VERSION 5.8 ;
BUSBITCHARS "[]" ;
DIVIDERCHAR "/" ;
UNITS
    DATABASE MICRONS 1000 ;
END UNITS

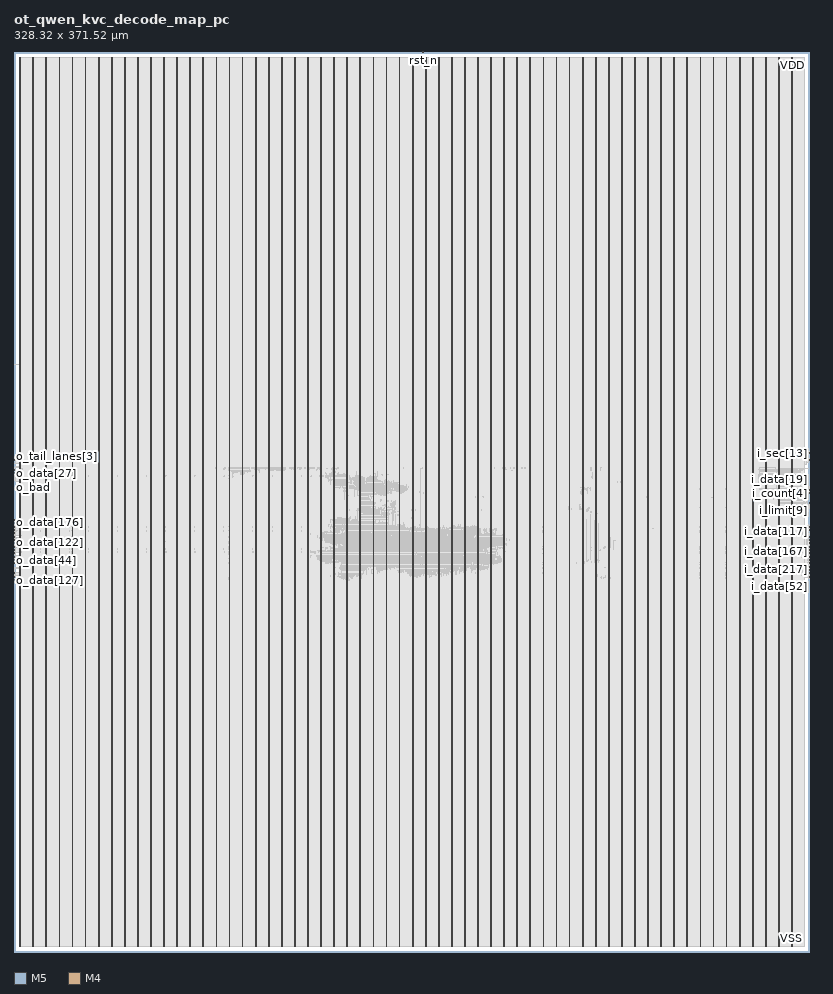
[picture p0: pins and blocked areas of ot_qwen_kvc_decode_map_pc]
MACRO ot_qwen_kvc_decode_map_pc
  FOREIGN ot_qwen_kvc_decode_map_pc 0 0 ;
  CLASS BLOCK ;
  SIZE 328.32 BY 371.52 ;
  PIN clk
    DIRECTION INPUT ;
    USE SIGNAL ;
    PORT
      LAYER M5 ;
        RECT  168.72 371.436 168.744 371.52 ;
    END
  END clk
  PIN fault
    DIRECTION OUTPUT ;
    USE SIGNAL ;
    PORT
      LAYER M5 ;
        RECT  168.816 371.436 168.84 371.52 ;
    END
  END fault
  PIN i_active
    DIRECTION INPUT ;
    USE SIGNAL ;
    PORT
      LAYER M4 ;
        RECT  328.236 188.88 328.32 188.904 ;
    END
  END i_active
  PIN i_count[0]
    DIRECTION INPUT ;
    USE SIGNAL ;
    PORT
      LAYER M4 ;
        RECT  328.236 188.976 328.32 189 ;
    END
  END i_count[0]
  PIN i_count[10]
    DIRECTION INPUT ;
    USE SIGNAL ;
    PORT
      LAYER M4 ;
        RECT  328.236 189.936 328.32 189.96 ;
    END
  END i_count[10]
  PIN i_count[1]
    DIRECTION INPUT ;
    USE SIGNAL ;
    PORT
      LAYER M4 ;
        RECT  328.236 189.072 328.32 189.096 ;
    END
  END i_count[1]
  PIN i_count[2]
    DIRECTION INPUT ;
    USE SIGNAL ;
    PORT
      LAYER M4 ;
        RECT  328.236 189.168 328.32 189.192 ;
    END
  END i_count[2]
  PIN i_count[3]
    DIRECTION INPUT ;
    USE SIGNAL ;
    PORT
      LAYER M4 ;
        RECT  328.236 189.264 328.32 189.288 ;
    END
  END i_count[3]
  PIN i_count[4]
    DIRECTION INPUT ;
    USE SIGNAL ;
    PORT
      LAYER M4 ;
        RECT  328.236 189.36 328.32 189.384 ;
    END
  END i_count[4]
  PIN i_count[5]
    DIRECTION INPUT ;
    USE SIGNAL ;
    PORT
      LAYER M4 ;
        RECT  328.236 189.456 328.32 189.48 ;
    END
  END i_count[5]
  PIN i_count[6]
    DIRECTION INPUT ;
    USE SIGNAL ;
    PORT
      LAYER M4 ;
        RECT  328.236 189.552 328.32 189.576 ;
    END
  END i_count[6]
  PIN i_count[7]
    DIRECTION INPUT ;
    USE SIGNAL ;
    PORT
      LAYER M4 ;
        RECT  328.236 189.648 328.32 189.672 ;
    END
  END i_count[7]
  PIN i_count[8]
    DIRECTION INPUT ;
    USE SIGNAL ;
    PORT
      LAYER M4 ;
        RECT  328.236 189.744 328.32 189.768 ;
    END
  END i_count[8]
  PIN i_count[9]
    DIRECTION INPUT ;
    USE SIGNAL ;
    PORT
      LAYER M4 ;
        RECT  328.236 189.84 328.32 189.864 ;
    END
  END i_count[9]
  PIN i_cr
    DIRECTION OUTPUT ;
    USE SIGNAL ;
    PORT
      LAYER M5 ;
        RECT  168.912 371.436 168.936 371.52 ;
    END
  END i_cr
  PIN i_data[0]
    DIRECTION INPUT ;
    USE SIGNAL ;
    PORT
      LAYER M4 ;
        RECT  328.236 190.032 328.32 190.056 ;
    END
  END i_data[0]
  PIN i_data[100]
    DIRECTION INPUT ;
    USE SIGNAL ;
    PORT
      LAYER M4 ;
        RECT  328.236 171.216 328.32 171.24 ;
    END
  END i_data[100]
  PIN i_data[101]
    DIRECTION INPUT ;
    USE SIGNAL ;
    PORT
      LAYER M4 ;
        RECT  328.236 171.312 328.32 171.336 ;
    END
  END i_data[101]
  PIN i_data[102]
    DIRECTION INPUT ;
    USE SIGNAL ;
    PORT
      LAYER M4 ;
        RECT  328.236 171.408 328.32 171.432 ;
    END
  END i_data[102]
  PIN i_data[103]
    DIRECTION INPUT ;
    USE SIGNAL ;
    PORT
      LAYER M4 ;
        RECT  328.236 171.504 328.32 171.528 ;
    END
  END i_data[103]
  PIN i_data[104]
    DIRECTION INPUT ;
    USE SIGNAL ;
    PORT
      LAYER M4 ;
        RECT  328.236 171.6 328.32 171.624 ;
    END
  END i_data[104]
  PIN i_data[105]
    DIRECTION INPUT ;
    USE SIGNAL ;
    PORT
      LAYER M4 ;
        RECT  328.236 171.696 328.32 171.72 ;
    END
  END i_data[105]
  PIN i_data[106]
    DIRECTION INPUT ;
    USE SIGNAL ;
    PORT
      LAYER M4 ;
        RECT  328.236 171.792 328.32 171.816 ;
    END
  END i_data[106]
  PIN i_data[107]
    DIRECTION INPUT ;
    USE SIGNAL ;
    PORT
      LAYER M4 ;
        RECT  328.236 171.888 328.32 171.912 ;
    END
  END i_data[107]
  PIN i_data[108]
    DIRECTION INPUT ;
    USE SIGNAL ;
    PORT
      LAYER M4 ;
        RECT  328.236 171.984 328.32 172.008 ;
    END
  END i_data[108]
  PIN i_data[109]
    DIRECTION INPUT ;
    USE SIGNAL ;
    PORT
      LAYER M4 ;
        RECT  328.236 172.08 328.32 172.104 ;
    END
  END i_data[109]
  PIN i_data[10]
    DIRECTION INPUT ;
    USE SIGNAL ;
    PORT
      LAYER M4 ;
        RECT  328.236 190.992 328.32 191.016 ;
    END
  END i_data[10]
  PIN i_data[110]
    DIRECTION INPUT ;
    USE SIGNAL ;
    PORT
      LAYER M4 ;
        RECT  328.236 172.176 328.32 172.2 ;
    END
  END i_data[110]
  PIN i_data[111]
    DIRECTION INPUT ;
    USE SIGNAL ;
    PORT
      LAYER M4 ;
        RECT  328.236 172.272 328.32 172.296 ;
    END
  END i_data[111]
  PIN i_data[112]
    DIRECTION INPUT ;
    USE SIGNAL ;
    PORT
      LAYER M4 ;
        RECT  328.236 172.368 328.32 172.392 ;
    END
  END i_data[112]
  PIN i_data[113]
    DIRECTION INPUT ;
    USE SIGNAL ;
    PORT
      LAYER M4 ;
        RECT  328.236 172.464 328.32 172.488 ;
    END
  END i_data[113]
  PIN i_data[114]
    DIRECTION INPUT ;
    USE SIGNAL ;
    PORT
      LAYER M4 ;
        RECT  328.236 172.56 328.32 172.584 ;
    END
  END i_data[114]
  PIN i_data[115]
    DIRECTION INPUT ;
    USE SIGNAL ;
    PORT
      LAYER M4 ;
        RECT  328.236 172.656 328.32 172.68 ;
    END
  END i_data[115]
  PIN i_data[116]
    DIRECTION INPUT ;
    USE SIGNAL ;
    PORT
      LAYER M4 ;
        RECT  328.236 173.52 328.32 173.544 ;
    END
  END i_data[116]
  PIN i_data[117]
    DIRECTION INPUT ;
    USE SIGNAL ;
    PORT
      LAYER M4 ;
        RECT  328.236 173.616 328.32 173.64 ;
    END
  END i_data[117]
  PIN i_data[118]
    DIRECTION INPUT ;
    USE SIGNAL ;
    PORT
      LAYER M4 ;
        RECT  328.236 173.712 328.32 173.736 ;
    END
  END i_data[118]
  PIN i_data[119]
    DIRECTION INPUT ;
    USE SIGNAL ;
    PORT
      LAYER M4 ;
        RECT  328.236 173.808 328.32 173.832 ;
    END
  END i_data[119]
  PIN i_data[11]
    DIRECTION INPUT ;
    USE SIGNAL ;
    PORT
      LAYER M4 ;
        RECT  328.236 191.088 328.32 191.112 ;
    END
  END i_data[11]
  PIN i_data[120]
    DIRECTION INPUT ;
    USE SIGNAL ;
    PORT
      LAYER M4 ;
        RECT  328.236 173.904 328.32 173.928 ;
    END
  END i_data[120]
  PIN i_data[121]
    DIRECTION INPUT ;
    USE SIGNAL ;
    PORT
      LAYER M4 ;
        RECT  328.236 174 328.32 174.024 ;
    END
  END i_data[121]
  PIN i_data[122]
    DIRECTION INPUT ;
    USE SIGNAL ;
    PORT
      LAYER M4 ;
        RECT  328.236 174.096 328.32 174.12 ;
    END
  END i_data[122]
  PIN i_data[123]
    DIRECTION INPUT ;
    USE SIGNAL ;
    PORT
      LAYER M4 ;
        RECT  328.236 174.192 328.32 174.216 ;
    END
  END i_data[123]
  PIN i_data[124]
    DIRECTION INPUT ;
    USE SIGNAL ;
    PORT
      LAYER M4 ;
        RECT  328.236 174.288 328.32 174.312 ;
    END
  END i_data[124]
  PIN i_data[125]
    DIRECTION INPUT ;
    USE SIGNAL ;
    PORT
      LAYER M4 ;
        RECT  328.236 174.384 328.32 174.408 ;
    END
  END i_data[125]
  PIN i_data[126]
    DIRECTION INPUT ;
    USE SIGNAL ;
    PORT
      LAYER M4 ;
        RECT  328.236 174.48 328.32 174.504 ;
    END
  END i_data[126]
  PIN i_data[127]
    DIRECTION INPUT ;
    USE SIGNAL ;
    PORT
      LAYER M4 ;
        RECT  328.236 174.576 328.32 174.6 ;
    END
  END i_data[127]
  PIN i_data[128]
    DIRECTION INPUT ;
    USE SIGNAL ;
    PORT
      LAYER M4 ;
        RECT  328.236 174.672 328.32 174.696 ;
    END
  END i_data[128]
  PIN i_data[129]
    DIRECTION INPUT ;
    USE SIGNAL ;
    PORT
      LAYER M4 ;
        RECT  328.236 174.768 328.32 174.792 ;
    END
  END i_data[129]
  PIN i_data[12]
    DIRECTION INPUT ;
    USE SIGNAL ;
    PORT
      LAYER M4 ;
        RECT  328.236 191.184 328.32 191.208 ;
    END
  END i_data[12]
  PIN i_data[130]
    DIRECTION INPUT ;
    USE SIGNAL ;
    PORT
      LAYER M4 ;
        RECT  328.236 174.864 328.32 174.888 ;
    END
  END i_data[130]
  PIN i_data[131]
    DIRECTION INPUT ;
    USE SIGNAL ;
    PORT
      LAYER M4 ;
        RECT  328.236 174.96 328.32 174.984 ;
    END
  END i_data[131]
  PIN i_data[132]
    DIRECTION INPUT ;
    USE SIGNAL ;
    PORT
      LAYER M4 ;
        RECT  328.236 175.056 328.32 175.08 ;
    END
  END i_data[132]
  PIN i_data[133]
    DIRECTION INPUT ;
    USE SIGNAL ;
    PORT
      LAYER M4 ;
        RECT  328.236 175.152 328.32 175.176 ;
    END
  END i_data[133]
  PIN i_data[134]
    DIRECTION INPUT ;
    USE SIGNAL ;
    PORT
      LAYER M4 ;
        RECT  328.236 175.248 328.32 175.272 ;
    END
  END i_data[134]
  PIN i_data[135]
    DIRECTION INPUT ;
    USE SIGNAL ;
    PORT
      LAYER M4 ;
        RECT  328.236 175.344 328.32 175.368 ;
    END
  END i_data[135]
  PIN i_data[136]
    DIRECTION INPUT ;
    USE SIGNAL ;
    PORT
      LAYER M4 ;
        RECT  328.236 175.44 328.32 175.464 ;
    END
  END i_data[136]
  PIN i_data[137]
    DIRECTION INPUT ;
    USE SIGNAL ;
    PORT
      LAYER M4 ;
        RECT  328.236 175.536 328.32 175.56 ;
    END
  END i_data[137]
  PIN i_data[138]
    DIRECTION INPUT ;
    USE SIGNAL ;
    PORT
      LAYER M4 ;
        RECT  328.236 175.632 328.32 175.656 ;
    END
  END i_data[138]
  PIN i_data[139]
    DIRECTION INPUT ;
    USE SIGNAL ;
    PORT
      LAYER M4 ;
        RECT  328.236 175.728 328.32 175.752 ;
    END
  END i_data[139]
  PIN i_data[13]
    DIRECTION INPUT ;
    USE SIGNAL ;
    PORT
      LAYER M4 ;
        RECT  328.236 191.28 328.32 191.304 ;
    END
  END i_data[13]
  PIN i_data[140]
    DIRECTION INPUT ;
    USE SIGNAL ;
    PORT
      LAYER M4 ;
        RECT  328.236 175.824 328.32 175.848 ;
    END
  END i_data[140]
  PIN i_data[141]
    DIRECTION INPUT ;
    USE SIGNAL ;
    PORT
      LAYER M4 ;
        RECT  328.236 175.92 328.32 175.944 ;
    END
  END i_data[141]
  PIN i_data[142]
    DIRECTION INPUT ;
    USE SIGNAL ;
    PORT
      LAYER M4 ;
        RECT  328.236 176.016 328.32 176.04 ;
    END
  END i_data[142]
  PIN i_data[143]
    DIRECTION INPUT ;
    USE SIGNAL ;
    PORT
      LAYER M4 ;
        RECT  328.236 176.112 328.32 176.136 ;
    END
  END i_data[143]
  PIN i_data[144]
    DIRECTION INPUT ;
    USE SIGNAL ;
    PORT
      LAYER M4 ;
        RECT  328.236 176.208 328.32 176.232 ;
    END
  END i_data[144]
  PIN i_data[145]
    DIRECTION INPUT ;
    USE SIGNAL ;
    PORT
      LAYER M4 ;
        RECT  328.236 176.304 328.32 176.328 ;
    END
  END i_data[145]
  PIN i_data[146]
    DIRECTION INPUT ;
    USE SIGNAL ;
    PORT
      LAYER M4 ;
        RECT  328.236 176.4 328.32 176.424 ;
    END
  END i_data[146]
  PIN i_data[147]
    DIRECTION INPUT ;
    USE SIGNAL ;
    PORT
      LAYER M4 ;
        RECT  328.236 176.496 328.32 176.52 ;
    END
  END i_data[147]
  PIN i_data[148]
    DIRECTION INPUT ;
    USE SIGNAL ;
    PORT
      LAYER M4 ;
        RECT  328.236 163.536 328.32 163.56 ;
    END
  END i_data[148]
  PIN i_data[149]
    DIRECTION INPUT ;
    USE SIGNAL ;
    PORT
      LAYER M4 ;
        RECT  328.236 163.632 328.32 163.656 ;
    END
  END i_data[149]
  PIN i_data[14]
    DIRECTION INPUT ;
    USE SIGNAL ;
    PORT
      LAYER M4 ;
        RECT  328.236 191.376 328.32 191.4 ;
    END
  END i_data[14]
  PIN i_data[150]
    DIRECTION INPUT ;
    USE SIGNAL ;
    PORT
      LAYER M4 ;
        RECT  328.236 163.728 328.32 163.752 ;
    END
  END i_data[150]
  PIN i_data[151]
    DIRECTION INPUT ;
    USE SIGNAL ;
    PORT
      LAYER M4 ;
        RECT  328.236 163.824 328.32 163.848 ;
    END
  END i_data[151]
  PIN i_data[152]
    DIRECTION INPUT ;
    USE SIGNAL ;
    PORT
      LAYER M4 ;
        RECT  328.236 163.92 328.32 163.944 ;
    END
  END i_data[152]
  PIN i_data[153]
    DIRECTION INPUT ;
    USE SIGNAL ;
    PORT
      LAYER M4 ;
        RECT  328.236 164.016 328.32 164.04 ;
    END
  END i_data[153]
  PIN i_data[154]
    DIRECTION INPUT ;
    USE SIGNAL ;
    PORT
      LAYER M4 ;
        RECT  328.236 164.112 328.32 164.136 ;
    END
  END i_data[154]
  PIN i_data[155]
    DIRECTION INPUT ;
    USE SIGNAL ;
    PORT
      LAYER M4 ;
        RECT  328.236 164.208 328.32 164.232 ;
    END
  END i_data[155]
  PIN i_data[156]
    DIRECTION INPUT ;
    USE SIGNAL ;
    PORT
      LAYER M4 ;
        RECT  328.236 164.304 328.32 164.328 ;
    END
  END i_data[156]
  PIN i_data[157]
    DIRECTION INPUT ;
    USE SIGNAL ;
    PORT
      LAYER M4 ;
        RECT  328.236 164.4 328.32 164.424 ;
    END
  END i_data[157]
  PIN i_data[158]
    DIRECTION INPUT ;
    USE SIGNAL ;
    PORT
      LAYER M4 ;
        RECT  328.236 164.496 328.32 164.52 ;
    END
  END i_data[158]
  PIN i_data[159]
    DIRECTION INPUT ;
    USE SIGNAL ;
    PORT
      LAYER M4 ;
        RECT  328.236 164.592 328.32 164.616 ;
    END
  END i_data[159]
  PIN i_data[15]
    DIRECTION INPUT ;
    USE SIGNAL ;
    PORT
      LAYER M4 ;
        RECT  328.236 191.472 328.32 191.496 ;
    END
  END i_data[15]
  PIN i_data[160]
    DIRECTION INPUT ;
    USE SIGNAL ;
    PORT
      LAYER M4 ;
        RECT  328.236 164.688 328.32 164.712 ;
    END
  END i_data[160]
  PIN i_data[161]
    DIRECTION INPUT ;
    USE SIGNAL ;
    PORT
      LAYER M4 ;
        RECT  328.236 164.784 328.32 164.808 ;
    END
  END i_data[161]
  PIN i_data[162]
    DIRECTION INPUT ;
    USE SIGNAL ;
    PORT
      LAYER M4 ;
        RECT  328.236 164.88 328.32 164.904 ;
    END
  END i_data[162]
  PIN i_data[163]
    DIRECTION INPUT ;
    USE SIGNAL ;
    PORT
      LAYER M4 ;
        RECT  328.236 164.976 328.32 165 ;
    END
  END i_data[163]
  PIN i_data[164]
    DIRECTION INPUT ;
    USE SIGNAL ;
    PORT
      LAYER M4 ;
        RECT  328.236 165.072 328.32 165.096 ;
    END
  END i_data[164]
  PIN i_data[165]
    DIRECTION INPUT ;
    USE SIGNAL ;
    PORT
      LAYER M4 ;
        RECT  328.236 165.168 328.32 165.192 ;
    END
  END i_data[165]
  PIN i_data[166]
    DIRECTION INPUT ;
    USE SIGNAL ;
    PORT
      LAYER M4 ;
        RECT  328.236 165.264 328.32 165.288 ;
    END
  END i_data[166]
  PIN i_data[167]
    DIRECTION INPUT ;
    USE SIGNAL ;
    PORT
      LAYER M4 ;
        RECT  328.236 165.36 328.32 165.384 ;
    END
  END i_data[167]
  PIN i_data[168]
    DIRECTION INPUT ;
    USE SIGNAL ;
    PORT
      LAYER M4 ;
        RECT  328.236 165.456 328.32 165.48 ;
    END
  END i_data[168]
  PIN i_data[169]
    DIRECTION INPUT ;
    USE SIGNAL ;
    PORT
      LAYER M4 ;
        RECT  328.236 165.552 328.32 165.576 ;
    END
  END i_data[169]
  PIN i_data[16]
    DIRECTION INPUT ;
    USE SIGNAL ;
    PORT
      LAYER M4 ;
        RECT  328.236 191.568 328.32 191.592 ;
    END
  END i_data[16]
  PIN i_data[170]
    DIRECTION INPUT ;
    USE SIGNAL ;
    PORT
      LAYER M4 ;
        RECT  328.236 165.648 328.32 165.672 ;
    END
  END i_data[170]
  PIN i_data[171]
    DIRECTION INPUT ;
    USE SIGNAL ;
    PORT
      LAYER M4 ;
        RECT  328.236 165.744 328.32 165.768 ;
    END
  END i_data[171]
  PIN i_data[172]
    DIRECTION INPUT ;
    USE SIGNAL ;
    PORT
      LAYER M4 ;
        RECT  328.236 165.84 328.32 165.864 ;
    END
  END i_data[172]
  PIN i_data[173]
    DIRECTION INPUT ;
    USE SIGNAL ;
    PORT
      LAYER M4 ;
        RECT  328.236 165.936 328.32 165.96 ;
    END
  END i_data[173]
  PIN i_data[174]
    DIRECTION INPUT ;
    USE SIGNAL ;
    PORT
      LAYER M4 ;
        RECT  328.236 166.032 328.32 166.056 ;
    END
  END i_data[174]
  PIN i_data[175]
    DIRECTION INPUT ;
    USE SIGNAL ;
    PORT
      LAYER M4 ;
        RECT  328.236 166.128 328.32 166.152 ;
    END
  END i_data[175]
  PIN i_data[176]
    DIRECTION INPUT ;
    USE SIGNAL ;
    PORT
      LAYER M4 ;
        RECT  328.236 166.224 328.32 166.248 ;
    END
  END i_data[176]
  PIN i_data[177]
    DIRECTION INPUT ;
    USE SIGNAL ;
    PORT
      LAYER M4 ;
        RECT  328.236 166.32 328.32 166.344 ;
    END
  END i_data[177]
  PIN i_data[178]
    DIRECTION INPUT ;
    USE SIGNAL ;
    PORT
      LAYER M4 ;
        RECT  328.236 166.416 328.32 166.44 ;
    END
  END i_data[178]
  PIN i_data[179]
    DIRECTION INPUT ;
    USE SIGNAL ;
    PORT
      LAYER M4 ;
        RECT  328.236 166.512 328.32 166.536 ;
    END
  END i_data[179]
  PIN i_data[17]
    DIRECTION INPUT ;
    USE SIGNAL ;
    PORT
      LAYER M4 ;
        RECT  328.236 191.664 328.32 191.688 ;
    END
  END i_data[17]
  PIN i_data[180]
    DIRECTION INPUT ;
    USE SIGNAL ;
    PORT
      LAYER M4 ;
        RECT  328.236 166.608 328.32 166.632 ;
    END
  END i_data[180]
  PIN i_data[181]
    DIRECTION INPUT ;
    USE SIGNAL ;
    PORT
      LAYER M4 ;
        RECT  328.236 166.704 328.32 166.728 ;
    END
  END i_data[181]
  PIN i_data[182]
    DIRECTION INPUT ;
    USE SIGNAL ;
    PORT
      LAYER M4 ;
        RECT  328.236 166.8 328.32 166.824 ;
    END
  END i_data[182]
  PIN i_data[183]
    DIRECTION INPUT ;
    USE SIGNAL ;
    PORT
      LAYER M4 ;
        RECT  328.236 166.896 328.32 166.92 ;
    END
  END i_data[183]
  PIN i_data[184]
    DIRECTION INPUT ;
    USE SIGNAL ;
    PORT
      LAYER M4 ;
        RECT  328.236 166.992 328.32 167.016 ;
    END
  END i_data[184]
  PIN i_data[185]
    DIRECTION INPUT ;
    USE SIGNAL ;
    PORT
      LAYER M4 ;
        RECT  328.236 167.088 328.32 167.112 ;
    END
  END i_data[185]
  PIN i_data[186]
    DIRECTION INPUT ;
    USE SIGNAL ;
    PORT
      LAYER M4 ;
        RECT  328.236 167.184 328.32 167.208 ;
    END
  END i_data[186]
  PIN i_data[187]
    DIRECTION INPUT ;
    USE SIGNAL ;
    PORT
      LAYER M4 ;
        RECT  328.236 167.28 328.32 167.304 ;
    END
  END i_data[187]
  PIN i_data[188]
    DIRECTION INPUT ;
    USE SIGNAL ;
    PORT
      LAYER M4 ;
        RECT  328.236 167.376 328.32 167.4 ;
    END
  END i_data[188]
  PIN i_data[189]
    DIRECTION INPUT ;
    USE SIGNAL ;
    PORT
      LAYER M4 ;
        RECT  328.236 167.472 328.32 167.496 ;
    END
  END i_data[189]
  PIN i_data[18]
    DIRECTION INPUT ;
    USE SIGNAL ;
    PORT
      LAYER M4 ;
        RECT  328.236 191.76 328.32 191.784 ;
    END
  END i_data[18]
  PIN i_data[190]
    DIRECTION INPUT ;
    USE SIGNAL ;
    PORT
      LAYER M4 ;
        RECT  328.236 167.568 328.32 167.592 ;
    END
  END i_data[190]
  PIN i_data[191]
    DIRECTION INPUT ;
    USE SIGNAL ;
    PORT
      LAYER M4 ;
        RECT  328.236 167.664 328.32 167.688 ;
    END
  END i_data[191]
  PIN i_data[192]
    DIRECTION INPUT ;
    USE SIGNAL ;
    PORT
      LAYER M4 ;
        RECT  328.236 167.76 328.32 167.784 ;
    END
  END i_data[192]
  PIN i_data[193]
    DIRECTION INPUT ;
    USE SIGNAL ;
    PORT
      LAYER M4 ;
        RECT  328.236 167.856 328.32 167.88 ;
    END
  END i_data[193]
  PIN i_data[194]
    DIRECTION INPUT ;
    USE SIGNAL ;
    PORT
      LAYER M4 ;
        RECT  328.236 167.952 328.32 167.976 ;
    END
  END i_data[194]
  PIN i_data[195]
    DIRECTION INPUT ;
    USE SIGNAL ;
    PORT
      LAYER M4 ;
        RECT  328.236 168.048 328.32 168.072 ;
    END
  END i_data[195]
  PIN i_data[196]
    DIRECTION INPUT ;
    USE SIGNAL ;
    PORT
      LAYER M4 ;
        RECT  328.236 168.144 328.32 168.168 ;
    END
  END i_data[196]
  PIN i_data[197]
    DIRECTION INPUT ;
    USE SIGNAL ;
    PORT
      LAYER M4 ;
        RECT  328.236 168.24 328.32 168.264 ;
    END
  END i_data[197]
  PIN i_data[198]
    DIRECTION INPUT ;
    USE SIGNAL ;
    PORT
      LAYER M4 ;
        RECT  328.236 168.336 328.32 168.36 ;
    END
  END i_data[198]
  PIN i_data[199]
    DIRECTION INPUT ;
    USE SIGNAL ;
    PORT
      LAYER M4 ;
        RECT  328.236 168.432 328.32 168.456 ;
    END
  END i_data[199]
  PIN i_data[19]
    DIRECTION INPUT ;
    USE SIGNAL ;
    PORT
      LAYER M4 ;
        RECT  328.236 191.856 328.32 191.88 ;
    END
  END i_data[19]
  PIN i_data[1]
    DIRECTION INPUT ;
    USE SIGNAL ;
    PORT
      LAYER M4 ;
        RECT  328.236 190.128 328.32 190.152 ;
    END
  END i_data[1]
  PIN i_data[200]
    DIRECTION INPUT ;
    USE SIGNAL ;
    PORT
      LAYER M4 ;
        RECT  328.236 168.528 328.32 168.552 ;
    END
  END i_data[200]
  PIN i_data[201]
    DIRECTION INPUT ;
    USE SIGNAL ;
    PORT
      LAYER M4 ;
        RECT  328.236 168.624 328.32 168.648 ;
    END
  END i_data[201]
  PIN i_data[202]
    DIRECTION INPUT ;
    USE SIGNAL ;
    PORT
      LAYER M4 ;
        RECT  328.236 168.72 328.32 168.744 ;
    END
  END i_data[202]
  PIN i_data[203]
    DIRECTION INPUT ;
    USE SIGNAL ;
    PORT
      LAYER M4 ;
        RECT  328.236 168.816 328.32 168.84 ;
    END
  END i_data[203]
  PIN i_data[204]
    DIRECTION INPUT ;
    USE SIGNAL ;
    PORT
      LAYER M4 ;
        RECT  328.236 168.912 328.32 168.936 ;
    END
  END i_data[204]
  PIN i_data[205]
    DIRECTION INPUT ;
    USE SIGNAL ;
    PORT
      LAYER M4 ;
        RECT  328.236 169.008 328.32 169.032 ;
    END
  END i_data[205]
  PIN i_data[206]
    DIRECTION INPUT ;
    USE SIGNAL ;
    PORT
      LAYER M4 ;
        RECT  328.236 169.104 328.32 169.128 ;
    END
  END i_data[206]
  PIN i_data[207]
    DIRECTION INPUT ;
    USE SIGNAL ;
    PORT
      LAYER M4 ;
        RECT  328.236 169.2 328.32 169.224 ;
    END
  END i_data[207]
  PIN i_data[208]
    DIRECTION INPUT ;
    USE SIGNAL ;
    PORT
      LAYER M4 ;
        RECT  328.236 169.296 328.32 169.32 ;
    END
  END i_data[208]
  PIN i_data[209]
    DIRECTION INPUT ;
    USE SIGNAL ;
    PORT
      LAYER M4 ;
        RECT  328.236 169.392 328.32 169.416 ;
    END
  END i_data[209]
  PIN i_data[20]
    DIRECTION INPUT ;
    USE SIGNAL ;
    PORT
      LAYER M4 ;
        RECT  328.236 160.464 328.32 160.488 ;
    END
  END i_data[20]
  PIN i_data[210]
    DIRECTION INPUT ;
    USE SIGNAL ;
    PORT
      LAYER M4 ;
        RECT  328.236 169.488 328.32 169.512 ;
    END
  END i_data[210]
  PIN i_data[211]
    DIRECTION INPUT ;
    USE SIGNAL ;
    PORT
      LAYER M4 ;
        RECT  328.236 169.584 328.32 169.608 ;
    END
  END i_data[211]
  PIN i_data[212]
    DIRECTION INPUT ;
    USE SIGNAL ;
    PORT
      LAYER M4 ;
        RECT  328.236 157.392 328.32 157.416 ;
    END
  END i_data[212]
  PIN i_data[213]
    DIRECTION INPUT ;
    USE SIGNAL ;
    PORT
      LAYER M4 ;
        RECT  328.236 157.488 328.32 157.512 ;
    END
  END i_data[213]
  PIN i_data[214]
    DIRECTION INPUT ;
    USE SIGNAL ;
    PORT
      LAYER M4 ;
        RECT  328.236 157.584 328.32 157.608 ;
    END
  END i_data[214]
  PIN i_data[215]
    DIRECTION INPUT ;
    USE SIGNAL ;
    PORT
      LAYER M4 ;
        RECT  328.236 157.68 328.32 157.704 ;
    END
  END i_data[215]
  PIN i_data[216]
    DIRECTION INPUT ;
    USE SIGNAL ;
    PORT
      LAYER M4 ;
        RECT  328.236 157.776 328.32 157.8 ;
    END
  END i_data[216]
  PIN i_data[217]
    DIRECTION INPUT ;
    USE SIGNAL ;
    PORT
      LAYER M4 ;
        RECT  328.236 157.872 328.32 157.896 ;
    END
  END i_data[217]
  PIN i_data[218]
    DIRECTION INPUT ;
    USE SIGNAL ;
    PORT
      LAYER M4 ;
        RECT  328.236 157.968 328.32 157.992 ;
    END
  END i_data[218]
  PIN i_data[219]
    DIRECTION INPUT ;
    USE SIGNAL ;
    PORT
      LAYER M4 ;
        RECT  328.236 158.064 328.32 158.088 ;
    END
  END i_data[219]
  PIN i_data[21]
    DIRECTION INPUT ;
    USE SIGNAL ;
    PORT
      LAYER M4 ;
        RECT  328.236 160.56 328.32 160.584 ;
    END
  END i_data[21]
  PIN i_data[220]
    DIRECTION INPUT ;
    USE SIGNAL ;
    PORT
      LAYER M4 ;
        RECT  328.236 158.16 328.32 158.184 ;
    END
  END i_data[220]
  PIN i_data[221]
    DIRECTION INPUT ;
    USE SIGNAL ;
    PORT
      LAYER M4 ;
        RECT  328.236 158.256 328.32 158.28 ;
    END
  END i_data[221]
  PIN i_data[222]
    DIRECTION INPUT ;
    USE SIGNAL ;
    PORT
      LAYER M4 ;
        RECT  328.236 158.352 328.32 158.376 ;
    END
  END i_data[222]
  PIN i_data[223]
    DIRECTION INPUT ;
    USE SIGNAL ;
    PORT
      LAYER M4 ;
        RECT  328.236 158.448 328.32 158.472 ;
    END
  END i_data[223]
  PIN i_data[224]
    DIRECTION INPUT ;
    USE SIGNAL ;
    PORT
      LAYER M4 ;
        RECT  328.236 158.544 328.32 158.568 ;
    END
  END i_data[224]
  PIN i_data[225]
    DIRECTION INPUT ;
    USE SIGNAL ;
    PORT
      LAYER M4 ;
        RECT  328.236 158.64 328.32 158.664 ;
    END
  END i_data[225]
  PIN i_data[226]
    DIRECTION INPUT ;
    USE SIGNAL ;
    PORT
      LAYER M4 ;
        RECT  328.236 158.736 328.32 158.76 ;
    END
  END i_data[226]
  PIN i_data[227]
    DIRECTION INPUT ;
    USE SIGNAL ;
    PORT
      LAYER M4 ;
        RECT  328.236 158.832 328.32 158.856 ;
    END
  END i_data[227]
  PIN i_data[228]
    DIRECTION INPUT ;
    USE SIGNAL ;
    PORT
      LAYER M4 ;
        RECT  328.236 158.928 328.32 158.952 ;
    END
  END i_data[228]
  PIN i_data[229]
    DIRECTION INPUT ;
    USE SIGNAL ;
    PORT
      LAYER M4 ;
        RECT  328.236 159.024 328.32 159.048 ;
    END
  END i_data[229]
  PIN i_data[22]
    DIRECTION INPUT ;
    USE SIGNAL ;
    PORT
      LAYER M4 ;
        RECT  328.236 160.656 328.32 160.68 ;
    END
  END i_data[22]
  PIN i_data[230]
    DIRECTION INPUT ;
    USE SIGNAL ;
    PORT
      LAYER M4 ;
        RECT  328.236 159.12 328.32 159.144 ;
    END
  END i_data[230]
  PIN i_data[231]
    DIRECTION INPUT ;
    USE SIGNAL ;
    PORT
      LAYER M4 ;
        RECT  328.236 159.216 328.32 159.24 ;
    END
  END i_data[231]
  PIN i_data[232]
    DIRECTION INPUT ;
    USE SIGNAL ;
    PORT
      LAYER M4 ;
        RECT  328.236 159.312 328.32 159.336 ;
    END
  END i_data[232]
  PIN i_data[233]
    DIRECTION INPUT ;
    USE SIGNAL ;
    PORT
      LAYER M4 ;
        RECT  328.236 159.408 328.32 159.432 ;
    END
  END i_data[233]
  PIN i_data[234]
    DIRECTION INPUT ;
    USE SIGNAL ;
    PORT
      LAYER M4 ;
        RECT  328.236 159.504 328.32 159.528 ;
    END
  END i_data[234]
  PIN i_data[235]
    DIRECTION INPUT ;
    USE SIGNAL ;
    PORT
      LAYER M4 ;
        RECT  328.236 159.6 328.32 159.624 ;
    END
  END i_data[235]
  PIN i_data[236]
    DIRECTION INPUT ;
    USE SIGNAL ;
    PORT
      LAYER M4 ;
        RECT  328.236 159.696 328.32 159.72 ;
    END
  END i_data[236]
  PIN i_data[237]
    DIRECTION INPUT ;
    USE SIGNAL ;
    PORT
      LAYER M4 ;
        RECT  328.236 159.792 328.32 159.816 ;
    END
  END i_data[237]
  PIN i_data[238]
    DIRECTION INPUT ;
    USE SIGNAL ;
    PORT
      LAYER M4 ;
        RECT  328.236 159.888 328.32 159.912 ;
    END
  END i_data[238]
  PIN i_data[239]
    DIRECTION INPUT ;
    USE SIGNAL ;
    PORT
      LAYER M4 ;
        RECT  328.236 159.984 328.32 160.008 ;
    END
  END i_data[239]
  PIN i_data[23]
    DIRECTION INPUT ;
    USE SIGNAL ;
    PORT
      LAYER M4 ;
        RECT  328.236 160.752 328.32 160.776 ;
    END
  END i_data[23]
  PIN i_data[240]
    DIRECTION INPUT ;
    USE SIGNAL ;
    PORT
      LAYER M4 ;
        RECT  328.236 160.08 328.32 160.104 ;
    END
  END i_data[240]
  PIN i_data[241]
    DIRECTION INPUT ;
    USE SIGNAL ;
    PORT
      LAYER M4 ;
        RECT  328.236 160.176 328.32 160.2 ;
    END
  END i_data[241]
  PIN i_data[242]
    DIRECTION INPUT ;
    USE SIGNAL ;
    PORT
      LAYER M4 ;
        RECT  328.236 160.272 328.32 160.296 ;
    END
  END i_data[242]
  PIN i_data[243]
    DIRECTION INPUT ;
    USE SIGNAL ;
    PORT
      LAYER M4 ;
        RECT  328.236 160.368 328.32 160.392 ;
    END
  END i_data[243]
  PIN i_data[244]
    DIRECTION INPUT ;
    USE SIGNAL ;
    PORT
      LAYER M4 ;
        RECT  328.236 182.736 328.32 182.76 ;
    END
  END i_data[244]
  PIN i_data[245]
    DIRECTION INPUT ;
    USE SIGNAL ;
    PORT
      LAYER M4 ;
        RECT  328.236 182.832 328.32 182.856 ;
    END
  END i_data[245]
  PIN i_data[246]
    DIRECTION INPUT ;
    USE SIGNAL ;
    PORT
      LAYER M4 ;
        RECT  328.236 182.928 328.32 182.952 ;
    END
  END i_data[246]
  PIN i_data[247]
    DIRECTION INPUT ;
    USE SIGNAL ;
    PORT
      LAYER M4 ;
        RECT  328.236 183.024 328.32 183.048 ;
    END
  END i_data[247]
  PIN i_data[248]
    DIRECTION INPUT ;
    USE SIGNAL ;
    PORT
      LAYER M4 ;
        RECT  328.236 183.12 328.32 183.144 ;
    END
  END i_data[248]
  PIN i_data[249]
    DIRECTION INPUT ;
    USE SIGNAL ;
    PORT
      LAYER M4 ;
        RECT  328.236 183.216 328.32 183.24 ;
    END
  END i_data[249]
  PIN i_data[24]
    DIRECTION INPUT ;
    USE SIGNAL ;
    PORT
      LAYER M4 ;
        RECT  328.236 160.848 328.32 160.872 ;
    END
  END i_data[24]
  PIN i_data[250]
    DIRECTION INPUT ;
    USE SIGNAL ;
    PORT
      LAYER M4 ;
        RECT  328.236 183.312 328.32 183.336 ;
    END
  END i_data[250]
  PIN i_data[251]
    DIRECTION INPUT ;
    USE SIGNAL ;
    PORT
      LAYER M4 ;
        RECT  328.236 183.408 328.32 183.432 ;
    END
  END i_data[251]
  PIN i_data[252]
    DIRECTION INPUT ;
    USE SIGNAL ;
    PORT
      LAYER M4 ;
        RECT  328.236 183.504 328.32 183.528 ;
    END
  END i_data[252]
  PIN i_data[253]
    DIRECTION INPUT ;
    USE SIGNAL ;
    PORT
      LAYER M4 ;
        RECT  328.236 183.6 328.32 183.624 ;
    END
  END i_data[253]
  PIN i_data[254]
    DIRECTION INPUT ;
    USE SIGNAL ;
    PORT
      LAYER M4 ;
        RECT  328.236 183.696 328.32 183.72 ;
    END
  END i_data[254]
  PIN i_data[255]
    DIRECTION INPUT ;
    USE SIGNAL ;
    PORT
      LAYER M4 ;
        RECT  328.236 183.792 328.32 183.816 ;
    END
  END i_data[255]
  PIN i_data[25]
    DIRECTION INPUT ;
    USE SIGNAL ;
    PORT
      LAYER M4 ;
        RECT  328.236 160.944 328.32 160.968 ;
    END
  END i_data[25]
  PIN i_data[26]
    DIRECTION INPUT ;
    USE SIGNAL ;
    PORT
      LAYER M4 ;
        RECT  328.236 161.04 328.32 161.064 ;
    END
  END i_data[26]
  PIN i_data[27]
    DIRECTION INPUT ;
    USE SIGNAL ;
    PORT
      LAYER M4 ;
        RECT  328.236 161.136 328.32 161.16 ;
    END
  END i_data[27]
  PIN i_data[28]
    DIRECTION INPUT ;
    USE SIGNAL ;
    PORT
      LAYER M4 ;
        RECT  328.236 161.232 328.32 161.256 ;
    END
  END i_data[28]
  PIN i_data[29]
    DIRECTION INPUT ;
    USE SIGNAL ;
    PORT
      LAYER M4 ;
        RECT  328.236 161.328 328.32 161.352 ;
    END
  END i_data[29]
  PIN i_data[2]
    DIRECTION INPUT ;
    USE SIGNAL ;
    PORT
      LAYER M4 ;
        RECT  328.236 190.224 328.32 190.248 ;
    END
  END i_data[2]
  PIN i_data[30]
    DIRECTION INPUT ;
    USE SIGNAL ;
    PORT
      LAYER M4 ;
        RECT  328.236 161.424 328.32 161.448 ;
    END
  END i_data[30]
  PIN i_data[31]
    DIRECTION INPUT ;
    USE SIGNAL ;
    PORT
      LAYER M4 ;
        RECT  328.236 161.52 328.32 161.544 ;
    END
  END i_data[31]
  PIN i_data[32]
    DIRECTION INPUT ;
    USE SIGNAL ;
    PORT
      LAYER M4 ;
        RECT  328.236 161.616 328.32 161.64 ;
    END
  END i_data[32]
  PIN i_data[33]
    DIRECTION INPUT ;
    USE SIGNAL ;
    PORT
      LAYER M4 ;
        RECT  328.236 161.712 328.32 161.736 ;
    END
  END i_data[33]
  PIN i_data[34]
    DIRECTION INPUT ;
    USE SIGNAL ;
    PORT
      LAYER M4 ;
        RECT  328.236 161.808 328.32 161.832 ;
    END
  END i_data[34]
  PIN i_data[35]
    DIRECTION INPUT ;
    USE SIGNAL ;
    PORT
      LAYER M4 ;
        RECT  328.236 161.904 328.32 161.928 ;
    END
  END i_data[35]
  PIN i_data[36]
    DIRECTION INPUT ;
    USE SIGNAL ;
    PORT
      LAYER M4 ;
        RECT  328.236 162 328.32 162.024 ;
    END
  END i_data[36]
  PIN i_data[37]
    DIRECTION INPUT ;
    USE SIGNAL ;
    PORT
      LAYER M4 ;
        RECT  328.236 162.096 328.32 162.12 ;
    END
  END i_data[37]
  PIN i_data[38]
    DIRECTION INPUT ;
    USE SIGNAL ;
    PORT
      LAYER M4 ;
        RECT  328.236 162.192 328.32 162.216 ;
    END
  END i_data[38]
  PIN i_data[39]
    DIRECTION INPUT ;
    USE SIGNAL ;
    PORT
      LAYER M4 ;
        RECT  328.236 162.288 328.32 162.312 ;
    END
  END i_data[39]
  PIN i_data[3]
    DIRECTION INPUT ;
    USE SIGNAL ;
    PORT
      LAYER M4 ;
        RECT  328.236 190.32 328.32 190.344 ;
    END
  END i_data[3]
  PIN i_data[40]
    DIRECTION INPUT ;
    USE SIGNAL ;
    PORT
      LAYER M4 ;
        RECT  328.236 162.384 328.32 162.408 ;
    END
  END i_data[40]
  PIN i_data[41]
    DIRECTION INPUT ;
    USE SIGNAL ;
    PORT
      LAYER M4 ;
        RECT  328.236 162.48 328.32 162.504 ;
    END
  END i_data[41]
  PIN i_data[42]
    DIRECTION INPUT ;
    USE SIGNAL ;
    PORT
      LAYER M4 ;
        RECT  328.236 162.576 328.32 162.6 ;
    END
  END i_data[42]
  PIN i_data[43]
    DIRECTION INPUT ;
    USE SIGNAL ;
    PORT
      LAYER M4 ;
        RECT  328.236 162.672 328.32 162.696 ;
    END
  END i_data[43]
  PIN i_data[44]
    DIRECTION INPUT ;
    USE SIGNAL ;
    PORT
      LAYER M4 ;
        RECT  328.236 162.768 328.32 162.792 ;
    END
  END i_data[44]
  PIN i_data[45]
    DIRECTION INPUT ;
    USE SIGNAL ;
    PORT
      LAYER M4 ;
        RECT  328.236 162.864 328.32 162.888 ;
    END
  END i_data[45]
  PIN i_data[46]
    DIRECTION INPUT ;
    USE SIGNAL ;
    PORT
      LAYER M4 ;
        RECT  328.236 162.96 328.32 162.984 ;
    END
  END i_data[46]
  PIN i_data[47]
    DIRECTION INPUT ;
    USE SIGNAL ;
    PORT
      LAYER M4 ;
        RECT  328.236 163.056 328.32 163.08 ;
    END
  END i_data[47]
  PIN i_data[48]
    DIRECTION INPUT ;
    USE SIGNAL ;
    PORT
      LAYER M4 ;
        RECT  328.236 163.152 328.32 163.176 ;
    END
  END i_data[48]
  PIN i_data[49]
    DIRECTION INPUT ;
    USE SIGNAL ;
    PORT
      LAYER M4 ;
        RECT  328.236 163.248 328.32 163.272 ;
    END
  END i_data[49]
  PIN i_data[4]
    DIRECTION INPUT ;
    USE SIGNAL ;
    PORT
      LAYER M4 ;
        RECT  328.236 190.416 328.32 190.44 ;
    END
  END i_data[4]
  PIN i_data[50]
    DIRECTION INPUT ;
    USE SIGNAL ;
    PORT
      LAYER M4 ;
        RECT  328.236 163.344 328.32 163.368 ;
    END
  END i_data[50]
  PIN i_data[51]
    DIRECTION INPUT ;
    USE SIGNAL ;
    PORT
      LAYER M4 ;
        RECT  328.236 163.44 328.32 163.464 ;
    END
  END i_data[51]
  PIN i_data[52]
    DIRECTION INPUT ;
    USE SIGNAL ;
    PORT
      LAYER M4 ;
        RECT  328.236 154.32 328.32 154.344 ;
    END
  END i_data[52]
  PIN i_data[53]
    DIRECTION INPUT ;
    USE SIGNAL ;
    PORT
      LAYER M4 ;
        RECT  328.236 154.416 328.32 154.44 ;
    END
  END i_data[53]
  PIN i_data[54]
    DIRECTION INPUT ;
    USE SIGNAL ;
    PORT
      LAYER M4 ;
        RECT  328.236 154.512 328.32 154.536 ;
    END
  END i_data[54]
  PIN i_data[55]
    DIRECTION INPUT ;
    USE SIGNAL ;
    PORT
      LAYER M4 ;
        RECT  328.236 154.608 328.32 154.632 ;
    END
  END i_data[55]
  PIN i_data[56]
    DIRECTION INPUT ;
    USE SIGNAL ;
    PORT
      LAYER M4 ;
        RECT  328.236 154.704 328.32 154.728 ;
    END
  END i_data[56]
  PIN i_data[57]
    DIRECTION INPUT ;
    USE SIGNAL ;
    PORT
      LAYER M4 ;
        RECT  328.236 154.8 328.32 154.824 ;
    END
  END i_data[57]
  PIN i_data[58]
    DIRECTION INPUT ;
    USE SIGNAL ;
    PORT
      LAYER M4 ;
        RECT  328.236 154.896 328.32 154.92 ;
    END
  END i_data[58]
  PIN i_data[59]
    DIRECTION INPUT ;
    USE SIGNAL ;
    PORT
      LAYER M4 ;
        RECT  328.236 154.992 328.32 155.016 ;
    END
  END i_data[59]
  PIN i_data[5]
    DIRECTION INPUT ;
    USE SIGNAL ;
    PORT
      LAYER M4 ;
        RECT  328.236 190.512 328.32 190.536 ;
    END
  END i_data[5]
  PIN i_data[60]
    DIRECTION INPUT ;
    USE SIGNAL ;
    PORT
      LAYER M4 ;
        RECT  328.236 155.088 328.32 155.112 ;
    END
  END i_data[60]
  PIN i_data[61]
    DIRECTION INPUT ;
    USE SIGNAL ;
    PORT
      LAYER M4 ;
        RECT  328.236 155.184 328.32 155.208 ;
    END
  END i_data[61]
  PIN i_data[62]
    DIRECTION INPUT ;
    USE SIGNAL ;
    PORT
      LAYER M4 ;
        RECT  328.236 155.28 328.32 155.304 ;
    END
  END i_data[62]
  PIN i_data[63]
    DIRECTION INPUT ;
    USE SIGNAL ;
    PORT
      LAYER M4 ;
        RECT  328.236 155.376 328.32 155.4 ;
    END
  END i_data[63]
  PIN i_data[64]
    DIRECTION INPUT ;
    USE SIGNAL ;
    PORT
      LAYER M4 ;
        RECT  328.236 155.472 328.32 155.496 ;
    END
  END i_data[64]
  PIN i_data[65]
    DIRECTION INPUT ;
    USE SIGNAL ;
    PORT
      LAYER M4 ;
        RECT  328.236 155.568 328.32 155.592 ;
    END
  END i_data[65]
  PIN i_data[66]
    DIRECTION INPUT ;
    USE SIGNAL ;
    PORT
      LAYER M4 ;
        RECT  328.236 155.664 328.32 155.688 ;
    END
  END i_data[66]
  PIN i_data[67]
    DIRECTION INPUT ;
    USE SIGNAL ;
    PORT
      LAYER M4 ;
        RECT  328.236 155.76 328.32 155.784 ;
    END
  END i_data[67]
  PIN i_data[68]
    DIRECTION INPUT ;
    USE SIGNAL ;
    PORT
      LAYER M4 ;
        RECT  328.236 155.856 328.32 155.88 ;
    END
  END i_data[68]
  PIN i_data[69]
    DIRECTION INPUT ;
    USE SIGNAL ;
    PORT
      LAYER M4 ;
        RECT  328.236 155.952 328.32 155.976 ;
    END
  END i_data[69]
  PIN i_data[6]
    DIRECTION INPUT ;
    USE SIGNAL ;
    PORT
      LAYER M4 ;
        RECT  328.236 190.608 328.32 190.632 ;
    END
  END i_data[6]
  PIN i_data[70]
    DIRECTION INPUT ;
    USE SIGNAL ;
    PORT
      LAYER M4 ;
        RECT  328.236 156.048 328.32 156.072 ;
    END
  END i_data[70]
  PIN i_data[71]
    DIRECTION INPUT ;
    USE SIGNAL ;
    PORT
      LAYER M4 ;
        RECT  328.236 156.144 328.32 156.168 ;
    END
  END i_data[71]
  PIN i_data[72]
    DIRECTION INPUT ;
    USE SIGNAL ;
    PORT
      LAYER M4 ;
        RECT  328.236 156.24 328.32 156.264 ;
    END
  END i_data[72]
  PIN i_data[73]
    DIRECTION INPUT ;
    USE SIGNAL ;
    PORT
      LAYER M4 ;
        RECT  328.236 156.336 328.32 156.36 ;
    END
  END i_data[73]
  PIN i_data[74]
    DIRECTION INPUT ;
    USE SIGNAL ;
    PORT
      LAYER M4 ;
        RECT  328.236 156.432 328.32 156.456 ;
    END
  END i_data[74]
  PIN i_data[75]
    DIRECTION INPUT ;
    USE SIGNAL ;
    PORT
      LAYER M4 ;
        RECT  328.236 156.528 328.32 156.552 ;
    END
  END i_data[75]
  PIN i_data[76]
    DIRECTION INPUT ;
    USE SIGNAL ;
    PORT
      LAYER M4 ;
        RECT  328.236 156.624 328.32 156.648 ;
    END
  END i_data[76]
  PIN i_data[77]
    DIRECTION INPUT ;
    USE SIGNAL ;
    PORT
      LAYER M4 ;
        RECT  328.236 156.72 328.32 156.744 ;
    END
  END i_data[77]
  PIN i_data[78]
    DIRECTION INPUT ;
    USE SIGNAL ;
    PORT
      LAYER M4 ;
        RECT  328.236 156.816 328.32 156.84 ;
    END
  END i_data[78]
  PIN i_data[79]
    DIRECTION INPUT ;
    USE SIGNAL ;
    PORT
      LAYER M4 ;
        RECT  328.236 156.912 328.32 156.936 ;
    END
  END i_data[79]
  PIN i_data[7]
    DIRECTION INPUT ;
    USE SIGNAL ;
    PORT
      LAYER M4 ;
        RECT  328.236 190.704 328.32 190.728 ;
    END
  END i_data[7]
  PIN i_data[80]
    DIRECTION INPUT ;
    USE SIGNAL ;
    PORT
      LAYER M4 ;
        RECT  328.236 157.008 328.32 157.032 ;
    END
  END i_data[80]
  PIN i_data[81]
    DIRECTION INPUT ;
    USE SIGNAL ;
    PORT
      LAYER M4 ;
        RECT  328.236 157.104 328.32 157.128 ;
    END
  END i_data[81]
  PIN i_data[82]
    DIRECTION INPUT ;
    USE SIGNAL ;
    PORT
      LAYER M4 ;
        RECT  328.236 157.2 328.32 157.224 ;
    END
  END i_data[82]
  PIN i_data[83]
    DIRECTION INPUT ;
    USE SIGNAL ;
    PORT
      LAYER M4 ;
        RECT  328.236 157.296 328.32 157.32 ;
    END
  END i_data[83]
  PIN i_data[84]
    DIRECTION INPUT ;
    USE SIGNAL ;
    PORT
      LAYER M4 ;
        RECT  328.236 169.68 328.32 169.704 ;
    END
  END i_data[84]
  PIN i_data[85]
    DIRECTION INPUT ;
    USE SIGNAL ;
    PORT
      LAYER M4 ;
        RECT  328.236 169.776 328.32 169.8 ;
    END
  END i_data[85]
  PIN i_data[86]
    DIRECTION INPUT ;
    USE SIGNAL ;
    PORT
      LAYER M4 ;
        RECT  328.236 169.872 328.32 169.896 ;
    END
  END i_data[86]
  PIN i_data[87]
    DIRECTION INPUT ;
    USE SIGNAL ;
    PORT
      LAYER M4 ;
        RECT  328.236 169.968 328.32 169.992 ;
    END
  END i_data[87]
  PIN i_data[88]
    DIRECTION INPUT ;
    USE SIGNAL ;
    PORT
      LAYER M4 ;
        RECT  328.236 170.064 328.32 170.088 ;
    END
  END i_data[88]
  PIN i_data[89]
    DIRECTION INPUT ;
    USE SIGNAL ;
    PORT
      LAYER M4 ;
        RECT  328.236 170.16 328.32 170.184 ;
    END
  END i_data[89]
  PIN i_data[8]
    DIRECTION INPUT ;
    USE SIGNAL ;
    PORT
      LAYER M4 ;
        RECT  328.236 190.8 328.32 190.824 ;
    END
  END i_data[8]
  PIN i_data[90]
    DIRECTION INPUT ;
    USE SIGNAL ;
    PORT
      LAYER M4 ;
        RECT  328.236 170.256 328.32 170.28 ;
    END
  END i_data[90]
  PIN i_data[91]
    DIRECTION INPUT ;
    USE SIGNAL ;
    PORT
      LAYER M4 ;
        RECT  328.236 170.352 328.32 170.376 ;
    END
  END i_data[91]
  PIN i_data[92]
    DIRECTION INPUT ;
    USE SIGNAL ;
    PORT
      LAYER M4 ;
        RECT  328.236 170.448 328.32 170.472 ;
    END
  END i_data[92]
  PIN i_data[93]
    DIRECTION INPUT ;
    USE SIGNAL ;
    PORT
      LAYER M4 ;
        RECT  328.236 170.544 328.32 170.568 ;
    END
  END i_data[93]
  PIN i_data[94]
    DIRECTION INPUT ;
    USE SIGNAL ;
    PORT
      LAYER M4 ;
        RECT  328.236 170.64 328.32 170.664 ;
    END
  END i_data[94]
  PIN i_data[95]
    DIRECTION INPUT ;
    USE SIGNAL ;
    PORT
      LAYER M4 ;
        RECT  328.236 170.736 328.32 170.76 ;
    END
  END i_data[95]
  PIN i_data[96]
    DIRECTION INPUT ;
    USE SIGNAL ;
    PORT
      LAYER M4 ;
        RECT  328.236 170.832 328.32 170.856 ;
    END
  END i_data[96]
  PIN i_data[97]
    DIRECTION INPUT ;
    USE SIGNAL ;
    PORT
      LAYER M4 ;
        RECT  328.236 170.928 328.32 170.952 ;
    END
  END i_data[97]
  PIN i_data[98]
    DIRECTION INPUT ;
    USE SIGNAL ;
    PORT
      LAYER M4 ;
        RECT  328.236 171.024 328.32 171.048 ;
    END
  END i_data[98]
  PIN i_data[99]
    DIRECTION INPUT ;
    USE SIGNAL ;
    PORT
      LAYER M4 ;
        RECT  328.236 171.12 328.32 171.144 ;
    END
  END i_data[99]
  PIN i_data[9]
    DIRECTION INPUT ;
    USE SIGNAL ;
    PORT
      LAYER M4 ;
        RECT  328.236 190.896 328.32 190.92 ;
    END
  END i_data[9]
  PIN i_done
    DIRECTION INPUT ;
    USE SIGNAL ;
    PORT
      LAYER M4 ;
        RECT  328.236 183.888 328.32 183.912 ;
    END
  END i_done
  PIN i_layer[0]
    DIRECTION INPUT ;
    USE SIGNAL ;
    PORT
      LAYER M4 ;
        RECT  328.236 183.984 328.32 184.008 ;
    END
  END i_layer[0]
  PIN i_layer[1]
    DIRECTION INPUT ;
    USE SIGNAL ;
    PORT
      LAYER M4 ;
        RECT  328.236 184.08 328.32 184.104 ;
    END
  END i_layer[1]
  PIN i_layer[2]
    DIRECTION INPUT ;
    USE SIGNAL ;
    PORT
      LAYER M4 ;
        RECT  328.236 184.176 328.32 184.2 ;
    END
  END i_layer[2]
  PIN i_layer[3]
    DIRECTION INPUT ;
    USE SIGNAL ;
    PORT
      LAYER M4 ;
        RECT  328.236 184.272 328.32 184.296 ;
    END
  END i_layer[3]
  PIN i_layer[4]
    DIRECTION INPUT ;
    USE SIGNAL ;
    PORT
      LAYER M4 ;
        RECT  328.236 184.368 328.32 184.392 ;
    END
  END i_layer[4]
  PIN i_layer[5]
    DIRECTION INPUT ;
    USE SIGNAL ;
    PORT
      LAYER M4 ;
        RECT  328.236 184.464 328.32 184.488 ;
    END
  END i_layer[5]
  PIN i_layer[6]
    DIRECTION INPUT ;
    USE SIGNAL ;
    PORT
      LAYER M4 ;
        RECT  328.236 184.56 328.32 184.584 ;
    END
  END i_layer[6]
  PIN i_layer[7]
    DIRECTION INPUT ;
    USE SIGNAL ;
    PORT
      LAYER M4 ;
        RECT  328.236 184.656 328.32 184.68 ;
    END
  END i_layer[7]
  PIN i_limit[0]
    DIRECTION INPUT ;
    USE SIGNAL ;
    PORT
      LAYER M4 ;
        RECT  328.236 184.752 328.32 184.776 ;
    END
  END i_limit[0]
  PIN i_limit[10]
    DIRECTION INPUT ;
    USE SIGNAL ;
    PORT
      LAYER M4 ;
        RECT  328.236 185.712 328.32 185.736 ;
    END
  END i_limit[10]
  PIN i_limit[1]
    DIRECTION INPUT ;
    USE SIGNAL ;
    PORT
      LAYER M4 ;
        RECT  328.236 184.848 328.32 184.872 ;
    END
  END i_limit[1]
  PIN i_limit[2]
    DIRECTION INPUT ;
    USE SIGNAL ;
    PORT
      LAYER M4 ;
        RECT  328.236 184.944 328.32 184.968 ;
    END
  END i_limit[2]
  PIN i_limit[3]
    DIRECTION INPUT ;
    USE SIGNAL ;
    PORT
      LAYER M4 ;
        RECT  328.236 185.04 328.32 185.064 ;
    END
  END i_limit[3]
  PIN i_limit[4]
    DIRECTION INPUT ;
    USE SIGNAL ;
    PORT
      LAYER M4 ;
        RECT  328.236 185.136 328.32 185.16 ;
    END
  END i_limit[4]
  PIN i_limit[5]
    DIRECTION INPUT ;
    USE SIGNAL ;
    PORT
      LAYER M4 ;
        RECT  328.236 185.232 328.32 185.256 ;
    END
  END i_limit[5]
  PIN i_limit[6]
    DIRECTION INPUT ;
    USE SIGNAL ;
    PORT
      LAYER M4 ;
        RECT  328.236 185.328 328.32 185.352 ;
    END
  END i_limit[6]
  PIN i_limit[7]
    DIRECTION INPUT ;
    USE SIGNAL ;
    PORT
      LAYER M4 ;
        RECT  328.236 185.424 328.32 185.448 ;
    END
  END i_limit[7]
  PIN i_limit[8]
    DIRECTION INPUT ;
    USE SIGNAL ;
    PORT
      LAYER M4 ;
        RECT  328.236 185.52 328.32 185.544 ;
    END
  END i_limit[8]
  PIN i_limit[9]
    DIRECTION INPUT ;
    USE SIGNAL ;
    PORT
      LAYER M4 ;
        RECT  328.236 185.616 328.32 185.64 ;
    END
  END i_limit[9]
  PIN i_port[0]
    DIRECTION INPUT ;
    USE SIGNAL ;
    PORT
      LAYER M4 ;
        RECT  328.236 201.936 328.32 201.96 ;
    END
  END i_port[0]
  PIN i_port[1]
    DIRECTION INPUT ;
    USE SIGNAL ;
    PORT
      LAYER M4 ;
        RECT  328.236 202.032 328.32 202.056 ;
    END
  END i_port[1]
  PIN i_port[2]
    DIRECTION INPUT ;
    USE SIGNAL ;
    PORT
      LAYER M4 ;
        RECT  328.236 202.128 328.32 202.152 ;
    END
  END i_port[2]
  PIN i_port[3]
    DIRECTION INPUT ;
    USE SIGNAL ;
    PORT
      LAYER M4 ;
        RECT  328.236 202.224 328.32 202.248 ;
    END
  END i_port[3]
  PIN i_port[4]
    DIRECTION INPUT ;
    USE SIGNAL ;
    PORT
      LAYER M4 ;
        RECT  328.236 202.32 328.32 202.344 ;
    END
  END i_port[4]
  PIN i_port[5]
    DIRECTION INPUT ;
    USE SIGNAL ;
    PORT
      LAYER M4 ;
        RECT  328.236 202.416 328.32 202.44 ;
    END
  END i_port[5]
  PIN i_port[6]
    DIRECTION INPUT ;
    USE SIGNAL ;
    PORT
      LAYER M4 ;
        RECT  328.236 202.512 328.32 202.536 ;
    END
  END i_port[6]
  PIN i_pos[0]
    DIRECTION INPUT ;
    USE SIGNAL ;
    PORT
      LAYER M4 ;
        RECT  328.236 202.608 328.32 202.632 ;
    END
  END i_pos[0]
  PIN i_pos[10]
    DIRECTION INPUT ;
    USE SIGNAL ;
    PORT
      LAYER M4 ;
        RECT  328.236 203.568 328.32 203.592 ;
    END
  END i_pos[10]
  PIN i_pos[11]
    DIRECTION INPUT ;
    USE SIGNAL ;
    PORT
      LAYER M4 ;
        RECT  328.236 203.664 328.32 203.688 ;
    END
  END i_pos[11]
  PIN i_pos[12]
    DIRECTION INPUT ;
    USE SIGNAL ;
    PORT
      LAYER M4 ;
        RECT  328.236 203.76 328.32 203.784 ;
    END
  END i_pos[12]
  PIN i_pos[1]
    DIRECTION INPUT ;
    USE SIGNAL ;
    PORT
      LAYER M4 ;
        RECT  328.236 202.704 328.32 202.728 ;
    END
  END i_pos[1]
  PIN i_pos[2]
    DIRECTION INPUT ;
    USE SIGNAL ;
    PORT
      LAYER M4 ;
        RECT  328.236 202.8 328.32 202.824 ;
    END
  END i_pos[2]
  PIN i_pos[3]
    DIRECTION INPUT ;
    USE SIGNAL ;
    PORT
      LAYER M4 ;
        RECT  328.236 202.896 328.32 202.92 ;
    END
  END i_pos[3]
  PIN i_pos[4]
    DIRECTION INPUT ;
    USE SIGNAL ;
    PORT
      LAYER M4 ;
        RECT  328.236 202.992 328.32 203.016 ;
    END
  END i_pos[4]
  PIN i_pos[5]
    DIRECTION INPUT ;
    USE SIGNAL ;
    PORT
      LAYER M4 ;
        RECT  328.236 203.088 328.32 203.112 ;
    END
  END i_pos[5]
  PIN i_pos[6]
    DIRECTION INPUT ;
    USE SIGNAL ;
    PORT
      LAYER M4 ;
        RECT  328.236 203.184 328.32 203.208 ;
    END
  END i_pos[6]
  PIN i_pos[7]
    DIRECTION INPUT ;
    USE SIGNAL ;
    PORT
      LAYER M4 ;
        RECT  328.236 203.28 328.32 203.304 ;
    END
  END i_pos[7]
  PIN i_pos[8]
    DIRECTION INPUT ;
    USE SIGNAL ;
    PORT
      LAYER M4 ;
        RECT  328.236 203.376 328.32 203.4 ;
    END
  END i_pos[8]
  PIN i_pos[9]
    DIRECTION INPUT ;
    USE SIGNAL ;
    PORT
      LAYER M4 ;
        RECT  328.236 203.472 328.32 203.496 ;
    END
  END i_pos[9]
  PIN i_row[0]
    DIRECTION INPUT ;
    USE SIGNAL ;
    PORT
      LAYER M4 ;
        RECT  328.236 203.856 328.32 203.88 ;
    END
  END i_row[0]
  PIN i_row[1]
    DIRECTION INPUT ;
    USE SIGNAL ;
    PORT
      LAYER M4 ;
        RECT  328.236 203.952 328.32 203.976 ;
    END
  END i_row[1]
  PIN i_row[2]
    DIRECTION INPUT ;
    USE SIGNAL ;
    PORT
      LAYER M4 ;
        RECT  328.236 204.048 328.32 204.072 ;
    END
  END i_row[2]
  PIN i_row[3]
    DIRECTION INPUT ;
    USE SIGNAL ;
    PORT
      LAYER M4 ;
        RECT  328.236 204.144 328.32 204.168 ;
    END
  END i_row[3]
  PIN i_row[4]
    DIRECTION INPUT ;
    USE SIGNAL ;
    PORT
      LAYER M4 ;
        RECT  328.236 204.24 328.32 204.264 ;
    END
  END i_row[4]
  PIN i_row[5]
    DIRECTION INPUT ;
    USE SIGNAL ;
    PORT
      LAYER M4 ;
        RECT  328.236 204.336 328.32 204.36 ;
    END
  END i_row[5]
  PIN i_row[6]
    DIRECTION INPUT ;
    USE SIGNAL ;
    PORT
      LAYER M4 ;
        RECT  328.236 204.432 328.32 204.456 ;
    END
  END i_row[6]
  PIN i_row[7]
    DIRECTION INPUT ;
    USE SIGNAL ;
    PORT
      LAYER M4 ;
        RECT  328.236 204.528 328.32 204.552 ;
    END
  END i_row[7]
  PIN i_sec[0]
    DIRECTION INPUT ;
    USE SIGNAL ;
    PORT
      LAYER M4 ;
        RECT  328.236 204.624 328.32 204.648 ;
    END
  END i_sec[0]
  PIN i_sec[10]
    DIRECTION INPUT ;
    USE SIGNAL ;
    PORT
      LAYER M4 ;
        RECT  328.236 205.584 328.32 205.608 ;
    END
  END i_sec[10]
  PIN i_sec[11]
    DIRECTION INPUT ;
    USE SIGNAL ;
    PORT
      LAYER M4 ;
        RECT  328.236 205.68 328.32 205.704 ;
    END
  END i_sec[11]
  PIN i_sec[12]
    DIRECTION INPUT ;
    USE SIGNAL ;
    PORT
      LAYER M4 ;
        RECT  328.236 205.776 328.32 205.8 ;
    END
  END i_sec[12]
  PIN i_sec[13]
    DIRECTION INPUT ;
    USE SIGNAL ;
    PORT
      LAYER M4 ;
        RECT  328.236 205.872 328.32 205.896 ;
    END
  END i_sec[13]
  PIN i_sec[14]
    DIRECTION INPUT ;
    USE SIGNAL ;
    PORT
      LAYER M4 ;
        RECT  328.236 205.968 328.32 205.992 ;
    END
  END i_sec[14]
  PIN i_sec[15]
    DIRECTION INPUT ;
    USE SIGNAL ;
    PORT
      LAYER M4 ;
        RECT  328.236 206.064 328.32 206.088 ;
    END
  END i_sec[15]
  PIN i_sec[16]
    DIRECTION INPUT ;
    USE SIGNAL ;
    PORT
      LAYER M4 ;
        RECT  328.236 206.16 328.32 206.184 ;
    END
  END i_sec[16]
  PIN i_sec[1]
    DIRECTION INPUT ;
    USE SIGNAL ;
    PORT
      LAYER M4 ;
        RECT  328.236 204.72 328.32 204.744 ;
    END
  END i_sec[1]
  PIN i_sec[2]
    DIRECTION INPUT ;
    USE SIGNAL ;
    PORT
      LAYER M4 ;
        RECT  328.236 204.816 328.32 204.84 ;
    END
  END i_sec[2]
  PIN i_sec[3]
    DIRECTION INPUT ;
    USE SIGNAL ;
    PORT
      LAYER M4 ;
        RECT  328.236 204.912 328.32 204.936 ;
    END
  END i_sec[3]
  PIN i_sec[4]
    DIRECTION INPUT ;
    USE SIGNAL ;
    PORT
      LAYER M4 ;
        RECT  328.236 205.008 328.32 205.032 ;
    END
  END i_sec[4]
  PIN i_sec[5]
    DIRECTION INPUT ;
    USE SIGNAL ;
    PORT
      LAYER M4 ;
        RECT  328.236 205.104 328.32 205.128 ;
    END
  END i_sec[5]
  PIN i_sec[6]
    DIRECTION INPUT ;
    USE SIGNAL ;
    PORT
      LAYER M4 ;
        RECT  328.236 205.2 328.32 205.224 ;
    END
  END i_sec[6]
  PIN i_sec[7]
    DIRECTION INPUT ;
    USE SIGNAL ;
    PORT
      LAYER M4 ;
        RECT  328.236 205.296 328.32 205.32 ;
    END
  END i_sec[7]
  PIN i_sec[8]
    DIRECTION INPUT ;
    USE SIGNAL ;
    PORT
      LAYER M4 ;
        RECT  328.236 205.392 328.32 205.416 ;
    END
  END i_sec[8]
  PIN i_sec[9]
    DIRECTION INPUT ;
    USE SIGNAL ;
    PORT
      LAYER M4 ;
        RECT  328.236 205.488 328.32 205.512 ;
    END
  END i_sec[9]
  PIN i_v
    DIRECTION INPUT ;
    USE SIGNAL ;
    PORT
      LAYER M4 ;
        RECT  328.236 206.256 328.32 206.28 ;
    END
  END i_v
  PIN o_bad
    DIRECTION OUTPUT ;
    USE SIGNAL ;
    PORT
      LAYER M4 ;
        RECT  0 194.928 0.084 194.952 ;
    END
  END o_bad
  PIN o_cr
    DIRECTION INPUT ;
    USE SIGNAL ;
    PORT
      LAYER M5 ;
        RECT  169.008 371.436 169.032 371.52 ;
    END
  END o_cr
  PIN o_data[0]
    DIRECTION OUTPUT ;
    USE SIGNAL ;
    PORT
      LAYER M4 ;
        RECT  0 195.024 0.084 195.048 ;
    END
  END o_data[0]
  PIN o_data[100]
    DIRECTION OUTPUT ;
    USE SIGNAL ;
    PORT
      LAYER M4 ;
        RECT  0 166.992 0.084 167.016 ;
    END
  END o_data[100]
  PIN o_data[101]
    DIRECTION OUTPUT ;
    USE SIGNAL ;
    PORT
      LAYER M4 ;
        RECT  0 167.088 0.084 167.112 ;
    END
  END o_data[101]
  PIN o_data[102]
    DIRECTION OUTPUT ;
    USE SIGNAL ;
    PORT
      LAYER M4 ;
        RECT  0 167.184 0.084 167.208 ;
    END
  END o_data[102]
  PIN o_data[103]
    DIRECTION OUTPUT ;
    USE SIGNAL ;
    PORT
      LAYER M4 ;
        RECT  0 167.28 0.084 167.304 ;
    END
  END o_data[103]
  PIN o_data[104]
    DIRECTION OUTPUT ;
    USE SIGNAL ;
    PORT
      LAYER M4 ;
        RECT  0 167.376 0.084 167.4 ;
    END
  END o_data[104]
  PIN o_data[105]
    DIRECTION OUTPUT ;
    USE SIGNAL ;
    PORT
      LAYER M4 ;
        RECT  0 167.472 0.084 167.496 ;
    END
  END o_data[105]
  PIN o_data[106]
    DIRECTION OUTPUT ;
    USE SIGNAL ;
    PORT
      LAYER M4 ;
        RECT  0 167.568 0.084 167.592 ;
    END
  END o_data[106]
  PIN o_data[107]
    DIRECTION OUTPUT ;
    USE SIGNAL ;
    PORT
      LAYER M4 ;
        RECT  0 167.664 0.084 167.688 ;
    END
  END o_data[107]
  PIN o_data[108]
    DIRECTION OUTPUT ;
    USE SIGNAL ;
    PORT
      LAYER M4 ;
        RECT  0 167.76 0.084 167.784 ;
    END
  END o_data[108]
  PIN o_data[109]
    DIRECTION OUTPUT ;
    USE SIGNAL ;
    PORT
      LAYER M4 ;
        RECT  0 167.856 0.084 167.88 ;
    END
  END o_data[109]
  PIN o_data[10]
    DIRECTION OUTPUT ;
    USE SIGNAL ;
    PORT
      LAYER M4 ;
        RECT  0 195.984 0.084 196.008 ;
    END
  END o_data[10]
  PIN o_data[110]
    DIRECTION OUTPUT ;
    USE SIGNAL ;
    PORT
      LAYER M4 ;
        RECT  0 167.952 0.084 167.976 ;
    END
  END o_data[110]
  PIN o_data[111]
    DIRECTION OUTPUT ;
    USE SIGNAL ;
    PORT
      LAYER M4 ;
        RECT  0 168.048 0.084 168.072 ;
    END
  END o_data[111]
  PIN o_data[112]
    DIRECTION OUTPUT ;
    USE SIGNAL ;
    PORT
      LAYER M4 ;
        RECT  0 168.144 0.084 168.168 ;
    END
  END o_data[112]
  PIN o_data[113]
    DIRECTION OUTPUT ;
    USE SIGNAL ;
    PORT
      LAYER M4 ;
        RECT  0 168.24 0.084 168.264 ;
    END
  END o_data[113]
  PIN o_data[114]
    DIRECTION OUTPUT ;
    USE SIGNAL ;
    PORT
      LAYER M4 ;
        RECT  0 168.336 0.084 168.36 ;
    END
  END o_data[114]
  PIN o_data[115]
    DIRECTION OUTPUT ;
    USE SIGNAL ;
    PORT
      LAYER M4 ;
        RECT  0 168.432 0.084 168.456 ;
    END
  END o_data[115]
  PIN o_data[116]
    DIRECTION OUTPUT ;
    USE SIGNAL ;
    PORT
      LAYER M4 ;
        RECT  0 168.528 0.084 168.552 ;
    END
  END o_data[116]
  PIN o_data[117]
    DIRECTION OUTPUT ;
    USE SIGNAL ;
    PORT
      LAYER M4 ;
        RECT  0 168.624 0.084 168.648 ;
    END
  END o_data[117]
  PIN o_data[118]
    DIRECTION OUTPUT ;
    USE SIGNAL ;
    PORT
      LAYER M4 ;
        RECT  0 168.72 0.084 168.744 ;
    END
  END o_data[118]
  PIN o_data[119]
    DIRECTION OUTPUT ;
    USE SIGNAL ;
    PORT
      LAYER M4 ;
        RECT  0 168.816 0.084 168.84 ;
    END
  END o_data[119]
  PIN o_data[11]
    DIRECTION OUTPUT ;
    USE SIGNAL ;
    PORT
      LAYER M4 ;
        RECT  0 196.08 0.084 196.104 ;
    END
  END o_data[11]
  PIN o_data[120]
    DIRECTION OUTPUT ;
    USE SIGNAL ;
    PORT
      LAYER M4 ;
        RECT  0 168.912 0.084 168.936 ;
    END
  END o_data[120]
  PIN o_data[121]
    DIRECTION OUTPUT ;
    USE SIGNAL ;
    PORT
      LAYER M4 ;
        RECT  0 169.008 0.084 169.032 ;
    END
  END o_data[121]
  PIN o_data[122]
    DIRECTION OUTPUT ;
    USE SIGNAL ;
    PORT
      LAYER M4 ;
        RECT  0 169.104 0.084 169.128 ;
    END
  END o_data[122]
  PIN o_data[123]
    DIRECTION OUTPUT ;
    USE SIGNAL ;
    PORT
      LAYER M4 ;
        RECT  0 169.2 0.084 169.224 ;
    END
  END o_data[123]
  PIN o_data[124]
    DIRECTION OUTPUT ;
    USE SIGNAL ;
    PORT
      LAYER M4 ;
        RECT  0 169.296 0.084 169.32 ;
    END
  END o_data[124]
  PIN o_data[125]
    DIRECTION OUTPUT ;
    USE SIGNAL ;
    PORT
      LAYER M4 ;
        RECT  0 169.392 0.084 169.416 ;
    END
  END o_data[125]
  PIN o_data[126]
    DIRECTION OUTPUT ;
    USE SIGNAL ;
    PORT
      LAYER M4 ;
        RECT  0 169.488 0.084 169.512 ;
    END
  END o_data[126]
  PIN o_data[127]
    DIRECTION OUTPUT ;
    USE SIGNAL ;
    PORT
      LAYER M4 ;
        RECT  0 153.456 0.084 153.48 ;
    END
  END o_data[127]
  PIN o_data[128]
    DIRECTION OUTPUT ;
    USE SIGNAL ;
    PORT
      LAYER M4 ;
        RECT  0 153.552 0.084 153.576 ;
    END
  END o_data[128]
  PIN o_data[129]
    DIRECTION OUTPUT ;
    USE SIGNAL ;
    PORT
      LAYER M4 ;
        RECT  0 153.648 0.084 153.672 ;
    END
  END o_data[129]
  PIN o_data[12]
    DIRECTION OUTPUT ;
    USE SIGNAL ;
    PORT
      LAYER M4 ;
        RECT  0 196.176 0.084 196.2 ;
    END
  END o_data[12]
  PIN o_data[130]
    DIRECTION OUTPUT ;
    USE SIGNAL ;
    PORT
      LAYER M4 ;
        RECT  0 153.744 0.084 153.768 ;
    END
  END o_data[130]
  PIN o_data[131]
    DIRECTION OUTPUT ;
    USE SIGNAL ;
    PORT
      LAYER M4 ;
        RECT  0 153.84 0.084 153.864 ;
    END
  END o_data[131]
  PIN o_data[132]
    DIRECTION OUTPUT ;
    USE SIGNAL ;
    PORT
      LAYER M4 ;
        RECT  0 153.936 0.084 153.96 ;
    END
  END o_data[132]
  PIN o_data[133]
    DIRECTION OUTPUT ;
    USE SIGNAL ;
    PORT
      LAYER M4 ;
        RECT  0 154.032 0.084 154.056 ;
    END
  END o_data[133]
  PIN o_data[134]
    DIRECTION OUTPUT ;
    USE SIGNAL ;
    PORT
      LAYER M4 ;
        RECT  0 154.128 0.084 154.152 ;
    END
  END o_data[134]
  PIN o_data[135]
    DIRECTION OUTPUT ;
    USE SIGNAL ;
    PORT
      LAYER M4 ;
        RECT  0 154.224 0.084 154.248 ;
    END
  END o_data[135]
  PIN o_data[136]
    DIRECTION OUTPUT ;
    USE SIGNAL ;
    PORT
      LAYER M4 ;
        RECT  0 154.32 0.084 154.344 ;
    END
  END o_data[136]
  PIN o_data[137]
    DIRECTION OUTPUT ;
    USE SIGNAL ;
    PORT
      LAYER M4 ;
        RECT  0 154.416 0.084 154.44 ;
    END
  END o_data[137]
  PIN o_data[138]
    DIRECTION OUTPUT ;
    USE SIGNAL ;
    PORT
      LAYER M4 ;
        RECT  0 154.512 0.084 154.536 ;
    END
  END o_data[138]
  PIN o_data[139]
    DIRECTION OUTPUT ;
    USE SIGNAL ;
    PORT
      LAYER M4 ;
        RECT  0 154.608 0.084 154.632 ;
    END
  END o_data[139]
  PIN o_data[13]
    DIRECTION OUTPUT ;
    USE SIGNAL ;
    PORT
      LAYER M4 ;
        RECT  0 196.272 0.084 196.296 ;
    END
  END o_data[13]
  PIN o_data[140]
    DIRECTION OUTPUT ;
    USE SIGNAL ;
    PORT
      LAYER M4 ;
        RECT  0 154.704 0.084 154.728 ;
    END
  END o_data[140]
  PIN o_data[141]
    DIRECTION OUTPUT ;
    USE SIGNAL ;
    PORT
      LAYER M4 ;
        RECT  0 154.8 0.084 154.824 ;
    END
  END o_data[141]
  PIN o_data[142]
    DIRECTION OUTPUT ;
    USE SIGNAL ;
    PORT
      LAYER M4 ;
        RECT  0 154.896 0.084 154.92 ;
    END
  END o_data[142]
  PIN o_data[143]
    DIRECTION OUTPUT ;
    USE SIGNAL ;
    PORT
      LAYER M4 ;
        RECT  0 154.992 0.084 155.016 ;
    END
  END o_data[143]
  PIN o_data[144]
    DIRECTION OUTPUT ;
    USE SIGNAL ;
    PORT
      LAYER M4 ;
        RECT  0 155.088 0.084 155.112 ;
    END
  END o_data[144]
  PIN o_data[145]
    DIRECTION OUTPUT ;
    USE SIGNAL ;
    PORT
      LAYER M4 ;
        RECT  0 155.184 0.084 155.208 ;
    END
  END o_data[145]
  PIN o_data[146]
    DIRECTION OUTPUT ;
    USE SIGNAL ;
    PORT
      LAYER M4 ;
        RECT  0 155.28 0.084 155.304 ;
    END
  END o_data[146]
  PIN o_data[147]
    DIRECTION OUTPUT ;
    USE SIGNAL ;
    PORT
      LAYER M4 ;
        RECT  0 155.376 0.084 155.4 ;
    END
  END o_data[147]
  PIN o_data[148]
    DIRECTION OUTPUT ;
    USE SIGNAL ;
    PORT
      LAYER M4 ;
        RECT  0 155.472 0.084 155.496 ;
    END
  END o_data[148]
  PIN o_data[149]
    DIRECTION OUTPUT ;
    USE SIGNAL ;
    PORT
      LAYER M4 ;
        RECT  0 155.568 0.084 155.592 ;
    END
  END o_data[149]
  PIN o_data[14]
    DIRECTION OUTPUT ;
    USE SIGNAL ;
    PORT
      LAYER M4 ;
        RECT  0 196.368 0.084 196.392 ;
    END
  END o_data[14]
  PIN o_data[150]
    DIRECTION OUTPUT ;
    USE SIGNAL ;
    PORT
      LAYER M4 ;
        RECT  0 155.664 0.084 155.688 ;
    END
  END o_data[150]
  PIN o_data[151]
    DIRECTION OUTPUT ;
    USE SIGNAL ;
    PORT
      LAYER M4 ;
        RECT  0 155.76 0.084 155.784 ;
    END
  END o_data[151]
  PIN o_data[152]
    DIRECTION OUTPUT ;
    USE SIGNAL ;
    PORT
      LAYER M4 ;
        RECT  0 155.856 0.084 155.88 ;
    END
  END o_data[152]
  PIN o_data[153]
    DIRECTION OUTPUT ;
    USE SIGNAL ;
    PORT
      LAYER M4 ;
        RECT  0 155.952 0.084 155.976 ;
    END
  END o_data[153]
  PIN o_data[154]
    DIRECTION OUTPUT ;
    USE SIGNAL ;
    PORT
      LAYER M4 ;
        RECT  0 156.048 0.084 156.072 ;
    END
  END o_data[154]
  PIN o_data[155]
    DIRECTION OUTPUT ;
    USE SIGNAL ;
    PORT
      LAYER M4 ;
        RECT  0 156.144 0.084 156.168 ;
    END
  END o_data[155]
  PIN o_data[156]
    DIRECTION OUTPUT ;
    USE SIGNAL ;
    PORT
      LAYER M4 ;
        RECT  0 156.24 0.084 156.264 ;
    END
  END o_data[156]
  PIN o_data[157]
    DIRECTION OUTPUT ;
    USE SIGNAL ;
    PORT
      LAYER M4 ;
        RECT  0 156.336 0.084 156.36 ;
    END
  END o_data[157]
  PIN o_data[158]
    DIRECTION OUTPUT ;
    USE SIGNAL ;
    PORT
      LAYER M4 ;
        RECT  0 156.432 0.084 156.456 ;
    END
  END o_data[158]
  PIN o_data[159]
    DIRECTION OUTPUT ;
    USE SIGNAL ;
    PORT
      LAYER M4 ;
        RECT  0 175.728 0.084 175.752 ;
    END
  END o_data[159]
  PIN o_data[15]
    DIRECTION OUTPUT ;
    USE SIGNAL ;
    PORT
      LAYER M4 ;
        RECT  0 196.464 0.084 196.488 ;
    END
  END o_data[15]
  PIN o_data[160]
    DIRECTION OUTPUT ;
    USE SIGNAL ;
    PORT
      LAYER M4 ;
        RECT  0 175.824 0.084 175.848 ;
    END
  END o_data[160]
  PIN o_data[161]
    DIRECTION OUTPUT ;
    USE SIGNAL ;
    PORT
      LAYER M4 ;
        RECT  0 175.92 0.084 175.944 ;
    END
  END o_data[161]
  PIN o_data[162]
    DIRECTION OUTPUT ;
    USE SIGNAL ;
    PORT
      LAYER M4 ;
        RECT  0 176.016 0.084 176.04 ;
    END
  END o_data[162]
  PIN o_data[163]
    DIRECTION OUTPUT ;
    USE SIGNAL ;
    PORT
      LAYER M4 ;
        RECT  0 176.112 0.084 176.136 ;
    END
  END o_data[163]
  PIN o_data[164]
    DIRECTION OUTPUT ;
    USE SIGNAL ;
    PORT
      LAYER M4 ;
        RECT  0 176.208 0.084 176.232 ;
    END
  END o_data[164]
  PIN o_data[165]
    DIRECTION OUTPUT ;
    USE SIGNAL ;
    PORT
      LAYER M4 ;
        RECT  0 176.304 0.084 176.328 ;
    END
  END o_data[165]
  PIN o_data[166]
    DIRECTION OUTPUT ;
    USE SIGNAL ;
    PORT
      LAYER M4 ;
        RECT  0 176.4 0.084 176.424 ;
    END
  END o_data[166]
  PIN o_data[167]
    DIRECTION OUTPUT ;
    USE SIGNAL ;
    PORT
      LAYER M4 ;
        RECT  0 176.496 0.084 176.52 ;
    END
  END o_data[167]
  PIN o_data[168]
    DIRECTION OUTPUT ;
    USE SIGNAL ;
    PORT
      LAYER M4 ;
        RECT  0 176.592 0.084 176.616 ;
    END
  END o_data[168]
  PIN o_data[169]
    DIRECTION OUTPUT ;
    USE SIGNAL ;
    PORT
      LAYER M4 ;
        RECT  0 176.688 0.084 176.712 ;
    END
  END o_data[169]
  PIN o_data[16]
    DIRECTION OUTPUT ;
    USE SIGNAL ;
    PORT
      LAYER M4 ;
        RECT  0 196.56 0.084 196.584 ;
    END
  END o_data[16]
  PIN o_data[170]
    DIRECTION OUTPUT ;
    USE SIGNAL ;
    PORT
      LAYER M4 ;
        RECT  0 176.784 0.084 176.808 ;
    END
  END o_data[170]
  PIN o_data[171]
    DIRECTION OUTPUT ;
    USE SIGNAL ;
    PORT
      LAYER M4 ;
        RECT  0 176.88 0.084 176.904 ;
    END
  END o_data[171]
  PIN o_data[172]
    DIRECTION OUTPUT ;
    USE SIGNAL ;
    PORT
      LAYER M4 ;
        RECT  0 176.976 0.084 177 ;
    END
  END o_data[172]
  PIN o_data[173]
    DIRECTION OUTPUT ;
    USE SIGNAL ;
    PORT
      LAYER M4 ;
        RECT  0 177.072 0.084 177.096 ;
    END
  END o_data[173]
  PIN o_data[174]
    DIRECTION OUTPUT ;
    USE SIGNAL ;
    PORT
      LAYER M4 ;
        RECT  0 177.168 0.084 177.192 ;
    END
  END o_data[174]
  PIN o_data[175]
    DIRECTION OUTPUT ;
    USE SIGNAL ;
    PORT
      LAYER M4 ;
        RECT  0 177.264 0.084 177.288 ;
    END
  END o_data[175]
  PIN o_data[176]
    DIRECTION OUTPUT ;
    USE SIGNAL ;
    PORT
      LAYER M4 ;
        RECT  0 177.36 0.084 177.384 ;
    END
  END o_data[176]
  PIN o_data[177]
    DIRECTION OUTPUT ;
    USE SIGNAL ;
    PORT
      LAYER M4 ;
        RECT  0 177.456 0.084 177.48 ;
    END
  END o_data[177]
  PIN o_data[178]
    DIRECTION OUTPUT ;
    USE SIGNAL ;
    PORT
      LAYER M4 ;
        RECT  0 177.552 0.084 177.576 ;
    END
  END o_data[178]
  PIN o_data[179]
    DIRECTION OUTPUT ;
    USE SIGNAL ;
    PORT
      LAYER M4 ;
        RECT  0 177.648 0.084 177.672 ;
    END
  END o_data[179]
  PIN o_data[17]
    DIRECTION OUTPUT ;
    USE SIGNAL ;
    PORT
      LAYER M4 ;
        RECT  0 196.656 0.084 196.68 ;
    END
  END o_data[17]
  PIN o_data[180]
    DIRECTION OUTPUT ;
    USE SIGNAL ;
    PORT
      LAYER M4 ;
        RECT  0 177.744 0.084 177.768 ;
    END
  END o_data[180]
  PIN o_data[181]
    DIRECTION OUTPUT ;
    USE SIGNAL ;
    PORT
      LAYER M4 ;
        RECT  0 177.84 0.084 177.864 ;
    END
  END o_data[181]
  PIN o_data[182]
    DIRECTION OUTPUT ;
    USE SIGNAL ;
    PORT
      LAYER M4 ;
        RECT  0 177.936 0.084 177.96 ;
    END
  END o_data[182]
  PIN o_data[183]
    DIRECTION OUTPUT ;
    USE SIGNAL ;
    PORT
      LAYER M4 ;
        RECT  0 178.032 0.084 178.056 ;
    END
  END o_data[183]
  PIN o_data[184]
    DIRECTION OUTPUT ;
    USE SIGNAL ;
    PORT
      LAYER M4 ;
        RECT  0 178.128 0.084 178.152 ;
    END
  END o_data[184]
  PIN o_data[185]
    DIRECTION OUTPUT ;
    USE SIGNAL ;
    PORT
      LAYER M4 ;
        RECT  0 178.224 0.084 178.248 ;
    END
  END o_data[185]
  PIN o_data[186]
    DIRECTION OUTPUT ;
    USE SIGNAL ;
    PORT
      LAYER M4 ;
        RECT  0 178.32 0.084 178.344 ;
    END
  END o_data[186]
  PIN o_data[187]
    DIRECTION OUTPUT ;
    USE SIGNAL ;
    PORT
      LAYER M4 ;
        RECT  0 178.416 0.084 178.44 ;
    END
  END o_data[187]
  PIN o_data[188]
    DIRECTION OUTPUT ;
    USE SIGNAL ;
    PORT
      LAYER M4 ;
        RECT  0 178.512 0.084 178.536 ;
    END
  END o_data[188]
  PIN o_data[189]
    DIRECTION OUTPUT ;
    USE SIGNAL ;
    PORT
      LAYER M4 ;
        RECT  0 178.608 0.084 178.632 ;
    END
  END o_data[189]
  PIN o_data[18]
    DIRECTION OUTPUT ;
    USE SIGNAL ;
    PORT
      LAYER M4 ;
        RECT  0 196.752 0.084 196.776 ;
    END
  END o_data[18]
  PIN o_data[190]
    DIRECTION OUTPUT ;
    USE SIGNAL ;
    PORT
      LAYER M4 ;
        RECT  0 178.704 0.084 178.728 ;
    END
  END o_data[190]
  PIN o_data[191]
    DIRECTION OUTPUT ;
    USE SIGNAL ;
    PORT
      LAYER M4 ;
        RECT  0 169.584 0.084 169.608 ;
    END
  END o_data[191]
  PIN o_data[192]
    DIRECTION OUTPUT ;
    USE SIGNAL ;
    PORT
      LAYER M4 ;
        RECT  0 169.68 0.084 169.704 ;
    END
  END o_data[192]
  PIN o_data[193]
    DIRECTION OUTPUT ;
    USE SIGNAL ;
    PORT
      LAYER M4 ;
        RECT  0 169.776 0.084 169.8 ;
    END
  END o_data[193]
  PIN o_data[194]
    DIRECTION OUTPUT ;
    USE SIGNAL ;
    PORT
      LAYER M4 ;
        RECT  0 169.872 0.084 169.896 ;
    END
  END o_data[194]
  PIN o_data[195]
    DIRECTION OUTPUT ;
    USE SIGNAL ;
    PORT
      LAYER M4 ;
        RECT  0 169.968 0.084 169.992 ;
    END
  END o_data[195]
  PIN o_data[196]
    DIRECTION OUTPUT ;
    USE SIGNAL ;
    PORT
      LAYER M4 ;
        RECT  0 170.064 0.084 170.088 ;
    END
  END o_data[196]
  PIN o_data[197]
    DIRECTION OUTPUT ;
    USE SIGNAL ;
    PORT
      LAYER M4 ;
        RECT  0 170.16 0.084 170.184 ;
    END
  END o_data[197]
  PIN o_data[198]
    DIRECTION OUTPUT ;
    USE SIGNAL ;
    PORT
      LAYER M4 ;
        RECT  0 170.256 0.084 170.28 ;
    END
  END o_data[198]
  PIN o_data[199]
    DIRECTION OUTPUT ;
    USE SIGNAL ;
    PORT
      LAYER M4 ;
        RECT  0 170.352 0.084 170.376 ;
    END
  END o_data[199]
  PIN o_data[19]
    DIRECTION OUTPUT ;
    USE SIGNAL ;
    PORT
      LAYER M4 ;
        RECT  0 196.848 0.084 196.872 ;
    END
  END o_data[19]
  PIN o_data[1]
    DIRECTION OUTPUT ;
    USE SIGNAL ;
    PORT
      LAYER M4 ;
        RECT  0 195.12 0.084 195.144 ;
    END
  END o_data[1]
  PIN o_data[200]
    DIRECTION OUTPUT ;
    USE SIGNAL ;
    PORT
      LAYER M4 ;
        RECT  0 170.448 0.084 170.472 ;
    END
  END o_data[200]
  PIN o_data[201]
    DIRECTION OUTPUT ;
    USE SIGNAL ;
    PORT
      LAYER M4 ;
        RECT  0 170.544 0.084 170.568 ;
    END
  END o_data[201]
  PIN o_data[202]
    DIRECTION OUTPUT ;
    USE SIGNAL ;
    PORT
      LAYER M4 ;
        RECT  0 170.64 0.084 170.664 ;
    END
  END o_data[202]
  PIN o_data[203]
    DIRECTION OUTPUT ;
    USE SIGNAL ;
    PORT
      LAYER M4 ;
        RECT  0 170.736 0.084 170.76 ;
    END
  END o_data[203]
  PIN o_data[204]
    DIRECTION OUTPUT ;
    USE SIGNAL ;
    PORT
      LAYER M4 ;
        RECT  0 170.832 0.084 170.856 ;
    END
  END o_data[204]
  PIN o_data[205]
    DIRECTION OUTPUT ;
    USE SIGNAL ;
    PORT
      LAYER M4 ;
        RECT  0 170.928 0.084 170.952 ;
    END
  END o_data[205]
  PIN o_data[206]
    DIRECTION OUTPUT ;
    USE SIGNAL ;
    PORT
      LAYER M4 ;
        RECT  0 171.024 0.084 171.048 ;
    END
  END o_data[206]
  PIN o_data[207]
    DIRECTION OUTPUT ;
    USE SIGNAL ;
    PORT
      LAYER M4 ;
        RECT  0 171.12 0.084 171.144 ;
    END
  END o_data[207]
  PIN o_data[208]
    DIRECTION OUTPUT ;
    USE SIGNAL ;
    PORT
      LAYER M4 ;
        RECT  0 171.216 0.084 171.24 ;
    END
  END o_data[208]
  PIN o_data[209]
    DIRECTION OUTPUT ;
    USE SIGNAL ;
    PORT
      LAYER M4 ;
        RECT  0 171.312 0.084 171.336 ;
    END
  END o_data[209]
  PIN o_data[20]
    DIRECTION OUTPUT ;
    USE SIGNAL ;
    PORT
      LAYER M4 ;
        RECT  0 196.944 0.084 196.968 ;
    END
  END o_data[20]
  PIN o_data[210]
    DIRECTION OUTPUT ;
    USE SIGNAL ;
    PORT
      LAYER M4 ;
        RECT  0 171.408 0.084 171.432 ;
    END
  END o_data[210]
  PIN o_data[211]
    DIRECTION OUTPUT ;
    USE SIGNAL ;
    PORT
      LAYER M4 ;
        RECT  0 171.504 0.084 171.528 ;
    END
  END o_data[211]
  PIN o_data[212]
    DIRECTION OUTPUT ;
    USE SIGNAL ;
    PORT
      LAYER M4 ;
        RECT  0 171.6 0.084 171.624 ;
    END
  END o_data[212]
  PIN o_data[213]
    DIRECTION OUTPUT ;
    USE SIGNAL ;
    PORT
      LAYER M4 ;
        RECT  0 171.696 0.084 171.72 ;
    END
  END o_data[213]
  PIN o_data[214]
    DIRECTION OUTPUT ;
    USE SIGNAL ;
    PORT
      LAYER M4 ;
        RECT  0 171.792 0.084 171.816 ;
    END
  END o_data[214]
  PIN o_data[215]
    DIRECTION OUTPUT ;
    USE SIGNAL ;
    PORT
      LAYER M4 ;
        RECT  0 171.888 0.084 171.912 ;
    END
  END o_data[215]
  PIN o_data[216]
    DIRECTION OUTPUT ;
    USE SIGNAL ;
    PORT
      LAYER M4 ;
        RECT  0 171.984 0.084 172.008 ;
    END
  END o_data[216]
  PIN o_data[217]
    DIRECTION OUTPUT ;
    USE SIGNAL ;
    PORT
      LAYER M4 ;
        RECT  0 172.08 0.084 172.104 ;
    END
  END o_data[217]
  PIN o_data[218]
    DIRECTION OUTPUT ;
    USE SIGNAL ;
    PORT
      LAYER M4 ;
        RECT  0 172.176 0.084 172.2 ;
    END
  END o_data[218]
  PIN o_data[219]
    DIRECTION OUTPUT ;
    USE SIGNAL ;
    PORT
      LAYER M4 ;
        RECT  0 172.272 0.084 172.296 ;
    END
  END o_data[219]
  PIN o_data[21]
    DIRECTION OUTPUT ;
    USE SIGNAL ;
    PORT
      LAYER M4 ;
        RECT  0 197.04 0.084 197.064 ;
    END
  END o_data[21]
  PIN o_data[220]
    DIRECTION OUTPUT ;
    USE SIGNAL ;
    PORT
      LAYER M4 ;
        RECT  0 172.368 0.084 172.392 ;
    END
  END o_data[220]
  PIN o_data[221]
    DIRECTION OUTPUT ;
    USE SIGNAL ;
    PORT
      LAYER M4 ;
        RECT  0 172.464 0.084 172.488 ;
    END
  END o_data[221]
  PIN o_data[222]
    DIRECTION OUTPUT ;
    USE SIGNAL ;
    PORT
      LAYER M4 ;
        RECT  0 172.56 0.084 172.584 ;
    END
  END o_data[222]
  PIN o_data[223]
    DIRECTION OUTPUT ;
    USE SIGNAL ;
    PORT
      LAYER M4 ;
        RECT  0 172.656 0.084 172.68 ;
    END
  END o_data[223]
  PIN o_data[224]
    DIRECTION OUTPUT ;
    USE SIGNAL ;
    PORT
      LAYER M4 ;
        RECT  0 172.752 0.084 172.776 ;
    END
  END o_data[224]
  PIN o_data[225]
    DIRECTION OUTPUT ;
    USE SIGNAL ;
    PORT
      LAYER M4 ;
        RECT  0 172.848 0.084 172.872 ;
    END
  END o_data[225]
  PIN o_data[226]
    DIRECTION OUTPUT ;
    USE SIGNAL ;
    PORT
      LAYER M4 ;
        RECT  0 172.944 0.084 172.968 ;
    END
  END o_data[226]
  PIN o_data[227]
    DIRECTION OUTPUT ;
    USE SIGNAL ;
    PORT
      LAYER M4 ;
        RECT  0 173.04 0.084 173.064 ;
    END
  END o_data[227]
  PIN o_data[228]
    DIRECTION OUTPUT ;
    USE SIGNAL ;
    PORT
      LAYER M4 ;
        RECT  0 173.136 0.084 173.16 ;
    END
  END o_data[228]
  PIN o_data[229]
    DIRECTION OUTPUT ;
    USE SIGNAL ;
    PORT
      LAYER M4 ;
        RECT  0 173.232 0.084 173.256 ;
    END
  END o_data[229]
  PIN o_data[22]
    DIRECTION OUTPUT ;
    USE SIGNAL ;
    PORT
      LAYER M4 ;
        RECT  0 197.136 0.084 197.16 ;
    END
  END o_data[22]
  PIN o_data[230]
    DIRECTION OUTPUT ;
    USE SIGNAL ;
    PORT
      LAYER M4 ;
        RECT  0 173.328 0.084 173.352 ;
    END
  END o_data[230]
  PIN o_data[231]
    DIRECTION OUTPUT ;
    USE SIGNAL ;
    PORT
      LAYER M4 ;
        RECT  0 173.424 0.084 173.448 ;
    END
  END o_data[231]
  PIN o_data[232]
    DIRECTION OUTPUT ;
    USE SIGNAL ;
    PORT
      LAYER M4 ;
        RECT  0 173.52 0.084 173.544 ;
    END
  END o_data[232]
  PIN o_data[233]
    DIRECTION OUTPUT ;
    USE SIGNAL ;
    PORT
      LAYER M4 ;
        RECT  0 173.616 0.084 173.64 ;
    END
  END o_data[233]
  PIN o_data[234]
    DIRECTION OUTPUT ;
    USE SIGNAL ;
    PORT
      LAYER M4 ;
        RECT  0 173.712 0.084 173.736 ;
    END
  END o_data[234]
  PIN o_data[235]
    DIRECTION OUTPUT ;
    USE SIGNAL ;
    PORT
      LAYER M4 ;
        RECT  0 173.808 0.084 173.832 ;
    END
  END o_data[235]
  PIN o_data[236]
    DIRECTION OUTPUT ;
    USE SIGNAL ;
    PORT
      LAYER M4 ;
        RECT  0 173.904 0.084 173.928 ;
    END
  END o_data[236]
  PIN o_data[237]
    DIRECTION OUTPUT ;
    USE SIGNAL ;
    PORT
      LAYER M4 ;
        RECT  0 174 0.084 174.024 ;
    END
  END o_data[237]
  PIN o_data[238]
    DIRECTION OUTPUT ;
    USE SIGNAL ;
    PORT
      LAYER M4 ;
        RECT  0 174.096 0.084 174.12 ;
    END
  END o_data[238]
  PIN o_data[239]
    DIRECTION OUTPUT ;
    USE SIGNAL ;
    PORT
      LAYER M4 ;
        RECT  0 174.192 0.084 174.216 ;
    END
  END o_data[239]
  PIN o_data[23]
    DIRECTION OUTPUT ;
    USE SIGNAL ;
    PORT
      LAYER M4 ;
        RECT  0 197.232 0.084 197.256 ;
    END
  END o_data[23]
  PIN o_data[240]
    DIRECTION OUTPUT ;
    USE SIGNAL ;
    PORT
      LAYER M4 ;
        RECT  0 174.288 0.084 174.312 ;
    END
  END o_data[240]
  PIN o_data[241]
    DIRECTION OUTPUT ;
    USE SIGNAL ;
    PORT
      LAYER M4 ;
        RECT  0 174.384 0.084 174.408 ;
    END
  END o_data[241]
  PIN o_data[242]
    DIRECTION OUTPUT ;
    USE SIGNAL ;
    PORT
      LAYER M4 ;
        RECT  0 174.48 0.084 174.504 ;
    END
  END o_data[242]
  PIN o_data[243]
    DIRECTION OUTPUT ;
    USE SIGNAL ;
    PORT
      LAYER M4 ;
        RECT  0 174.576 0.084 174.6 ;
    END
  END o_data[243]
  PIN o_data[244]
    DIRECTION OUTPUT ;
    USE SIGNAL ;
    PORT
      LAYER M4 ;
        RECT  0 174.672 0.084 174.696 ;
    END
  END o_data[244]
  PIN o_data[245]
    DIRECTION OUTPUT ;
    USE SIGNAL ;
    PORT
      LAYER M4 ;
        RECT  0 174.768 0.084 174.792 ;
    END
  END o_data[245]
  PIN o_data[246]
    DIRECTION OUTPUT ;
    USE SIGNAL ;
    PORT
      LAYER M4 ;
        RECT  0 174.864 0.084 174.888 ;
    END
  END o_data[246]
  PIN o_data[247]
    DIRECTION OUTPUT ;
    USE SIGNAL ;
    PORT
      LAYER M4 ;
        RECT  0 174.96 0.084 174.984 ;
    END
  END o_data[247]
  PIN o_data[248]
    DIRECTION OUTPUT ;
    USE SIGNAL ;
    PORT
      LAYER M4 ;
        RECT  0 175.056 0.084 175.08 ;
    END
  END o_data[248]
  PIN o_data[249]
    DIRECTION OUTPUT ;
    USE SIGNAL ;
    PORT
      LAYER M4 ;
        RECT  0 175.152 0.084 175.176 ;
    END
  END o_data[249]
  PIN o_data[24]
    DIRECTION OUTPUT ;
    USE SIGNAL ;
    PORT
      LAYER M4 ;
        RECT  0 197.328 0.084 197.352 ;
    END
  END o_data[24]
  PIN o_data[250]
    DIRECTION OUTPUT ;
    USE SIGNAL ;
    PORT
      LAYER M4 ;
        RECT  0 175.248 0.084 175.272 ;
    END
  END o_data[250]
  PIN o_data[251]
    DIRECTION OUTPUT ;
    USE SIGNAL ;
    PORT
      LAYER M4 ;
        RECT  0 175.344 0.084 175.368 ;
    END
  END o_data[251]
  PIN o_data[252]
    DIRECTION OUTPUT ;
    USE SIGNAL ;
    PORT
      LAYER M4 ;
        RECT  0 175.44 0.084 175.464 ;
    END
  END o_data[252]
  PIN o_data[253]
    DIRECTION OUTPUT ;
    USE SIGNAL ;
    PORT
      LAYER M4 ;
        RECT  0 175.536 0.084 175.56 ;
    END
  END o_data[253]
  PIN o_data[254]
    DIRECTION OUTPUT ;
    USE SIGNAL ;
    PORT
      LAYER M4 ;
        RECT  0 175.632 0.084 175.656 ;
    END
  END o_data[254]
  PIN o_data[255]
    DIRECTION OUTPUT ;
    USE SIGNAL ;
    PORT
      LAYER M4 ;
        RECT  0 198.768 0.084 198.792 ;
    END
  END o_data[255]
  PIN o_data[25]
    DIRECTION OUTPUT ;
    USE SIGNAL ;
    PORT
      LAYER M4 ;
        RECT  0 197.424 0.084 197.448 ;
    END
  END o_data[25]
  PIN o_data[26]
    DIRECTION OUTPUT ;
    USE SIGNAL ;
    PORT
      LAYER M4 ;
        RECT  0 197.52 0.084 197.544 ;
    END
  END o_data[26]
  PIN o_data[27]
    DIRECTION OUTPUT ;
    USE SIGNAL ;
    PORT
      LAYER M4 ;
        RECT  0 197.616 0.084 197.64 ;
    END
  END o_data[27]
  PIN o_data[28]
    DIRECTION OUTPUT ;
    USE SIGNAL ;
    PORT
      LAYER M4 ;
        RECT  0 197.712 0.084 197.736 ;
    END
  END o_data[28]
  PIN o_data[29]
    DIRECTION OUTPUT ;
    USE SIGNAL ;
    PORT
      LAYER M4 ;
        RECT  0 197.808 0.084 197.832 ;
    END
  END o_data[29]
  PIN o_data[2]
    DIRECTION OUTPUT ;
    USE SIGNAL ;
    PORT
      LAYER M4 ;
        RECT  0 195.216 0.084 195.24 ;
    END
  END o_data[2]
  PIN o_data[30]
    DIRECTION OUTPUT ;
    USE SIGNAL ;
    PORT
      LAYER M4 ;
        RECT  0 197.904 0.084 197.928 ;
    END
  END o_data[30]
  PIN o_data[31]
    DIRECTION OUTPUT ;
    USE SIGNAL ;
    PORT
      LAYER M4 ;
        RECT  0 160.368 0.084 160.392 ;
    END
  END o_data[31]
  PIN o_data[32]
    DIRECTION OUTPUT ;
    USE SIGNAL ;
    PORT
      LAYER M4 ;
        RECT  0 160.464 0.084 160.488 ;
    END
  END o_data[32]
  PIN o_data[33]
    DIRECTION OUTPUT ;
    USE SIGNAL ;
    PORT
      LAYER M4 ;
        RECT  0 160.56 0.084 160.584 ;
    END
  END o_data[33]
  PIN o_data[34]
    DIRECTION OUTPUT ;
    USE SIGNAL ;
    PORT
      LAYER M4 ;
        RECT  0 160.656 0.084 160.68 ;
    END
  END o_data[34]
  PIN o_data[35]
    DIRECTION OUTPUT ;
    USE SIGNAL ;
    PORT
      LAYER M4 ;
        RECT  0 160.752 0.084 160.776 ;
    END
  END o_data[35]
  PIN o_data[36]
    DIRECTION OUTPUT ;
    USE SIGNAL ;
    PORT
      LAYER M4 ;
        RECT  0 160.848 0.084 160.872 ;
    END
  END o_data[36]
  PIN o_data[37]
    DIRECTION OUTPUT ;
    USE SIGNAL ;
    PORT
      LAYER M4 ;
        RECT  0 160.944 0.084 160.968 ;
    END
  END o_data[37]
  PIN o_data[38]
    DIRECTION OUTPUT ;
    USE SIGNAL ;
    PORT
      LAYER M4 ;
        RECT  0 161.04 0.084 161.064 ;
    END
  END o_data[38]
  PIN o_data[39]
    DIRECTION OUTPUT ;
    USE SIGNAL ;
    PORT
      LAYER M4 ;
        RECT  0 161.136 0.084 161.16 ;
    END
  END o_data[39]
  PIN o_data[3]
    DIRECTION OUTPUT ;
    USE SIGNAL ;
    PORT
      LAYER M4 ;
        RECT  0 195.312 0.084 195.336 ;
    END
  END o_data[3]
  PIN o_data[40]
    DIRECTION OUTPUT ;
    USE SIGNAL ;
    PORT
      LAYER M4 ;
        RECT  0 161.232 0.084 161.256 ;
    END
  END o_data[40]
  PIN o_data[41]
    DIRECTION OUTPUT ;
    USE SIGNAL ;
    PORT
      LAYER M4 ;
        RECT  0 161.328 0.084 161.352 ;
    END
  END o_data[41]
  PIN o_data[42]
    DIRECTION OUTPUT ;
    USE SIGNAL ;
    PORT
      LAYER M4 ;
        RECT  0 161.424 0.084 161.448 ;
    END
  END o_data[42]
  PIN o_data[43]
    DIRECTION OUTPUT ;
    USE SIGNAL ;
    PORT
      LAYER M4 ;
        RECT  0 161.52 0.084 161.544 ;
    END
  END o_data[43]
  PIN o_data[44]
    DIRECTION OUTPUT ;
    USE SIGNAL ;
    PORT
      LAYER M4 ;
        RECT  0 161.616 0.084 161.64 ;
    END
  END o_data[44]
  PIN o_data[45]
    DIRECTION OUTPUT ;
    USE SIGNAL ;
    PORT
      LAYER M4 ;
        RECT  0 161.712 0.084 161.736 ;
    END
  END o_data[45]
  PIN o_data[46]
    DIRECTION OUTPUT ;
    USE SIGNAL ;
    PORT
      LAYER M4 ;
        RECT  0 161.808 0.084 161.832 ;
    END
  END o_data[46]
  PIN o_data[47]
    DIRECTION OUTPUT ;
    USE SIGNAL ;
    PORT
      LAYER M4 ;
        RECT  0 161.904 0.084 161.928 ;
    END
  END o_data[47]
  PIN o_data[48]
    DIRECTION OUTPUT ;
    USE SIGNAL ;
    PORT
      LAYER M4 ;
        RECT  0 162 0.084 162.024 ;
    END
  END o_data[48]
  PIN o_data[49]
    DIRECTION OUTPUT ;
    USE SIGNAL ;
    PORT
      LAYER M4 ;
        RECT  0 162.096 0.084 162.12 ;
    END
  END o_data[49]
  PIN o_data[4]
    DIRECTION OUTPUT ;
    USE SIGNAL ;
    PORT
      LAYER M4 ;
        RECT  0 195.408 0.084 195.432 ;
    END
  END o_data[4]
  PIN o_data[50]
    DIRECTION OUTPUT ;
    USE SIGNAL ;
    PORT
      LAYER M4 ;
        RECT  0 162.192 0.084 162.216 ;
    END
  END o_data[50]
  PIN o_data[51]
    DIRECTION OUTPUT ;
    USE SIGNAL ;
    PORT
      LAYER M4 ;
        RECT  0 162.288 0.084 162.312 ;
    END
  END o_data[51]
  PIN o_data[52]
    DIRECTION OUTPUT ;
    USE SIGNAL ;
    PORT
      LAYER M4 ;
        RECT  0 162.384 0.084 162.408 ;
    END
  END o_data[52]
  PIN o_data[53]
    DIRECTION OUTPUT ;
    USE SIGNAL ;
    PORT
      LAYER M4 ;
        RECT  0 162.48 0.084 162.504 ;
    END
  END o_data[53]
  PIN o_data[54]
    DIRECTION OUTPUT ;
    USE SIGNAL ;
    PORT
      LAYER M4 ;
        RECT  0 162.576 0.084 162.6 ;
    END
  END o_data[54]
  PIN o_data[55]
    DIRECTION OUTPUT ;
    USE SIGNAL ;
    PORT
      LAYER M4 ;
        RECT  0 162.672 0.084 162.696 ;
    END
  END o_data[55]
  PIN o_data[56]
    DIRECTION OUTPUT ;
    USE SIGNAL ;
    PORT
      LAYER M4 ;
        RECT  0 162.768 0.084 162.792 ;
    END
  END o_data[56]
  PIN o_data[57]
    DIRECTION OUTPUT ;
    USE SIGNAL ;
    PORT
      LAYER M4 ;
        RECT  0 162.864 0.084 162.888 ;
    END
  END o_data[57]
  PIN o_data[58]
    DIRECTION OUTPUT ;
    USE SIGNAL ;
    PORT
      LAYER M4 ;
        RECT  0 162.96 0.084 162.984 ;
    END
  END o_data[58]
  PIN o_data[59]
    DIRECTION OUTPUT ;
    USE SIGNAL ;
    PORT
      LAYER M4 ;
        RECT  0 163.056 0.084 163.08 ;
    END
  END o_data[59]
  PIN o_data[5]
    DIRECTION OUTPUT ;
    USE SIGNAL ;
    PORT
      LAYER M4 ;
        RECT  0 195.504 0.084 195.528 ;
    END
  END o_data[5]
  PIN o_data[60]
    DIRECTION OUTPUT ;
    USE SIGNAL ;
    PORT
      LAYER M4 ;
        RECT  0 163.152 0.084 163.176 ;
    END
  END o_data[60]
  PIN o_data[61]
    DIRECTION OUTPUT ;
    USE SIGNAL ;
    PORT
      LAYER M4 ;
        RECT  0 163.248 0.084 163.272 ;
    END
  END o_data[61]
  PIN o_data[62]
    DIRECTION OUTPUT ;
    USE SIGNAL ;
    PORT
      LAYER M4 ;
        RECT  0 163.344 0.084 163.368 ;
    END
  END o_data[62]
  PIN o_data[63]
    DIRECTION OUTPUT ;
    USE SIGNAL ;
    PORT
      LAYER M4 ;
        RECT  0 163.44 0.084 163.464 ;
    END
  END o_data[63]
  PIN o_data[64]
    DIRECTION OUTPUT ;
    USE SIGNAL ;
    PORT
      LAYER M4 ;
        RECT  0 163.536 0.084 163.56 ;
    END
  END o_data[64]
  PIN o_data[65]
    DIRECTION OUTPUT ;
    USE SIGNAL ;
    PORT
      LAYER M4 ;
        RECT  0 163.632 0.084 163.656 ;
    END
  END o_data[65]
  PIN o_data[66]
    DIRECTION OUTPUT ;
    USE SIGNAL ;
    PORT
      LAYER M4 ;
        RECT  0 163.728 0.084 163.752 ;
    END
  END o_data[66]
  PIN o_data[67]
    DIRECTION OUTPUT ;
    USE SIGNAL ;
    PORT
      LAYER M4 ;
        RECT  0 163.824 0.084 163.848 ;
    END
  END o_data[67]
  PIN o_data[68]
    DIRECTION OUTPUT ;
    USE SIGNAL ;
    PORT
      LAYER M4 ;
        RECT  0 163.92 0.084 163.944 ;
    END
  END o_data[68]
  PIN o_data[69]
    DIRECTION OUTPUT ;
    USE SIGNAL ;
    PORT
      LAYER M4 ;
        RECT  0 164.016 0.084 164.04 ;
    END
  END o_data[69]
  PIN o_data[6]
    DIRECTION OUTPUT ;
    USE SIGNAL ;
    PORT
      LAYER M4 ;
        RECT  0 195.6 0.084 195.624 ;
    END
  END o_data[6]
  PIN o_data[70]
    DIRECTION OUTPUT ;
    USE SIGNAL ;
    PORT
      LAYER M4 ;
        RECT  0 164.112 0.084 164.136 ;
    END
  END o_data[70]
  PIN o_data[71]
    DIRECTION OUTPUT ;
    USE SIGNAL ;
    PORT
      LAYER M4 ;
        RECT  0 164.208 0.084 164.232 ;
    END
  END o_data[71]
  PIN o_data[72]
    DIRECTION OUTPUT ;
    USE SIGNAL ;
    PORT
      LAYER M4 ;
        RECT  0 164.304 0.084 164.328 ;
    END
  END o_data[72]
  PIN o_data[73]
    DIRECTION OUTPUT ;
    USE SIGNAL ;
    PORT
      LAYER M4 ;
        RECT  0 164.4 0.084 164.424 ;
    END
  END o_data[73]
  PIN o_data[74]
    DIRECTION OUTPUT ;
    USE SIGNAL ;
    PORT
      LAYER M4 ;
        RECT  0 164.496 0.084 164.52 ;
    END
  END o_data[74]
  PIN o_data[75]
    DIRECTION OUTPUT ;
    USE SIGNAL ;
    PORT
      LAYER M4 ;
        RECT  0 164.592 0.084 164.616 ;
    END
  END o_data[75]
  PIN o_data[76]
    DIRECTION OUTPUT ;
    USE SIGNAL ;
    PORT
      LAYER M4 ;
        RECT  0 164.688 0.084 164.712 ;
    END
  END o_data[76]
  PIN o_data[77]
    DIRECTION OUTPUT ;
    USE SIGNAL ;
    PORT
      LAYER M4 ;
        RECT  0 164.784 0.084 164.808 ;
    END
  END o_data[77]
  PIN o_data[78]
    DIRECTION OUTPUT ;
    USE SIGNAL ;
    PORT
      LAYER M4 ;
        RECT  0 164.88 0.084 164.904 ;
    END
  END o_data[78]
  PIN o_data[79]
    DIRECTION OUTPUT ;
    USE SIGNAL ;
    PORT
      LAYER M4 ;
        RECT  0 164.976 0.084 165 ;
    END
  END o_data[79]
  PIN o_data[7]
    DIRECTION OUTPUT ;
    USE SIGNAL ;
    PORT
      LAYER M4 ;
        RECT  0 195.696 0.084 195.72 ;
    END
  END o_data[7]
  PIN o_data[80]
    DIRECTION OUTPUT ;
    USE SIGNAL ;
    PORT
      LAYER M4 ;
        RECT  0 165.072 0.084 165.096 ;
    END
  END o_data[80]
  PIN o_data[81]
    DIRECTION OUTPUT ;
    USE SIGNAL ;
    PORT
      LAYER M4 ;
        RECT  0 165.168 0.084 165.192 ;
    END
  END o_data[81]
  PIN o_data[82]
    DIRECTION OUTPUT ;
    USE SIGNAL ;
    PORT
      LAYER M4 ;
        RECT  0 165.264 0.084 165.288 ;
    END
  END o_data[82]
  PIN o_data[83]
    DIRECTION OUTPUT ;
    USE SIGNAL ;
    PORT
      LAYER M4 ;
        RECT  0 165.36 0.084 165.384 ;
    END
  END o_data[83]
  PIN o_data[84]
    DIRECTION OUTPUT ;
    USE SIGNAL ;
    PORT
      LAYER M4 ;
        RECT  0 165.456 0.084 165.48 ;
    END
  END o_data[84]
  PIN o_data[85]
    DIRECTION OUTPUT ;
    USE SIGNAL ;
    PORT
      LAYER M4 ;
        RECT  0 165.552 0.084 165.576 ;
    END
  END o_data[85]
  PIN o_data[86]
    DIRECTION OUTPUT ;
    USE SIGNAL ;
    PORT
      LAYER M4 ;
        RECT  0 165.648 0.084 165.672 ;
    END
  END o_data[86]
  PIN o_data[87]
    DIRECTION OUTPUT ;
    USE SIGNAL ;
    PORT
      LAYER M4 ;
        RECT  0 165.744 0.084 165.768 ;
    END
  END o_data[87]
  PIN o_data[88]
    DIRECTION OUTPUT ;
    USE SIGNAL ;
    PORT
      LAYER M4 ;
        RECT  0 165.84 0.084 165.864 ;
    END
  END o_data[88]
  PIN o_data[89]
    DIRECTION OUTPUT ;
    USE SIGNAL ;
    PORT
      LAYER M4 ;
        RECT  0 165.936 0.084 165.96 ;
    END
  END o_data[89]
  PIN o_data[8]
    DIRECTION OUTPUT ;
    USE SIGNAL ;
    PORT
      LAYER M4 ;
        RECT  0 195.792 0.084 195.816 ;
    END
  END o_data[8]
  PIN o_data[90]
    DIRECTION OUTPUT ;
    USE SIGNAL ;
    PORT
      LAYER M4 ;
        RECT  0 166.032 0.084 166.056 ;
    END
  END o_data[90]
  PIN o_data[91]
    DIRECTION OUTPUT ;
    USE SIGNAL ;
    PORT
      LAYER M4 ;
        RECT  0 166.128 0.084 166.152 ;
    END
  END o_data[91]
  PIN o_data[92]
    DIRECTION OUTPUT ;
    USE SIGNAL ;
    PORT
      LAYER M4 ;
        RECT  0 166.224 0.084 166.248 ;
    END
  END o_data[92]
  PIN o_data[93]
    DIRECTION OUTPUT ;
    USE SIGNAL ;
    PORT
      LAYER M4 ;
        RECT  0 166.32 0.084 166.344 ;
    END
  END o_data[93]
  PIN o_data[94]
    DIRECTION OUTPUT ;
    USE SIGNAL ;
    PORT
      LAYER M4 ;
        RECT  0 166.416 0.084 166.44 ;
    END
  END o_data[94]
  PIN o_data[95]
    DIRECTION OUTPUT ;
    USE SIGNAL ;
    PORT
      LAYER M4 ;
        RECT  0 166.512 0.084 166.536 ;
    END
  END o_data[95]
  PIN o_data[96]
    DIRECTION OUTPUT ;
    USE SIGNAL ;
    PORT
      LAYER M4 ;
        RECT  0 166.608 0.084 166.632 ;
    END
  END o_data[96]
  PIN o_data[97]
    DIRECTION OUTPUT ;
    USE SIGNAL ;
    PORT
      LAYER M4 ;
        RECT  0 166.704 0.084 166.728 ;
    END
  END o_data[97]
  PIN o_data[98]
    DIRECTION OUTPUT ;
    USE SIGNAL ;
    PORT
      LAYER M4 ;
        RECT  0 166.8 0.084 166.824 ;
    END
  END o_data[98]
  PIN o_data[99]
    DIRECTION OUTPUT ;
    USE SIGNAL ;
    PORT
      LAYER M4 ;
        RECT  0 166.896 0.084 166.92 ;
    END
  END o_data[99]
  PIN o_data[9]
    DIRECTION OUTPUT ;
    USE SIGNAL ;
    PORT
      LAYER M4 ;
        RECT  0 195.888 0.084 195.912 ;
    END
  END o_data[9]
  PIN o_drop
    DIRECTION OUTPUT ;
    USE SIGNAL ;
    PORT
      LAYER M4 ;
        RECT  0 198.864 0.084 198.888 ;
    END
  END o_drop
  PIN o_isk
    DIRECTION OUTPUT ;
    USE SIGNAL ;
    PORT
      LAYER M4 ;
        RECT  0 198.96 0.084 198.984 ;
    END
  END o_isk
  PIN o_loc0[0]
    DIRECTION OUTPUT ;
    USE SIGNAL ;
    PORT
      LAYER M4 ;
        RECT  0 199.056 0.084 199.08 ;
    END
  END o_loc0[0]
  PIN o_loc0[1]
    DIRECTION OUTPUT ;
    USE SIGNAL ;
    PORT
      LAYER M4 ;
        RECT  0 199.152 0.084 199.176 ;
    END
  END o_loc0[1]
  PIN o_loc0[2]
    DIRECTION OUTPUT ;
    USE SIGNAL ;
    PORT
      LAYER M4 ;
        RECT  0 199.248 0.084 199.272 ;
    END
  END o_loc0[2]
  PIN o_loc0[3]
    DIRECTION OUTPUT ;
    USE SIGNAL ;
    PORT
      LAYER M4 ;
        RECT  0 199.344 0.084 199.368 ;
    END
  END o_loc0[3]
  PIN o_loc0[4]
    DIRECTION OUTPUT ;
    USE SIGNAL ;
    PORT
      LAYER M4 ;
        RECT  0 199.44 0.084 199.464 ;
    END
  END o_loc0[4]
  PIN o_loc0[5]
    DIRECTION OUTPUT ;
    USE SIGNAL ;
    PORT
      LAYER M4 ;
        RECT  0 199.536 0.084 199.56 ;
    END
  END o_loc0[5]
  PIN o_loc0[6]
    DIRECTION OUTPUT ;
    USE SIGNAL ;
    PORT
      LAYER M4 ;
        RECT  0 199.632 0.084 199.656 ;
    END
  END o_loc0[6]
  PIN o_loc1[0]
    DIRECTION OUTPUT ;
    USE SIGNAL ;
    PORT
      LAYER M4 ;
        RECT  0 199.728 0.084 199.752 ;
    END
  END o_loc1[0]
  PIN o_loc1[1]
    DIRECTION OUTPUT ;
    USE SIGNAL ;
    PORT
      LAYER M4 ;
        RECT  0 199.824 0.084 199.848 ;
    END
  END o_loc1[1]
  PIN o_loc1[2]
    DIRECTION OUTPUT ;
    USE SIGNAL ;
    PORT
      LAYER M4 ;
        RECT  0 199.92 0.084 199.944 ;
    END
  END o_loc1[2]
  PIN o_loc1[3]
    DIRECTION OUTPUT ;
    USE SIGNAL ;
    PORT
      LAYER M4 ;
        RECT  0 200.016 0.084 200.04 ;
    END
  END o_loc1[3]
  PIN o_loc1[4]
    DIRECTION OUTPUT ;
    USE SIGNAL ;
    PORT
      LAYER M4 ;
        RECT  0 200.112 0.084 200.136 ;
    END
  END o_loc1[4]
  PIN o_loc1[5]
    DIRECTION OUTPUT ;
    USE SIGNAL ;
    PORT
      LAYER M4 ;
        RECT  0 200.208 0.084 200.232 ;
    END
  END o_loc1[5]
  PIN o_loc1[6]
    DIRECTION OUTPUT ;
    USE SIGNAL ;
    PORT
      LAYER M4 ;
        RECT  0 200.304 0.084 200.328 ;
    END
  END o_loc1[6]
  PIN o_n[0]
    DIRECTION OUTPUT ;
    USE SIGNAL ;
    PORT
      LAYER M4 ;
        RECT  0 200.4 0.084 200.424 ;
    END
  END o_n[0]
  PIN o_n[1]
    DIRECTION OUTPUT ;
    USE SIGNAL ;
    PORT
      LAYER M4 ;
        RECT  0 200.496 0.084 200.52 ;
    END
  END o_n[1]
  PIN o_sel0[0]
    DIRECTION OUTPUT ;
    USE SIGNAL ;
    PORT
      LAYER M4 ;
        RECT  0 200.592 0.084 200.616 ;
    END
  END o_sel0[0]
  PIN o_sel0[1]
    DIRECTION OUTPUT ;
    USE SIGNAL ;
    PORT
      LAYER M4 ;
        RECT  0 200.688 0.084 200.712 ;
    END
  END o_sel0[1]
  PIN o_sel1[0]
    DIRECTION OUTPUT ;
    USE SIGNAL ;
    PORT
      LAYER M4 ;
        RECT  0 200.784 0.084 200.808 ;
    END
  END o_sel1[0]
  PIN o_sel1[1]
    DIRECTION OUTPUT ;
    USE SIGNAL ;
    PORT
      LAYER M4 ;
        RECT  0 200.88 0.084 200.904 ;
    END
  END o_sel1[1]
  PIN o_tail
    DIRECTION OUTPUT ;
    USE SIGNAL ;
    PORT
      LAYER M4 ;
        RECT  0 200.976 0.084 201 ;
    END
  END o_tail
  PIN o_tail_lanes[0]
    DIRECTION OUTPUT ;
    USE SIGNAL ;
    PORT
      LAYER M4 ;
        RECT  0 201.072 0.084 201.096 ;
    END
  END o_tail_lanes[0]
  PIN o_tail_lanes[1]
    DIRECTION OUTPUT ;
    USE SIGNAL ;
    PORT
      LAYER M4 ;
        RECT  0 201.168 0.084 201.192 ;
    END
  END o_tail_lanes[1]
  PIN o_tail_lanes[2]
    DIRECTION OUTPUT ;
    USE SIGNAL ;
    PORT
      LAYER M4 ;
        RECT  0 201.264 0.084 201.288 ;
    END
  END o_tail_lanes[2]
  PIN o_tail_lanes[3]
    DIRECTION OUTPUT ;
    USE SIGNAL ;
    PORT
      LAYER M4 ;
        RECT  0 201.36 0.084 201.384 ;
    END
  END o_tail_lanes[3]
  PIN o_tile0[0]
    DIRECTION OUTPUT ;
    USE SIGNAL ;
    PORT
      LAYER M4 ;
        RECT  0 201.456 0.084 201.48 ;
    END
  END o_tile0[0]
  PIN o_tile0[10]
    DIRECTION OUTPUT ;
    USE SIGNAL ;
    PORT
      LAYER M4 ;
        RECT  0 203.664 0.084 203.688 ;
    END
  END o_tile0[10]
  PIN o_tile0[1]
    DIRECTION OUTPUT ;
    USE SIGNAL ;
    PORT
      LAYER M4 ;
        RECT  0 201.552 0.084 201.576 ;
    END
  END o_tile0[1]
  PIN o_tile0[2]
    DIRECTION OUTPUT ;
    USE SIGNAL ;
    PORT
      LAYER M4 ;
        RECT  0 201.648 0.084 201.672 ;
    END
  END o_tile0[2]
  PIN o_tile0[3]
    DIRECTION OUTPUT ;
    USE SIGNAL ;
    PORT
      LAYER M4 ;
        RECT  0 201.744 0.084 201.768 ;
    END
  END o_tile0[3]
  PIN o_tile0[4]
    DIRECTION OUTPUT ;
    USE SIGNAL ;
    PORT
      LAYER M4 ;
        RECT  0 203.088 0.084 203.112 ;
    END
  END o_tile0[4]
  PIN o_tile0[5]
    DIRECTION OUTPUT ;
    USE SIGNAL ;
    PORT
      LAYER M4 ;
        RECT  0 203.184 0.084 203.208 ;
    END
  END o_tile0[5]
  PIN o_tile0[6]
    DIRECTION OUTPUT ;
    USE SIGNAL ;
    PORT
      LAYER M4 ;
        RECT  0 203.28 0.084 203.304 ;
    END
  END o_tile0[6]
  PIN o_tile0[7]
    DIRECTION OUTPUT ;
    USE SIGNAL ;
    PORT
      LAYER M4 ;
        RECT  0 203.376 0.084 203.4 ;
    END
  END o_tile0[7]
  PIN o_tile0[8]
    DIRECTION OUTPUT ;
    USE SIGNAL ;
    PORT
      LAYER M4 ;
        RECT  0 203.472 0.084 203.496 ;
    END
  END o_tile0[8]
  PIN o_tile0[9]
    DIRECTION OUTPUT ;
    USE SIGNAL ;
    PORT
      LAYER M4 ;
        RECT  0 203.568 0.084 203.592 ;
    END
  END o_tile0[9]
  PIN o_tile1[0]
    DIRECTION OUTPUT ;
    USE SIGNAL ;
    PORT
      LAYER M4 ;
        RECT  0 203.76 0.084 203.784 ;
    END
  END o_tile1[0]
  PIN o_tile1[10]
    DIRECTION OUTPUT ;
    USE SIGNAL ;
    PORT
      LAYER M4 ;
        RECT  0 204.72 0.084 204.744 ;
    END
  END o_tile1[10]
  PIN o_tile1[1]
    DIRECTION OUTPUT ;
    USE SIGNAL ;
    PORT
      LAYER M4 ;
        RECT  0 203.856 0.084 203.88 ;
    END
  END o_tile1[1]
  PIN o_tile1[2]
    DIRECTION OUTPUT ;
    USE SIGNAL ;
    PORT
      LAYER M4 ;
        RECT  0 203.952 0.084 203.976 ;
    END
  END o_tile1[2]
  PIN o_tile1[3]
    DIRECTION OUTPUT ;
    USE SIGNAL ;
    PORT
      LAYER M4 ;
        RECT  0 204.048 0.084 204.072 ;
    END
  END o_tile1[3]
  PIN o_tile1[4]
    DIRECTION OUTPUT ;
    USE SIGNAL ;
    PORT
      LAYER M4 ;
        RECT  0 204.144 0.084 204.168 ;
    END
  END o_tile1[4]
  PIN o_tile1[5]
    DIRECTION OUTPUT ;
    USE SIGNAL ;
    PORT
      LAYER M4 ;
        RECT  0 204.24 0.084 204.264 ;
    END
  END o_tile1[5]
  PIN o_tile1[6]
    DIRECTION OUTPUT ;
    USE SIGNAL ;
    PORT
      LAYER M4 ;
        RECT  0 204.336 0.084 204.36 ;
    END
  END o_tile1[6]
  PIN o_tile1[7]
    DIRECTION OUTPUT ;
    USE SIGNAL ;
    PORT
      LAYER M4 ;
        RECT  0 204.432 0.084 204.456 ;
    END
  END o_tile1[7]
  PIN o_tile1[8]
    DIRECTION OUTPUT ;
    USE SIGNAL ;
    PORT
      LAYER M4 ;
        RECT  0 204.528 0.084 204.552 ;
    END
  END o_tile1[8]
  PIN o_tile1[9]
    DIRECTION OUTPUT ;
    USE SIGNAL ;
    PORT
      LAYER M4 ;
        RECT  0 204.624 0.084 204.648 ;
    END
  END o_tile1[9]
  PIN o_v
    DIRECTION OUTPUT ;
    USE SIGNAL ;
    PORT
      LAYER M4 ;
        RECT  0 204.816 0.084 204.84 ;
    END
  END o_v
  PIN rst_n
    DIRECTION INPUT ;
    USE SIGNAL ;
    PORT
      LAYER M5 ;
        RECT  169.104 371.436 169.128 371.52 ;
    END
  END rst_n
  PIN VDD
    DIRECTION INOUT ;
    USE POWER ;
    PORT
      LAYER M5 ;
        RECT  321.192 2.151 321.312 369.369 ;
        RECT  315.792 2.151 315.912 369.369 ;
        RECT  310.392 2.151 310.512 369.369 ;
        RECT  304.992 2.151 305.112 369.369 ;
        RECT  299.592 2.151 299.712 369.369 ;
        RECT  294.192 2.151 294.312 369.369 ;
        RECT  288.792 2.151 288.912 369.369 ;
        RECT  283.392 2.151 283.512 369.369 ;
        RECT  277.992 2.151 278.112 369.369 ;
        RECT  272.592 2.151 272.712 369.369 ;
        RECT  267.192 2.151 267.312 369.369 ;
        RECT  261.792 2.151 261.912 369.369 ;
        RECT  256.392 2.151 256.512 369.369 ;
        RECT  250.992 2.151 251.112 369.369 ;
        RECT  245.592 2.151 245.712 369.369 ;
        RECT  240.192 2.151 240.312 369.369 ;
        RECT  234.792 2.151 234.912 369.369 ;
        RECT  229.392 2.151 229.512 369.369 ;
        RECT  223.992 2.151 224.112 369.369 ;
        RECT  218.592 2.151 218.712 369.369 ;
        RECT  213.192 2.151 213.312 369.369 ;
        RECT  207.792 2.151 207.912 369.369 ;
        RECT  202.392 2.151 202.512 369.369 ;
        RECT  196.992 2.151 197.112 369.369 ;
        RECT  191.592 2.151 191.712 369.369 ;
        RECT  186.192 2.151 186.312 369.369 ;
        RECT  180.792 2.151 180.912 369.369 ;
        RECT  175.392 2.151 175.512 369.369 ;
        RECT  169.992 2.151 170.112 369.369 ;
        RECT  164.592 2.151 164.712 369.369 ;
        RECT  159.192 2.151 159.312 369.369 ;
        RECT  153.792 2.151 153.912 369.369 ;
        RECT  148.392 2.151 148.512 369.369 ;
        RECT  142.992 2.151 143.112 369.369 ;
        RECT  137.592 2.151 137.712 369.369 ;
        RECT  132.192 2.151 132.312 369.369 ;
        RECT  126.792 2.151 126.912 369.369 ;
        RECT  121.392 2.151 121.512 369.369 ;
        RECT  115.992 2.151 116.112 369.369 ;
        RECT  110.592 2.151 110.712 369.369 ;
        RECT  105.192 2.151 105.312 369.369 ;
        RECT  99.792 2.151 99.912 369.369 ;
        RECT  94.392 2.151 94.512 369.369 ;
        RECT  88.992 2.151 89.112 369.369 ;
        RECT  83.592 2.151 83.712 369.369 ;
        RECT  78.192 2.151 78.312 369.369 ;
        RECT  72.792 2.151 72.912 369.369 ;
        RECT  67.392 2.151 67.512 369.369 ;
        RECT  61.992 2.151 62.112 369.369 ;
        RECT  56.592 2.151 56.712 369.369 ;
        RECT  51.192 2.151 51.312 369.369 ;
        RECT  45.792 2.151 45.912 369.369 ;
        RECT  40.392 2.151 40.512 369.369 ;
        RECT  34.992 2.151 35.112 369.369 ;
        RECT  29.592 2.151 29.712 369.369 ;
        RECT  24.192 2.151 24.312 369.369 ;
        RECT  18.792 2.151 18.912 369.369 ;
        RECT  13.392 2.151 13.512 369.369 ;
        RECT  7.992 2.151 8.112 369.369 ;
        RECT  2.592 2.151 2.712 369.369 ;
    END
  END VDD
  PIN VSS
    DIRECTION INOUT ;
    USE GROUND ;
    PORT
      LAYER M5 ;
        RECT  321 2.137 321.12 369.383 ;
        RECT  315.6 2.137 315.72 369.383 ;
        RECT  310.2 2.137 310.32 369.383 ;
        RECT  304.8 2.137 304.92 369.383 ;
        RECT  299.4 2.137 299.52 369.383 ;
        RECT  294 2.137 294.12 369.383 ;
        RECT  288.6 2.137 288.72 369.383 ;
        RECT  283.2 2.137 283.32 369.383 ;
        RECT  277.8 2.137 277.92 369.383 ;
        RECT  272.4 2.137 272.52 369.383 ;
        RECT  267 2.137 267.12 369.383 ;
        RECT  261.6 2.137 261.72 369.383 ;
        RECT  256.2 2.137 256.32 369.383 ;
        RECT  250.8 2.137 250.92 369.383 ;
        RECT  245.4 2.137 245.52 369.383 ;
        RECT  240 2.137 240.12 369.383 ;
        RECT  234.6 2.137 234.72 369.383 ;
        RECT  229.2 2.137 229.32 369.383 ;
        RECT  223.8 2.137 223.92 369.383 ;
        RECT  218.4 2.137 218.52 369.383 ;
        RECT  213 2.137 213.12 369.383 ;
        RECT  207.6 2.137 207.72 369.383 ;
        RECT  202.2 2.137 202.32 369.383 ;
        RECT  196.8 2.137 196.92 369.383 ;
        RECT  191.4 2.137 191.52 369.383 ;
        RECT  186 2.137 186.12 369.383 ;
        RECT  180.6 2.137 180.72 369.383 ;
        RECT  175.2 2.137 175.32 369.383 ;
        RECT  169.8 2.137 169.92 369.383 ;
        RECT  164.4 2.137 164.52 369.383 ;
        RECT  159 2.137 159.12 369.383 ;
        RECT  153.6 2.137 153.72 369.383 ;
        RECT  148.2 2.137 148.32 369.383 ;
        RECT  142.8 2.137 142.92 369.383 ;
        RECT  137.4 2.137 137.52 369.383 ;
        RECT  132 2.137 132.12 369.383 ;
        RECT  126.6 2.137 126.72 369.383 ;
        RECT  121.2 2.137 121.32 369.383 ;
        RECT  115.8 2.137 115.92 369.383 ;
        RECT  110.4 2.137 110.52 369.383 ;
        RECT  105 2.137 105.12 369.383 ;
        RECT  99.6 2.137 99.72 369.383 ;
        RECT  94.2 2.137 94.32 369.383 ;
        RECT  88.8 2.137 88.92 369.383 ;
        RECT  83.4 2.137 83.52 369.383 ;
        RECT  78 2.137 78.12 369.383 ;
        RECT  72.6 2.137 72.72 369.383 ;
        RECT  67.2 2.137 67.32 369.383 ;
        RECT  61.8 2.137 61.92 369.383 ;
        RECT  56.4 2.137 56.52 369.383 ;
        RECT  51 2.137 51.12 369.383 ;
        RECT  45.6 2.137 45.72 369.383 ;
        RECT  40.2 2.137 40.32 369.383 ;
        RECT  34.8 2.137 34.92 369.383 ;
        RECT  29.4 2.137 29.52 369.383 ;
        RECT  24 2.137 24.12 369.383 ;
        RECT  18.6 2.137 18.72 369.383 ;
        RECT  13.2 2.137 13.32 369.383 ;
        RECT  7.8 2.137 7.92 369.383 ;
        RECT  2.4 2.137 2.52 369.383 ;
    END
  END VSS
  OBS
    LAYER RVTN ;
     RECT  2.16 2.16 326.16 2.295 ;
     RECT  2.16 2.565 326.16 2.835 ;
     RECT  2.16 3.105 326.16 3.375 ;
     RECT  2.16 3.645 326.16 3.915 ;
     RECT  2.16 4.185 326.16 4.455 ;
     RECT  2.16 4.725 326.16 4.995 ;
     RECT  2.16 5.265 326.16 5.535 ;
     RECT  2.16 5.805 326.16 6.075 ;
     RECT  2.16 6.345 326.16 6.615 ;
     RECT  2.16 6.885 326.16 7.155 ;
     RECT  2.16 7.425 326.16 7.695 ;
     RECT  2.16 7.965 326.16 8.235 ;
     RECT  2.16 8.505 326.16 8.775 ;
     RECT  2.16 9.045 326.16 9.315 ;
     RECT  2.16 9.585 326.16 9.855 ;
     RECT  2.16 10.125 326.16 10.395 ;
     RECT  2.16 10.665 326.16 10.935 ;
     RECT  2.16 11.205 326.16 11.475 ;
     RECT  2.16 11.745 326.16 12.015 ;
     RECT  2.16 12.285 326.16 12.555 ;
     RECT  2.16 12.825 326.16 13.095 ;
     RECT  2.16 13.365 326.16 13.635 ;
     RECT  2.16 13.905 326.16 14.175 ;
     RECT  2.16 14.445 326.16 14.715 ;
     RECT  2.16 14.985 326.16 15.255 ;
     RECT  2.16 15.525 326.16 15.795 ;
     RECT  2.16 16.065 326.16 16.335 ;
     RECT  2.16 16.605 326.16 16.875 ;
     RECT  2.16 17.145 326.16 17.415 ;
     RECT  2.16 17.685 326.16 17.955 ;
     RECT  2.16 18.225 326.16 18.495 ;
     RECT  2.16 18.765 326.16 19.035 ;
     RECT  2.16 19.305 326.16 19.575 ;
     RECT  2.16 19.845 326.16 20.115 ;
     RECT  2.16 20.385 326.16 20.655 ;
     RECT  2.16 20.925 326.16 21.195 ;
     RECT  2.16 21.465 326.16 21.735 ;
     RECT  2.16 22.005 326.16 22.275 ;
     RECT  2.16 22.545 326.16 22.815 ;
     RECT  2.16 23.085 326.16 23.355 ;
     RECT  2.16 23.625 326.16 23.895 ;
     RECT  2.16 24.165 326.16 24.435 ;
     RECT  2.16 24.705 326.16 24.975 ;
     RECT  2.16 25.245 326.16 25.515 ;
     RECT  2.16 25.785 326.16 26.055 ;
     RECT  2.16 26.325 326.16 26.595 ;
     RECT  2.16 26.865 326.16 27.135 ;
     RECT  2.16 27.405 326.16 27.675 ;
     RECT  2.16 27.945 326.16 28.215 ;
     RECT  2.16 28.485 326.16 28.755 ;
     RECT  2.16 29.025 326.16 29.295 ;
     RECT  2.16 29.565 326.16 29.835 ;
     RECT  2.16 30.105 326.16 30.375 ;
     RECT  2.16 30.645 326.16 30.915 ;
     RECT  2.16 31.185 326.16 31.455 ;
     RECT  2.16 31.725 326.16 31.995 ;
     RECT  2.16 32.265 326.16 32.535 ;
     RECT  2.16 32.805 326.16 33.075 ;
     RECT  2.16 33.345 326.16 33.615 ;
     RECT  2.16 33.885 326.16 34.155 ;
     RECT  2.16 34.425 326.16 34.695 ;
     RECT  2.16 34.965 326.16 35.235 ;
     RECT  2.16 35.505 326.16 35.775 ;
     RECT  2.16 36.045 326.16 36.315 ;
     RECT  2.16 36.585 326.16 36.855 ;
     RECT  2.16 37.125 326.16 37.395 ;
     RECT  2.16 37.665 326.16 37.935 ;
     RECT  2.16 38.205 326.16 38.475 ;
     RECT  2.16 38.745 326.16 39.015 ;
     RECT  2.16 39.285 326.16 39.555 ;
     RECT  2.16 39.825 326.16 40.095 ;
     RECT  2.16 40.365 326.16 40.635 ;
     RECT  2.16 40.905 326.16 41.175 ;
     RECT  2.16 41.445 326.16 41.715 ;
     RECT  2.16 41.985 326.16 42.255 ;
     RECT  2.16 42.525 326.16 42.795 ;
     RECT  2.16 43.065 326.16 43.335 ;
     RECT  2.16 43.605 326.16 43.875 ;
     RECT  2.16 44.145 326.16 44.415 ;
     RECT  2.16 44.685 326.16 44.955 ;
     RECT  2.16 45.225 326.16 45.495 ;
     RECT  2.16 45.765 326.16 46.035 ;
     RECT  2.16 46.305 326.16 46.575 ;
     RECT  2.16 46.845 326.16 47.115 ;
     RECT  2.16 47.385 326.16 47.655 ;
     RECT  2.16 47.925 326.16 48.195 ;
     RECT  2.16 48.465 326.16 48.735 ;
     RECT  2.16 49.005 326.16 49.275 ;
     RECT  2.16 49.545 326.16 49.815 ;
     RECT  2.16 50.085 326.16 50.355 ;
     RECT  2.16 50.625 326.16 50.895 ;
     RECT  2.16 51.165 326.16 51.435 ;
     RECT  2.16 51.705 326.16 51.975 ;
     RECT  2.16 52.245 326.16 52.515 ;
     RECT  2.16 52.785 326.16 53.055 ;
     RECT  2.16 53.325 326.16 53.595 ;
     RECT  2.16 53.865 326.16 54.135 ;
     RECT  2.16 54.405 326.16 54.675 ;
     RECT  2.16 54.945 326.16 55.215 ;
     RECT  2.16 55.485 326.16 55.755 ;
     RECT  2.16 56.025 326.16 56.295 ;
     RECT  2.16 56.565 326.16 56.835 ;
     RECT  2.16 57.105 326.16 57.375 ;
     RECT  2.16 57.645 326.16 57.915 ;
     RECT  2.16 58.185 326.16 58.455 ;
     RECT  2.16 58.725 326.16 58.995 ;
     RECT  2.16 59.265 326.16 59.535 ;
     RECT  2.16 59.805 326.16 60.075 ;
     RECT  2.16 60.345 326.16 60.615 ;
     RECT  2.16 60.885 326.16 61.155 ;
     RECT  2.16 61.425 326.16 61.695 ;
     RECT  2.16 61.965 326.16 62.235 ;
     RECT  2.16 62.505 326.16 62.775 ;
     RECT  2.16 63.045 326.16 63.315 ;
     RECT  2.16 63.585 326.16 63.855 ;
     RECT  2.16 64.125 326.16 64.395 ;
     RECT  2.16 64.665 326.16 64.935 ;
     RECT  2.16 65.205 326.16 65.475 ;
     RECT  2.16 65.745 326.16 66.015 ;
     RECT  2.16 66.285 326.16 66.555 ;
     RECT  2.16 66.825 326.16 67.095 ;
     RECT  2.16 67.365 326.16 67.635 ;
     RECT  2.16 67.905 326.16 68.175 ;
     RECT  2.16 68.445 326.16 68.715 ;
     RECT  2.16 68.985 326.16 69.255 ;
     RECT  2.16 69.525 326.16 69.795 ;
     RECT  2.16 70.065 326.16 70.335 ;
     RECT  2.16 70.605 326.16 70.875 ;
     RECT  2.16 71.145 326.16 71.415 ;
     RECT  2.16 71.685 326.16 71.955 ;
     RECT  2.16 72.225 326.16 72.495 ;
     RECT  2.16 72.765 326.16 73.035 ;
     RECT  2.16 73.305 326.16 73.575 ;
     RECT  2.16 73.845 326.16 74.115 ;
     RECT  2.16 74.385 326.16 74.655 ;
     RECT  2.16 74.925 326.16 75.195 ;
     RECT  2.16 75.465 326.16 75.735 ;
     RECT  2.16 76.005 326.16 76.275 ;
     RECT  2.16 76.545 326.16 76.815 ;
     RECT  2.16 77.085 326.16 77.355 ;
     RECT  2.16 77.625 326.16 77.895 ;
     RECT  2.16 78.165 326.16 78.435 ;
     RECT  2.16 78.705 326.16 78.975 ;
     RECT  2.16 79.245 326.16 79.515 ;
     RECT  2.16 79.785 326.16 80.055 ;
     RECT  2.16 80.325 326.16 80.595 ;
     RECT  2.16 80.865 326.16 81.135 ;
     RECT  2.16 81.405 326.16 81.675 ;
     RECT  2.16 81.945 326.16 82.215 ;
     RECT  2.16 82.485 326.16 82.755 ;
     RECT  2.16 83.025 326.16 83.295 ;
     RECT  2.16 83.565 326.16 83.835 ;
     RECT  2.16 84.105 326.16 84.375 ;
     RECT  2.16 84.645 326.16 84.915 ;
     RECT  2.16 85.185 326.16 85.455 ;
     RECT  2.16 85.725 326.16 85.995 ;
     RECT  2.16 86.265 326.16 86.535 ;
     RECT  2.16 86.805 326.16 87.075 ;
     RECT  2.16 87.345 326.16 87.615 ;
     RECT  2.16 87.885 326.16 88.155 ;
     RECT  2.16 88.425 326.16 88.695 ;
     RECT  2.16 88.965 326.16 89.235 ;
     RECT  2.16 89.505 326.16 89.775 ;
     RECT  2.16 90.045 326.16 90.315 ;
     RECT  2.16 90.585 326.16 90.855 ;
     RECT  2.16 91.125 326.16 91.395 ;
     RECT  2.16 91.665 326.16 91.935 ;
     RECT  2.16 92.205 326.16 92.475 ;
     RECT  2.16 92.745 326.16 93.015 ;
     RECT  2.16 93.285 326.16 93.555 ;
     RECT  2.16 93.825 326.16 94.095 ;
     RECT  2.16 94.365 326.16 94.635 ;
     RECT  2.16 94.905 326.16 95.175 ;
     RECT  2.16 95.445 326.16 95.715 ;
     RECT  2.16 95.985 326.16 96.255 ;
     RECT  2.16 96.525 326.16 96.795 ;
     RECT  2.16 97.065 326.16 97.335 ;
     RECT  2.16 97.605 326.16 97.875 ;
     RECT  2.16 98.145 326.16 98.415 ;
     RECT  2.16 98.685 326.16 98.955 ;
     RECT  2.16 99.225 326.16 99.495 ;
     RECT  2.16 99.765 326.16 100.035 ;
     RECT  2.16 100.305 326.16 100.575 ;
     RECT  2.16 100.845 326.16 101.115 ;
     RECT  2.16 101.385 326.16 101.655 ;
     RECT  2.16 101.925 326.16 102.195 ;
     RECT  2.16 102.465 326.16 102.735 ;
     RECT  2.16 103.005 326.16 103.275 ;
     RECT  2.16 103.545 326.16 103.815 ;
     RECT  2.16 104.085 326.16 104.355 ;
     RECT  2.16 104.625 326.16 104.895 ;
     RECT  2.16 105.165 326.16 105.435 ;
     RECT  2.16 105.705 326.16 105.975 ;
     RECT  2.16 106.245 326.16 106.515 ;
     RECT  2.16 106.785 326.16 107.055 ;
     RECT  2.16 107.325 326.16 107.595 ;
     RECT  2.16 107.865 326.16 108.135 ;
     RECT  2.16 108.405 326.16 108.675 ;
     RECT  2.16 108.945 326.16 109.215 ;
     RECT  2.16 109.485 326.16 109.755 ;
     RECT  2.16 110.025 326.16 110.295 ;
     RECT  2.16 110.565 326.16 110.835 ;
     RECT  2.16 111.105 326.16 111.375 ;
     RECT  2.16 111.645 326.16 111.915 ;
     RECT  2.16 112.185 326.16 112.455 ;
     RECT  2.16 112.725 326.16 112.995 ;
     RECT  2.16 113.265 326.16 113.535 ;
     RECT  2.16 113.805 326.16 114.075 ;
     RECT  2.16 114.345 326.16 114.615 ;
     RECT  2.16 114.885 326.16 115.155 ;
     RECT  2.16 115.425 326.16 115.695 ;
     RECT  2.16 115.965 326.16 116.235 ;
     RECT  2.16 116.505 326.16 116.775 ;
     RECT  2.16 117.045 326.16 117.315 ;
     RECT  2.16 117.585 326.16 117.855 ;
     RECT  2.16 118.125 326.16 118.395 ;
     RECT  2.16 118.665 326.16 118.935 ;
     RECT  2.16 119.205 326.16 119.475 ;
     RECT  2.16 119.745 326.16 120.015 ;
     RECT  2.16 120.285 326.16 120.555 ;
     RECT  2.16 120.825 326.16 121.095 ;
     RECT  2.16 121.365 326.16 121.635 ;
     RECT  2.16 121.905 326.16 122.175 ;
     RECT  2.16 122.445 326.16 122.715 ;
     RECT  2.16 122.985 326.16 123.255 ;
     RECT  2.16 123.525 326.16 123.795 ;
     RECT  2.16 124.065 326.16 124.335 ;
     RECT  2.16 124.605 326.16 124.875 ;
     RECT  2.16 125.145 326.16 125.415 ;
     RECT  2.16 125.685 326.16 125.955 ;
     RECT  2.16 126.225 326.16 126.495 ;
     RECT  2.16 126.765 326.16 127.035 ;
     RECT  2.16 127.305 326.16 127.575 ;
     RECT  2.16 127.845 326.16 128.115 ;
     RECT  2.16 128.385 326.16 128.655 ;
     RECT  2.16 128.925 326.16 129.195 ;
     RECT  2.16 129.465 326.16 129.735 ;
     RECT  2.16 130.005 326.16 130.275 ;
     RECT  2.16 130.545 326.16 130.815 ;
     RECT  2.16 131.085 326.16 131.355 ;
     RECT  2.16 131.625 326.16 131.895 ;
     RECT  2.16 132.165 326.16 132.435 ;
     RECT  2.16 132.705 326.16 132.975 ;
     RECT  2.16 133.245 326.16 133.515 ;
     RECT  2.16 133.785 326.16 134.055 ;
     RECT  2.16 134.325 326.16 134.595 ;
     RECT  2.16 134.865 326.16 135.135 ;
     RECT  2.16 135.405 326.16 135.675 ;
     RECT  2.16 135.945 326.16 136.215 ;
     RECT  2.16 136.485 326.16 136.755 ;
     RECT  2.16 137.025 326.16 137.295 ;
     RECT  2.16 137.565 326.16 137.835 ;
     RECT  2.16 138.105 326.16 138.375 ;
     RECT  2.16 138.645 326.16 138.915 ;
     RECT  2.16 139.185 326.16 139.455 ;
     RECT  2.16 139.725 326.16 139.995 ;
     RECT  2.16 140.265 326.16 140.535 ;
     RECT  2.16 140.805 326.16 141.075 ;
     RECT  2.16 141.345 326.16 141.615 ;
     RECT  2.16 141.885 326.16 142.155 ;
     RECT  2.16 142.425 326.16 142.695 ;
     RECT  2.16 142.965 326.16 143.235 ;
     RECT  2.16 143.505 326.16 143.775 ;
     RECT  2.16 144.045 326.16 144.315 ;
     RECT  2.16 144.585 326.16 144.855 ;
     RECT  2.16 145.125 326.16 145.395 ;
     RECT  2.16 145.665 326.16 145.935 ;
     RECT  2.16 146.205 326.16 146.475 ;
     RECT  2.16 146.745 326.16 147.015 ;
     RECT  2.16 147.285 326.16 147.555 ;
     RECT  2.16 147.825 326.16 148.095 ;
     RECT  2.16 148.365 326.16 148.635 ;
     RECT  2.16 148.905 326.16 149.175 ;
     RECT  2.16 149.445 326.16 149.715 ;
     RECT  2.16 149.985 326.16 150.255 ;
     RECT  2.16 150.525 326.16 150.795 ;
     RECT  2.16 151.065 326.16 151.335 ;
     RECT  2.16 151.605 326.16 151.875 ;
     RECT  2.16 152.145 326.16 152.415 ;
     RECT  2.16 152.685 326.16 152.955 ;
     RECT  2.16 153.225 326.16 153.495 ;
     RECT  2.16 153.765 326.16 154.035 ;
     RECT  2.16 154.305 326.16 154.575 ;
     RECT  2.16 154.845 326.16 155.115 ;
     RECT  2.16 155.385 326.16 155.655 ;
     RECT  2.16 155.925 326.16 156.195 ;
     RECT  2.16 156.465 326.16 156.735 ;
     RECT  2.16 157.005 326.16 157.275 ;
     RECT  2.16 157.545 326.16 157.815 ;
     RECT  2.16 158.085 326.16 158.355 ;
     RECT  2.16 158.625 326.16 158.895 ;
     RECT  2.16 159.165 326.16 159.435 ;
     RECT  2.16 159.705 326.16 159.975 ;
     RECT  2.16 160.245 326.16 160.515 ;
     RECT  2.16 160.785 326.16 161.055 ;
     RECT  2.16 161.325 326.16 161.595 ;
     RECT  2.16 161.865 326.16 162.135 ;
     RECT  2.16 162.405 326.16 162.675 ;
     RECT  2.16 162.945 326.16 163.215 ;
     RECT  2.16 163.485 326.16 163.755 ;
     RECT  2.16 164.025 326.16 164.295 ;
     RECT  2.16 164.565 326.16 164.835 ;
     RECT  2.16 165.105 326.16 165.375 ;
     RECT  2.16 165.645 326.16 165.915 ;
     RECT  2.16 166.185 326.16 166.455 ;
     RECT  2.16 166.725 326.16 166.995 ;
     RECT  2.16 167.265 326.16 167.535 ;
     RECT  2.16 167.805 326.16 168.075 ;
     RECT  2.16 168.345 326.16 168.615 ;
     RECT  2.16 168.885 326.16 169.155 ;
     RECT  2.16 169.425 326.16 169.695 ;
     RECT  2.16 169.965 326.16 170.235 ;
     RECT  2.16 170.505 326.16 170.775 ;
     RECT  2.16 171.045 326.16 171.315 ;
     RECT  2.16 171.585 326.16 171.855 ;
     RECT  2.16 172.125 326.16 172.395 ;
     RECT  2.16 172.665 326.16 172.935 ;
     RECT  2.16 173.205 326.16 173.475 ;
     RECT  2.16 173.745 326.16 174.015 ;
     RECT  2.16 174.285 326.16 174.555 ;
     RECT  2.16 174.825 326.16 175.095 ;
     RECT  2.16 175.365 326.16 175.635 ;
     RECT  2.16 175.905 326.16 176.175 ;
     RECT  2.16 176.445 326.16 176.715 ;
     RECT  2.16 176.985 326.16 177.255 ;
     RECT  2.16 177.525 326.16 177.795 ;
     RECT  2.16 178.065 326.16 178.335 ;
     RECT  2.16 178.605 326.16 178.875 ;
     RECT  2.16 179.145 326.16 179.415 ;
     RECT  2.16 179.685 326.16 179.955 ;
     RECT  2.16 180.225 326.16 180.495 ;
     RECT  2.16 180.765 326.16 181.035 ;
     RECT  2.16 181.305 326.16 181.575 ;
     RECT  2.16 181.845 326.16 182.115 ;
     RECT  2.16 182.385 326.16 182.655 ;
     RECT  2.16 182.925 326.16 183.195 ;
     RECT  2.16 183.465 326.16 183.735 ;
     RECT  2.16 184.005 326.16 184.275 ;
     RECT  2.16 184.545 326.16 184.815 ;
     RECT  2.16 185.085 326.16 185.355 ;
     RECT  2.16 185.625 326.16 185.895 ;
     RECT  2.16 186.165 326.16 186.435 ;
     RECT  2.16 186.705 326.16 186.975 ;
     RECT  2.16 187.245 326.16 187.515 ;
     RECT  2.16 187.785 326.16 188.055 ;
     RECT  2.16 188.325 326.16 188.595 ;
     RECT  2.16 188.865 326.16 189.135 ;
     RECT  2.16 189.405 326.16 189.675 ;
     RECT  2.16 189.945 326.16 190.215 ;
     RECT  2.16 190.485 326.16 190.755 ;
     RECT  2.16 191.025 326.16 191.295 ;
     RECT  2.16 191.565 326.16 191.835 ;
     RECT  2.16 192.105 326.16 192.375 ;
     RECT  2.16 192.645 326.16 192.915 ;
     RECT  2.16 193.185 326.16 193.455 ;
     RECT  2.16 193.725 326.16 193.995 ;
     RECT  2.16 194.265 326.16 194.535 ;
     RECT  2.16 194.805 326.16 195.075 ;
     RECT  2.16 195.345 326.16 195.615 ;
     RECT  2.16 195.885 326.16 196.155 ;
     RECT  2.16 196.425 326.16 196.695 ;
     RECT  2.16 196.965 326.16 197.235 ;
     RECT  2.16 197.505 326.16 197.775 ;
     RECT  2.16 198.045 326.16 198.315 ;
     RECT  2.16 198.585 326.16 198.855 ;
     RECT  2.16 199.125 326.16 199.395 ;
     RECT  2.16 199.665 326.16 199.935 ;
     RECT  2.16 200.205 326.16 200.475 ;
     RECT  2.16 200.745 326.16 201.015 ;
     RECT  2.16 201.285 326.16 201.555 ;
     RECT  2.16 201.825 326.16 202.095 ;
     RECT  2.16 202.365 326.16 202.635 ;
     RECT  2.16 202.905 326.16 203.175 ;
     RECT  2.16 203.445 326.16 203.715 ;
     RECT  2.16 203.985 326.16 204.255 ;
     RECT  2.16 204.525 326.16 204.795 ;
     RECT  2.16 205.065 326.16 205.335 ;
     RECT  2.16 205.605 326.16 205.875 ;
     RECT  2.16 206.145 326.16 206.415 ;
     RECT  2.16 206.685 326.16 206.955 ;
     RECT  2.16 207.225 326.16 207.495 ;
     RECT  2.16 207.765 326.16 208.035 ;
     RECT  2.16 208.305 326.16 208.575 ;
     RECT  2.16 208.845 326.16 209.115 ;
     RECT  2.16 209.385 326.16 209.655 ;
     RECT  2.16 209.925 326.16 210.195 ;
     RECT  2.16 210.465 326.16 210.735 ;
     RECT  2.16 211.005 326.16 211.275 ;
     RECT  2.16 211.545 326.16 211.815 ;
     RECT  2.16 212.085 326.16 212.355 ;
     RECT  2.16 212.625 326.16 212.895 ;
     RECT  2.16 213.165 326.16 213.435 ;
     RECT  2.16 213.705 326.16 213.975 ;
     RECT  2.16 214.245 326.16 214.515 ;
     RECT  2.16 214.785 326.16 215.055 ;
     RECT  2.16 215.325 326.16 215.595 ;
     RECT  2.16 215.865 326.16 216.135 ;
     RECT  2.16 216.405 326.16 216.675 ;
     RECT  2.16 216.945 326.16 217.215 ;
     RECT  2.16 217.485 326.16 217.755 ;
     RECT  2.16 218.025 326.16 218.295 ;
     RECT  2.16 218.565 326.16 218.835 ;
     RECT  2.16 219.105 326.16 219.375 ;
     RECT  2.16 219.645 326.16 219.915 ;
     RECT  2.16 220.185 326.16 220.455 ;
     RECT  2.16 220.725 326.16 220.995 ;
     RECT  2.16 221.265 326.16 221.535 ;
     RECT  2.16 221.805 326.16 222.075 ;
     RECT  2.16 222.345 326.16 222.615 ;
     RECT  2.16 222.885 326.16 223.155 ;
     RECT  2.16 223.425 326.16 223.695 ;
     RECT  2.16 223.965 326.16 224.235 ;
     RECT  2.16 224.505 326.16 224.775 ;
     RECT  2.16 225.045 326.16 225.315 ;
     RECT  2.16 225.585 326.16 225.855 ;
     RECT  2.16 226.125 326.16 226.395 ;
     RECT  2.16 226.665 326.16 226.935 ;
     RECT  2.16 227.205 326.16 227.475 ;
     RECT  2.16 227.745 326.16 228.015 ;
     RECT  2.16 228.285 326.16 228.555 ;
     RECT  2.16 228.825 326.16 229.095 ;
     RECT  2.16 229.365 326.16 229.635 ;
     RECT  2.16 229.905 326.16 230.175 ;
     RECT  2.16 230.445 326.16 230.715 ;
     RECT  2.16 230.985 326.16 231.255 ;
     RECT  2.16 231.525 326.16 231.795 ;
     RECT  2.16 232.065 326.16 232.335 ;
     RECT  2.16 232.605 326.16 232.875 ;
     RECT  2.16 233.145 326.16 233.415 ;
     RECT  2.16 233.685 326.16 233.955 ;
     RECT  2.16 234.225 326.16 234.495 ;
     RECT  2.16 234.765 326.16 235.035 ;
     RECT  2.16 235.305 326.16 235.575 ;
     RECT  2.16 235.845 326.16 236.115 ;
     RECT  2.16 236.385 326.16 236.655 ;
     RECT  2.16 236.925 326.16 237.195 ;
     RECT  2.16 237.465 326.16 237.735 ;
     RECT  2.16 238.005 326.16 238.275 ;
     RECT  2.16 238.545 326.16 238.815 ;
     RECT  2.16 239.085 326.16 239.355 ;
     RECT  2.16 239.625 326.16 239.895 ;
     RECT  2.16 240.165 326.16 240.435 ;
     RECT  2.16 240.705 326.16 240.975 ;
     RECT  2.16 241.245 326.16 241.515 ;
     RECT  2.16 241.785 326.16 242.055 ;
     RECT  2.16 242.325 326.16 242.595 ;
     RECT  2.16 242.865 326.16 243.135 ;
     RECT  2.16 243.405 326.16 243.675 ;
     RECT  2.16 243.945 326.16 244.215 ;
     RECT  2.16 244.485 326.16 244.755 ;
     RECT  2.16 245.025 326.16 245.295 ;
     RECT  2.16 245.565 326.16 245.835 ;
     RECT  2.16 246.105 326.16 246.375 ;
     RECT  2.16 246.645 326.16 246.915 ;
     RECT  2.16 247.185 326.16 247.455 ;
     RECT  2.16 247.725 326.16 247.995 ;
     RECT  2.16 248.265 326.16 248.535 ;
     RECT  2.16 248.805 326.16 249.075 ;
     RECT  2.16 249.345 326.16 249.615 ;
     RECT  2.16 249.885 326.16 250.155 ;
     RECT  2.16 250.425 326.16 250.695 ;
     RECT  2.16 250.965 326.16 251.235 ;
     RECT  2.16 251.505 326.16 251.775 ;
     RECT  2.16 252.045 326.16 252.315 ;
     RECT  2.16 252.585 326.16 252.855 ;
     RECT  2.16 253.125 326.16 253.395 ;
     RECT  2.16 253.665 326.16 253.935 ;
     RECT  2.16 254.205 326.16 254.475 ;
     RECT  2.16 254.745 326.16 255.015 ;
     RECT  2.16 255.285 326.16 255.555 ;
     RECT  2.16 255.825 326.16 256.095 ;
     RECT  2.16 256.365 326.16 256.635 ;
     RECT  2.16 256.905 326.16 257.175 ;
     RECT  2.16 257.445 326.16 257.715 ;
     RECT  2.16 257.985 326.16 258.255 ;
     RECT  2.16 258.525 326.16 258.795 ;
     RECT  2.16 259.065 326.16 259.335 ;
     RECT  2.16 259.605 326.16 259.875 ;
     RECT  2.16 260.145 326.16 260.415 ;
     RECT  2.16 260.685 326.16 260.955 ;
     RECT  2.16 261.225 326.16 261.495 ;
     RECT  2.16 261.765 326.16 262.035 ;
     RECT  2.16 262.305 326.16 262.575 ;
     RECT  2.16 262.845 326.16 263.115 ;
     RECT  2.16 263.385 326.16 263.655 ;
     RECT  2.16 263.925 326.16 264.195 ;
     RECT  2.16 264.465 326.16 264.735 ;
     RECT  2.16 265.005 326.16 265.275 ;
     RECT  2.16 265.545 326.16 265.815 ;
     RECT  2.16 266.085 326.16 266.355 ;
     RECT  2.16 266.625 326.16 266.895 ;
     RECT  2.16 267.165 326.16 267.435 ;
     RECT  2.16 267.705 326.16 267.975 ;
     RECT  2.16 268.245 326.16 268.515 ;
     RECT  2.16 268.785 326.16 269.055 ;
     RECT  2.16 269.325 326.16 269.595 ;
     RECT  2.16 269.865 326.16 270.135 ;
     RECT  2.16 270.405 326.16 270.675 ;
     RECT  2.16 270.945 326.16 271.215 ;
     RECT  2.16 271.485 326.16 271.755 ;
     RECT  2.16 272.025 326.16 272.295 ;
     RECT  2.16 272.565 326.16 272.835 ;
     RECT  2.16 273.105 326.16 273.375 ;
     RECT  2.16 273.645 326.16 273.915 ;
     RECT  2.16 274.185 326.16 274.455 ;
     RECT  2.16 274.725 326.16 274.995 ;
     RECT  2.16 275.265 326.16 275.535 ;
     RECT  2.16 275.805 326.16 276.075 ;
     RECT  2.16 276.345 326.16 276.615 ;
     RECT  2.16 276.885 326.16 277.155 ;
     RECT  2.16 277.425 326.16 277.695 ;
     RECT  2.16 277.965 326.16 278.235 ;
     RECT  2.16 278.505 326.16 278.775 ;
     RECT  2.16 279.045 326.16 279.315 ;
     RECT  2.16 279.585 326.16 279.855 ;
     RECT  2.16 280.125 326.16 280.395 ;
     RECT  2.16 280.665 326.16 280.935 ;
     RECT  2.16 281.205 326.16 281.475 ;
     RECT  2.16 281.745 326.16 282.015 ;
     RECT  2.16 282.285 326.16 282.555 ;
     RECT  2.16 282.825 326.16 283.095 ;
     RECT  2.16 283.365 326.16 283.635 ;
     RECT  2.16 283.905 326.16 284.175 ;
     RECT  2.16 284.445 326.16 284.715 ;
     RECT  2.16 284.985 326.16 285.255 ;
     RECT  2.16 285.525 326.16 285.795 ;
     RECT  2.16 286.065 326.16 286.335 ;
     RECT  2.16 286.605 326.16 286.875 ;
     RECT  2.16 287.145 326.16 287.415 ;
     RECT  2.16 287.685 326.16 287.955 ;
     RECT  2.16 288.225 326.16 288.495 ;
     RECT  2.16 288.765 326.16 289.035 ;
     RECT  2.16 289.305 326.16 289.575 ;
     RECT  2.16 289.845 326.16 290.115 ;
     RECT  2.16 290.385 326.16 290.655 ;
     RECT  2.16 290.925 326.16 291.195 ;
     RECT  2.16 291.465 326.16 291.735 ;
     RECT  2.16 292.005 326.16 292.275 ;
     RECT  2.16 292.545 326.16 292.815 ;
     RECT  2.16 293.085 326.16 293.355 ;
     RECT  2.16 293.625 326.16 293.895 ;
     RECT  2.16 294.165 326.16 294.435 ;
     RECT  2.16 294.705 326.16 294.975 ;
     RECT  2.16 295.245 326.16 295.515 ;
     RECT  2.16 295.785 326.16 296.055 ;
     RECT  2.16 296.325 326.16 296.595 ;
     RECT  2.16 296.865 326.16 297.135 ;
     RECT  2.16 297.405 326.16 297.675 ;
     RECT  2.16 297.945 326.16 298.215 ;
     RECT  2.16 298.485 326.16 298.755 ;
     RECT  2.16 299.025 326.16 299.295 ;
     RECT  2.16 299.565 326.16 299.835 ;
     RECT  2.16 300.105 326.16 300.375 ;
     RECT  2.16 300.645 326.16 300.915 ;
     RECT  2.16 301.185 326.16 301.455 ;
     RECT  2.16 301.725 326.16 301.995 ;
     RECT  2.16 302.265 326.16 302.535 ;
     RECT  2.16 302.805 326.16 303.075 ;
     RECT  2.16 303.345 326.16 303.615 ;
     RECT  2.16 303.885 326.16 304.155 ;
     RECT  2.16 304.425 326.16 304.695 ;
     RECT  2.16 304.965 326.16 305.235 ;
     RECT  2.16 305.505 326.16 305.775 ;
     RECT  2.16 306.045 326.16 306.315 ;
     RECT  2.16 306.585 326.16 306.855 ;
     RECT  2.16 307.125 326.16 307.395 ;
     RECT  2.16 307.665 326.16 307.935 ;
     RECT  2.16 308.205 326.16 308.475 ;
     RECT  2.16 308.745 326.16 309.015 ;
     RECT  2.16 309.285 326.16 309.555 ;
     RECT  2.16 309.825 326.16 310.095 ;
     RECT  2.16 310.365 326.16 310.635 ;
     RECT  2.16 310.905 326.16 311.175 ;
     RECT  2.16 311.445 326.16 311.715 ;
     RECT  2.16 311.985 326.16 312.255 ;
     RECT  2.16 312.525 326.16 312.795 ;
     RECT  2.16 313.065 326.16 313.335 ;
     RECT  2.16 313.605 326.16 313.875 ;
     RECT  2.16 314.145 326.16 314.415 ;
     RECT  2.16 314.685 326.16 314.955 ;
     RECT  2.16 315.225 326.16 315.495 ;
     RECT  2.16 315.765 326.16 316.035 ;
     RECT  2.16 316.305 326.16 316.575 ;
     RECT  2.16 316.845 326.16 317.115 ;
     RECT  2.16 317.385 326.16 317.655 ;
     RECT  2.16 317.925 326.16 318.195 ;
     RECT  2.16 318.465 326.16 318.735 ;
     RECT  2.16 319.005 326.16 319.275 ;
     RECT  2.16 319.545 326.16 319.815 ;
     RECT  2.16 320.085 326.16 320.355 ;
     RECT  2.16 320.625 326.16 320.895 ;
     RECT  2.16 321.165 326.16 321.435 ;
     RECT  2.16 321.705 326.16 321.975 ;
     RECT  2.16 322.245 326.16 322.515 ;
     RECT  2.16 322.785 326.16 323.055 ;
     RECT  2.16 323.325 326.16 323.595 ;
     RECT  2.16 323.865 326.16 324.135 ;
     RECT  2.16 324.405 326.16 324.675 ;
     RECT  2.16 324.945 326.16 325.215 ;
     RECT  2.16 325.485 326.16 325.755 ;
     RECT  2.16 326.025 326.16 326.295 ;
     RECT  2.16 326.565 326.16 326.835 ;
     RECT  2.16 327.105 326.16 327.375 ;
     RECT  2.16 327.645 326.16 327.915 ;
     RECT  2.16 328.185 326.16 328.455 ;
     RECT  2.16 328.725 326.16 328.995 ;
     RECT  2.16 329.265 326.16 329.535 ;
     RECT  2.16 329.805 326.16 330.075 ;
     RECT  2.16 330.345 326.16 330.615 ;
     RECT  2.16 330.885 326.16 331.155 ;
     RECT  2.16 331.425 326.16 331.695 ;
     RECT  2.16 331.965 326.16 332.235 ;
     RECT  2.16 332.505 326.16 332.775 ;
     RECT  2.16 333.045 326.16 333.315 ;
     RECT  2.16 333.585 326.16 333.855 ;
     RECT  2.16 334.125 326.16 334.395 ;
     RECT  2.16 334.665 326.16 334.935 ;
     RECT  2.16 335.205 326.16 335.475 ;
     RECT  2.16 335.745 326.16 336.015 ;
     RECT  2.16 336.285 326.16 336.555 ;
     RECT  2.16 336.825 326.16 337.095 ;
     RECT  2.16 337.365 326.16 337.635 ;
     RECT  2.16 337.905 326.16 338.175 ;
     RECT  2.16 338.445 326.16 338.715 ;
     RECT  2.16 338.985 326.16 339.255 ;
     RECT  2.16 339.525 326.16 339.795 ;
     RECT  2.16 340.065 326.16 340.335 ;
     RECT  2.16 340.605 326.16 340.875 ;
     RECT  2.16 341.145 326.16 341.415 ;
     RECT  2.16 341.685 326.16 341.955 ;
     RECT  2.16 342.225 326.16 342.495 ;
     RECT  2.16 342.765 326.16 343.035 ;
     RECT  2.16 343.305 326.16 343.575 ;
     RECT  2.16 343.845 326.16 344.115 ;
     RECT  2.16 344.385 326.16 344.655 ;
     RECT  2.16 344.925 326.16 345.195 ;
     RECT  2.16 345.465 326.16 345.735 ;
     RECT  2.16 346.005 326.16 346.275 ;
     RECT  2.16 346.545 326.16 346.815 ;
     RECT  2.16 347.085 326.16 347.355 ;
     RECT  2.16 347.625 326.16 347.895 ;
     RECT  2.16 348.165 326.16 348.435 ;
     RECT  2.16 348.705 326.16 348.975 ;
     RECT  2.16 349.245 326.16 349.515 ;
     RECT  2.16 349.785 326.16 350.055 ;
     RECT  2.16 350.325 326.16 350.595 ;
     RECT  2.16 350.865 326.16 351.135 ;
     RECT  2.16 351.405 326.16 351.675 ;
     RECT  2.16 351.945 326.16 352.215 ;
     RECT  2.16 352.485 326.16 352.755 ;
     RECT  2.16 353.025 326.16 353.295 ;
     RECT  2.16 353.565 326.16 353.835 ;
     RECT  2.16 354.105 326.16 354.375 ;
     RECT  2.16 354.645 326.16 354.915 ;
     RECT  2.16 355.185 326.16 355.455 ;
     RECT  2.16 355.725 326.16 355.995 ;
     RECT  2.16 356.265 326.16 356.535 ;
     RECT  2.16 356.805 326.16 357.075 ;
     RECT  2.16 357.345 326.16 357.615 ;
     RECT  2.16 357.885 326.16 358.155 ;
     RECT  2.16 358.425 326.16 358.695 ;
     RECT  2.16 358.965 326.16 359.235 ;
     RECT  2.16 359.505 326.16 359.775 ;
     RECT  2.16 360.045 326.16 360.315 ;
     RECT  2.16 360.585 326.16 360.855 ;
     RECT  2.16 361.125 326.16 361.395 ;
     RECT  2.16 361.665 326.16 361.935 ;
     RECT  2.16 362.205 326.16 362.475 ;
     RECT  2.16 362.745 326.16 363.015 ;
     RECT  2.16 363.285 326.16 363.555 ;
     RECT  2.16 363.825 326.16 364.095 ;
     RECT  2.16 364.365 326.16 364.635 ;
     RECT  2.16 364.905 326.16 365.175 ;
     RECT  2.16 365.445 326.16 365.715 ;
     RECT  2.16 365.985 326.16 366.255 ;
     RECT  2.16 366.525 326.16 366.795 ;
     RECT  2.16 367.065 326.16 367.335 ;
     RECT  2.16 367.605 326.16 367.875 ;
     RECT  2.16 368.145 326.16 368.415 ;
     RECT  2.16 368.685 326.16 368.955 ;
     RECT  2.16 369.225 326.16 369.36 ;
    LAYER RVTP ;
     RECT  2.16 2.295 326.16 2.565 ;
     RECT  2.16 2.835 326.16 3.105 ;
     RECT  2.16 3.375 326.16 3.645 ;
     RECT  2.16 3.915 326.16 4.185 ;
     RECT  2.16 4.455 326.16 4.725 ;
     RECT  2.16 4.995 326.16 5.265 ;
     RECT  2.16 5.535 326.16 5.805 ;
     RECT  2.16 6.075 326.16 6.345 ;
     RECT  2.16 6.615 326.16 6.885 ;
     RECT  2.16 7.155 326.16 7.425 ;
     RECT  2.16 7.695 326.16 7.965 ;
     RECT  2.16 8.235 326.16 8.505 ;
     RECT  2.16 8.775 326.16 9.045 ;
     RECT  2.16 9.315 326.16 9.585 ;
     RECT  2.16 9.855 326.16 10.125 ;
     RECT  2.16 10.395 326.16 10.665 ;
     RECT  2.16 10.935 326.16 11.205 ;
     RECT  2.16 11.475 326.16 11.745 ;
     RECT  2.16 12.015 326.16 12.285 ;
     RECT  2.16 12.555 326.16 12.825 ;
     RECT  2.16 13.095 326.16 13.365 ;
     RECT  2.16 13.635 326.16 13.905 ;
     RECT  2.16 14.175 326.16 14.445 ;
     RECT  2.16 14.715 326.16 14.985 ;
     RECT  2.16 15.255 326.16 15.525 ;
     RECT  2.16 15.795 326.16 16.065 ;
     RECT  2.16 16.335 326.16 16.605 ;
     RECT  2.16 16.875 326.16 17.145 ;
     RECT  2.16 17.415 326.16 17.685 ;
     RECT  2.16 17.955 326.16 18.225 ;
     RECT  2.16 18.495 326.16 18.765 ;
     RECT  2.16 19.035 326.16 19.305 ;
     RECT  2.16 19.575 326.16 19.845 ;
     RECT  2.16 20.115 326.16 20.385 ;
     RECT  2.16 20.655 326.16 20.925 ;
     RECT  2.16 21.195 326.16 21.465 ;
     RECT  2.16 21.735 326.16 22.005 ;
     RECT  2.16 22.275 326.16 22.545 ;
     RECT  2.16 22.815 326.16 23.085 ;
     RECT  2.16 23.355 326.16 23.625 ;
     RECT  2.16 23.895 326.16 24.165 ;
     RECT  2.16 24.435 326.16 24.705 ;
     RECT  2.16 24.975 326.16 25.245 ;
     RECT  2.16 25.515 326.16 25.785 ;
     RECT  2.16 26.055 326.16 26.325 ;
     RECT  2.16 26.595 326.16 26.865 ;
     RECT  2.16 27.135 326.16 27.405 ;
     RECT  2.16 27.675 326.16 27.945 ;
     RECT  2.16 28.215 326.16 28.485 ;
     RECT  2.16 28.755 326.16 29.025 ;
     RECT  2.16 29.295 326.16 29.565 ;
     RECT  2.16 29.835 326.16 30.105 ;
     RECT  2.16 30.375 326.16 30.645 ;
     RECT  2.16 30.915 326.16 31.185 ;
     RECT  2.16 31.455 326.16 31.725 ;
     RECT  2.16 31.995 326.16 32.265 ;
     RECT  2.16 32.535 326.16 32.805 ;
     RECT  2.16 33.075 326.16 33.345 ;
     RECT  2.16 33.615 326.16 33.885 ;
     RECT  2.16 34.155 326.16 34.425 ;
     RECT  2.16 34.695 326.16 34.965 ;
     RECT  2.16 35.235 326.16 35.505 ;
     RECT  2.16 35.775 326.16 36.045 ;
     RECT  2.16 36.315 326.16 36.585 ;
     RECT  2.16 36.855 326.16 37.125 ;
     RECT  2.16 37.395 326.16 37.665 ;
     RECT  2.16 37.935 326.16 38.205 ;
     RECT  2.16 38.475 326.16 38.745 ;
     RECT  2.16 39.015 326.16 39.285 ;
     RECT  2.16 39.555 326.16 39.825 ;
     RECT  2.16 40.095 326.16 40.365 ;
     RECT  2.16 40.635 326.16 40.905 ;
     RECT  2.16 41.175 326.16 41.445 ;
     RECT  2.16 41.715 326.16 41.985 ;
     RECT  2.16 42.255 326.16 42.525 ;
     RECT  2.16 42.795 326.16 43.065 ;
     RECT  2.16 43.335 326.16 43.605 ;
     RECT  2.16 43.875 326.16 44.145 ;
     RECT  2.16 44.415 326.16 44.685 ;
     RECT  2.16 44.955 326.16 45.225 ;
     RECT  2.16 45.495 326.16 45.765 ;
     RECT  2.16 46.035 326.16 46.305 ;
     RECT  2.16 46.575 326.16 46.845 ;
     RECT  2.16 47.115 326.16 47.385 ;
     RECT  2.16 47.655 326.16 47.925 ;
     RECT  2.16 48.195 326.16 48.465 ;
     RECT  2.16 48.735 326.16 49.005 ;
     RECT  2.16 49.275 326.16 49.545 ;
     RECT  2.16 49.815 326.16 50.085 ;
     RECT  2.16 50.355 326.16 50.625 ;
     RECT  2.16 50.895 326.16 51.165 ;
     RECT  2.16 51.435 326.16 51.705 ;
     RECT  2.16 51.975 326.16 52.245 ;
     RECT  2.16 52.515 326.16 52.785 ;
     RECT  2.16 53.055 326.16 53.325 ;
     RECT  2.16 53.595 326.16 53.865 ;
     RECT  2.16 54.135 326.16 54.405 ;
     RECT  2.16 54.675 326.16 54.945 ;
     RECT  2.16 55.215 326.16 55.485 ;
     RECT  2.16 55.755 326.16 56.025 ;
     RECT  2.16 56.295 326.16 56.565 ;
     RECT  2.16 56.835 326.16 57.105 ;
     RECT  2.16 57.375 326.16 57.645 ;
     RECT  2.16 57.915 326.16 58.185 ;
     RECT  2.16 58.455 326.16 58.725 ;
     RECT  2.16 58.995 326.16 59.265 ;
     RECT  2.16 59.535 326.16 59.805 ;
     RECT  2.16 60.075 326.16 60.345 ;
     RECT  2.16 60.615 326.16 60.885 ;
     RECT  2.16 61.155 326.16 61.425 ;
     RECT  2.16 61.695 326.16 61.965 ;
     RECT  2.16 62.235 326.16 62.505 ;
     RECT  2.16 62.775 326.16 63.045 ;
     RECT  2.16 63.315 326.16 63.585 ;
     RECT  2.16 63.855 326.16 64.125 ;
     RECT  2.16 64.395 326.16 64.665 ;
     RECT  2.16 64.935 326.16 65.205 ;
     RECT  2.16 65.475 326.16 65.745 ;
     RECT  2.16 66.015 326.16 66.285 ;
     RECT  2.16 66.555 326.16 66.825 ;
     RECT  2.16 67.095 326.16 67.365 ;
     RECT  2.16 67.635 326.16 67.905 ;
     RECT  2.16 68.175 326.16 68.445 ;
     RECT  2.16 68.715 326.16 68.985 ;
     RECT  2.16 69.255 326.16 69.525 ;
     RECT  2.16 69.795 326.16 70.065 ;
     RECT  2.16 70.335 326.16 70.605 ;
     RECT  2.16 70.875 326.16 71.145 ;
     RECT  2.16 71.415 326.16 71.685 ;
     RECT  2.16 71.955 326.16 72.225 ;
     RECT  2.16 72.495 326.16 72.765 ;
     RECT  2.16 73.035 326.16 73.305 ;
     RECT  2.16 73.575 326.16 73.845 ;
     RECT  2.16 74.115 326.16 74.385 ;
     RECT  2.16 74.655 326.16 74.925 ;
     RECT  2.16 75.195 326.16 75.465 ;
     RECT  2.16 75.735 326.16 76.005 ;
     RECT  2.16 76.275 326.16 76.545 ;
     RECT  2.16 76.815 326.16 77.085 ;
     RECT  2.16 77.355 326.16 77.625 ;
     RECT  2.16 77.895 326.16 78.165 ;
     RECT  2.16 78.435 326.16 78.705 ;
     RECT  2.16 78.975 326.16 79.245 ;
     RECT  2.16 79.515 326.16 79.785 ;
     RECT  2.16 80.055 326.16 80.325 ;
     RECT  2.16 80.595 326.16 80.865 ;
     RECT  2.16 81.135 326.16 81.405 ;
     RECT  2.16 81.675 326.16 81.945 ;
     RECT  2.16 82.215 326.16 82.485 ;
     RECT  2.16 82.755 326.16 83.025 ;
     RECT  2.16 83.295 326.16 83.565 ;
     RECT  2.16 83.835 326.16 84.105 ;
     RECT  2.16 84.375 326.16 84.645 ;
     RECT  2.16 84.915 326.16 85.185 ;
     RECT  2.16 85.455 326.16 85.725 ;
     RECT  2.16 85.995 326.16 86.265 ;
     RECT  2.16 86.535 326.16 86.805 ;
     RECT  2.16 87.075 326.16 87.345 ;
     RECT  2.16 87.615 326.16 87.885 ;
     RECT  2.16 88.155 326.16 88.425 ;
     RECT  2.16 88.695 326.16 88.965 ;
     RECT  2.16 89.235 326.16 89.505 ;
     RECT  2.16 89.775 326.16 90.045 ;
     RECT  2.16 90.315 326.16 90.585 ;
     RECT  2.16 90.855 326.16 91.125 ;
     RECT  2.16 91.395 326.16 91.665 ;
     RECT  2.16 91.935 326.16 92.205 ;
     RECT  2.16 92.475 326.16 92.745 ;
     RECT  2.16 93.015 326.16 93.285 ;
     RECT  2.16 93.555 326.16 93.825 ;
     RECT  2.16 94.095 326.16 94.365 ;
     RECT  2.16 94.635 326.16 94.905 ;
     RECT  2.16 95.175 326.16 95.445 ;
     RECT  2.16 95.715 326.16 95.985 ;
     RECT  2.16 96.255 326.16 96.525 ;
     RECT  2.16 96.795 326.16 97.065 ;
     RECT  2.16 97.335 326.16 97.605 ;
     RECT  2.16 97.875 326.16 98.145 ;
     RECT  2.16 98.415 326.16 98.685 ;
     RECT  2.16 98.955 326.16 99.225 ;
     RECT  2.16 99.495 326.16 99.765 ;
     RECT  2.16 100.035 326.16 100.305 ;
     RECT  2.16 100.575 326.16 100.845 ;
     RECT  2.16 101.115 326.16 101.385 ;
     RECT  2.16 101.655 326.16 101.925 ;
     RECT  2.16 102.195 326.16 102.465 ;
     RECT  2.16 102.735 326.16 103.005 ;
     RECT  2.16 103.275 326.16 103.545 ;
     RECT  2.16 103.815 326.16 104.085 ;
     RECT  2.16 104.355 326.16 104.625 ;
     RECT  2.16 104.895 326.16 105.165 ;
     RECT  2.16 105.435 326.16 105.705 ;
     RECT  2.16 105.975 326.16 106.245 ;
     RECT  2.16 106.515 326.16 106.785 ;
     RECT  2.16 107.055 326.16 107.325 ;
     RECT  2.16 107.595 326.16 107.865 ;
     RECT  2.16 108.135 326.16 108.405 ;
     RECT  2.16 108.675 326.16 108.945 ;
     RECT  2.16 109.215 326.16 109.485 ;
     RECT  2.16 109.755 326.16 110.025 ;
     RECT  2.16 110.295 326.16 110.565 ;
     RECT  2.16 110.835 326.16 111.105 ;
     RECT  2.16 111.375 326.16 111.645 ;
     RECT  2.16 111.915 326.16 112.185 ;
     RECT  2.16 112.455 326.16 112.725 ;
     RECT  2.16 112.995 326.16 113.265 ;
     RECT  2.16 113.535 326.16 113.805 ;
     RECT  2.16 114.075 326.16 114.345 ;
     RECT  2.16 114.615 326.16 114.885 ;
     RECT  2.16 115.155 326.16 115.425 ;
     RECT  2.16 115.695 326.16 115.965 ;
     RECT  2.16 116.235 326.16 116.505 ;
     RECT  2.16 116.775 326.16 117.045 ;
     RECT  2.16 117.315 326.16 117.585 ;
     RECT  2.16 117.855 326.16 118.125 ;
     RECT  2.16 118.395 326.16 118.665 ;
     RECT  2.16 118.935 326.16 119.205 ;
     RECT  2.16 119.475 326.16 119.745 ;
     RECT  2.16 120.015 326.16 120.285 ;
     RECT  2.16 120.555 326.16 120.825 ;
     RECT  2.16 121.095 326.16 121.365 ;
     RECT  2.16 121.635 326.16 121.905 ;
     RECT  2.16 122.175 326.16 122.445 ;
     RECT  2.16 122.715 326.16 122.985 ;
     RECT  2.16 123.255 326.16 123.525 ;
     RECT  2.16 123.795 326.16 124.065 ;
     RECT  2.16 124.335 326.16 124.605 ;
     RECT  2.16 124.875 326.16 125.145 ;
     RECT  2.16 125.415 326.16 125.685 ;
     RECT  2.16 125.955 326.16 126.225 ;
     RECT  2.16 126.495 326.16 126.765 ;
     RECT  2.16 127.035 326.16 127.305 ;
     RECT  2.16 127.575 326.16 127.845 ;
     RECT  2.16 128.115 326.16 128.385 ;
     RECT  2.16 128.655 326.16 128.925 ;
     RECT  2.16 129.195 326.16 129.465 ;
     RECT  2.16 129.735 326.16 130.005 ;
     RECT  2.16 130.275 326.16 130.545 ;
     RECT  2.16 130.815 326.16 131.085 ;
     RECT  2.16 131.355 326.16 131.625 ;
     RECT  2.16 131.895 326.16 132.165 ;
     RECT  2.16 132.435 326.16 132.705 ;
     RECT  2.16 132.975 326.16 133.245 ;
     RECT  2.16 133.515 326.16 133.785 ;
     RECT  2.16 134.055 326.16 134.325 ;
     RECT  2.16 134.595 326.16 134.865 ;
     RECT  2.16 135.135 326.16 135.405 ;
     RECT  2.16 135.675 326.16 135.945 ;
     RECT  2.16 136.215 326.16 136.485 ;
     RECT  2.16 136.755 326.16 137.025 ;
     RECT  2.16 137.295 326.16 137.565 ;
     RECT  2.16 137.835 326.16 138.105 ;
     RECT  2.16 138.375 326.16 138.645 ;
     RECT  2.16 138.915 326.16 139.185 ;
     RECT  2.16 139.455 326.16 139.725 ;
     RECT  2.16 139.995 326.16 140.265 ;
     RECT  2.16 140.535 326.16 140.805 ;
     RECT  2.16 141.075 326.16 141.345 ;
     RECT  2.16 141.615 326.16 141.885 ;
     RECT  2.16 142.155 326.16 142.425 ;
     RECT  2.16 142.695 326.16 142.965 ;
     RECT  2.16 143.235 326.16 143.505 ;
     RECT  2.16 143.775 326.16 144.045 ;
     RECT  2.16 144.315 326.16 144.585 ;
     RECT  2.16 144.855 326.16 145.125 ;
     RECT  2.16 145.395 326.16 145.665 ;
     RECT  2.16 145.935 326.16 146.205 ;
     RECT  2.16 146.475 326.16 146.745 ;
     RECT  2.16 147.015 326.16 147.285 ;
     RECT  2.16 147.555 326.16 147.825 ;
     RECT  2.16 148.095 326.16 148.365 ;
     RECT  2.16 148.635 326.16 148.905 ;
     RECT  2.16 149.175 326.16 149.445 ;
     RECT  2.16 149.715 326.16 149.985 ;
     RECT  2.16 150.255 326.16 150.525 ;
     RECT  2.16 150.795 326.16 151.065 ;
     RECT  2.16 151.335 326.16 151.605 ;
     RECT  2.16 151.875 326.16 152.145 ;
     RECT  2.16 152.415 326.16 152.685 ;
     RECT  2.16 152.955 326.16 153.225 ;
     RECT  2.16 153.495 326.16 153.765 ;
     RECT  2.16 154.035 326.16 154.305 ;
     RECT  2.16 154.575 326.16 154.845 ;
     RECT  2.16 155.115 326.16 155.385 ;
     RECT  2.16 155.655 326.16 155.925 ;
     RECT  2.16 156.195 326.16 156.465 ;
     RECT  2.16 156.735 326.16 157.005 ;
     RECT  2.16 157.275 326.16 157.545 ;
     RECT  2.16 157.815 326.16 158.085 ;
     RECT  2.16 158.355 326.16 158.625 ;
     RECT  2.16 158.895 326.16 159.165 ;
     RECT  2.16 159.435 326.16 159.705 ;
     RECT  2.16 159.975 326.16 160.245 ;
     RECT  2.16 160.515 326.16 160.785 ;
     RECT  2.16 161.055 326.16 161.325 ;
     RECT  2.16 161.595 326.16 161.865 ;
     RECT  2.16 162.135 326.16 162.405 ;
     RECT  2.16 162.675 326.16 162.945 ;
     RECT  2.16 163.215 326.16 163.485 ;
     RECT  2.16 163.755 326.16 164.025 ;
     RECT  2.16 164.295 326.16 164.565 ;
     RECT  2.16 164.835 326.16 165.105 ;
     RECT  2.16 165.375 326.16 165.645 ;
     RECT  2.16 165.915 326.16 166.185 ;
     RECT  2.16 166.455 326.16 166.725 ;
     RECT  2.16 166.995 326.16 167.265 ;
     RECT  2.16 167.535 326.16 167.805 ;
     RECT  2.16 168.075 326.16 168.345 ;
     RECT  2.16 168.615 326.16 168.885 ;
     RECT  2.16 169.155 326.16 169.425 ;
     RECT  2.16 169.695 326.16 169.965 ;
     RECT  2.16 170.235 326.16 170.505 ;
     RECT  2.16 170.775 326.16 171.045 ;
     RECT  2.16 171.315 326.16 171.585 ;
     RECT  2.16 171.855 326.16 172.125 ;
     RECT  2.16 172.395 326.16 172.665 ;
     RECT  2.16 172.935 326.16 173.205 ;
     RECT  2.16 173.475 326.16 173.745 ;
     RECT  2.16 174.015 326.16 174.285 ;
     RECT  2.16 174.555 326.16 174.825 ;
     RECT  2.16 175.095 326.16 175.365 ;
     RECT  2.16 175.635 326.16 175.905 ;
     RECT  2.16 176.175 326.16 176.445 ;
     RECT  2.16 176.715 326.16 176.985 ;
     RECT  2.16 177.255 326.16 177.525 ;
     RECT  2.16 177.795 326.16 178.065 ;
     RECT  2.16 178.335 326.16 178.605 ;
     RECT  2.16 178.875 326.16 179.145 ;
     RECT  2.16 179.415 326.16 179.685 ;
     RECT  2.16 179.955 326.16 180.225 ;
     RECT  2.16 180.495 326.16 180.765 ;
     RECT  2.16 181.035 326.16 181.305 ;
     RECT  2.16 181.575 326.16 181.845 ;
     RECT  2.16 182.115 326.16 182.385 ;
     RECT  2.16 182.655 326.16 182.925 ;
     RECT  2.16 183.195 326.16 183.465 ;
     RECT  2.16 183.735 326.16 184.005 ;
     RECT  2.16 184.275 326.16 184.545 ;
     RECT  2.16 184.815 326.16 185.085 ;
     RECT  2.16 185.355 326.16 185.625 ;
     RECT  2.16 185.895 326.16 186.165 ;
     RECT  2.16 186.435 326.16 186.705 ;
     RECT  2.16 186.975 326.16 187.245 ;
     RECT  2.16 187.515 326.16 187.785 ;
     RECT  2.16 188.055 326.16 188.325 ;
     RECT  2.16 188.595 326.16 188.865 ;
     RECT  2.16 189.135 326.16 189.405 ;
     RECT  2.16 189.675 326.16 189.945 ;
     RECT  2.16 190.215 326.16 190.485 ;
     RECT  2.16 190.755 326.16 191.025 ;
     RECT  2.16 191.295 326.16 191.565 ;
     RECT  2.16 191.835 326.16 192.105 ;
     RECT  2.16 192.375 326.16 192.645 ;
     RECT  2.16 192.915 326.16 193.185 ;
     RECT  2.16 193.455 326.16 193.725 ;
     RECT  2.16 193.995 326.16 194.265 ;
     RECT  2.16 194.535 326.16 194.805 ;
     RECT  2.16 195.075 326.16 195.345 ;
     RECT  2.16 195.615 326.16 195.885 ;
     RECT  2.16 196.155 326.16 196.425 ;
     RECT  2.16 196.695 326.16 196.965 ;
     RECT  2.16 197.235 326.16 197.505 ;
     RECT  2.16 197.775 326.16 198.045 ;
     RECT  2.16 198.315 326.16 198.585 ;
     RECT  2.16 198.855 326.16 199.125 ;
     RECT  2.16 199.395 326.16 199.665 ;
     RECT  2.16 199.935 326.16 200.205 ;
     RECT  2.16 200.475 326.16 200.745 ;
     RECT  2.16 201.015 326.16 201.285 ;
     RECT  2.16 201.555 326.16 201.825 ;
     RECT  2.16 202.095 326.16 202.365 ;
     RECT  2.16 202.635 326.16 202.905 ;
     RECT  2.16 203.175 326.16 203.445 ;
     RECT  2.16 203.715 326.16 203.985 ;
     RECT  2.16 204.255 326.16 204.525 ;
     RECT  2.16 204.795 326.16 205.065 ;
     RECT  2.16 205.335 326.16 205.605 ;
     RECT  2.16 205.875 326.16 206.145 ;
     RECT  2.16 206.415 326.16 206.685 ;
     RECT  2.16 206.955 326.16 207.225 ;
     RECT  2.16 207.495 326.16 207.765 ;
     RECT  2.16 208.035 326.16 208.305 ;
     RECT  2.16 208.575 326.16 208.845 ;
     RECT  2.16 209.115 326.16 209.385 ;
     RECT  2.16 209.655 326.16 209.925 ;
     RECT  2.16 210.195 326.16 210.465 ;
     RECT  2.16 210.735 326.16 211.005 ;
     RECT  2.16 211.275 326.16 211.545 ;
     RECT  2.16 211.815 326.16 212.085 ;
     RECT  2.16 212.355 326.16 212.625 ;
     RECT  2.16 212.895 326.16 213.165 ;
     RECT  2.16 213.435 326.16 213.705 ;
     RECT  2.16 213.975 326.16 214.245 ;
     RECT  2.16 214.515 326.16 214.785 ;
     RECT  2.16 215.055 326.16 215.325 ;
     RECT  2.16 215.595 326.16 215.865 ;
     RECT  2.16 216.135 326.16 216.405 ;
     RECT  2.16 216.675 326.16 216.945 ;
     RECT  2.16 217.215 326.16 217.485 ;
     RECT  2.16 217.755 326.16 218.025 ;
     RECT  2.16 218.295 326.16 218.565 ;
     RECT  2.16 218.835 326.16 219.105 ;
     RECT  2.16 219.375 326.16 219.645 ;
     RECT  2.16 219.915 326.16 220.185 ;
     RECT  2.16 220.455 326.16 220.725 ;
     RECT  2.16 220.995 326.16 221.265 ;
     RECT  2.16 221.535 326.16 221.805 ;
     RECT  2.16 222.075 326.16 222.345 ;
     RECT  2.16 222.615 326.16 222.885 ;
     RECT  2.16 223.155 326.16 223.425 ;
     RECT  2.16 223.695 326.16 223.965 ;
     RECT  2.16 224.235 326.16 224.505 ;
     RECT  2.16 224.775 326.16 225.045 ;
     RECT  2.16 225.315 326.16 225.585 ;
     RECT  2.16 225.855 326.16 226.125 ;
     RECT  2.16 226.395 326.16 226.665 ;
     RECT  2.16 226.935 326.16 227.205 ;
     RECT  2.16 227.475 326.16 227.745 ;
     RECT  2.16 228.015 326.16 228.285 ;
     RECT  2.16 228.555 326.16 228.825 ;
     RECT  2.16 229.095 326.16 229.365 ;
     RECT  2.16 229.635 326.16 229.905 ;
     RECT  2.16 230.175 326.16 230.445 ;
     RECT  2.16 230.715 326.16 230.985 ;
     RECT  2.16 231.255 326.16 231.525 ;
     RECT  2.16 231.795 326.16 232.065 ;
     RECT  2.16 232.335 326.16 232.605 ;
     RECT  2.16 232.875 326.16 233.145 ;
     RECT  2.16 233.415 326.16 233.685 ;
     RECT  2.16 233.955 326.16 234.225 ;
     RECT  2.16 234.495 326.16 234.765 ;
     RECT  2.16 235.035 326.16 235.305 ;
     RECT  2.16 235.575 326.16 235.845 ;
     RECT  2.16 236.115 326.16 236.385 ;
     RECT  2.16 236.655 326.16 236.925 ;
     RECT  2.16 237.195 326.16 237.465 ;
     RECT  2.16 237.735 326.16 238.005 ;
     RECT  2.16 238.275 326.16 238.545 ;
     RECT  2.16 238.815 326.16 239.085 ;
     RECT  2.16 239.355 326.16 239.625 ;
     RECT  2.16 239.895 326.16 240.165 ;
     RECT  2.16 240.435 326.16 240.705 ;
     RECT  2.16 240.975 326.16 241.245 ;
     RECT  2.16 241.515 326.16 241.785 ;
     RECT  2.16 242.055 326.16 242.325 ;
     RECT  2.16 242.595 326.16 242.865 ;
     RECT  2.16 243.135 326.16 243.405 ;
     RECT  2.16 243.675 326.16 243.945 ;
     RECT  2.16 244.215 326.16 244.485 ;
     RECT  2.16 244.755 326.16 245.025 ;
     RECT  2.16 245.295 326.16 245.565 ;
     RECT  2.16 245.835 326.16 246.105 ;
     RECT  2.16 246.375 326.16 246.645 ;
     RECT  2.16 246.915 326.16 247.185 ;
     RECT  2.16 247.455 326.16 247.725 ;
     RECT  2.16 247.995 326.16 248.265 ;
     RECT  2.16 248.535 326.16 248.805 ;
     RECT  2.16 249.075 326.16 249.345 ;
     RECT  2.16 249.615 326.16 249.885 ;
     RECT  2.16 250.155 326.16 250.425 ;
     RECT  2.16 250.695 326.16 250.965 ;
     RECT  2.16 251.235 326.16 251.505 ;
     RECT  2.16 251.775 326.16 252.045 ;
     RECT  2.16 252.315 326.16 252.585 ;
     RECT  2.16 252.855 326.16 253.125 ;
     RECT  2.16 253.395 326.16 253.665 ;
     RECT  2.16 253.935 326.16 254.205 ;
     RECT  2.16 254.475 326.16 254.745 ;
     RECT  2.16 255.015 326.16 255.285 ;
     RECT  2.16 255.555 326.16 255.825 ;
     RECT  2.16 256.095 326.16 256.365 ;
     RECT  2.16 256.635 326.16 256.905 ;
     RECT  2.16 257.175 326.16 257.445 ;
     RECT  2.16 257.715 326.16 257.985 ;
     RECT  2.16 258.255 326.16 258.525 ;
     RECT  2.16 258.795 326.16 259.065 ;
     RECT  2.16 259.335 326.16 259.605 ;
     RECT  2.16 259.875 326.16 260.145 ;
     RECT  2.16 260.415 326.16 260.685 ;
     RECT  2.16 260.955 326.16 261.225 ;
     RECT  2.16 261.495 326.16 261.765 ;
     RECT  2.16 262.035 326.16 262.305 ;
     RECT  2.16 262.575 326.16 262.845 ;
     RECT  2.16 263.115 326.16 263.385 ;
     RECT  2.16 263.655 326.16 263.925 ;
     RECT  2.16 264.195 326.16 264.465 ;
     RECT  2.16 264.735 326.16 265.005 ;
     RECT  2.16 265.275 326.16 265.545 ;
     RECT  2.16 265.815 326.16 266.085 ;
     RECT  2.16 266.355 326.16 266.625 ;
     RECT  2.16 266.895 326.16 267.165 ;
     RECT  2.16 267.435 326.16 267.705 ;
     RECT  2.16 267.975 326.16 268.245 ;
     RECT  2.16 268.515 326.16 268.785 ;
     RECT  2.16 269.055 326.16 269.325 ;
     RECT  2.16 269.595 326.16 269.865 ;
     RECT  2.16 270.135 326.16 270.405 ;
     RECT  2.16 270.675 326.16 270.945 ;
     RECT  2.16 271.215 326.16 271.485 ;
     RECT  2.16 271.755 326.16 272.025 ;
     RECT  2.16 272.295 326.16 272.565 ;
     RECT  2.16 272.835 326.16 273.105 ;
     RECT  2.16 273.375 326.16 273.645 ;
     RECT  2.16 273.915 326.16 274.185 ;
     RECT  2.16 274.455 326.16 274.725 ;
     RECT  2.16 274.995 326.16 275.265 ;
     RECT  2.16 275.535 326.16 275.805 ;
     RECT  2.16 276.075 326.16 276.345 ;
     RECT  2.16 276.615 326.16 276.885 ;
     RECT  2.16 277.155 326.16 277.425 ;
     RECT  2.16 277.695 326.16 277.965 ;
     RECT  2.16 278.235 326.16 278.505 ;
     RECT  2.16 278.775 326.16 279.045 ;
     RECT  2.16 279.315 326.16 279.585 ;
     RECT  2.16 279.855 326.16 280.125 ;
     RECT  2.16 280.395 326.16 280.665 ;
     RECT  2.16 280.935 326.16 281.205 ;
     RECT  2.16 281.475 326.16 281.745 ;
     RECT  2.16 282.015 326.16 282.285 ;
     RECT  2.16 282.555 326.16 282.825 ;
     RECT  2.16 283.095 326.16 283.365 ;
     RECT  2.16 283.635 326.16 283.905 ;
     RECT  2.16 284.175 326.16 284.445 ;
     RECT  2.16 284.715 326.16 284.985 ;
     RECT  2.16 285.255 326.16 285.525 ;
     RECT  2.16 285.795 326.16 286.065 ;
     RECT  2.16 286.335 326.16 286.605 ;
     RECT  2.16 286.875 326.16 287.145 ;
     RECT  2.16 287.415 326.16 287.685 ;
     RECT  2.16 287.955 326.16 288.225 ;
     RECT  2.16 288.495 326.16 288.765 ;
     RECT  2.16 289.035 326.16 289.305 ;
     RECT  2.16 289.575 326.16 289.845 ;
     RECT  2.16 290.115 326.16 290.385 ;
     RECT  2.16 290.655 326.16 290.925 ;
     RECT  2.16 291.195 326.16 291.465 ;
     RECT  2.16 291.735 326.16 292.005 ;
     RECT  2.16 292.275 326.16 292.545 ;
     RECT  2.16 292.815 326.16 293.085 ;
     RECT  2.16 293.355 326.16 293.625 ;
     RECT  2.16 293.895 326.16 294.165 ;
     RECT  2.16 294.435 326.16 294.705 ;
     RECT  2.16 294.975 326.16 295.245 ;
     RECT  2.16 295.515 326.16 295.785 ;
     RECT  2.16 296.055 326.16 296.325 ;
     RECT  2.16 296.595 326.16 296.865 ;
     RECT  2.16 297.135 326.16 297.405 ;
     RECT  2.16 297.675 326.16 297.945 ;
     RECT  2.16 298.215 326.16 298.485 ;
     RECT  2.16 298.755 326.16 299.025 ;
     RECT  2.16 299.295 326.16 299.565 ;
     RECT  2.16 299.835 326.16 300.105 ;
     RECT  2.16 300.375 326.16 300.645 ;
     RECT  2.16 300.915 326.16 301.185 ;
     RECT  2.16 301.455 326.16 301.725 ;
     RECT  2.16 301.995 326.16 302.265 ;
     RECT  2.16 302.535 326.16 302.805 ;
     RECT  2.16 303.075 326.16 303.345 ;
     RECT  2.16 303.615 326.16 303.885 ;
     RECT  2.16 304.155 326.16 304.425 ;
     RECT  2.16 304.695 326.16 304.965 ;
     RECT  2.16 305.235 326.16 305.505 ;
     RECT  2.16 305.775 326.16 306.045 ;
     RECT  2.16 306.315 326.16 306.585 ;
     RECT  2.16 306.855 326.16 307.125 ;
     RECT  2.16 307.395 326.16 307.665 ;
     RECT  2.16 307.935 326.16 308.205 ;
     RECT  2.16 308.475 326.16 308.745 ;
     RECT  2.16 309.015 326.16 309.285 ;
     RECT  2.16 309.555 326.16 309.825 ;
     RECT  2.16 310.095 326.16 310.365 ;
     RECT  2.16 310.635 326.16 310.905 ;
     RECT  2.16 311.175 326.16 311.445 ;
     RECT  2.16 311.715 326.16 311.985 ;
     RECT  2.16 312.255 326.16 312.525 ;
     RECT  2.16 312.795 326.16 313.065 ;
     RECT  2.16 313.335 326.16 313.605 ;
     RECT  2.16 313.875 326.16 314.145 ;
     RECT  2.16 314.415 326.16 314.685 ;
     RECT  2.16 314.955 326.16 315.225 ;
     RECT  2.16 315.495 326.16 315.765 ;
     RECT  2.16 316.035 326.16 316.305 ;
     RECT  2.16 316.575 326.16 316.845 ;
     RECT  2.16 317.115 326.16 317.385 ;
     RECT  2.16 317.655 326.16 317.925 ;
     RECT  2.16 318.195 326.16 318.465 ;
     RECT  2.16 318.735 326.16 319.005 ;
     RECT  2.16 319.275 326.16 319.545 ;
     RECT  2.16 319.815 326.16 320.085 ;
     RECT  2.16 320.355 326.16 320.625 ;
     RECT  2.16 320.895 326.16 321.165 ;
     RECT  2.16 321.435 326.16 321.705 ;
     RECT  2.16 321.975 326.16 322.245 ;
     RECT  2.16 322.515 326.16 322.785 ;
     RECT  2.16 323.055 326.16 323.325 ;
     RECT  2.16 323.595 326.16 323.865 ;
     RECT  2.16 324.135 326.16 324.405 ;
     RECT  2.16 324.675 326.16 324.945 ;
     RECT  2.16 325.215 326.16 325.485 ;
     RECT  2.16 325.755 326.16 326.025 ;
     RECT  2.16 326.295 326.16 326.565 ;
     RECT  2.16 326.835 326.16 327.105 ;
     RECT  2.16 327.375 326.16 327.645 ;
     RECT  2.16 327.915 326.16 328.185 ;
     RECT  2.16 328.455 326.16 328.725 ;
     RECT  2.16 328.995 326.16 329.265 ;
     RECT  2.16 329.535 326.16 329.805 ;
     RECT  2.16 330.075 326.16 330.345 ;
     RECT  2.16 330.615 326.16 330.885 ;
     RECT  2.16 331.155 326.16 331.425 ;
     RECT  2.16 331.695 326.16 331.965 ;
     RECT  2.16 332.235 326.16 332.505 ;
     RECT  2.16 332.775 326.16 333.045 ;
     RECT  2.16 333.315 326.16 333.585 ;
     RECT  2.16 333.855 326.16 334.125 ;
     RECT  2.16 334.395 326.16 334.665 ;
     RECT  2.16 334.935 326.16 335.205 ;
     RECT  2.16 335.475 326.16 335.745 ;
     RECT  2.16 336.015 326.16 336.285 ;
     RECT  2.16 336.555 326.16 336.825 ;
     RECT  2.16 337.095 326.16 337.365 ;
     RECT  2.16 337.635 326.16 337.905 ;
     RECT  2.16 338.175 326.16 338.445 ;
     RECT  2.16 338.715 326.16 338.985 ;
     RECT  2.16 339.255 326.16 339.525 ;
     RECT  2.16 339.795 326.16 340.065 ;
     RECT  2.16 340.335 326.16 340.605 ;
     RECT  2.16 340.875 326.16 341.145 ;
     RECT  2.16 341.415 326.16 341.685 ;
     RECT  2.16 341.955 326.16 342.225 ;
     RECT  2.16 342.495 326.16 342.765 ;
     RECT  2.16 343.035 326.16 343.305 ;
     RECT  2.16 343.575 326.16 343.845 ;
     RECT  2.16 344.115 326.16 344.385 ;
     RECT  2.16 344.655 326.16 344.925 ;
     RECT  2.16 345.195 326.16 345.465 ;
     RECT  2.16 345.735 326.16 346.005 ;
     RECT  2.16 346.275 326.16 346.545 ;
     RECT  2.16 346.815 326.16 347.085 ;
     RECT  2.16 347.355 326.16 347.625 ;
     RECT  2.16 347.895 326.16 348.165 ;
     RECT  2.16 348.435 326.16 348.705 ;
     RECT  2.16 348.975 326.16 349.245 ;
     RECT  2.16 349.515 326.16 349.785 ;
     RECT  2.16 350.055 326.16 350.325 ;
     RECT  2.16 350.595 326.16 350.865 ;
     RECT  2.16 351.135 326.16 351.405 ;
     RECT  2.16 351.675 326.16 351.945 ;
     RECT  2.16 352.215 326.16 352.485 ;
     RECT  2.16 352.755 326.16 353.025 ;
     RECT  2.16 353.295 326.16 353.565 ;
     RECT  2.16 353.835 326.16 354.105 ;
     RECT  2.16 354.375 326.16 354.645 ;
     RECT  2.16 354.915 326.16 355.185 ;
     RECT  2.16 355.455 326.16 355.725 ;
     RECT  2.16 355.995 326.16 356.265 ;
     RECT  2.16 356.535 326.16 356.805 ;
     RECT  2.16 357.075 326.16 357.345 ;
     RECT  2.16 357.615 326.16 357.885 ;
     RECT  2.16 358.155 326.16 358.425 ;
     RECT  2.16 358.695 326.16 358.965 ;
     RECT  2.16 359.235 326.16 359.505 ;
     RECT  2.16 359.775 326.16 360.045 ;
     RECT  2.16 360.315 326.16 360.585 ;
     RECT  2.16 360.855 326.16 361.125 ;
     RECT  2.16 361.395 326.16 361.665 ;
     RECT  2.16 361.935 326.16 362.205 ;
     RECT  2.16 362.475 326.16 362.745 ;
     RECT  2.16 363.015 326.16 363.285 ;
     RECT  2.16 363.555 326.16 363.825 ;
     RECT  2.16 364.095 326.16 364.365 ;
     RECT  2.16 364.635 326.16 364.905 ;
     RECT  2.16 365.175 326.16 365.445 ;
     RECT  2.16 365.715 326.16 365.985 ;
     RECT  2.16 366.255 326.16 366.525 ;
     RECT  2.16 366.795 326.16 367.065 ;
     RECT  2.16 367.335 326.16 367.605 ;
     RECT  2.16 367.875 326.16 368.145 ;
     RECT  2.16 368.415 326.16 368.685 ;
     RECT  2.16 368.955 326.16 369.225 ;
    LAYER M1 ;
     RECT  2.16 2.151 326.16 369.369 ;
    LAYER M2 ;
     RECT  0.031 167.976 0.103 167.994 ;
     RECT  0.031 171.09 0.103 171.108 ;
     RECT  0.103 170.901 0.131 171.108 ;
     RECT  0.103 158.436 0.139 158.454 ;
     RECT  0.103 164.232 0.203 165.564 ;
     RECT  0.175 156.636 0.211 156.654 ;
     RECT  0.103 174.33 0.211 174.348 ;
     RECT  0.139 175.572 0.211 175.59 ;
     RECT  0.103 167.976 0.239 168.84 ;
     RECT  0.211 156.636 0.247 156.798 ;
     RECT  0.103 161.1 0.247 161.118 ;
     RECT  0.211 162.72 0.247 162.738 ;
     RECT  0.103 170.046 0.247 170.064 ;
     RECT  0.211 155.556 0.283 155.574 ;
     RECT  0.211 174.33 0.283 175.59 ;
     RECT  0.211 176.454 0.283 176.472 ;
     RECT  0.211 194.976 0.283 194.994 ;
     RECT  0.103 199.44 0.347 199.458 ;
     RECT  0.103 172.368 0.355 172.386 ;
     RECT  0.283 194.976 0.355 195.03 ;
     RECT  0.319 196.434 0.355 196.452 ;
     RECT  0.247 161.1 0.391 162.738 ;
     RECT  0.355 172.368 0.391 172.692 ;
     RECT  0.283 174.33 0.391 176.472 ;
     RECT  0.355 178.038 0.391 178.254 ;
     RECT  0.355 194.976 0.391 195.174 ;
     RECT  0.355 196.326 0.391 196.452 ;
     RECT  0.283 154.89 0.419 155.574 ;
     RECT  0.391 178.038 0.427 178.326 ;
     RECT  0.391 194.508 0.427 195.174 ;
     RECT  0.203 165.078 0.463 165.564 ;
     RECT  0.247 169.776 0.463 170.064 ;
     RECT  0.131 170.901 0.463 170.964 ;
     RECT  0.391 171.828 0.463 172.692 ;
     RECT  0.427 177.876 0.463 178.326 ;
     RECT  0.427 194.508 0.463 195.444 ;
     RECT  0.391 196.326 0.463 196.524 ;
     RECT  0.391 160.596 0.499 162.738 ;
     RECT  0.463 163.53 0.499 163.746 ;
     RECT  0.463 165.078 0.499 165.708 ;
     RECT  0.391 174.33 0.499 176.67 ;
     RECT  0.463 177.768 0.499 178.704 ;
     RECT  0.463 194.508 0.499 196.524 ;
     RECT  0.463 197.676 0.499 197.694 ;
     RECT  0.463 202.716 0.499 202.734 ;
     RECT  0.103 203.616 0.499 204.282 ;
     RECT  0.419 155.556 0.535 155.574 ;
     RECT  0.247 156.366 0.535 156.798 ;
     RECT  0.499 165.078 0.535 165.834 ;
     RECT  0.463 166.77 0.535 166.788 ;
     RECT  0.463 169.776 0.535 170.964 ;
     RECT  0.463 171.828 0.535 173.196 ;
     RECT  0.499 174.33 0.535 176.778 ;
     RECT  0.499 177.57 0.535 178.704 ;
     RECT  0.499 194.508 0.535 197.694 ;
     RECT  0.463 200.448 0.535 200.574 ;
     RECT  0.211 201.762 0.535 201.78 ;
     RECT  0.499 202.716 0.535 204.282 ;
     RECT  0.535 169.551 0.563 170.964 ;
     RECT  0.535 171.828 0.563 178.704 ;
     RECT  0.535 199.836 0.563 200.574 ;
     RECT  0.563 169.551 1.111 170.919 ;
     RECT  0.103 153.666 2.16 153.684 ;
     RECT  0.535 155.556 2.16 156.798 ;
     RECT  0.139 158.436 2.16 158.652 ;
     RECT  0.499 160.596 2.16 163.746 ;
     RECT  0.535 165.078 2.16 166.824 ;
     RECT  0.239 167.976 2.16 168.408 ;
     RECT  1.111 169.506 2.16 170.919 ;
     RECT  0.563 171.828 2.16 178.254 ;
     RECT  0.535 194.202 2.16 197.766 ;
     RECT  0.535 198.9 2.16 198.918 ;
     RECT  0.563 199.836 2.16 200.466 ;
     RECT  0.535 201.762 2.16 204.282 ;
     RECT  0.031 242.406 2.16 242.424 ;
     RECT  2.16 2.151 326.16 369.369 ;
     RECT  326.16 189.108 327.155 191.394 ;
     RECT  326.16 205.038 327.155 207.486 ;
     RECT  326.16 166.266 327.191 172.422 ;
     RECT  326.16 182.592 327.191 186.228 ;
     RECT  327.155 189.45 327.191 191.394 ;
     RECT  326.16 201.258 327.191 204.246 ;
     RECT  326.16 187.794 327.227 187.812 ;
     RECT  327.191 182.592 327.263 185.112 ;
     RECT  327.191 201.258 327.263 203.814 ;
     RECT  327.263 182.592 327.299 184.878 ;
     RECT  327.155 205.074 327.695 206.784 ;
     RECT  327.299 184.176 327.731 184.878 ;
     RECT  327.191 186.21 327.731 186.228 ;
     RECT  327.695 205.308 327.731 206.784 ;
     RECT  327.299 182.592 327.767 183.15 ;
     RECT  326.16 199.674 327.767 199.692 ;
     RECT  327.263 201.87 327.767 203.814 ;
     RECT  327.731 205.308 327.767 205.974 ;
     RECT  326.16 173.448 327.803 175.932 ;
     RECT  326.16 181.746 327.803 181.764 ;
     RECT  327.191 189.486 327.803 191.394 ;
     RECT  326.16 158.022 327.839 165.366 ;
     RECT  327.191 166.428 327.839 172.422 ;
     RECT  327.803 173.448 327.839 175.428 ;
     RECT  327.767 201.87 327.839 202.194 ;
     RECT  327.803 189.756 327.847 191.394 ;
     RECT  327.839 166.428 327.875 171.144 ;
     RECT  327.839 172.17 327.875 172.422 ;
     RECT  327.839 173.448 327.875 175.086 ;
     RECT  327.767 183.006 327.875 183.15 ;
     RECT  327.767 202.95 327.875 203.814 ;
     RECT  327.839 162.954 327.911 165.366 ;
     RECT  327.875 166.428 327.911 170.334 ;
     RECT  327.875 171.126 327.911 171.144 ;
     RECT  327.911 166.428 327.947 170.19 ;
     RECT  327.847 189.756 327.947 191.979 ;
     RECT  327.947 166.428 328.063 169.92 ;
     RECT  326.16 154.476 328.099 154.944 ;
     RECT  327.839 158.022 328.099 162.162 ;
     RECT  328.099 154.431 328.135 155.07 ;
     RECT  326.16 155.862 328.135 156.42 ;
     RECT  327.911 164.538 328.135 165.366 ;
     RECT  328.063 166.356 328.135 169.92 ;
     RECT  327.875 172.404 328.135 172.422 ;
     RECT  327.731 184.176 328.135 184.842 ;
     RECT  327.875 173.448 328.163 174.816 ;
     RECT  327.839 202.176 328.163 202.194 ;
     RECT  327.767 205.308 328.163 205.902 ;
     RECT  328.099 157.518 328.199 162.162 ;
     RECT  327.911 162.954 328.199 163.782 ;
     RECT  328.135 164.538 328.199 169.92 ;
     RECT  327.947 189.756 328.199 191.556 ;
     RECT  328.135 154.386 328.235 156.42 ;
     RECT  328.199 158.436 328.235 158.454 ;
     RECT  328.199 159.246 328.235 159.264 ;
     RECT  328.199 160.056 328.235 162.162 ;
     RECT  328.199 163.764 328.235 163.782 ;
     RECT  328.199 164.538 328.235 166.95 ;
     RECT  328.199 168.426 328.235 169.92 ;
     RECT  328.135 172.404 328.235 172.656 ;
     RECT  328.163 173.952 328.235 174.816 ;
     RECT  328.135 176.184 328.235 176.202 ;
     RECT  328.135 183.276 328.235 184.842 ;
     RECT  328.199 190.224 328.235 191.556 ;
     RECT  327.875 203.256 328.235 203.814 ;
     RECT  328.163 205.614 328.235 205.902 ;
     RECT  327.731 206.766 328.235 206.784 ;
    LAYER M3 ;
     RECT  2.415 2.143 2.505 2.413 ;
     RECT  7.815 2.143 7.905 2.413 ;
     RECT  13.215 2.143 13.305 2.413 ;
     RECT  18.615 2.143 18.705 2.413 ;
     RECT  24.015 2.143 24.105 2.413 ;
     RECT  29.415 2.143 29.505 2.413 ;
     RECT  34.815 2.143 34.905 2.413 ;
     RECT  40.215 2.143 40.305 2.413 ;
     RECT  45.615 2.143 45.705 2.413 ;
     RECT  51.015 2.143 51.105 2.413 ;
     RECT  56.415 2.143 56.505 2.413 ;
     RECT  61.815 2.143 61.905 2.413 ;
     RECT  67.215 2.143 67.305 2.413 ;
     RECT  72.615 2.143 72.705 2.413 ;
     RECT  78.015 2.143 78.105 2.413 ;
     RECT  83.415 2.143 83.505 2.413 ;
     RECT  88.815 2.143 88.905 2.413 ;
     RECT  94.215 2.143 94.305 2.413 ;
     RECT  99.615 2.143 99.705 2.413 ;
     RECT  105.015 2.143 105.105 2.413 ;
     RECT  110.415 2.143 110.505 2.413 ;
     RECT  115.815 2.143 115.905 2.413 ;
     RECT  121.215 2.143 121.305 2.413 ;
     RECT  126.615 2.143 126.705 2.413 ;
     RECT  132.015 2.143 132.105 2.413 ;
     RECT  137.415 2.143 137.505 2.413 ;
     RECT  142.815 2.143 142.905 2.413 ;
     RECT  148.215 2.143 148.305 2.413 ;
     RECT  153.615 2.143 153.705 2.413 ;
     RECT  159.015 2.143 159.105 2.413 ;
     RECT  164.415 2.143 164.505 2.413 ;
     RECT  169.815 2.143 169.905 2.413 ;
     RECT  175.215 2.143 175.305 2.413 ;
     RECT  180.615 2.143 180.705 2.413 ;
     RECT  186.015 2.143 186.105 2.413 ;
     RECT  191.415 2.143 191.505 2.413 ;
     RECT  196.815 2.143 196.905 2.413 ;
     RECT  202.215 2.143 202.305 2.413 ;
     RECT  207.615 2.143 207.705 2.413 ;
     RECT  213.015 2.143 213.105 2.413 ;
     RECT  218.415 2.143 218.505 2.413 ;
     RECT  223.815 2.143 223.905 2.413 ;
     RECT  229.215 2.143 229.305 2.413 ;
     RECT  234.615 2.143 234.705 2.413 ;
     RECT  240.015 2.143 240.105 2.413 ;
     RECT  245.415 2.143 245.505 2.413 ;
     RECT  250.815 2.143 250.905 2.413 ;
     RECT  256.215 2.143 256.305 2.413 ;
     RECT  261.615 2.143 261.705 2.413 ;
     RECT  267.015 2.143 267.105 2.413 ;
     RECT  272.415 2.143 272.505 2.413 ;
     RECT  277.815 2.143 277.905 2.413 ;
     RECT  283.215 2.143 283.305 2.413 ;
     RECT  288.615 2.143 288.705 2.413 ;
     RECT  294.015 2.143 294.105 2.413 ;
     RECT  299.415 2.143 299.505 2.413 ;
     RECT  304.815 2.143 304.905 2.413 ;
     RECT  310.215 2.143 310.305 2.413 ;
     RECT  315.615 2.143 315.705 2.413 ;
     RECT  321.015 2.143 321.105 2.413 ;
     RECT  137.415 2.413 137.697 153.451 ;
     RECT  137.415 153.451 137.826 153.547 ;
     RECT  137.415 153.547 138.546 153.661 ;
     RECT  0.108 153.643 0.126 153.689 ;
     RECT  137.088 153.661 138.546 153.739 ;
     RECT  2.415 2.413 2.697 153.832 ;
     RECT  13.215 2.413 13.497 153.832 ;
     RECT  24.015 2.413 24.297 153.832 ;
     RECT  34.815 2.413 35.097 153.832 ;
     RECT  45.615 2.413 45.897 153.832 ;
     RECT  56.415 2.413 56.697 153.832 ;
     RECT  67.215 2.413 67.497 153.832 ;
     RECT  78.015 2.413 78.297 153.832 ;
     RECT  88.815 2.413 89.097 153.832 ;
     RECT  99.615 2.413 99.897 153.832 ;
     RECT  110.415 2.413 110.697 153.832 ;
     RECT  121.215 2.413 121.497 153.832 ;
     RECT  132.015 2.413 132.297 153.832 ;
     RECT  136.116 153.835 136.134 153.931 ;
     RECT  136.872 153.739 138.546 153.959 ;
     RECT  136.008 153.931 136.134 154.027 ;
     RECT  135.684 154.027 136.134 154.039 ;
     RECT  136.872 153.959 138.15 154.039 ;
     RECT  142.815 2.413 143.097 154.075 ;
     RECT  139.608 154.111 139.626 154.201 ;
     RECT  135.684 154.039 138.15 154.267 ;
     RECT  245.415 2.413 245.697 154.267 ;
     RECT  0.144 154.123 0.162 154.301 ;
     RECT  135.216 154.267 138.15 154.315 ;
     RECT  139.464 154.201 139.626 154.345 ;
     RECT  250.815 2.413 251.097 154.363 ;
     RECT  261.615 2.413 261.897 154.363 ;
     RECT  272.415 2.413 272.697 154.363 ;
     RECT  283.215 2.413 283.497 154.363 ;
     RECT  294.015 2.413 294.297 154.363 ;
     RECT  304.815 2.413 305.097 154.363 ;
     RECT  315.615 2.413 315.897 154.363 ;
     RECT  328.14 154.363 328.158 154.381 ;
     RECT  245.415 154.267 246.258 154.397 ;
     RECT  328.14 154.381 328.23 154.408 ;
     RECT  13.104 153.832 13.497 154.409 ;
     RECT  23.904 153.832 24.297 154.409 ;
     RECT  34.704 153.832 35.097 154.409 ;
     RECT  45.504 153.832 45.897 154.409 ;
     RECT  56.304 153.832 56.697 154.409 ;
     RECT  67.104 153.832 67.497 154.409 ;
     RECT  77.904 153.832 78.297 154.409 ;
     RECT  88.704 153.832 89.097 154.409 ;
     RECT  99.504 153.832 99.897 154.409 ;
     RECT  110.304 153.832 110.697 154.409 ;
     RECT  121.104 153.832 121.497 154.409 ;
     RECT  250.704 154.363 251.097 154.409 ;
     RECT  261.504 154.363 261.897 154.409 ;
     RECT  272.304 154.363 272.697 154.409 ;
     RECT  283.104 154.363 283.497 154.409 ;
     RECT  293.904 154.363 294.297 154.409 ;
     RECT  304.704 154.363 305.097 154.409 ;
     RECT  315.504 154.363 315.897 154.409 ;
     RECT  2.304 153.832 2.697 154.445 ;
     RECT  243.504 154.267 243.522 154.471 ;
     RECT  328.104 154.408 328.23 154.471 ;
     RECT  243.504 154.471 243.702 154.499 ;
     RECT  242.496 154.315 242.514 154.507 ;
     RECT  243.684 154.499 243.702 154.507 ;
     RECT  327.744 154.471 328.23 154.541 ;
     RECT  243.684 154.507 243.774 154.571 ;
     RECT  135 154.315 138.15 154.603 ;
     RECT  139.392 154.345 139.626 154.603 ;
     RECT  242.244 154.507 242.514 154.643 ;
     RECT  243.756 154.571 243.774 154.643 ;
     RECT  166.356 154.543 166.374 154.651 ;
     RECT  322.056 154.507 322.074 154.679 ;
     RECT  2.415 154.445 2.697 154.741 ;
     RECT  166.356 154.651 166.482 154.741 ;
     RECT  133.632 154.603 133.65 154.769 ;
     RECT  2.415 154.741 2.79 154.781 ;
     RECT  131.904 153.832 132.297 154.795 ;
     RECT  171.54 154.747 171.558 154.843 ;
     RECT  138.996 154.603 139.626 154.849 ;
     RECT  166.356 154.741 166.518 154.849 ;
     RECT  134.532 154.603 138.15 154.877 ;
     RECT  135.18 154.877 138.15 154.885 ;
     RECT  0.288 154.843 0.414 154.891 ;
     RECT  164.415 2.413 164.697 154.921 ;
     RECT  242.496 154.643 242.514 154.921 ;
     RECT  164.415 154.921 165.402 155.011 ;
     RECT  166.356 154.849 166.734 155.011 ;
     RECT  167.472 154.891 167.49 155.011 ;
     RECT  171.54 154.843 172.206 155.011 ;
     RECT  328.032 154.541 328.23 155.021 ;
     RECT  133.668 154.813 133.794 155.039 ;
     RECT  242.496 154.921 242.694 155.039 ;
     RECT  240.015 2.413 240.297 155.131 ;
     RECT  135.18 154.885 138.222 155.155 ;
     RECT  138.996 154.849 139.986 155.155 ;
     RECT  141.948 155.119 141.966 155.155 ;
     RECT  141.444 155.155 141.966 155.191 ;
     RECT  0.288 154.891 0.486 155.275 ;
     RECT  135.18 155.155 139.986 155.281 ;
     RECT  141.192 155.191 141.966 155.281 ;
     RECT  142.815 154.075 143.334 155.281 ;
     RECT  164.415 155.011 166.734 155.281 ;
     RECT  324.9 155.227 324.918 155.281 ;
     RECT  244.224 154.795 244.242 155.309 ;
     RECT  324.9 155.281 325.494 155.309 ;
     RECT  130.536 155.179 130.554 155.357 ;
     RECT  325.476 155.309 325.494 155.357 ;
     RECT  163.548 154.849 163.566 155.425 ;
     RECT  135.18 155.281 140.13 155.461 ;
     RECT  163.404 155.425 163.566 155.461 ;
     RECT  164.376 155.281 166.734 155.461 ;
     RECT  167.472 155.011 167.634 155.461 ;
     RECT  174.168 155.317 174.186 155.461 ;
     RECT  186.015 2.413 186.297 155.551 ;
     RECT  196.815 2.413 197.097 155.551 ;
     RECT  207.615 2.413 207.897 155.551 ;
     RECT  229.215 2.413 229.497 155.551 ;
     RECT  240.015 155.131 240.714 155.551 ;
     RECT  250.815 154.409 251.097 155.551 ;
     RECT  261.615 154.409 261.897 155.551 ;
     RECT  272.415 154.409 272.697 155.551 ;
     RECT  283.215 154.409 283.497 155.551 ;
     RECT  294.015 154.409 294.297 155.551 ;
     RECT  304.815 154.409 305.097 155.551 ;
     RECT  315.615 154.409 315.897 155.551 ;
     RECT  163.368 155.461 163.566 155.563 ;
     RECT  164.376 155.461 167.634 155.563 ;
     RECT  133.884 155.281 134.154 155.597 ;
     RECT  185.904 155.551 186.297 155.597 ;
     RECT  244.404 155.461 244.422 155.615 ;
     RECT  131.688 154.795 132.297 155.659 ;
     RECT  0.108 155.275 0.486 155.695 ;
     RECT  135.18 155.461 140.418 155.695 ;
     RECT  141.192 155.281 143.334 155.695 ;
     RECT  135.18 155.695 143.334 155.731 ;
     RECT  174.168 155.461 174.33 155.731 ;
     RECT  328.068 155.021 328.23 155.755 ;
     RECT  131.688 155.659 132.894 155.849 ;
     RECT  174.132 155.731 174.33 155.849 ;
     RECT  239.904 155.551 240.714 155.849 ;
     RECT  133.956 155.597 134.154 155.851 ;
     RECT  135.072 155.731 143.334 155.851 ;
     RECT  182.7 155.851 182.718 155.857 ;
     RECT  176.328 155.179 176.346 155.885 ;
     RECT  182.304 155.857 182.718 155.899 ;
     RECT  185.94 155.597 186.297 155.899 ;
     RECT  175.215 2.413 175.497 155.947 ;
     RECT  174.132 155.849 174.15 155.957 ;
     RECT  162.504 155.731 162.522 155.965 ;
     RECT  182.304 155.899 182.862 155.993 ;
     RECT  133.956 155.851 143.334 156.001 ;
     RECT  163.368 155.563 167.634 156.001 ;
     RECT  169.815 2.413 170.097 156.001 ;
     RECT  171.54 155.011 172.278 156.001 ;
     RECT  173.16 155.851 173.178 156.001 ;
     RECT  178.38 155.419 178.398 156.001 ;
     RECT  162.36 155.965 162.522 156.029 ;
     RECT  238.284 155.929 238.302 156.029 ;
     RECT  218.415 2.413 218.697 156.091 ;
     RECT  131.688 155.849 132.786 156.119 ;
     RECT  177.48 155.563 177.498 156.127 ;
     RECT  178.38 156.001 178.542 156.127 ;
     RECT  163.296 156.001 168.174 156.187 ;
     RECT  169.056 155.371 169.074 156.187 ;
     RECT  148.215 2.413 148.497 156.235 ;
     RECT  163.296 156.187 169.074 156.235 ;
     RECT  169.815 156.001 173.898 156.235 ;
     RECT  328.032 155.755 328.23 156.235 ;
     RECT  0.108 155.695 0.558 156.269 ;
     RECT  133.956 156.001 143.694 156.271 ;
     RECT  163.296 156.235 173.898 156.271 ;
     RECT  177.48 156.127 178.542 156.271 ;
     RECT  179.532 156.001 179.55 156.271 ;
     RECT  175.215 155.947 176.31 156.379 ;
     RECT  0.108 156.269 0.27 156.389 ;
     RECT  133.956 156.271 144.306 156.389 ;
     RECT  182.448 155.993 182.862 156.425 ;
     RECT  327.996 156.235 328.23 156.425 ;
     RECT  185.94 155.899 186.39 156.523 ;
     RECT  162.54 156.271 173.898 156.533 ;
     RECT  190.404 156.397 190.422 156.533 ;
     RECT  177.48 156.271 179.55 156.541 ;
     RECT  180.615 2.413 180.897 156.541 ;
     RECT  133.956 156.389 133.974 156.569 ;
     RECT  196.704 155.551 197.097 156.569 ;
     RECT  207.504 155.551 207.897 156.569 ;
     RECT  218.304 156.091 218.697 156.569 ;
     RECT  229.104 155.551 229.497 156.569 ;
     RECT  239.904 155.849 240.297 156.569 ;
     RECT  250.704 155.551 251.097 156.569 ;
     RECT  261.504 155.551 261.897 156.569 ;
     RECT  272.304 155.551 272.697 156.569 ;
     RECT  283.104 155.551 283.497 156.569 ;
     RECT  293.904 155.551 294.297 156.569 ;
     RECT  304.704 155.551 305.097 156.569 ;
     RECT  315.504 155.551 315.897 156.569 ;
     RECT  159.015 2.413 159.297 156.631 ;
     RECT  183.96 156.139 183.978 156.631 ;
     RECT  325.476 156.475 325.494 156.631 ;
     RECT  327.996 156.425 328.158 156.653 ;
     RECT  182.448 156.425 182.718 156.695 ;
     RECT  183.96 156.631 184.086 156.695 ;
     RECT  185.904 156.523 186.39 156.703 ;
     RECT  158.688 156.631 159.297 156.715 ;
     RECT  0.108 156.389 0.234 156.803 ;
     RECT  182.448 156.695 182.538 156.811 ;
     RECT  185.724 156.703 186.39 156.811 ;
     RECT  324.9 156.631 325.494 156.901 ;
     RECT  324.9 156.901 325.53 156.941 ;
     RECT  158.688 156.715 159.858 156.955 ;
     RECT  174.888 156.379 176.31 156.955 ;
     RECT  180.324 156.541 180.897 157.073 ;
     RECT  145.404 156.001 145.422 157.081 ;
     RECT  161.604 156.973 161.622 157.081 ;
     RECT  173.268 156.533 173.898 157.081 ;
     RECT  174.672 156.955 176.31 157.081 ;
     RECT  177.048 156.541 179.55 157.081 ;
     RECT  149.904 156.199 149.922 157.171 ;
     RECT  150.732 156.541 150.75 157.171 ;
     RECT  158.688 156.955 160.002 157.171 ;
     RECT  160.74 156.763 160.758 157.171 ;
     RECT  161.496 157.081 161.622 157.171 ;
     RECT  162.54 156.533 172.242 157.171 ;
     RECT  184.068 156.695 184.086 157.195 ;
     RECT  173.268 157.081 176.31 157.207 ;
     RECT  177.048 157.081 179.694 157.207 ;
     RECT  180.504 157.073 180.897 157.237 ;
     RECT  149.904 157.171 150.75 157.271 ;
     RECT  185.724 156.811 186.57 157.291 ;
     RECT  185.58 157.291 186.57 157.339 ;
     RECT  158.688 157.171 160.758 157.351 ;
     RECT  161.496 157.171 172.242 157.351 ;
     RECT  173.268 157.207 179.694 157.351 ;
     RECT  189.036 156.541 189.054 157.351 ;
     RECT  149.976 157.271 150.75 157.477 ;
     RECT  151.596 157.315 151.614 157.477 ;
     RECT  158.616 157.351 160.758 157.477 ;
     RECT  182.376 156.811 182.538 157.477 ;
     RECT  135.036 156.389 144.306 157.483 ;
     RECT  184.068 157.195 184.77 157.483 ;
     RECT  185.58 157.339 186.786 157.483 ;
     RECT  328.068 156.653 328.158 157.483 ;
     RECT  135.036 157.483 144.378 157.513 ;
     RECT  158.58 157.477 160.758 157.531 ;
     RECT  149.976 157.477 151.614 157.549 ;
     RECT  158.472 157.531 160.758 157.577 ;
     RECT  328.068 157.483 328.194 157.579 ;
     RECT  158.616 157.577 160.758 157.586 ;
     RECT  135.036 157.513 144.45 157.621 ;
     RECT  180.504 157.237 181.53 157.621 ;
     RECT  182.376 157.477 182.898 157.621 ;
     RECT  184.068 157.483 186.786 157.621 ;
     RECT  328.032 157.579 328.194 157.675 ;
     RECT  145.404 157.081 145.71 157.739 ;
     RECT  324.9 156.941 325.494 157.757 ;
     RECT  135.036 157.621 144.594 157.771 ;
     RECT  145.404 157.739 145.422 157.771 ;
     RECT  161.496 157.351 179.694 157.811 ;
     RECT  149.976 157.549 152.01 157.813 ;
     RECT  149.976 157.813 152.226 157.819 ;
     RECT  147.636 156.235 148.497 157.847 ;
     RECT  178.38 157.811 179.694 157.847 ;
     RECT  149.976 157.819 152.406 157.855 ;
     RECT  153.615 2.413 153.897 157.855 ;
     RECT  158.976 157.586 160.758 157.855 ;
     RECT  161.496 157.811 177.57 157.855 ;
     RECT  180.504 157.621 182.898 157.855 ;
     RECT  183.78 157.621 186.786 157.855 ;
     RECT  192.528 157.585 192.546 157.855 ;
     RECT  193.464 157.771 193.482 157.855 ;
     RECT  149.976 157.855 153.897 157.867 ;
     RECT  178.452 157.847 179.694 157.867 ;
     RECT  180.432 157.855 186.786 157.867 ;
     RECT  188.676 157.351 189.414 157.891 ;
     RECT  190.404 157.771 190.422 157.891 ;
     RECT  192.528 157.855 193.482 157.891 ;
     RECT  327.96 157.675 328.194 157.963 ;
     RECT  131.688 156.119 132.297 158.009 ;
     RECT  135.036 157.771 145.422 158.017 ;
     RECT  327.96 157.963 328.23 158.017 ;
     RECT  178.452 157.867 186.786 158.045 ;
     RECT  149.976 157.867 154.206 158.053 ;
     RECT  155.592 158.017 155.61 158.053 ;
     RECT  191.415 2.413 191.697 158.089 ;
     RECT  192.528 157.891 194.094 158.089 ;
     RECT  195.264 158.017 195.282 158.089 ;
     RECT  149.472 158.053 154.206 158.125 ;
     RECT  155.556 158.053 155.61 158.125 ;
     RECT  146.196 157.891 146.214 158.161 ;
     RECT  188.676 157.891 190.422 158.161 ;
     RECT  191.415 158.089 194.166 158.161 ;
     RECT  294.015 156.569 294.297 158.245 ;
     RECT  133.38 158.125 133.398 158.251 ;
     RECT  191.415 158.161 194.382 158.251 ;
     RECT  195.264 158.089 195.39 158.251 ;
     RECT  196.815 156.569 197.097 158.251 ;
     RECT  207.615 156.569 207.897 158.251 ;
     RECT  218.415 156.569 218.697 158.251 ;
     RECT  229.215 156.569 229.497 158.251 ;
     RECT  240.015 156.569 240.297 158.251 ;
     RECT  250.815 156.569 251.097 158.251 ;
     RECT  261.615 156.569 261.897 158.251 ;
     RECT  272.415 156.569 272.697 158.251 ;
     RECT  283.215 156.569 283.497 158.251 ;
     RECT  304.815 156.569 305.097 158.251 ;
     RECT  315.615 156.569 315.897 158.251 ;
     RECT  146.196 158.161 146.322 158.279 ;
     RECT  188.676 158.161 190.458 158.287 ;
     RECT  196.704 158.251 197.097 158.288 ;
     RECT  178.452 158.045 183.69 158.315 ;
     RECT  155.52 158.125 155.61 158.359 ;
     RECT  133.38 158.251 133.47 158.387 ;
     RECT  134.856 158.017 145.422 158.431 ;
     RECT  184.5 158.045 186.786 158.431 ;
     RECT  0.108 156.803 0.162 158.459 ;
     RECT  130.536 158.359 130.554 158.459 ;
     RECT  132.015 158.009 132.297 158.521 ;
     RECT  149.472 158.125 154.386 158.521 ;
     RECT  155.124 158.359 155.61 158.521 ;
     RECT  156.96 158.431 156.978 158.521 ;
     RECT  158.976 157.855 177.57 158.521 ;
     RECT  325.44 157.757 325.494 158.521 ;
     RECT  156.708 158.521 156.978 158.557 ;
     RECT  134.532 158.431 145.422 158.593 ;
     RECT  157.932 158.557 157.95 158.593 ;
     RECT  149.472 158.521 155.61 158.629 ;
     RECT  157.896 158.593 157.95 158.629 ;
     RECT  158.688 158.521 177.57 158.629 ;
     RECT  149.472 158.629 155.754 158.635 ;
     RECT  0.144 158.459 0.162 158.657 ;
     RECT  132.015 158.521 132.822 158.657 ;
     RECT  156.636 158.557 156.978 158.665 ;
     RECT  157.896 158.629 177.57 158.665 ;
     RECT  178.452 158.315 183.654 158.665 ;
     RECT  184.5 158.431 186.822 158.665 ;
     RECT  191.415 158.251 195.39 158.665 ;
     RECT  184.5 158.665 186.894 158.701 ;
     RECT  187.668 158.665 187.686 158.701 ;
     RECT  188.64 158.287 190.458 158.701 ;
     RECT  191.415 158.665 196.002 158.701 ;
     RECT  244.116 158.665 244.134 158.701 ;
     RECT  250.704 158.251 251.097 158.717 ;
     RECT  261.504 158.251 261.897 158.717 ;
     RECT  272.304 158.251 272.697 158.717 ;
     RECT  283.104 158.251 283.497 158.717 ;
     RECT  293.904 158.245 294.297 158.717 ;
     RECT  304.704 158.251 305.097 158.717 ;
     RECT  315.504 158.251 315.897 158.717 ;
     RECT  134.532 158.593 145.89 158.729 ;
     RECT  207.504 158.251 207.897 158.729 ;
     RECT  218.304 158.251 218.697 158.729 ;
     RECT  229.104 158.251 229.497 158.729 ;
     RECT  239.904 158.251 240.297 158.729 ;
     RECT  149.472 158.635 155.79 158.731 ;
     RECT  156.564 158.665 156.978 158.731 ;
     RECT  243.936 158.701 244.134 158.819 ;
     RECT  147.24 158.539 147.258 158.827 ;
     RECT  149.472 158.731 156.978 158.863 ;
     RECT  188.64 158.701 196.002 158.927 ;
     RECT  149.472 158.863 157.086 159.019 ;
     RECT  157.896 158.665 183.654 159.019 ;
     RECT  188.64 158.927 195.75 159.053 ;
     RECT  147.132 158.827 147.258 159.061 ;
     RECT  149.472 159.019 183.654 159.061 ;
     RECT  184.5 158.701 187.686 159.061 ;
     RECT  324.9 158.521 325.494 159.061 ;
     RECT  134.856 158.729 145.89 159.097 ;
     RECT  146.988 159.061 147.258 159.097 ;
     RECT  149.472 159.061 187.758 159.115 ;
     RECT  188.64 159.053 193.158 159.115 ;
     RECT  327.744 158.017 328.23 159.149 ;
     RECT  148.215 157.847 148.497 159.169 ;
     RECT  149.472 159.115 193.158 159.169 ;
     RECT  196.815 158.288 197.097 159.241 ;
     RECT  327.996 159.149 328.23 159.269 ;
     RECT  134.856 159.097 147.258 159.331 ;
     RECT  148.215 159.169 193.158 159.331 ;
     RECT  196.596 159.241 197.097 159.389 ;
     RECT  324.9 159.061 325.53 159.389 ;
     RECT  134.856 159.331 193.158 159.467 ;
     RECT  134.856 159.467 167.778 159.503 ;
     RECT  325.44 159.389 325.53 159.539 ;
     RECT  325.44 159.539 325.494 159.629 ;
     RECT  325.476 159.629 325.494 159.809 ;
     RECT  207.615 158.729 207.897 159.871 ;
     RECT  218.415 158.729 218.697 159.871 ;
     RECT  229.215 158.729 229.497 159.871 ;
     RECT  240.015 158.729 240.297 159.871 ;
     RECT  250.815 158.717 251.097 159.871 ;
     RECT  261.615 158.717 261.897 159.871 ;
     RECT  272.415 158.717 272.697 159.871 ;
     RECT  283.215 158.717 283.497 159.871 ;
     RECT  294.015 158.717 294.297 159.871 ;
     RECT  304.815 158.717 305.097 159.871 ;
     RECT  315.615 158.717 315.897 159.871 ;
     RECT  207.504 159.871 207.897 159.917 ;
     RECT  218.304 159.871 218.697 159.917 ;
     RECT  229.104 159.871 229.497 159.917 ;
     RECT  250.704 159.871 251.097 159.917 ;
     RECT  261.504 159.871 261.897 159.917 ;
     RECT  272.304 159.871 272.697 159.917 ;
     RECT  283.104 159.871 283.497 159.917 ;
     RECT  293.904 159.871 294.297 159.917 ;
     RECT  304.704 159.871 305.097 159.917 ;
     RECT  315.504 159.871 315.897 159.917 ;
     RECT  327.996 159.269 328.194 159.943 ;
     RECT  193.932 159.053 195.75 160.051 ;
     RECT  327.744 159.943 328.194 160.051 ;
     RECT  196.815 159.389 197.097 160.141 ;
     RECT  168.552 159.467 188.982 160.211 ;
     RECT  135.252 159.503 167.778 160.249 ;
     RECT  168.552 160.211 188.73 160.249 ;
     RECT  189.756 159.467 193.158 160.249 ;
     RECT  193.896 160.051 195.75 160.249 ;
     RECT  198 160.123 198.018 160.249 ;
     RECT  196.668 160.141 197.097 160.267 ;
     RECT  198 160.249 198.918 160.267 ;
     RECT  135.252 160.249 188.73 160.285 ;
     RECT  13.215 154.409 13.497 160.312 ;
     RECT  24.015 154.409 24.297 160.312 ;
     RECT  34.815 154.409 35.097 160.312 ;
     RECT  45.615 154.409 45.897 160.312 ;
     RECT  56.415 154.409 56.697 160.312 ;
     RECT  67.215 154.409 67.497 160.312 ;
     RECT  78.015 154.409 78.297 160.312 ;
     RECT  88.815 154.409 89.097 160.312 ;
     RECT  99.615 154.409 99.897 160.312 ;
     RECT  110.415 154.409 110.697 160.312 ;
     RECT  121.215 154.409 121.497 160.312 ;
     RECT  2.415 154.781 2.697 160.321 ;
     RECT  189.756 160.249 195.75 160.321 ;
     RECT  234.615 2.413 234.897 160.483 ;
     RECT  189.756 160.321 195.822 160.519 ;
     RECT  189.72 160.519 195.822 160.549 ;
     RECT  196.596 160.267 198.918 160.549 ;
     RECT  128.772 160.459 128.79 160.555 ;
     RECT  130.824 160.315 130.842 160.555 ;
     RECT  189.72 160.549 198.918 160.555 ;
     RECT  234.615 160.483 235.026 160.555 ;
     RECT  327.744 160.051 328.23 160.589 ;
     RECT  128.772 160.555 129.726 160.591 ;
     RECT  130.572 160.555 130.842 160.591 ;
     RECT  132.015 158.657 132.297 160.591 ;
     RECT  189.504 160.555 199.566 160.591 ;
     RECT  239.904 159.871 240.297 160.591 ;
     RECT  128.772 160.591 130.842 160.717 ;
     RECT  132.015 160.591 132.822 160.747 ;
     RECT  128.664 160.717 130.842 160.753 ;
     RECT  131.58 160.747 132.858 160.753 ;
     RECT  135.18 160.285 188.73 160.753 ;
     RECT  327.816 160.589 328.23 160.781 ;
     RECT  207.615 159.917 207.897 160.843 ;
     RECT  218.415 159.917 218.697 160.843 ;
     RECT  229.215 159.917 229.497 160.843 ;
     RECT  250.815 159.917 251.097 160.843 ;
     RECT  261.615 159.917 261.897 160.843 ;
     RECT  272.415 159.917 272.697 160.843 ;
     RECT  283.215 159.917 283.497 160.843 ;
     RECT  294.015 159.917 294.297 160.843 ;
     RECT  304.815 159.917 305.097 160.843 ;
     RECT  315.615 159.917 315.897 160.843 ;
     RECT  126.615 2.413 126.897 160.861 ;
     RECT  128.664 160.753 132.858 160.861 ;
     RECT  189.504 160.591 200.214 160.861 ;
     RECT  239.688 160.591 240.297 160.861 ;
     RECT  2.304 160.321 2.697 160.889 ;
     RECT  13.104 160.312 13.497 160.889 ;
     RECT  23.904 160.312 24.297 160.889 ;
     RECT  34.704 160.312 35.097 160.889 ;
     RECT  45.504 160.312 45.897 160.889 ;
     RECT  56.304 160.312 56.697 160.889 ;
     RECT  67.104 160.312 67.497 160.889 ;
     RECT  77.904 160.312 78.297 160.889 ;
     RECT  88.704 160.312 89.097 160.889 ;
     RECT  99.504 160.312 99.897 160.889 ;
     RECT  110.304 160.312 110.697 160.889 ;
     RECT  121.104 160.312 121.497 160.889 ;
     RECT  207.504 160.843 207.897 160.889 ;
     RECT  218.304 160.843 218.697 160.889 ;
     RECT  229.104 160.843 229.497 160.889 ;
     RECT  250.704 160.843 251.097 160.889 ;
     RECT  261.504 160.843 261.897 160.889 ;
     RECT  272.304 160.843 272.697 160.889 ;
     RECT  283.104 160.843 283.497 160.889 ;
     RECT  293.904 160.843 294.297 160.889 ;
     RECT  304.704 160.843 305.097 160.889 ;
     RECT  315.504 160.843 315.897 160.889 ;
     RECT  0.396 160.591 0.414 160.939 ;
     RECT  128.664 160.861 132.894 160.951 ;
     RECT  133.74 160.753 133.758 160.951 ;
     RECT  232.344 160.459 232.362 160.979 ;
     RECT  128.664 160.951 133.758 161.021 ;
     RECT  234.615 160.555 235.458 161.059 ;
     RECT  238.392 160.843 238.41 161.059 ;
     RECT  0.108 160.939 0.414 161.131 ;
     RECT  135.108 160.753 188.73 161.131 ;
     RECT  189.504 160.861 200.754 161.131 ;
     RECT  238.392 161.059 238.482 161.131 ;
     RECT  0.108 161.131 0.45 161.132 ;
     RECT  232.56 161.083 232.578 161.159 ;
     RECT  0.144 161.132 0.45 161.221 ;
     RECT  234.615 161.059 235.494 161.249 ;
     RECT  133.776 161.095 133.902 161.257 ;
     RECT  135.108 161.131 201.114 161.257 ;
     RECT  238.212 161.131 238.482 161.285 ;
     RECT  128.664 161.021 132.966 161.321 ;
     RECT  128.664 161.321 131.13 161.365 ;
     RECT  126.54 160.861 126.897 161.401 ;
     RECT  127.692 161.365 131.13 161.401 ;
     RECT  236.664 161.035 236.682 161.401 ;
     RECT  236.16 161.401 236.682 161.491 ;
     RECT  241.2 160.843 241.218 161.491 ;
     RECT  239.652 160.861 240.297 161.515 ;
     RECT  241.2 161.491 241.722 161.515 ;
     RECT  236.16 161.491 237.15 161.519 ;
     RECT  328.032 160.781 328.23 161.563 ;
     RECT  327.852 161.563 328.23 161.599 ;
     RECT  239.652 161.515 241.722 161.645 ;
     RECT  0.144 161.221 0.522 161.761 ;
     RECT  126.54 161.401 131.13 161.761 ;
     RECT  133.776 161.257 201.114 161.795 ;
     RECT  0.144 161.761 0.558 161.885 ;
     RECT  237.132 161.519 237.15 161.885 ;
     RECT  126.18 161.761 131.13 161.899 ;
     RECT  199.512 161.795 201.114 161.941 ;
     RECT  131.976 161.321 132.966 162.031 ;
     RECT  133.776 161.795 198.522 162.031 ;
     RECT  239.652 161.645 241.362 162.059 ;
     RECT  125.532 161.899 131.13 162.139 ;
     RECT  327.744 161.599 328.23 162.167 ;
     RECT  125.424 162.139 131.13 162.187 ;
     RECT  327.744 162.167 328.194 162.187 ;
     RECT  0.216 161.885 0.558 162.283 ;
     RECT  0.216 162.283 0.63 162.301 ;
     RECT  327.672 162.187 328.194 162.317 ;
     RECT  125.172 162.187 131.13 162.337 ;
     RECT  0.216 162.301 0.702 162.365 ;
     RECT  125.172 162.337 131.202 162.373 ;
     RECT  131.976 162.031 198.522 162.373 ;
     RECT  199.512 161.941 201.186 162.401 ;
     RECT  2.415 160.889 2.697 162.472 ;
     RECT  13.215 160.889 13.497 162.472 ;
     RECT  24.015 160.889 24.297 162.472 ;
     RECT  34.815 160.889 35.097 162.472 ;
     RECT  45.615 160.889 45.897 162.472 ;
     RECT  56.415 160.889 56.697 162.472 ;
     RECT  67.215 160.889 67.497 162.472 ;
     RECT  78.015 160.889 78.297 162.472 ;
     RECT  88.815 160.889 89.097 162.472 ;
     RECT  99.615 160.889 99.897 162.472 ;
     RECT  110.415 160.889 110.697 162.472 ;
     RECT  121.215 160.889 121.497 162.472 ;
     RECT  2.304 162.472 2.697 162.509 ;
     RECT  34.704 162.472 35.097 162.605 ;
     RECT  110.304 162.472 110.697 162.605 ;
     RECT  13.104 162.472 13.497 162.608 ;
     RECT  23.904 162.472 24.297 162.608 ;
     RECT  45.504 162.472 45.897 162.608 ;
     RECT  56.304 162.472 56.697 162.608 ;
     RECT  67.104 162.472 67.497 162.608 ;
     RECT  77.904 162.472 78.297 162.608 ;
     RECT  88.704 162.472 89.097 162.608 ;
     RECT  99.504 162.472 99.897 162.608 ;
     RECT  121.104 162.472 121.497 162.608 ;
     RECT  199.512 162.401 200.862 162.667 ;
     RECT  0.216 162.365 0.63 162.715 ;
     RECT  125.172 162.373 198.522 162.715 ;
     RECT  199.296 162.667 200.862 162.715 ;
     RECT  325.476 162.667 325.494 162.841 ;
     RECT  324.9 162.841 325.494 162.869 ;
     RECT  324.9 162.869 324.918 162.893 ;
     RECT  125.172 162.715 200.862 162.941 ;
     RECT  168.66 162.941 200.862 163.013 ;
     RECT  0.144 162.715 0.63 163.085 ;
     RECT  0.144 163.085 0.558 163.181 ;
     RECT  168.66 163.013 200.718 163.211 ;
     RECT  168.66 163.211 199.71 163.283 ;
     RECT  200.52 163.211 200.718 163.283 ;
     RECT  125.172 162.941 167.706 163.291 ;
     RECT  2.415 162.509 2.697 163.381 ;
     RECT  168.66 163.283 198.882 163.409 ;
     RECT  199.692 163.283 199.71 163.409 ;
     RECT  200.52 163.283 200.682 163.409 ;
     RECT  2.415 163.381 2.79 163.421 ;
     RECT  185.796 163.409 198.882 163.445 ;
     RECT  125.064 163.291 167.706 163.469 ;
     RECT  122.544 163.021 122.562 163.489 ;
     RECT  185.868 163.445 198.882 163.517 ;
     RECT  122.544 163.489 122.634 163.553 ;
     RECT  200.52 163.409 200.61 163.553 ;
     RECT  200.52 163.553 200.538 163.565 ;
     RECT  201.456 163.525 201.474 163.565 ;
     RECT  122.616 163.553 122.634 163.589 ;
     RECT  125.604 163.469 167.706 163.589 ;
     RECT  185.868 163.517 198.81 163.589 ;
     RECT  126.108 163.589 165.906 163.715 ;
     RECT  327.744 162.317 328.194 163.723 ;
     RECT  166.716 163.589 167.706 163.759 ;
     RECT  166.716 163.759 167.742 163.795 ;
     RECT  168.66 163.409 185.058 163.795 ;
     RECT  126.144 163.715 165.906 163.859 ;
     RECT  0.468 163.181 0.558 163.915 ;
     RECT  326.088 163.561 326.106 163.949 ;
     RECT  327.744 163.723 328.23 164.141 ;
     RECT  185.868 163.589 198.738 164.189 ;
     RECT  2.415 163.421 2.697 164.191 ;
     RECT  13.215 162.608 13.497 164.191 ;
     RECT  24.015 162.608 24.297 164.191 ;
     RECT  34.815 162.605 35.097 164.191 ;
     RECT  45.615 162.608 45.897 164.191 ;
     RECT  56.415 162.608 56.697 164.191 ;
     RECT  67.215 162.608 67.497 164.191 ;
     RECT  78.015 162.608 78.297 164.191 ;
     RECT  88.815 162.608 89.097 164.191 ;
     RECT  99.615 162.608 99.897 164.191 ;
     RECT  121.215 162.608 121.497 164.191 ;
     RECT  166.716 163.795 185.058 164.191 ;
     RECT  185.868 164.189 194.49 164.191 ;
     RECT  327.78 164.141 328.23 164.237 ;
     RECT  166.716 164.191 194.49 164.255 ;
     RECT  195.552 164.189 198.738 164.255 ;
     RECT  0.108 163.915 0.558 164.333 ;
     RECT  126.615 163.859 165.906 164.333 ;
     RECT  327.852 164.237 328.23 164.333 ;
     RECT  166.716 164.255 194.454 164.335 ;
     RECT  327.888 164.333 328.23 164.429 ;
     RECT  166.176 164.335 194.454 164.489 ;
     RECT  126.615 164.333 165.078 164.632 ;
     RECT  207.615 160.889 207.897 164.632 ;
     RECT  218.415 160.889 218.697 164.632 ;
     RECT  229.215 160.889 229.497 164.632 ;
     RECT  250.815 160.889 251.097 164.632 ;
     RECT  261.615 160.889 261.897 164.632 ;
     RECT  272.415 160.889 272.697 164.632 ;
     RECT  283.215 160.889 283.497 164.632 ;
     RECT  294.015 160.889 294.297 164.632 ;
     RECT  304.815 160.889 305.097 164.632 ;
     RECT  315.615 160.889 315.897 164.632 ;
     RECT  207.504 164.632 207.897 164.669 ;
     RECT  218.304 164.632 218.697 164.669 ;
     RECT  229.104 164.632 229.497 164.669 ;
     RECT  199.764 164.155 199.782 164.717 ;
     RECT  195.588 164.255 198.738 164.759 ;
     RECT  195.588 164.759 196.038 164.765 ;
     RECT  124.236 164.371 124.254 164.911 ;
     RECT  325.476 164.827 325.494 165.001 ;
     RECT  13.104 164.191 13.497 165.037 ;
     RECT  56.304 164.191 56.697 165.037 ;
     RECT  77.904 164.191 78.297 165.037 ;
     RECT  99.504 164.191 99.897 165.037 ;
     RECT  0.108 164.333 0.342 165.073 ;
     RECT  2.304 164.191 2.697 165.073 ;
     RECT  123.588 164.911 124.254 165.073 ;
     RECT  10.836 165.037 10.854 165.109 ;
     RECT  54.72 165.037 54.738 165.109 ;
     RECT  61.815 2.413 62.097 165.109 ;
     RECT  74.664 165.037 74.682 165.109 ;
     RECT  98.604 165.037 98.622 165.109 ;
     RECT  122.544 164.731 122.562 165.115 ;
     RECT  123.588 165.073 124.326 165.115 ;
     RECT  122.544 165.115 124.326 165.137 ;
     RECT  195.588 164.765 195.642 165.137 ;
     RECT  126.504 164.632 165.078 165.145 ;
     RECT  202.215 2.413 202.497 165.163 ;
     RECT  241.344 162.059 241.362 165.163 ;
     RECT  327.96 164.429 328.23 165.163 ;
     RECT  10.836 165.109 10.926 165.173 ;
     RECT  13.104 165.037 13.554 165.173 ;
     RECT  54.72 165.109 54.81 165.173 ;
     RECT  56.304 165.037 56.754 165.173 ;
     RECT  74.664 165.109 74.754 165.173 ;
     RECT  77.904 165.037 78.354 165.173 ;
     RECT  98.604 165.109 98.694 165.173 ;
     RECT  99.504 165.037 99.954 165.173 ;
     RECT  124.236 165.137 124.326 165.173 ;
     RECT  118.584 165.073 118.602 165.181 ;
     RECT  125.604 165.001 125.622 165.181 ;
     RECT  126.504 165.145 165.438 165.181 ;
     RECT  166.32 164.489 194.454 165.181 ;
     RECT  202.104 165.163 202.497 165.181 ;
     RECT  2.304 165.073 2.898 165.182 ;
     RECT  118.584 165.181 118.638 165.182 ;
     RECT  2.304 165.182 2.862 165.209 ;
     RECT  10.908 165.173 10.926 165.209 ;
     RECT  13.104 165.173 13.497 165.209 ;
     RECT  22.86 165.109 22.878 165.209 ;
     RECT  23.904 164.191 24.297 165.209 ;
     RECT  30.852 165.109 30.87 165.209 ;
     RECT  34.704 164.191 35.097 165.209 ;
     RECT  42.804 165.109 42.822 165.209 ;
     RECT  45.504 164.191 45.897 165.209 ;
     RECT  54.792 165.173 54.81 165.209 ;
     RECT  56.304 165.173 56.697 165.209 ;
     RECT  61.815 165.109 62.766 165.209 ;
     RECT  67.104 164.191 67.497 165.209 ;
     RECT  74.736 165.173 74.754 165.209 ;
     RECT  77.904 165.173 78.297 165.209 ;
     RECT  86.688 165.109 86.706 165.209 ;
     RECT  88.704 164.191 89.097 165.209 ;
     RECT  98.676 165.173 98.694 165.209 ;
     RECT  99.504 165.173 99.897 165.209 ;
     RECT  121.104 164.191 121.497 165.209 ;
     RECT  122.544 165.137 123.282 165.209 ;
     RECT  166.32 165.181 194.85 165.209 ;
     RECT  250.704 164.632 251.097 165.209 ;
     RECT  261.504 164.632 261.897 165.209 ;
     RECT  272.304 164.632 272.697 165.209 ;
     RECT  283.104 164.632 283.497 165.209 ;
     RECT  293.904 164.632 294.297 165.209 ;
     RECT  304.704 164.632 305.097 165.209 ;
     RECT  315.504 164.632 315.897 165.209 ;
     RECT  125.604 165.181 165.438 165.259 ;
     RECT  166.32 165.209 193.266 165.259 ;
     RECT  0.108 165.073 0.522 165.271 ;
     RECT  2.415 165.209 2.862 165.299 ;
     RECT  118.62 165.182 118.638 165.299 ;
     RECT  202.104 165.181 202.914 165.299 ;
     RECT  194.04 165.209 194.85 165.343 ;
     RECT  196.815 164.759 198.738 165.343 ;
     RECT  327.888 165.163 328.23 165.343 ;
     RECT  327.744 165.343 328.23 165.355 ;
     RECT  125.604 165.259 193.266 165.371 ;
     RECT  238.104 161.833 238.122 165.547 ;
     RECT  129.276 165.371 193.266 165.569 ;
     RECT  194.04 165.343 195.426 165.605 ;
     RECT  125.604 165.371 128.538 165.643 ;
     RECT  241.344 165.163 241.434 165.643 ;
     RECT  242.208 165.595 242.226 165.643 ;
     RECT  130.14 165.569 193.266 165.677 ;
     RECT  238.104 165.547 238.41 165.677 ;
     RECT  122.544 165.209 122.562 165.713 ;
     RECT  125.316 165.643 128.538 165.713 ;
     RECT  130.212 165.677 193.266 165.725 ;
     RECT  125.316 165.713 125.334 165.749 ;
     RECT  126.615 165.713 128.538 165.749 ;
     RECT  130.536 165.725 193.266 165.749 ;
     RECT  0.108 165.271 0.558 165.773 ;
     RECT  126.615 165.749 127.674 165.839 ;
     RECT  128.448 165.749 128.538 165.839 ;
     RECT  129.276 165.569 129.294 165.839 ;
     RECT  130.536 165.749 130.734 165.839 ;
     RECT  131.652 165.749 193.266 165.839 ;
     RECT  194.256 165.605 195.426 165.839 ;
     RECT  131.868 165.839 193.266 165.869 ;
     RECT  241.344 165.643 242.226 165.869 ;
     RECT  327.636 165.355 328.23 165.869 ;
     RECT  194.256 165.839 195.318 165.875 ;
     RECT  131.904 165.869 193.266 165.955 ;
     RECT  194.256 165.875 195.138 166.019 ;
     RECT  242.208 165.869 242.226 166.019 ;
     RECT  324.9 165.001 325.494 166.109 ;
     RECT  196.815 165.343 198.99 166.145 ;
     RECT  324.9 166.109 324.918 166.157 ;
     RECT  322.056 166.081 322.074 166.253 ;
     RECT  2.415 165.299 2.697 166.261 ;
     RECT  327.168 166.027 327.186 166.289 ;
     RECT  13.215 165.209 13.497 166.351 ;
     RECT  24.015 165.209 24.297 166.351 ;
     RECT  34.815 165.209 35.097 166.351 ;
     RECT  45.615 165.209 45.897 166.351 ;
     RECT  56.415 165.209 56.697 166.351 ;
     RECT  61.815 165.209 62.097 166.351 ;
     RECT  67.215 165.209 67.497 166.351 ;
     RECT  78.015 165.209 78.297 166.351 ;
     RECT  88.815 165.209 89.097 166.351 ;
     RECT  99.615 165.209 99.897 166.351 ;
     RECT  121.215 165.209 121.497 166.351 ;
     RECT  207.615 164.669 207.897 166.351 ;
     RECT  218.415 164.669 218.697 166.351 ;
     RECT  229.215 164.669 229.497 166.351 ;
     RECT  250.815 165.209 251.097 166.351 ;
     RECT  261.615 165.209 261.897 166.351 ;
     RECT  272.415 165.209 272.697 166.351 ;
     RECT  283.215 165.209 283.497 166.351 ;
     RECT  294.015 165.209 294.297 166.351 ;
     RECT  304.815 165.209 305.097 166.351 ;
     RECT  315.615 165.209 315.897 166.351 ;
     RECT  2.415 166.261 2.862 166.379 ;
     RECT  131.904 165.955 193.482 166.379 ;
     RECT  207.504 166.351 207.897 166.397 ;
     RECT  218.304 166.351 218.697 166.397 ;
     RECT  229.104 166.351 229.497 166.397 ;
     RECT  10.836 166.351 10.854 166.451 ;
     RECT  22.824 166.351 22.842 166.451 ;
     RECT  30.78 166.351 30.798 166.451 ;
     RECT  42.768 166.351 42.786 166.451 ;
     RECT  54.72 166.351 54.738 166.451 ;
     RECT  61.815 166.351 62.73 166.451 ;
     RECT  74.664 166.351 74.682 166.451 ;
     RECT  86.652 166.351 86.67 166.451 ;
     RECT  98.604 166.351 98.622 166.451 ;
     RECT  118.584 166.351 118.602 166.451 ;
     RECT  196.815 166.145 198.738 166.531 ;
     RECT  202.215 165.299 202.497 166.531 ;
     RECT  199.512 166.189 199.602 166.603 ;
     RECT  128.52 165.839 128.538 166.621 ;
     RECT  131.904 166.379 132.534 166.649 ;
     RECT  133.596 166.379 193.482 166.649 ;
     RECT  130.536 165.839 130.626 166.657 ;
     RECT  131.904 166.649 132.39 166.685 ;
     RECT  130.536 166.657 130.842 166.693 ;
     RECT  131.904 166.685 132.297 166.693 ;
     RECT  196.776 166.531 198.738 166.729 ;
     RECT  200.664 166.603 200.682 166.729 ;
     RECT  128.412 166.621 128.538 166.733 ;
     RECT  133.956 166.649 193.482 166.747 ;
     RECT  194.256 166.019 195.066 166.747 ;
     RECT  126.615 165.839 126.897 166.765 ;
     RECT  128.52 166.733 128.538 166.765 ;
     RECT  129.312 166.459 129.582 166.765 ;
     RECT  243.936 166.651 243.954 166.765 ;
     RECT  128.52 166.765 129.582 166.793 ;
     RECT  126.54 166.765 126.897 166.801 ;
     RECT  200.52 166.729 200.682 166.801 ;
     RECT  201.672 166.531 202.497 166.801 ;
     RECT  2.415 166.379 2.697 166.891 ;
     RECT  238.104 165.677 238.122 166.891 ;
     RECT  245.415 154.397 245.697 166.891 ;
     RECT  126.54 166.801 127.602 166.919 ;
     RECT  128.592 166.793 128.97 166.919 ;
     RECT  130.536 166.693 132.297 166.919 ;
     RECT  199.512 166.603 199.746 166.919 ;
     RECT  243.36 166.765 243.954 166.919 ;
     RECT  128.916 166.919 128.97 166.925 ;
     RECT  199.548 166.919 199.746 166.927 ;
     RECT  200.52 166.801 202.497 166.927 ;
     RECT  128.952 166.925 128.97 166.991 ;
     RECT  130.536 166.919 130.662 166.991 ;
     RECT  238.104 166.891 238.302 166.991 ;
     RECT  245.415 166.891 246.222 166.991 ;
     RECT  245.415 166.991 246.114 166.999 ;
     RECT  126.615 166.919 127.602 167.021 ;
     RECT  133.956 166.747 195.066 167.035 ;
     RECT  328.032 165.869 328.23 167.083 ;
     RECT  0.468 165.773 0.558 167.117 ;
     RECT  243.936 166.919 243.954 167.161 ;
     RECT  133.956 167.035 195.57 167.179 ;
     RECT  243.936 167.161 244.134 167.189 ;
     RECT  245.412 166.999 246.114 167.189 ;
     RECT  0.468 167.117 0.486 167.213 ;
     RECT  244.116 167.189 244.134 167.261 ;
     RECT  133.956 167.179 195.678 167.269 ;
     RECT  196.704 166.729 198.738 167.269 ;
     RECT  324.9 167.161 324.918 167.275 ;
     RECT  130.536 166.991 130.59 167.309 ;
     RECT  130.536 167.309 130.554 167.323 ;
     RECT  207.615 166.397 207.897 167.323 ;
     RECT  218.415 166.397 218.697 167.323 ;
     RECT  229.215 166.397 229.497 167.323 ;
     RECT  13.104 166.351 13.497 167.369 ;
     RECT  23.904 166.351 24.297 167.369 ;
     RECT  34.704 166.351 35.097 167.369 ;
     RECT  45.504 166.351 45.897 167.369 ;
     RECT  56.304 166.351 56.697 167.369 ;
     RECT  67.104 166.351 67.497 167.369 ;
     RECT  77.904 166.351 78.297 167.369 ;
     RECT  88.704 166.351 89.097 167.369 ;
     RECT  99.504 166.351 99.897 167.369 ;
     RECT  121.104 166.351 121.497 167.369 ;
     RECT  130.248 167.323 130.554 167.369 ;
     RECT  133.956 167.269 198.738 167.369 ;
     RECT  207.504 167.323 207.897 167.369 ;
     RECT  218.304 167.323 218.697 167.369 ;
     RECT  229.104 167.323 229.497 167.369 ;
     RECT  250.704 166.351 251.097 167.369 ;
     RECT  261.504 166.351 261.897 167.369 ;
     RECT  272.304 166.351 272.697 167.369 ;
     RECT  283.104 166.351 283.497 167.369 ;
     RECT  293.904 166.351 294.297 167.369 ;
     RECT  304.704 166.351 305.097 167.369 ;
     RECT  315.504 166.351 315.897 167.369 ;
     RECT  2.304 166.891 2.697 167.405 ;
     RECT  133.956 167.369 135.198 167.459 ;
     RECT  324.9 167.275 325.566 167.459 ;
     RECT  131.76 166.919 132.297 167.501 ;
     RECT  324.9 167.459 325.53 167.501 ;
     RECT  327.852 167.083 328.23 167.503 ;
     RECT  133.956 167.459 134.91 167.567 ;
     RECT  133.956 167.567 134.73 167.603 ;
     RECT  0.144 167.563 0.342 167.693 ;
     RECT  136.008 167.369 198.738 167.701 ;
     RECT  199.548 166.927 202.497 167.701 ;
     RECT  2.415 167.405 2.697 167.707 ;
     RECT  325.44 167.501 325.53 167.729 ;
     RECT  129.996 167.773 130.014 167.837 ;
     RECT  203.292 167.773 203.31 167.873 ;
     RECT  0.144 167.693 0.27 167.947 ;
     RECT  0.108 167.947 0.27 167.971 ;
     RECT  2.415 167.707 2.79 168.029 ;
     RECT  136.008 167.701 202.497 168.139 ;
     RECT  203.22 167.881 203.238 168.139 ;
     RECT  133.956 167.603 134.55 168.151 ;
     RECT  132.015 167.501 132.297 168.349 ;
     RECT  133.02 167.845 133.038 168.349 ;
     RECT  136.008 168.139 203.238 168.385 ;
     RECT  135.648 168.385 203.238 168.421 ;
     RECT  2.415 168.029 2.697 168.511 ;
     RECT  13.215 167.369 13.497 168.511 ;
     RECT  24.015 167.369 24.297 168.511 ;
     RECT  34.815 167.369 35.097 168.511 ;
     RECT  45.615 167.369 45.897 168.511 ;
     RECT  56.415 167.369 56.697 168.511 ;
     RECT  67.215 167.369 67.497 168.511 ;
     RECT  78.015 167.369 78.297 168.511 ;
     RECT  88.815 167.369 89.097 168.511 ;
     RECT  99.615 167.369 99.897 168.511 ;
     RECT  121.215 167.369 121.497 168.511 ;
     RECT  131.364 168.349 133.038 168.511 ;
     RECT  135.576 168.421 203.238 168.511 ;
     RECT  130.464 168.511 130.482 168.523 ;
     RECT  135.36 168.511 203.238 168.539 ;
     RECT  133.848 168.151 134.55 168.571 ;
     RECT  135.36 168.539 203.094 168.571 ;
     RECT  133.848 168.571 203.094 168.611 ;
     RECT  130.464 168.523 130.554 168.655 ;
     RECT  131.292 168.511 133.038 168.655 ;
     RECT  133.848 168.611 202.77 168.655 ;
     RECT  0.036 167.971 0.27 168.715 ;
     RECT  130.464 168.655 202.77 168.719 ;
     RECT  128.592 168.889 128.61 168.961 ;
     RECT  128.592 168.961 129.726 169.195 ;
     RECT  130.464 168.719 202.554 169.195 ;
     RECT  61.815 166.451 62.097 169.429 ;
     RECT  128.592 169.195 202.554 169.501 ;
     RECT  2.304 168.511 2.697 169.517 ;
     RECT  10.836 169.429 10.854 169.529 ;
     RECT  13.104 168.511 13.497 169.529 ;
     RECT  22.824 169.429 22.842 169.529 ;
     RECT  23.904 168.511 24.297 169.529 ;
     RECT  30.78 169.429 30.798 169.529 ;
     RECT  34.704 168.511 35.097 169.529 ;
     RECT  42.768 169.429 42.786 169.529 ;
     RECT  45.504 168.511 45.897 169.529 ;
     RECT  54.72 169.429 54.738 169.529 ;
     RECT  56.304 168.511 56.697 169.529 ;
     RECT  61.815 169.429 62.73 169.529 ;
     RECT  67.104 168.511 67.497 169.529 ;
     RECT  74.664 169.429 74.682 169.529 ;
     RECT  77.904 168.511 78.297 169.529 ;
     RECT  86.652 169.429 86.67 169.529 ;
     RECT  88.704 168.511 89.097 169.529 ;
     RECT  98.604 169.429 98.622 169.529 ;
     RECT  99.504 168.511 99.897 169.529 ;
     RECT  118.584 169.429 118.602 169.529 ;
     RECT  121.104 168.511 121.497 169.529 ;
     RECT  0.036 168.715 0.342 169.531 ;
     RECT  1.116 169.501 1.134 169.531 ;
     RECT  0.036 169.531 1.134 169.574 ;
     RECT  128.484 169.501 202.554 169.619 ;
     RECT  126.615 167.021 126.897 169.723 ;
     RECT  126.615 169.723 126.99 169.735 ;
     RECT  184.86 169.619 202.554 169.735 ;
     RECT  128.484 169.619 184.122 169.771 ;
     RECT  247.356 166.171 247.374 169.771 ;
     RECT  250.815 167.369 251.097 169.867 ;
     RECT  247.356 169.771 247.986 169.889 ;
     RECT  245.415 167.189 246.114 169.897 ;
     RECT  247.536 169.889 247.986 169.897 ;
     RECT  327.744 167.503 328.23 169.925 ;
     RECT  184.86 169.735 202.59 169.961 ;
     RECT  247.536 169.897 248.13 169.969 ;
     RECT  245.415 169.897 246.33 169.997 ;
     RECT  247.536 169.969 248.202 169.997 ;
     RECT  250.815 169.867 251.19 169.997 ;
     RECT  327.744 169.925 328.05 169.997 ;
     RECT  245.415 169.997 246.258 170.069 ;
     RECT  248.184 169.997 248.202 170.069 ;
     RECT  126.615 169.735 127.386 170.203 ;
     RECT  204.552 169.933 204.57 170.231 ;
     RECT  2.415 169.517 2.697 170.299 ;
     RECT  2.415 170.299 2.79 170.311 ;
     RECT  184.86 169.961 202.554 170.339 ;
     RECT  128.376 169.771 184.122 170.395 ;
     RECT  184.86 170.339 202.497 170.395 ;
     RECT  2.415 170.311 2.862 170.429 ;
     RECT  203.472 169.897 203.49 170.537 ;
     RECT  327.744 169.997 327.942 170.669 ;
     RECT  126.612 170.203 127.386 170.671 ;
     RECT  128.376 170.395 202.497 170.735 ;
     RECT  2.415 170.429 2.697 170.815 ;
     RECT  126.54 170.671 127.386 170.815 ;
     RECT  327.744 170.669 327.906 170.851 ;
     RECT  0.036 169.574 0.594 170.879 ;
     RECT  2.088 170.815 2.697 170.924 ;
     RECT  125.928 170.815 127.386 170.941 ;
     RECT  128.376 170.735 189.702 170.941 ;
     RECT  327.708 170.851 327.906 170.957 ;
     RECT  0.036 170.879 0.558 170.969 ;
     RECT  125.928 170.941 189.702 170.969 ;
     RECT  13.215 169.529 13.497 171.112 ;
     RECT  24.015 169.529 24.297 171.112 ;
     RECT  34.815 169.529 35.097 171.112 ;
     RECT  45.615 169.529 45.897 171.112 ;
     RECT  56.415 169.529 56.697 171.112 ;
     RECT  67.215 169.529 67.497 171.112 ;
     RECT  78.015 169.529 78.297 171.112 ;
     RECT  88.815 169.529 89.097 171.112 ;
     RECT  99.615 169.529 99.897 171.112 ;
     RECT  121.215 169.529 121.497 171.112 ;
     RECT  0.036 170.969 0.414 171.113 ;
     RECT  190.44 170.735 202.497 171.113 ;
     RECT  2.304 170.924 2.697 171.248 ;
     RECT  190.62 171.113 202.497 171.311 ;
     RECT  245.415 170.069 246.114 171.311 ;
     RECT  125.1 171.307 125.118 171.509 ;
     RECT  126.615 170.969 189.702 171.509 ;
     RECT  327.744 170.957 327.906 171.533 ;
     RECT  179.244 171.509 189.702 171.553 ;
     RECT  110.415 162.605 110.697 171.643 ;
     RECT  13.104 171.112 13.497 171.689 ;
     RECT  23.904 171.112 24.297 171.689 ;
     RECT  34.704 171.112 35.097 171.689 ;
     RECT  45.504 171.112 45.897 171.689 ;
     RECT  56.304 171.112 56.697 171.689 ;
     RECT  67.104 171.112 67.497 171.689 ;
     RECT  77.904 171.112 78.297 171.689 ;
     RECT  88.704 171.112 89.097 171.689 ;
     RECT  99.504 171.112 99.897 171.689 ;
     RECT  110.304 171.643 110.697 171.689 ;
     RECT  121.104 171.112 121.497 171.689 ;
     RECT  125.352 171.625 125.37 171.779 ;
     RECT  156.06 171.509 178.506 171.779 ;
     RECT  2.415 171.248 2.697 171.883 ;
     RECT  2.415 171.883 2.718 171.895 ;
     RECT  126.615 171.509 155.286 171.895 ;
     RECT  2.415 171.895 2.862 171.931 ;
     RECT  179.244 171.553 189.774 171.931 ;
     RECT  122.616 171.859 122.634 171.959 ;
     RECT  190.728 171.311 202.497 171.959 ;
     RECT  0.108 171.113 0.414 172.021 ;
     RECT  190.728 171.959 199.134 172.049 ;
     RECT  199.908 171.959 201.006 172.049 ;
     RECT  200.052 172.049 200.07 172.061 ;
     RECT  190.728 172.049 198.99 172.085 ;
     RECT  200.988 172.049 201.006 172.085 ;
     RECT  2.415 171.931 2.898 172.121 ;
     RECT  201.744 171.959 202.497 172.205 ;
     RECT  190.728 172.085 198.738 172.229 ;
     RECT  0.108 172.021 0.558 172.291 ;
     RECT  193.932 172.229 198.738 172.319 ;
     RECT  179.244 171.931 189.99 172.327 ;
     RECT  190.728 172.229 193.158 172.327 ;
     RECT  0.108 172.291 0.63 172.349 ;
     RECT  126.612 171.895 155.286 172.355 ;
     RECT  327.744 171.533 327.87 172.363 ;
     RECT  128.844 172.355 155.286 172.399 ;
     RECT  156.06 171.779 178.434 172.399 ;
     RECT  0.108 172.349 0.594 172.463 ;
     RECT  327.744 172.363 328.23 172.493 ;
     RECT  128.844 172.399 178.434 172.499 ;
     RECT  193.932 172.319 195.714 172.499 ;
     RECT  135.036 172.499 178.434 172.561 ;
     RECT  179.244 172.327 193.158 172.561 ;
     RECT  325.476 172.315 325.494 172.561 ;
     RECT  0.108 172.463 0.558 172.589 ;
     RECT  135.036 172.561 193.158 172.589 ;
     RECT  196.488 172.319 198.738 172.589 ;
     RECT  324.9 172.561 325.494 172.589 ;
     RECT  327.852 172.493 328.23 172.589 ;
     RECT  122.544 172.291 122.562 172.625 ;
     RECT  147.888 172.589 193.086 172.625 ;
     RECT  126.612 172.355 128.07 172.633 ;
     RECT  194.22 172.499 195.714 172.637 ;
     RECT  324.9 172.589 324.918 172.637 ;
     RECT  196.704 172.589 198.738 172.661 ;
     RECT  328.14 172.589 328.23 172.661 ;
     RECT  328.212 172.661 328.23 172.685 ;
     RECT  194.256 172.637 195.714 172.697 ;
     RECT  126.468 172.633 128.07 172.769 ;
     RECT  135.036 172.589 147.15 172.859 ;
     RECT  135.036 172.859 135.81 172.931 ;
     RECT  136.62 172.859 147.15 173.003 ;
     RECT  126.54 172.769 128.07 173.039 ;
     RECT  195.048 172.697 195.642 173.039 ;
     RECT  128.844 172.499 133.614 173.129 ;
     RECT  147.888 172.625 192.654 173.129 ;
     RECT  196.704 172.661 197.766 173.129 ;
     RECT  126.54 173.039 127.35 173.165 ;
     RECT  135.756 172.931 135.81 173.165 ;
     RECT  147.888 173.129 168.786 173.165 ;
     RECT  126.54 173.165 126.897 173.201 ;
     RECT  164.16 173.165 168.786 173.201 ;
     RECT  128.844 173.129 130.95 173.237 ;
     RECT  131.796 173.129 133.614 173.245 ;
     RECT  128.844 173.237 129.474 173.275 ;
     RECT  131.796 173.245 133.686 173.281 ;
     RECT  130.248 173.237 130.95 173.309 ;
     RECT  165.96 173.201 168.786 173.309 ;
     RECT  294.015 167.369 294.297 173.365 ;
     RECT  207.615 167.369 207.897 173.371 ;
     RECT  218.415 167.369 218.697 173.371 ;
     RECT  229.215 167.369 229.497 173.371 ;
     RECT  250.815 169.997 251.097 173.371 ;
     RECT  261.615 167.369 261.897 173.371 ;
     RECT  272.415 167.369 272.697 173.371 ;
     RECT  283.215 167.369 283.497 173.371 ;
     RECT  304.815 167.369 305.097 173.371 ;
     RECT  315.615 167.369 315.897 173.371 ;
     RECT  136.8 173.003 147.15 173.443 ;
     RECT  147.888 173.165 163.386 173.443 ;
     RECT  128.268 173.275 129.474 173.471 ;
     RECT  128.448 173.471 129.474 173.507 ;
     RECT  196.704 173.129 197.442 173.515 ;
     RECT  128.448 173.507 129.186 173.543 ;
     RECT  328.14 173.443 328.158 173.551 ;
     RECT  194.256 172.697 194.274 173.611 ;
     RECT  195.048 173.039 195.066 173.611 ;
     RECT  128.448 173.543 128.466 173.669 ;
     RECT  136.8 173.443 163.386 173.669 ;
     RECT  194.256 173.611 195.066 173.669 ;
     RECT  131.796 173.281 133.758 173.705 ;
     RECT  136.8 173.669 163.242 173.705 ;
     RECT  169.704 173.129 192.654 173.705 ;
     RECT  130.536 173.309 130.95 173.741 ;
     RECT  2.415 172.121 2.697 173.749 ;
     RECT  61.815 169.529 62.097 173.749 ;
     RECT  0.18 172.589 0.558 173.755 ;
     RECT  2.415 173.749 2.862 173.803 ;
     RECT  13.215 171.689 13.497 173.803 ;
     RECT  24.015 171.689 24.297 173.803 ;
     RECT  34.815 171.689 35.097 173.803 ;
     RECT  45.615 171.689 45.897 173.803 ;
     RECT  56.415 171.689 56.697 173.803 ;
     RECT  67.215 171.689 67.497 173.803 ;
     RECT  78.015 171.689 78.297 173.803 ;
     RECT  88.815 171.689 89.097 173.803 ;
     RECT  99.615 171.689 99.897 173.803 ;
     RECT  110.415 171.689 110.697 173.803 ;
     RECT  121.215 171.689 121.497 173.803 ;
     RECT  325.476 173.371 325.494 173.821 ;
     RECT  2.304 173.803 2.862 173.849 ;
     RECT  10.836 173.749 10.854 173.849 ;
     RECT  13.104 173.803 13.497 173.849 ;
     RECT  22.824 173.749 22.842 173.849 ;
     RECT  23.904 173.803 24.297 173.849 ;
     RECT  30.78 173.749 30.798 173.849 ;
     RECT  34.704 173.803 35.097 173.849 ;
     RECT  42.768 173.749 42.786 173.849 ;
     RECT  45.504 173.803 45.897 173.849 ;
     RECT  54.72 173.749 54.738 173.849 ;
     RECT  56.304 173.803 56.697 173.849 ;
     RECT  61.815 173.749 62.73 173.849 ;
     RECT  67.104 173.803 67.497 173.849 ;
     RECT  74.664 173.749 74.682 173.849 ;
     RECT  77.904 173.803 78.297 173.849 ;
     RECT  86.652 173.749 86.67 173.849 ;
     RECT  88.704 173.803 89.097 173.849 ;
     RECT  98.604 173.749 98.622 173.849 ;
     RECT  99.504 173.803 99.897 173.849 ;
     RECT  106.596 173.749 106.614 173.849 ;
     RECT  110.304 173.803 110.697 173.849 ;
     RECT  118.584 173.749 118.602 173.849 ;
     RECT  121.104 173.803 121.497 173.849 ;
     RECT  130.536 173.741 130.554 173.849 ;
     RECT  131.904 173.705 133.758 173.849 ;
     RECT  169.776 173.705 192.654 173.849 ;
     RECT  207.504 173.371 207.897 173.849 ;
     RECT  218.304 173.371 218.697 173.849 ;
     RECT  229.104 173.371 229.497 173.849 ;
     RECT  250.704 173.371 251.097 173.849 ;
     RECT  261.504 173.371 261.897 173.849 ;
     RECT  272.304 173.371 272.697 173.849 ;
     RECT  283.104 173.371 283.497 173.849 ;
     RECT  293.904 173.365 294.297 173.849 ;
     RECT  304.704 173.371 305.097 173.849 ;
     RECT  315.504 173.371 315.897 173.849 ;
     RECT  194.256 173.669 194.994 173.851 ;
     RECT  0.18 173.755 1.17 173.899 ;
     RECT  327.744 173.551 328.158 173.899 ;
     RECT  0.18 173.899 1.242 173.911 ;
     RECT  132.015 173.849 133.758 173.911 ;
     RECT  134.532 173.281 134.55 173.911 ;
     RECT  164.16 173.201 165.042 173.911 ;
     RECT  193.752 173.851 194.994 173.939 ;
     RECT  135.756 173.165 135.774 173.947 ;
     RECT  163.98 173.911 165.042 173.947 ;
     RECT  165.96 173.309 168.21 173.947 ;
     RECT  185.472 173.849 192.654 173.975 ;
     RECT  0.18 173.911 1.314 173.981 ;
     RECT  169.776 173.849 184.734 174.011 ;
     RECT  196.488 173.515 197.442 174.019 ;
     RECT  198.72 172.661 198.738 174.019 ;
     RECT  163.98 173.947 168.21 174.055 ;
     RECT  185.616 173.975 192.654 174.055 ;
     RECT  135.756 173.947 135.918 174.091 ;
     RECT  163.98 174.055 168.57 174.091 ;
     RECT  0.18 173.981 1.242 174.119 ;
     RECT  0.18 174.119 1.17 174.128 ;
     RECT  185.616 174.055 192.762 174.209 ;
     RECT  198.72 174.019 199.098 174.209 ;
     RECT  324.9 173.821 325.494 174.317 ;
     RECT  0.18 174.128 0.558 174.325 ;
     RECT  135.288 174.091 136.062 174.325 ;
     RECT  136.8 173.705 163.062 174.325 ;
     RECT  132.015 173.911 134.55 174.331 ;
     RECT  135.288 174.325 163.062 174.331 ;
     RECT  169.776 174.011 178.794 174.353 ;
     RECT  196.488 174.019 197.946 174.365 ;
     RECT  132.015 174.331 163.062 174.389 ;
     RECT  169.776 174.353 175.986 174.479 ;
     RECT  193.896 173.939 194.994 174.479 ;
     RECT  196.488 174.365 197.442 174.479 ;
     RECT  324.9 174.317 324.918 174.509 ;
     RECT  135.9 174.389 163.062 174.523 ;
     RECT  163.98 174.091 168.93 174.523 ;
     RECT  198.72 174.209 198.99 174.523 ;
     RECT  135.9 174.523 169.038 174.559 ;
     RECT  169.776 174.479 173.574 174.559 ;
     RECT  2.415 173.849 2.697 174.595 ;
     RECT  2.415 174.595 2.79 174.653 ;
     RECT  198.252 174.523 198.99 174.653 ;
     RECT  174.312 174.479 175.986 174.659 ;
     RECT  196.488 174.479 197.097 174.659 ;
     RECT  130.644 174.619 130.662 174.667 ;
     RECT  132.015 174.389 135.126 174.667 ;
     RECT  135.9 174.559 173.574 174.749 ;
     RECT  174.348 174.659 175.986 174.749 ;
     RECT  185.616 174.209 192.654 174.749 ;
     RECT  196.632 174.659 197.097 174.749 ;
     RECT  263.772 174.619 263.79 174.749 ;
     RECT  169.815 174.749 173.502 174.785 ;
     RECT  130.536 174.667 130.662 174.797 ;
     RECT  131.904 174.667 135.126 174.797 ;
     RECT  174.348 174.749 174.366 174.797 ;
     RECT  263.664 174.757 263.682 174.797 ;
     RECT  163.476 174.749 168.75 174.821 ;
     RECT  194.04 174.479 194.382 174.821 ;
     RECT  327.744 173.899 328.23 174.821 ;
     RECT  171.972 174.785 173.502 174.857 ;
     RECT  179.532 174.011 184.734 174.857 ;
     RECT  195.12 174.595 195.138 174.857 ;
     RECT  198.252 174.653 198.45 174.857 ;
     RECT  179.928 174.857 184.734 174.859 ;
     RECT  185.616 174.749 192.51 174.859 ;
     RECT  178.596 174.353 178.794 174.865 ;
     RECT  168.732 174.821 168.75 174.893 ;
     RECT  172.692 174.857 173.502 174.893 ;
     RECT  172.692 174.893 172.71 174.899 ;
     RECT  194.076 174.821 194.382 174.929 ;
     RECT  198.432 174.857 198.45 174.929 ;
     RECT  163.8 174.821 167.886 174.941 ;
     RECT  327.744 174.821 328.05 174.989 ;
     RECT  135.9 174.749 161.658 175.019 ;
     RECT  166.5 174.941 167.886 175.019 ;
     RECT  178.596 174.865 178.938 175.019 ;
     RECT  179.928 174.859 192.51 175.019 ;
     RECT  179.928 175.019 191.826 175.042 ;
     RECT  135.9 175.019 161.442 175.055 ;
     RECT  162.468 174.749 162.558 175.091 ;
     RECT  166.5 175.019 166.698 175.091 ;
     RECT  169.815 174.785 171.198 175.091 ;
     RECT  176.904 174.353 177.858 175.091 ;
     RECT  130.536 174.797 130.626 175.127 ;
     RECT  167.472 175.019 167.886 175.127 ;
     RECT  327.744 174.989 327.87 175.135 ;
     RECT  166.68 175.091 166.698 175.163 ;
     RECT  167.544 175.127 167.886 175.163 ;
     RECT  178.596 175.019 178.614 175.199 ;
     RECT  179.928 175.042 182.142 175.199 ;
     RECT  163.8 174.941 165.726 175.289 ;
     RECT  167.652 175.163 167.886 175.289 ;
     RECT  176.904 175.091 177.426 175.289 ;
     RECT  182.88 175.042 191.826 175.289 ;
     RECT  164.415 175.289 165.726 175.325 ;
     RECT  167.832 175.289 167.886 175.325 ;
     RECT  175.215 174.749 175.986 175.325 ;
     RECT  133.308 174.797 135.126 175.333 ;
     RECT  135.9 175.055 161.334 175.333 ;
     RECT  0.108 174.325 0.558 175.339 ;
     RECT  61.815 173.849 62.097 175.339 ;
     RECT  218.415 173.849 218.697 175.339 ;
     RECT  162.468 175.091 162.486 175.361 ;
     RECT  186.015 175.289 191.826 175.361 ;
     RECT  182.88 175.289 184.626 175.373 ;
     RECT  327.708 175.135 327.87 175.373 ;
     RECT  207.615 173.849 207.897 175.432 ;
     RECT  229.215 173.849 229.497 175.432 ;
     RECT  250.815 173.849 251.097 175.432 ;
     RECT  261.615 173.849 261.897 175.432 ;
     RECT  272.415 173.849 272.697 175.432 ;
     RECT  283.215 173.849 283.497 175.432 ;
     RECT  294.015 173.849 294.297 175.432 ;
     RECT  304.815 173.849 305.097 175.432 ;
     RECT  315.615 173.849 315.897 175.432 ;
     RECT  176.94 175.289 177.426 175.433 ;
     RECT  131.904 174.797 132.498 175.435 ;
     RECT  0.108 175.339 0.666 175.469 ;
     RECT  10.836 175.339 10.854 175.469 ;
     RECT  22.824 175.339 22.842 175.469 ;
     RECT  30.78 175.339 30.798 175.469 ;
     RECT  42.768 175.339 42.786 175.469 ;
     RECT  54.72 175.339 54.738 175.469 ;
     RECT  61.815 175.339 62.73 175.469 ;
     RECT  74.664 175.339 74.682 175.469 ;
     RECT  86.652 175.339 86.67 175.469 ;
     RECT  98.604 175.339 98.622 175.469 ;
     RECT  106.596 175.339 106.614 175.469 ;
     RECT  118.584 175.339 118.602 175.469 ;
     RECT  130.608 175.127 130.626 175.469 ;
     RECT  186.015 175.361 187.542 175.469 ;
     RECT  196.704 174.749 197.097 175.469 ;
     RECT  207.504 175.432 207.897 175.469 ;
     RECT  218.304 175.339 218.697 175.469 ;
     RECT  229.104 175.432 229.497 175.469 ;
     RECT  250.704 175.432 251.097 175.469 ;
     RECT  261.504 175.432 261.897 175.469 ;
     RECT  272.304 175.432 272.697 175.469 ;
     RECT  283.104 175.432 283.497 175.469 ;
     RECT  293.904 175.432 294.297 175.469 ;
     RECT  304.704 175.432 305.097 175.469 ;
     RECT  315.504 175.432 315.897 175.469 ;
     RECT  34.815 173.849 35.097 175.525 ;
     RECT  110.415 173.849 110.697 175.525 ;
     RECT  2.415 174.653 2.697 175.531 ;
     RECT  13.215 173.849 13.497 175.531 ;
     RECT  24.015 173.849 24.297 175.531 ;
     RECT  45.615 173.849 45.897 175.531 ;
     RECT  56.415 173.849 56.697 175.531 ;
     RECT  67.215 173.849 67.497 175.531 ;
     RECT  78.015 173.849 78.297 175.531 ;
     RECT  88.815 173.849 89.097 175.531 ;
     RECT  99.615 173.849 99.897 175.531 ;
     RECT  121.215 173.849 121.497 175.531 ;
     RECT  164.415 175.325 165.654 175.559 ;
     RECT  169.815 175.091 170.658 175.559 ;
     RECT  180.615 175.199 182.142 175.559 ;
     RECT  182.88 175.373 184.302 175.559 ;
     RECT  187.056 175.469 187.542 175.559 ;
     RECT  188.532 175.361 191.826 175.559 ;
     RECT  34.704 175.525 35.097 175.565 ;
     RECT  110.304 175.525 110.697 175.565 ;
     RECT  2.304 175.531 2.697 175.568 ;
     RECT  13.104 175.531 13.497 175.568 ;
     RECT  23.904 175.531 24.297 175.568 ;
     RECT  45.504 175.531 45.897 175.568 ;
     RECT  56.304 175.531 56.697 175.568 ;
     RECT  67.104 175.531 67.497 175.568 ;
     RECT  77.904 175.531 78.297 175.568 ;
     RECT  88.704 175.531 89.097 175.568 ;
     RECT  99.504 175.531 99.897 175.568 ;
     RECT  121.104 175.531 121.497 175.568 ;
     RECT  131.544 175.435 132.498 175.568 ;
     RECT  188.532 175.559 190.458 175.568 ;
     RECT  183.312 175.559 184.302 175.595 ;
     RECT  164.415 175.559 164.79 175.631 ;
     RECT  131.976 175.568 132.498 175.675 ;
     RECT  133.308 175.333 161.334 175.675 ;
     RECT  165.636 175.559 165.654 175.703 ;
     RECT  131.976 175.675 161.334 175.739 ;
     RECT  189.144 175.568 190.458 175.739 ;
     RECT  131.112 175.579 131.238 175.829 ;
     RECT  156.852 175.739 161.334 175.829 ;
     RECT  184.104 175.595 184.302 175.829 ;
     RECT  187.056 175.559 187.074 175.829 ;
     RECT  189.9 175.739 190.458 175.829 ;
     RECT  191.415 175.559 191.826 175.829 ;
     RECT  131.976 175.739 156.078 175.865 ;
     RECT  189.144 175.739 189.162 175.865 ;
     RECT  191.415 175.829 191.79 175.865 ;
     RECT  131.112 175.829 131.202 175.937 ;
     RECT  327.744 175.373 327.87 175.949 ;
     RECT  129.78 175.837 129.798 175.973 ;
     RECT  158.472 175.829 161.334 175.973 ;
     RECT  0.108 175.469 0.594 176.045 ;
     RECT  327.816 175.949 327.87 176.045 ;
     RECT  167.868 175.325 167.886 176.059 ;
     RECT  131.976 175.865 135.666 176.099 ;
     RECT  136.44 175.865 156.078 176.099 ;
     RECT  156.852 175.829 157.518 176.099 ;
     RECT  189.9 175.829 190.026 176.099 ;
     RECT  136.44 176.099 154.998 176.135 ;
     RECT  155.772 176.099 156.078 176.135 ;
     RECT  158.472 175.973 161.154 176.135 ;
     RECT  189.9 176.099 189.918 176.135 ;
     RECT  0.216 176.045 0.594 176.141 ;
     RECT  177.408 175.433 177.426 176.141 ;
     RECT  328.032 176.155 328.158 176.179 ;
     RECT  180.615 175.559 182.034 176.189 ;
     RECT  158.472 176.135 161.01 176.207 ;
     RECT  180.615 176.189 181.386 176.237 ;
     RECT  328.032 176.179 328.23 176.237 ;
     RECT  160.524 176.207 161.01 176.243 ;
     RECT  328.032 176.237 328.05 176.333 ;
     RECT  131.112 175.937 131.13 176.369 ;
     RECT  158.472 176.207 159.75 176.369 ;
     RECT  156.06 176.135 156.078 176.405 ;
     RECT  126.615 173.201 126.897 176.413 ;
     RECT  129.888 175.981 129.906 176.413 ;
     RECT  183.312 175.595 183.33 176.429 ;
     RECT  160.668 176.243 161.01 176.441 ;
     RECT  126.612 176.413 126.897 176.449 ;
     RECT  129.888 176.413 129.978 176.449 ;
     RECT  129.888 176.449 130.05 176.513 ;
     RECT  184.284 175.829 184.302 176.525 ;
     RECT  158.472 176.369 159.642 176.549 ;
     RECT  158.472 176.549 159.297 176.573 ;
     RECT  167.436 176.059 167.886 176.573 ;
     RECT  126.54 176.449 126.897 176.639 ;
     RECT  130.032 176.513 130.05 176.639 ;
     RECT  132.015 176.099 135.666 176.683 ;
     RECT  136.44 176.135 154.638 176.683 ;
     RECT  132.015 176.683 154.638 176.717 ;
     RECT  133.2 176.717 154.638 176.72 ;
     RECT  150.372 176.72 154.638 176.747 ;
     RECT  241.344 165.869 241.362 176.981 ;
     RECT  150.408 176.747 154.638 177.251 ;
     RECT  160.668 176.441 160.686 177.251 ;
     RECT  150.408 177.251 152.19 177.323 ;
     RECT  150.408 177.323 151.038 177.359 ;
     RECT  0.216 176.141 0.558 177.448 ;
     RECT  150.48 177.359 151.038 177.449 ;
     RECT  0.216 177.448 0.594 177.457 ;
     RECT  132.015 176.717 132.297 177.493 ;
     RECT  133.2 176.72 149.31 177.493 ;
     RECT  0.216 177.457 0.666 177.533 ;
     RECT  152.172 177.323 152.19 177.593 ;
     RECT  132.015 177.493 149.31 177.601 ;
     RECT  0.216 177.533 0.558 177.677 ;
     RECT  131.904 177.601 149.31 177.719 ;
     RECT  131.904 177.719 138.546 177.763 ;
     RECT  131.832 177.763 138.546 177.835 ;
     RECT  139.32 177.719 149.31 177.863 ;
     RECT  139.32 177.863 141.93 177.899 ;
     RECT  131.76 177.835 138.546 177.997 ;
     RECT  139.464 177.899 141.93 178.025 ;
     RECT  129.6 177.961 129.618 178.061 ;
     RECT  156.42 176.953 156.438 178.105 ;
     RECT  239.652 162.059 240.297 178.133 ;
     RECT  0.36 177.677 0.558 178.259 ;
     RECT  0.396 178.259 0.558 178.331 ;
     RECT  139.644 178.025 141.93 178.331 ;
     RECT  139.644 178.331 140.886 178.367 ;
     RECT  151.02 177.449 151.038 178.375 ;
     RECT  153.615 177.251 154.638 178.375 ;
     RECT  167.868 176.573 167.886 178.375 ;
     RECT  130.536 177.421 130.554 178.403 ;
     RECT  140.328 178.367 140.886 178.403 ;
     RECT  167.76 178.375 167.886 178.403 ;
     RECT  151.02 178.375 151.074 178.411 ;
     RECT  152.964 178.375 154.638 178.411 ;
     RECT  140.436 178.403 140.886 178.439 ;
     RECT  131.328 177.997 138.546 178.529 ;
     RECT  0.432 178.331 0.558 178.541 ;
     RECT  150.948 178.411 151.074 178.645 ;
     RECT  131.328 178.529 132.297 178.651 ;
     RECT  131.148 178.651 132.297 178.673 ;
     RECT  142.74 177.863 149.31 178.681 ;
     RECT  150.876 178.645 151.686 178.681 ;
     RECT  152.964 178.411 154.71 178.681 ;
     RECT  0.468 178.541 0.558 178.709 ;
     RECT  131.148 178.673 131.166 178.709 ;
     RECT  236.16 161.519 236.178 178.709 ;
     RECT  0.468 178.709 0.486 178.733 ;
     RECT  133.344 178.529 138.546 178.771 ;
     RECT  133.344 178.771 138.87 178.799 ;
     RECT  133.416 178.799 138.87 178.943 ;
     RECT  133.416 178.943 137.697 179.069 ;
     RECT  164.415 175.631 164.697 179.083 ;
     RECT  133.416 179.069 136.494 179.105 ;
     RECT  133.56 179.105 136.134 179.141 ;
     RECT  175.215 175.325 175.497 179.311 ;
     RECT  133.56 179.141 135.126 179.339 ;
     RECT  142.74 178.681 154.71 179.339 ;
     RECT  164.088 179.083 164.697 179.339 ;
     RECT  161.28 179.311 161.298 179.357 ;
     RECT  164.304 179.339 164.697 179.357 ;
     RECT  175.104 179.311 175.497 179.357 ;
     RECT  133.56 179.339 134.874 179.375 ;
     RECT  138.528 178.943 138.87 179.411 ;
     RECT  133.56 179.375 133.578 179.447 ;
     RECT  134.748 179.375 134.874 179.447 ;
     RECT  178.416 179.323 178.434 179.453 ;
     RECT  134.748 179.447 134.766 179.519 ;
     RECT  140.796 178.439 140.886 179.519 ;
     RECT  164.376 179.357 164.697 179.519 ;
     RECT  162.828 179.491 162.846 179.549 ;
     RECT  138.852 179.411 138.87 179.609 ;
     RECT  140.796 179.519 140.814 179.753 ;
     RECT  142.74 179.339 153.897 179.879 ;
     RECT  157.5 176.099 157.518 180.139 ;
     RECT  159.015 176.573 159.297 180.301 ;
     RECT  157.5 180.139 157.554 180.329 ;
     RECT  152.64 179.879 153.897 180.391 ;
     RECT  154.692 179.339 154.71 180.391 ;
     RECT  142.74 179.879 151.902 180.419 ;
     RECT  238.104 166.991 238.122 180.419 ;
     RECT  142.74 180.419 143.298 180.491 ;
     RECT  144.108 180.419 151.902 180.605 ;
     RECT  151.668 180.605 151.902 180.661 ;
     RECT  152.64 180.391 154.71 180.661 ;
     RECT  151.668 180.661 154.71 180.715 ;
     RECT  157.536 180.329 157.554 180.749 ;
     RECT  158.364 180.301 159.297 180.761 ;
     RECT  144.108 180.605 150.858 180.833 ;
     RECT  156.42 178.105 156.474 180.841 ;
     RECT  151.668 180.715 155.034 180.959 ;
     RECT  156.42 180.841 156.798 180.967 ;
     RECT  241.128 180.931 241.146 180.989 ;
     RECT  151.74 180.959 155.034 180.995 ;
     RECT  240.015 178.133 240.297 181.003 ;
     RECT  240.015 181.003 240.822 181.04 ;
     RECT  151.74 180.995 154.71 181.229 ;
     RECT  142.74 180.491 143.097 181.345 ;
     RECT  144.108 180.833 150.786 181.345 ;
     RECT  155.844 180.967 156.798 181.345 ;
     RECT  141.912 178.331 141.93 181.499 ;
     RECT  152.676 181.229 154.71 181.499 ;
     RECT  155.844 181.345 157.338 181.499 ;
     RECT  156.096 181.499 157.338 181.615 ;
     RECT  142.74 181.345 150.786 181.651 ;
     RECT  156.096 181.615 157.518 181.651 ;
     RECT  159.015 180.761 159.297 181.651 ;
     RECT  151.74 181.229 151.902 181.679 ;
     RECT  238.176 181.381 238.194 181.741 ;
     RECT  238.176 181.741 238.302 181.769 ;
     RECT  156.096 181.651 157.662 181.805 ;
     RECT  142.74 181.651 150.894 181.813 ;
     RECT  158.436 181.651 159.297 181.841 ;
     RECT  238.284 181.769 238.302 181.841 ;
     RECT  156.384 181.805 157.662 181.913 ;
     RECT  237.384 181.885 237.402 182.039 ;
     RECT  236.52 181.921 236.538 182.083 ;
     RECT  152.748 181.499 154.71 182.111 ;
     RECT  156.384 181.913 157.266 182.147 ;
     RECT  141.66 181.651 141.678 182.155 ;
     RECT  142.668 181.813 150.894 182.191 ;
     RECT  236.52 182.083 237.222 182.191 ;
     RECT  164.415 179.519 164.697 182.281 ;
     RECT  153.468 182.111 154.71 182.333 ;
     RECT  141.516 182.155 141.678 182.353 ;
     RECT  142.416 182.191 150.894 182.353 ;
     RECT  151.884 181.679 151.902 182.353 ;
     RECT  141.516 182.353 150.894 182.381 ;
     RECT  321.015 2.413 321.297 182.389 ;
     RECT  153.615 182.333 154.71 182.395 ;
     RECT  156.384 182.147 156.474 182.417 ;
     RECT  141.948 182.381 150.894 182.425 ;
     RECT  151.884 182.353 152.73 182.461 ;
     RECT  153.615 182.395 155.178 182.461 ;
     RECT  229.215 175.469 229.497 182.461 ;
     RECT  141.948 182.425 150.93 182.489 ;
     RECT  151.848 182.461 152.73 182.551 ;
     RECT  156.384 182.417 156.438 182.579 ;
     RECT  164.088 182.281 164.697 182.579 ;
     RECT  165.564 182.395 165.582 182.579 ;
     RECT  192.78 182.395 192.798 182.579 ;
     RECT  149.4 182.489 150.93 182.587 ;
     RECT  151.704 182.551 152.73 182.587 ;
     RECT  327.78 181.741 327.798 182.587 ;
     RECT  134.064 182.551 134.082 182.621 ;
     RECT  192.42 182.587 192.438 182.624 ;
     RECT  149.4 182.587 152.73 182.651 ;
     RECT  135.612 182.623 135.63 182.669 ;
     RECT  138.492 182.443 138.51 182.669 ;
     RECT  153.615 182.461 155.574 182.672 ;
     RECT  156.384 182.579 156.402 182.672 ;
     RECT  238.284 182.587 238.302 182.687 ;
     RECT  157.212 182.147 157.266 182.731 ;
     RECT  233.64 182.551 233.658 182.731 ;
     RECT  149.4 182.651 151.83 182.765 ;
     RECT  321.015 182.389 321.39 182.765 ;
     RECT  157.212 182.731 157.302 182.821 ;
     RECT  229.176 182.461 229.497 182.821 ;
     RECT  233.46 182.731 233.658 182.821 ;
     RECT  234.615 161.249 234.897 182.821 ;
     RECT  236.34 182.191 237.222 182.861 ;
     RECT  236.808 182.861 237.222 182.929 ;
     RECT  141.948 182.489 148.626 182.957 ;
     RECT  150.408 182.765 151.83 182.957 ;
     RECT  141.948 182.957 148.59 182.993 ;
     RECT  152.604 182.651 152.73 183.001 ;
     RECT  327.744 182.587 327.798 183.001 ;
     RECT  152.604 183.001 152.766 183.119 ;
     RECT  236.808 182.929 237.366 183.119 ;
     RECT  142.38 182.993 148.59 183.155 ;
     RECT  150.48 182.957 151.83 183.155 ;
     RECT  237.06 183.119 237.366 183.191 ;
     RECT  142.524 183.155 148.59 183.227 ;
     RECT  327.744 183.001 327.87 183.259 ;
     RECT  230.292 182.731 230.31 183.263 ;
     RECT  233.46 182.821 234.897 183.263 ;
     RECT  238.248 183.127 238.266 183.263 ;
     RECT  327.744 183.259 328.158 183.271 ;
     RECT  142.524 183.227 147.186 183.293 ;
     RECT  237.348 183.191 237.366 183.293 ;
     RECT  149.4 182.765 149.418 183.299 ;
     RECT  150.516 183.155 150.534 183.389 ;
     RECT  152.748 183.119 152.766 183.389 ;
     RECT  157.212 182.821 157.374 183.389 ;
     RECT  151.272 183.155 151.83 183.461 ;
     RECT  153.615 182.672 156.402 183.461 ;
     RECT  327.744 183.271 328.23 183.505 ;
     RECT  151.812 183.461 151.83 183.533 ;
     RECT  153.615 183.461 154.926 183.533 ;
     RECT  155.772 183.461 156.402 183.533 ;
     RECT  155.808 183.533 156.402 183.541 ;
     RECT  240.015 181.04 240.297 183.631 ;
     RECT  250.815 175.469 251.097 183.631 ;
     RECT  261.615 175.469 261.897 183.631 ;
     RECT  272.415 175.469 272.697 183.631 ;
     RECT  283.215 175.469 283.497 183.631 ;
     RECT  294.015 175.469 294.297 183.631 ;
     RECT  304.815 175.469 305.097 183.631 ;
     RECT  315.615 175.469 315.897 183.631 ;
     RECT  239.904 183.631 240.297 183.677 ;
     RECT  250.704 183.631 251.097 183.677 ;
     RECT  261.504 183.631 261.897 183.677 ;
     RECT  272.304 183.631 272.697 183.677 ;
     RECT  283.104 183.631 283.497 183.677 ;
     RECT  293.904 183.631 294.297 183.677 ;
     RECT  304.704 183.631 305.097 183.677 ;
     RECT  315.504 183.631 315.897 183.677 ;
     RECT  142.524 183.293 146.07 183.695 ;
     RECT  325.512 183.361 325.53 183.703 ;
     RECT  228.996 182.821 229.497 183.725 ;
     RECT  154.764 183.533 154.782 183.731 ;
     RECT  233.46 183.263 233.658 183.773 ;
     RECT  148.176 183.227 148.59 183.811 ;
     RECT  153.615 183.533 153.897 183.811 ;
     RECT  155.808 183.541 156.474 183.811 ;
     RECT  327.204 183.505 328.23 183.883 ;
     RECT  325.44 183.703 325.53 183.901 ;
     RECT  148.176 183.811 149.13 183.965 ;
     RECT  325.296 183.901 325.53 184.027 ;
     RECT  142.668 183.695 146.07 184.081 ;
     RECT  147.06 183.293 147.186 184.081 ;
     RECT  148.176 183.965 148.497 184.081 ;
     RECT  323.424 184.027 323.442 184.081 ;
     RECT  324.54 184.027 325.53 184.081 ;
     RECT  323.424 184.081 323.622 184.171 ;
     RECT  327.132 183.883 328.23 184.171 ;
     RECT  321.015 182.765 321.297 184.207 ;
     RECT  323.388 184.171 323.658 184.207 ;
     RECT  324.396 184.081 325.782 184.207 ;
     RECT  152.316 184.171 152.334 184.235 ;
     RECT  320.688 184.207 321.297 184.279 ;
     RECT  322.272 184.279 322.29 184.315 ;
     RECT  153.288 183.811 153.897 184.351 ;
     RECT  155.808 183.811 156.978 184.351 ;
     RECT  319.32 184.207 319.338 184.351 ;
     RECT  322.272 184.315 322.578 184.351 ;
     RECT  323.388 184.207 325.782 184.351 ;
     RECT  327.096 184.171 328.23 184.363 ;
     RECT  320.616 184.279 321.297 184.441 ;
     RECT  322.092 184.351 325.782 184.441 ;
     RECT  233.46 183.773 233.478 184.469 ;
     RECT  320.58 184.441 325.782 184.477 ;
     RECT  320.472 184.477 325.782 184.549 ;
     RECT  318.456 184.351 319.338 184.585 ;
     RECT  233.64 184.549 233.658 184.649 ;
     RECT  317.916 184.585 319.338 184.651 ;
     RECT  320.4 184.549 325.782 184.651 ;
     RECT  153 184.351 153.897 184.775 ;
     RECT  150.48 184.747 150.498 184.847 ;
     RECT  326.952 184.363 328.23 184.847 ;
     RECT  142.668 184.081 148.497 184.855 ;
     RECT  326.952 184.847 327.762 184.877 ;
     RECT  155.592 184.351 156.978 184.891 ;
     RECT  326.952 184.877 327.726 184.891 ;
     RECT  317.916 184.651 325.782 184.981 ;
     RECT  155.412 184.891 157.302 185.045 ;
     RECT  155.628 185.045 157.302 185.089 ;
     RECT  317.808 184.981 325.782 185.125 ;
     RECT  150.552 185.017 150.57 185.153 ;
     RECT  155.628 185.089 157.41 185.153 ;
     RECT  142.668 184.855 148.734 185.161 ;
     RECT  315.615 183.677 315.897 185.161 ;
     RECT  317.7 185.125 325.782 185.161 ;
     RECT  142.668 185.161 149.166 185.351 ;
     RECT  315.615 185.161 325.782 185.431 ;
     RECT  326.628 184.891 327.726 185.431 ;
     RECT  315.615 185.431 327.726 185.621 ;
     RECT  142.668 185.351 148.497 185.629 ;
     RECT  156.42 185.153 157.41 185.629 ;
     RECT  156.42 185.629 157.518 185.657 ;
     RECT  156.492 185.657 157.518 185.729 ;
     RECT  326.628 185.621 327.726 185.741 ;
     RECT  156.492 185.729 157.338 185.819 ;
     RECT  156.636 185.819 157.338 185.837 ;
     RECT  142.524 185.629 148.497 185.855 ;
     RECT  154.692 185.803 154.71 185.855 ;
     RECT  151.164 185.803 151.182 185.935 ;
     RECT  142.524 185.855 147.294 185.963 ;
     RECT  327.096 185.741 327.726 185.963 ;
     RECT  142.524 185.963 147.078 186.097 ;
     RECT  156.852 185.837 157.338 186.125 ;
     RECT  153.615 184.775 153.897 186.133 ;
     RECT  327.132 185.963 327.726 186.161 ;
     RECT  157.32 186.125 157.338 186.197 ;
     RECT  155.628 185.971 155.646 186.233 ;
     RECT  327.708 186.161 327.726 186.233 ;
     RECT  153.615 186.133 154.566 186.269 ;
     RECT  151.164 185.935 151.326 186.331 ;
     RECT  315.615 185.621 325.782 186.395 ;
     RECT  151.128 186.331 151.326 186.511 ;
     RECT  151.128 186.511 151.506 186.629 ;
     RECT  142.488 186.097 147.078 186.701 ;
     RECT  153.615 186.269 153.954 186.737 ;
     RECT  315.615 186.395 325.71 186.899 ;
     RECT  315.615 186.899 318.15 186.907 ;
     RECT  142.632 186.701 147.078 186.935 ;
     RECT  151.488 186.629 151.506 186.941 ;
     RECT  142.632 186.935 146.646 187.169 ;
     RECT  318.924 186.899 325.71 187.321 ;
     RECT  313.668 186.871 313.686 187.373 ;
     RECT  142.632 187.169 146.538 187.511 ;
     RECT  261.615 183.677 261.897 187.681 ;
     RECT  288.615 2.413 288.897 187.681 ;
     RECT  318.924 187.321 325.818 187.681 ;
     RECT  195.012 187.531 195.03 187.709 ;
     RECT  261.072 187.681 261.897 187.723 ;
     RECT  288.072 187.681 288.897 187.757 ;
     RECT  289.62 187.717 289.638 187.757 ;
     RECT  193.752 187.819 193.77 187.825 ;
     RECT  315.216 186.907 318.15 187.825 ;
     RECT  147.384 187.321 147.402 187.861 ;
     RECT  148.215 185.855 148.497 187.861 ;
     RECT  314.928 187.825 318.15 187.861 ;
     RECT  318.924 187.681 325.926 187.861 ;
     RECT  260.964 187.723 261.897 187.889 ;
     RECT  193.464 187.825 193.77 187.979 ;
     RECT  190.404 187.819 190.422 187.997 ;
     RECT  311.364 187.987 311.382 188.023 ;
     RECT  310.215 2.413 310.497 188.059 ;
     RECT  311.328 188.023 311.382 188.059 ;
     RECT  312.336 187.987 312.354 188.059 ;
     RECT  193.464 187.979 193.482 188.093 ;
     RECT  310.215 188.059 312.354 188.095 ;
     RECT  137.415 179.069 137.697 188.131 ;
     RECT  310.215 188.095 312.39 188.131 ;
     RECT  147.384 187.861 148.497 188.221 ;
     RECT  310.176 188.131 312.39 188.221 ;
     RECT  310.176 188.221 312.642 188.257 ;
     RECT  142.632 187.511 146.43 188.293 ;
     RECT  142.02 188.293 146.43 188.329 ;
     RECT  136.476 186.709 136.494 188.401 ;
     RECT  137.415 188.131 137.79 188.401 ;
     RECT  141.984 188.329 146.43 188.401 ;
     RECT  309.564 188.257 312.75 188.401 ;
     RECT  314.928 187.861 325.926 188.401 ;
     RECT  136.44 188.401 136.494 188.491 ;
     RECT  137.415 188.401 137.97 188.519 ;
     RECT  314.928 188.401 326.034 188.519 ;
     RECT  309.06 188.401 312.75 188.527 ;
     RECT  314.064 188.329 314.082 188.563 ;
     RECT  314.928 188.519 325.926 188.563 ;
     RECT  141.984 188.401 146.466 188.591 ;
     RECT  151.272 188.563 151.29 188.635 ;
     RECT  153.615 186.737 153.897 188.635 ;
     RECT  309.06 188.527 312.966 188.635 ;
     RECT  142.776 188.591 146.466 188.671 ;
     RECT  151.272 188.635 151.65 188.671 ;
     RECT  309.06 188.635 313.182 188.683 ;
     RECT  314.064 188.563 325.926 188.683 ;
     RECT  147.312 188.221 148.497 188.761 ;
     RECT  152.676 188.635 153.897 188.761 ;
     RECT  151.272 188.671 151.758 188.797 ;
     RECT  152.568 188.761 153.897 188.797 ;
     RECT  234.615 183.263 234.897 188.869 ;
     RECT  327.204 187.789 327.222 188.875 ;
     RECT  142.776 188.671 146.502 188.905 ;
     RECT  147.312 188.761 148.95 188.905 ;
     RECT  151.272 188.797 153.897 188.905 ;
     RECT  309.06 188.683 325.926 188.905 ;
     RECT  142.776 188.905 148.95 188.941 ;
     RECT  149.688 188.923 149.706 188.941 ;
     RECT  150.84 188.905 153.897 188.941 ;
     RECT  327.168 188.875 327.222 188.971 ;
     RECT  142.776 188.941 149.706 189.095 ;
     RECT  327.132 188.971 327.222 189.163 ;
     RECT  150.48 188.941 153.897 189.211 ;
     RECT  308.484 188.905 325.926 189.245 ;
     RECT  309.204 189.245 325.926 189.259 ;
     RECT  327.096 189.163 327.222 189.259 ;
     RECT  232.56 189.103 232.578 189.329 ;
     RECT  159.015 181.841 159.297 189.355 ;
     RECT  155.304 189.373 155.322 189.409 ;
     RECT  159.015 189.355 159.426 189.409 ;
     RECT  234.288 188.869 234.897 189.445 ;
     RECT  155.304 189.409 155.754 189.481 ;
     RECT  159.015 189.409 160.074 189.481 ;
     RECT  309.204 189.259 327.222 189.481 ;
     RECT  306.108 189.481 306.126 189.599 ;
     RECT  233.712 189.445 234.897 189.643 ;
     RECT  155.304 189.481 155.79 189.671 ;
     RECT  309.204 189.481 327.798 189.671 ;
     RECT  149.724 189.211 154.566 189.691 ;
     RECT  155.304 189.671 155.754 189.691 ;
     RECT  308.376 189.571 308.466 189.707 ;
     RECT  167.76 178.403 167.778 189.715 ;
     RECT  313.524 189.671 327.798 189.739 ;
     RECT  149.724 189.691 155.754 189.779 ;
     RECT  159.015 189.481 160.146 189.835 ;
     RECT  168.876 189.259 168.894 189.869 ;
     RECT  309.204 189.671 312.714 189.869 ;
     RECT  167.328 189.715 167.778 189.965 ;
     RECT  136.404 188.491 136.494 189.985 ;
     RECT  136.224 189.985 136.494 190.021 ;
     RECT  137.415 188.519 137.697 190.021 ;
     RECT  142.776 189.095 148.95 190.021 ;
     RECT  149.724 189.779 154.602 190.021 ;
     RECT  159.015 189.835 160.686 190.021 ;
     RECT  233.712 189.643 234.954 190.139 ;
     RECT  309.312 189.869 312.714 190.139 ;
     RECT  309.312 190.139 311.454 190.175 ;
     RECT  158.292 190.021 161.046 190.255 ;
     RECT  136.224 190.021 137.697 190.291 ;
     RECT  136.08 190.291 137.697 190.397 ;
     RECT  155.556 189.779 155.754 190.453 ;
     RECT  141.984 188.591 142.002 190.489 ;
     RECT  142.776 190.021 154.602 190.489 ;
     RECT  157.932 190.255 161.154 190.489 ;
     RECT  157.86 190.489 161.154 190.525 ;
     RECT  234.324 190.139 234.954 190.525 ;
     RECT  141.984 190.489 154.602 190.561 ;
     RECT  155.556 190.453 156.078 190.561 ;
     RECT  157.104 190.525 161.154 190.561 ;
     RECT  236.556 189.409 236.574 190.561 ;
     RECT  141.984 190.561 156.114 190.651 ;
     RECT  157.104 190.561 161.874 190.651 ;
     RECT  141.984 190.651 161.874 190.679 ;
     RECT  157.248 190.679 161.874 190.699 ;
     RECT  308.448 189.707 308.466 190.759 ;
     RECT  140.436 188.059 140.454 190.831 ;
     RECT  308.376 190.759 308.466 190.831 ;
     RECT  309.312 190.175 310.497 190.831 ;
     RECT  312.336 190.139 312.714 190.831 ;
     RECT  313.524 189.739 328.23 190.831 ;
     RECT  234.324 190.525 235.062 190.859 ;
     RECT  141.984 190.679 156.402 190.921 ;
     RECT  308.376 190.831 310.497 190.921 ;
     RECT  307.908 190.921 310.497 190.939 ;
     RECT  311.436 190.175 311.454 190.939 ;
     RECT  141.768 190.921 156.402 190.949 ;
     RECT  230.292 190.831 230.31 190.949 ;
     RECT  312.336 190.831 328.23 190.949 ;
     RECT  140.436 190.831 140.67 190.957 ;
     RECT  141.768 190.949 155.286 190.957 ;
     RECT  157.248 190.699 161.946 190.993 ;
     RECT  312.336 190.949 325.638 191.021 ;
     RECT  326.376 190.949 328.23 191.021 ;
     RECT  307.908 190.939 311.454 191.029 ;
     RECT  312.336 191.021 325.602 191.029 ;
     RECT  237.924 190.381 237.942 191.065 ;
     RECT  307.548 191.029 311.454 191.065 ;
     RECT  312.264 191.029 325.602 191.065 ;
     RECT  234.615 190.859 235.062 191.083 ;
     RECT  236.232 190.561 236.574 191.083 ;
     RECT  240.015 183.677 240.297 191.083 ;
     RECT  250.815 183.677 251.097 191.083 ;
     RECT  261.615 187.889 261.897 191.083 ;
     RECT  272.415 183.677 272.697 191.083 ;
     RECT  283.215 183.677 283.497 191.083 ;
     RECT  294.015 183.677 294.297 191.083 ;
     RECT  304.815 183.677 305.097 191.083 ;
     RECT  157.248 190.993 162.486 191.093 ;
     RECT  326.376 191.021 326.394 191.093 ;
     RECT  239.904 191.083 240.297 191.129 ;
     RECT  250.704 191.083 251.097 191.129 ;
     RECT  261.504 191.083 261.897 191.129 ;
     RECT  272.304 191.083 272.697 191.129 ;
     RECT  283.104 191.083 283.497 191.129 ;
     RECT  293.904 191.083 294.297 191.129 ;
     RECT  304.704 191.083 305.097 191.129 ;
     RECT  234.615 191.083 236.574 191.219 ;
     RECT  237.924 191.065 238.086 191.219 ;
     RECT  306.108 190.987 306.126 191.227 ;
     RECT  236.34 191.219 236.574 191.261 ;
     RECT  157.248 191.093 162.378 191.291 ;
     RECT  327.132 191.021 328.23 191.291 ;
     RECT  140.436 190.957 155.286 191.335 ;
     RECT  136.224 190.397 137.697 191.371 ;
     RECT  307.548 191.065 325.602 191.399 ;
     RECT  140.256 191.335 155.286 191.461 ;
     RECT  237.852 191.263 237.87 191.461 ;
     RECT  307.548 191.399 325.134 191.489 ;
     RECT  139.644 191.461 155.286 191.497 ;
     RECT  237.672 191.461 237.87 191.501 ;
     RECT  306.108 191.227 306.234 191.501 ;
     RECT  139.104 191.497 155.286 191.533 ;
     RECT  156.312 190.949 156.402 191.569 ;
     RECT  157.248 191.291 161.982 191.569 ;
     RECT  138.564 191.533 155.286 191.633 ;
     RECT  136.008 191.371 137.697 191.641 ;
     RECT  138.564 191.633 140.454 191.641 ;
     RECT  234.615 191.219 235.35 191.641 ;
     RECT  234.072 191.641 235.35 191.759 ;
     RECT  236.88 191.569 237.078 191.759 ;
     RECT  237.852 191.501 237.87 191.759 ;
     RECT  156.312 191.569 161.982 191.795 ;
     RECT  234.072 191.759 235.17 191.803 ;
     RECT  133.524 191.569 133.542 191.839 ;
     RECT  233.892 191.803 235.17 191.84 ;
     RECT  138.528 191.641 140.454 191.867 ;
     RECT  133.488 191.839 133.542 191.875 ;
     RECT  230.292 191.767 230.31 191.903 ;
     RECT  234.144 191.84 235.17 191.903 ;
     RECT  132.015 178.673 132.297 191.911 ;
     RECT  133.488 191.875 133.578 191.911 ;
     RECT  134.316 191.371 134.334 191.911 ;
     RECT  135.648 191.641 137.697 191.911 ;
     RECT  141.192 191.633 155.286 191.911 ;
     RECT  156.312 191.795 161.91 191.911 ;
     RECT  234.615 191.903 235.17 191.939 ;
     RECT  236.88 191.759 236.898 191.939 ;
     RECT  327.852 191.291 328.23 191.981 ;
     RECT  327.852 191.981 327.942 191.984 ;
     RECT  141.192 191.911 161.91 192.029 ;
     RECT  306.108 191.501 306.126 192.029 ;
     RECT  315.615 191.489 325.134 192.065 ;
     RECT  161.856 192.029 161.91 192.101 ;
     RECT  162.936 191.911 162.954 192.101 ;
     RECT  138.564 191.867 140.454 192.299 ;
     RECT  138.564 192.299 140.274 192.371 ;
     RECT  132.015 191.911 134.766 192.379 ;
     RECT  135.648 191.911 137.754 192.379 ;
     RECT  141.192 192.029 160.65 192.415 ;
     RECT  141.12 192.415 160.65 192.461 ;
     RECT  138.564 192.371 139.662 192.479 ;
     RECT  160.164 192.461 160.65 192.569 ;
     RECT  141.12 192.461 159.39 192.605 ;
     RECT  160.632 192.569 160.65 192.605 ;
     RECT  138.564 192.479 138.582 192.641 ;
     RECT  139.644 192.479 139.662 192.749 ;
     RECT  141.12 192.605 159.297 192.749 ;
     RECT  161.856 192.101 161.874 192.983 ;
     RECT  307.548 191.489 314.658 192.991 ;
     RECT  315.615 192.065 324.63 192.991 ;
     RECT  132.015 192.379 137.754 193.081 ;
     RECT  141.12 192.749 152.406 193.109 ;
     RECT  153.36 192.749 159.297 193.181 ;
     RECT  141.12 193.109 144.522 193.189 ;
     RECT  153.36 193.181 157.734 193.217 ;
     RECT  307.548 192.991 324.63 193.229 ;
     RECT  140.724 193.189 144.522 193.261 ;
     RECT  315.432 193.229 324.63 193.261 ;
     RECT  307.548 193.229 314.586 193.351 ;
     RECT  132.015 193.081 137.79 193.459 ;
     RECT  140.508 193.261 144.522 193.483 ;
     RECT  140.436 193.483 144.522 193.495 ;
     RECT  145.368 193.109 152.406 193.523 ;
     RECT  153.36 193.217 155.934 193.531 ;
     RECT  139.968 193.495 144.522 193.649 ;
     RECT  153 193.531 155.934 193.649 ;
     RECT  315.432 193.261 324.702 193.649 ;
     RECT  140.724 193.649 144.522 193.685 ;
     RECT  324.432 193.649 324.702 193.685 ;
     RECT  307.476 193.351 314.586 193.729 ;
     RECT  324.432 193.685 324.63 193.793 ;
     RECT  132.015 193.459 137.826 193.801 ;
     RECT  138.996 193.225 139.122 193.801 ;
     RECT  153 193.649 155.79 193.805 ;
     RECT  250.815 191.129 251.097 193.819 ;
     RECT  307.404 193.729 314.586 193.927 ;
     RECT  153 193.805 155.646 193.955 ;
     RECT  156.708 193.217 157.734 193.955 ;
     RECT  131.976 193.801 139.122 193.991 ;
     RECT  158.508 193.181 159.297 193.991 ;
     RECT  153 193.955 154.818 194.027 ;
     RECT  307.332 193.927 314.586 194.035 ;
     RECT  155.628 193.955 155.646 194.063 ;
     RECT  307.224 194.035 314.586 194.063 ;
     RECT  156.708 193.955 156.762 194.099 ;
     RECT  140.76 193.685 144.522 194.155 ;
     RECT  145.368 193.523 152.118 194.155 ;
     RECT  131.976 193.991 137.826 194.189 ;
     RECT  154.62 194.027 154.818 194.189 ;
     RECT  248.976 193.819 248.994 194.189 ;
     RECT  250.452 193.819 251.097 194.189 ;
     RECT  140.76 194.155 152.118 194.195 ;
     RECT  130.824 193.189 130.842 194.197 ;
     RECT  157.752 194.071 157.77 194.225 ;
     RECT  145.62 194.195 152.118 194.261 ;
     RECT  153 194.027 153.897 194.341 ;
     RECT  145.62 194.261 151.47 194.369 ;
     RECT  130.536 194.197 130.842 194.431 ;
     RECT  140.76 194.195 144.594 194.431 ;
     RECT  315.432 193.649 323.514 194.495 ;
     RECT  0.54 194.197 0.558 194.503 ;
     RECT  129.636 194.071 129.654 194.503 ;
     RECT  130.464 194.431 130.842 194.503 ;
     RECT  156.744 194.099 156.762 194.531 ;
     RECT  154.62 194.189 154.638 194.603 ;
     RECT  126.615 176.639 126.897 194.611 ;
     RECT  126.54 194.611 126.897 194.729 ;
     RECT  152.784 194.341 153.897 194.729 ;
     RECT  315.54 194.495 323.514 194.729 ;
     RECT  0.396 194.503 0.558 194.731 ;
     RECT  129.636 194.503 130.842 194.731 ;
     RECT  129.636 194.731 130.878 194.737 ;
     RECT  131.976 194.189 137.697 194.737 ;
     RECT  131.796 194.737 137.697 194.773 ;
     RECT  145.656 194.369 151.47 194.801 ;
     RECT  150.984 194.801 151.002 194.837 ;
     RECT  139.104 193.991 139.122 194.845 ;
     RECT  140.04 194.431 144.594 194.845 ;
     RECT  129.636 194.737 131.022 194.881 ;
     RECT  131.76 194.773 137.697 194.881 ;
     RECT  307.224 194.063 314.334 194.881 ;
     RECT  323.208 194.729 323.514 194.881 ;
     RECT  324.504 193.793 324.63 194.881 ;
     RECT  153.216 194.729 153.897 194.909 ;
     RECT  2.415 175.568 2.697 194.923 ;
     RECT  315.54 194.729 322.362 194.999 ;
     RECT  139.104 194.845 144.594 195.007 ;
     RECT  129.636 194.881 137.697 195.035 ;
     RECT  153.54 194.909 153.897 195.035 ;
     RECT  126.612 194.729 126.897 195.107 ;
     RECT  323.208 194.881 324.63 195.107 ;
     RECT  145.656 194.801 150.138 195.143 ;
     RECT  138.528 195.007 144.594 195.179 ;
     RECT  307.224 194.881 314.622 195.269 ;
     RECT  323.208 195.107 324.306 195.269 ;
     RECT  139.464 195.179 144.594 195.305 ;
     RECT  145.656 195.143 149.67 195.377 ;
     RECT  13.215 175.568 13.497 195.385 ;
     RECT  24.015 175.568 24.297 195.385 ;
     RECT  34.815 175.565 35.097 195.385 ;
     RECT  45.615 175.568 45.897 195.385 ;
     RECT  56.415 175.568 56.697 195.385 ;
     RECT  67.215 175.568 67.497 195.385 ;
     RECT  78.015 175.568 78.297 195.385 ;
     RECT  88.815 175.568 89.097 195.385 ;
     RECT  99.615 175.568 99.897 195.385 ;
     RECT  110.415 175.565 110.697 195.385 ;
     RECT  121.215 175.568 121.497 195.385 ;
     RECT  13.104 195.385 13.497 195.437 ;
     RECT  23.904 195.385 24.297 195.437 ;
     RECT  34.704 195.385 35.097 195.437 ;
     RECT  45.504 195.385 45.897 195.437 ;
     RECT  56.304 195.385 56.697 195.437 ;
     RECT  67.104 195.385 67.497 195.437 ;
     RECT  77.904 195.385 78.297 195.437 ;
     RECT  88.704 195.385 89.097 195.437 ;
     RECT  99.504 195.385 99.897 195.437 ;
     RECT  110.304 195.385 110.697 195.437 ;
     RECT  121.104 195.385 121.497 195.437 ;
     RECT  129.636 195.035 129.654 195.511 ;
     RECT  139.896 195.305 144.594 195.511 ;
     RECT  2.304 194.923 2.697 195.539 ;
     RECT  139.896 195.511 144.774 195.581 ;
     RECT  138.528 195.179 138.726 195.583 ;
     RECT  324.288 195.269 324.306 195.611 ;
     RECT  145.872 195.377 149.67 195.647 ;
     RECT  145.98 195.647 149.67 195.677 ;
     RECT  139.896 195.581 144.486 195.683 ;
     RECT  129.312 195.511 129.654 195.691 ;
     RECT  138.492 195.583 138.726 195.691 ;
     RECT  307.332 195.269 314.622 195.691 ;
     RECT  128.664 195.691 129.654 195.781 ;
     RECT  146.088 195.677 149.67 195.809 ;
     RECT  140.04 195.683 144.486 195.821 ;
     RECT  140.04 195.821 140.058 195.845 ;
     RECT  140.796 195.821 144.486 195.881 ;
     RECT  146.34 195.809 149.67 195.881 ;
     RECT  128.664 195.781 129.762 195.889 ;
     RECT  238.86 195.385 238.878 195.889 ;
     RECT  0.108 194.731 0.558 195.917 ;
     RECT  138.42 195.691 138.726 195.917 ;
     RECT  146.412 195.881 149.67 195.953 ;
     RECT  126.615 195.107 126.897 195.961 ;
     RECT  307.332 195.691 314.838 195.961 ;
     RECT  315.615 194.999 322.362 195.961 ;
     RECT  138.528 195.917 138.726 196.027 ;
     RECT  128.592 195.889 129.762 196.079 ;
     RECT  138.528 196.027 138.762 196.079 ;
     RECT  140.796 195.881 144.378 196.079 ;
     RECT  146.592 195.953 149.67 196.079 ;
     RECT  138.528 196.079 138.69 196.115 ;
     RECT  146.7 196.079 149.67 196.115 ;
     RECT  128.7 196.079 129.762 196.159 ;
     RECT  130.5 195.035 137.697 196.159 ;
     RECT  238.572 195.889 238.878 196.159 ;
     RECT  147.24 196.115 149.67 196.223 ;
     RECT  90.144 195.925 90.162 196.231 ;
     RECT  122.58 196.159 122.598 196.231 ;
     RECT  126.54 195.961 126.897 196.231 ;
     RECT  147.312 196.223 149.67 196.231 ;
     RECT  238.428 196.159 238.878 196.259 ;
     RECT  2.415 195.539 2.697 196.321 ;
     RECT  13.215 195.437 13.497 196.321 ;
     RECT  34.815 195.437 35.097 196.321 ;
     RECT  56.415 195.437 56.697 196.321 ;
     RECT  61.815 175.469 62.097 196.321 ;
     RECT  67.215 195.437 67.497 196.321 ;
     RECT  78.015 195.437 78.297 196.321 ;
     RECT  99.615 195.437 99.897 196.321 ;
     RECT  126.396 196.231 126.99 196.321 ;
     RECT  127.872 196.195 127.962 196.349 ;
     RECT  140.796 196.079 144.054 196.349 ;
     RECT  147.312 196.231 150.138 196.349 ;
     RECT  24.015 195.437 24.297 196.357 ;
     RECT  45.615 195.437 45.897 196.357 ;
     RECT  110.415 195.437 110.697 196.357 ;
     RECT  121.215 195.437 121.497 196.357 ;
     RECT  307.332 195.961 322.614 196.385 ;
     RECT  122.544 196.231 122.598 196.393 ;
     RECT  126.288 196.321 126.99 196.393 ;
     RECT  0.216 195.917 0.558 196.397 ;
     RECT  106.668 196.357 106.686 196.411 ;
     RECT  2.415 196.321 3.006 196.421 ;
     RECT  122.544 196.393 122.634 196.421 ;
     RECT  128.7 196.159 137.697 196.421 ;
     RECT  144.036 196.349 144.054 196.421 ;
     RECT  147.312 196.349 149.022 196.421 ;
     RECT  307.512 196.385 322.614 196.421 ;
     RECT  86.652 196.231 86.67 196.429 ;
     RECT  122.58 196.421 122.634 196.429 ;
     RECT  86.652 196.429 86.742 196.457 ;
     RECT  90.144 196.231 90.414 196.457 ;
     RECT  122.58 196.429 122.67 196.457 ;
     RECT  126.288 196.393 127.17 196.465 ;
     RECT  126.108 196.465 127.17 196.493 ;
     RECT  127.944 196.349 127.962 196.493 ;
     RECT  10.836 196.321 10.854 196.501 ;
     RECT  22.824 196.357 22.842 196.501 ;
     RECT  30.78 196.321 30.798 196.501 ;
     RECT  42.768 196.357 42.786 196.501 ;
     RECT  54.72 196.321 54.738 196.501 ;
     RECT  61.815 196.321 62.73 196.501 ;
     RECT  74.664 196.321 74.682 196.501 ;
     RECT  86.724 196.457 86.742 196.501 ;
     RECT  90.144 196.457 90.342 196.501 ;
     RECT  98.604 196.321 98.622 196.501 ;
     RECT  118.584 196.357 118.602 196.501 ;
     RECT  10.836 196.501 10.926 196.529 ;
     RECT  13.215 196.321 13.554 196.529 ;
     RECT  22.824 196.501 22.914 196.529 ;
     RECT  24.015 196.357 24.354 196.529 ;
     RECT  30.78 196.501 30.87 196.529 ;
     RECT  34.815 196.321 35.154 196.529 ;
     RECT  42.768 196.501 42.858 196.529 ;
     RECT  45.615 196.357 45.954 196.529 ;
     RECT  54.72 196.501 54.81 196.529 ;
     RECT  56.415 196.321 56.754 196.529 ;
     RECT  67.215 196.321 67.554 196.529 ;
     RECT  74.664 196.501 74.754 196.529 ;
     RECT  78.015 196.321 78.354 196.529 ;
     RECT  86.724 196.501 86.814 196.529 ;
     RECT  90 196.501 90.342 196.529 ;
     RECT  98.604 196.501 98.694 196.529 ;
     RECT  99.615 196.321 99.954 196.529 ;
     RECT  106.596 196.411 106.686 196.529 ;
     RECT  110.415 196.357 110.754 196.529 ;
     RECT  118.584 196.501 118.674 196.529 ;
     RECT  121.215 196.357 121.554 196.529 ;
     RECT  122.616 196.457 122.67 196.529 ;
     RECT  128.772 196.421 137.697 196.529 ;
     RECT  140.796 196.349 143.097 196.529 ;
     RECT  141.372 196.529 143.097 196.541 ;
     RECT  2.415 196.421 2.934 196.555 ;
     RECT  13.215 196.529 13.497 196.591 ;
     RECT  24.015 196.529 24.297 196.591 ;
     RECT  34.815 196.529 35.097 196.591 ;
     RECT  45.615 196.529 45.897 196.591 ;
     RECT  56.415 196.529 56.697 196.591 ;
     RECT  67.215 196.529 67.497 196.591 ;
     RECT  78.015 196.529 78.297 196.591 ;
     RECT  88.815 195.437 89.097 196.591 ;
     RECT  99.615 196.529 99.897 196.591 ;
     RECT  110.415 196.529 110.697 196.591 ;
     RECT  121.215 196.529 121.497 196.591 ;
     RECT  2.304 196.555 2.934 196.619 ;
     RECT  10.908 196.529 10.926 196.619 ;
     RECT  22.896 196.529 22.914 196.619 ;
     RECT  30.852 196.529 30.87 196.619 ;
     RECT  42.84 196.529 42.858 196.619 ;
     RECT  54.792 196.529 54.81 196.619 ;
     RECT  61.815 196.501 62.802 196.619 ;
     RECT  74.736 196.529 74.754 196.619 ;
     RECT  86.796 196.529 86.814 196.619 ;
     RECT  98.676 196.529 98.694 196.619 ;
     RECT  106.668 196.529 106.686 196.619 ;
     RECT  118.656 196.529 118.674 196.619 ;
     RECT  122.616 196.529 122.634 196.619 ;
     RECT  126.108 196.493 126.897 196.619 ;
     RECT  128.772 196.529 129.33 196.619 ;
     RECT  130.212 196.529 137.697 196.619 ;
     RECT  141.372 196.541 141.426 196.619 ;
     RECT  142.164 196.541 143.097 196.619 ;
     RECT  147.312 196.421 147.33 196.619 ;
     RECT  13.104 196.591 13.497 196.637 ;
     RECT  23.904 196.591 24.297 196.637 ;
     RECT  34.704 196.591 35.097 196.637 ;
     RECT  45.504 196.591 45.897 196.637 ;
     RECT  56.304 196.591 56.697 196.637 ;
     RECT  67.104 196.591 67.497 196.637 ;
     RECT  77.904 196.591 78.297 196.637 ;
     RECT  88.704 196.591 89.097 196.637 ;
     RECT  99.504 196.591 99.897 196.637 ;
     RECT  110.304 196.591 110.697 196.637 ;
     RECT  121.104 196.591 121.497 196.637 ;
     RECT  126.252 196.619 126.897 196.655 ;
     RECT  129.024 196.619 129.186 196.655 ;
     RECT  138.528 196.115 138.546 196.655 ;
     RECT  142.236 196.619 143.097 196.655 ;
     RECT  307.512 196.421 322.002 196.655 ;
     RECT  130.32 196.619 137.697 196.733 ;
     RECT  133.452 196.733 137.697 196.925 ;
     RECT  322.776 196.771 322.794 196.961 ;
     RECT  151.92 196.651 151.938 196.987 ;
     RECT  153.615 195.035 153.897 196.987 ;
     RECT  130.32 196.733 132.354 197.069 ;
     RECT  133.452 196.925 136.602 197.159 ;
     RECT  151.596 196.987 151.938 197.159 ;
     RECT  315.216 196.655 322.002 197.159 ;
     RECT  153.615 196.987 154.458 197.165 ;
     RECT  135.288 197.159 136.494 197.195 ;
     RECT  307.512 196.655 314.442 197.195 ;
     RECT  133.452 197.159 134.19 197.231 ;
     RECT  135.612 197.195 136.494 197.231 ;
     RECT  94.215 2.413 94.497 197.239 ;
     RECT  94.176 197.239 94.497 197.275 ;
     RECT  136.116 197.231 136.494 197.303 ;
     RECT  93.564 197.275 94.497 197.311 ;
     RECT  0.288 196.397 0.558 197.357 ;
     RECT  90 196.529 90.018 197.419 ;
     RECT  315.576 197.159 322.002 197.437 ;
     RECT  130.32 197.069 132.297 197.465 ;
     RECT  133.452 197.231 133.794 197.465 ;
     RECT  129.168 196.655 129.186 197.501 ;
     RECT  93.564 197.311 94.914 197.581 ;
     RECT  307.764 197.195 314.442 197.581 ;
     RECT  129.816 197.515 129.834 197.609 ;
     RECT  136.116 197.303 136.422 197.609 ;
     RECT  93.564 197.581 95.058 197.671 ;
     RECT  130.752 197.465 132.297 197.699 ;
     RECT  148.215 196.421 149.022 197.699 ;
     RECT  238.86 196.259 238.878 197.735 ;
     RECT  128.52 197.581 128.538 197.741 ;
     RECT  131.004 197.699 132.297 197.771 ;
     RECT  133.776 197.465 133.794 197.771 ;
     RECT  0.468 197.357 0.558 197.837 ;
     RECT  0.468 197.837 0.486 197.933 ;
     RECT  131.508 197.771 132.297 197.941 ;
     RECT  90 197.419 90.666 198.049 ;
     RECT  90 198.049 91.17 198.085 ;
     RECT  315.576 197.437 322.218 198.085 ;
     RECT  323.352 197.851 323.73 198.085 ;
     RECT  86.652 198.013 86.67 198.113 ;
     RECT  2.415 196.619 2.697 198.121 ;
     RECT  90 198.085 91.494 198.121 ;
     RECT  92.304 198.085 92.322 198.121 ;
     RECT  93.564 197.671 95.13 198.121 ;
     RECT  315.576 198.085 323.73 198.121 ;
     RECT  324.504 197.851 324.522 198.121 ;
     RECT  150.12 196.349 150.138 198.149 ;
     RECT  131.508 197.941 132.786 198.239 ;
     RECT  141.408 196.619 141.426 198.239 ;
     RECT  131.508 198.239 132.57 198.269 ;
     RECT  307.764 197.581 314.694 198.277 ;
     RECT  315.576 198.121 324.522 198.277 ;
     RECT  93.528 198.121 95.13 198.283 ;
     RECT  96.372 198.085 96.39 198.319 ;
     RECT  93.456 198.283 95.13 198.355 ;
     RECT  96.372 198.319 96.57 198.355 ;
     RECT  2.34 198.121 2.697 198.391 ;
     RECT  90 198.121 92.322 198.391 ;
     RECT  93.456 198.355 95.202 198.391 ;
     RECT  95.976 198.355 97.038 198.391 ;
     RECT  90 198.391 95.202 198.517 ;
     RECT  95.976 198.391 97.506 198.517 ;
     RECT  307.764 198.277 324.522 198.517 ;
     RECT  140.544 198.391 140.562 198.545 ;
     RECT  307.656 198.517 324.522 198.589 ;
     RECT  307.656 198.589 325.242 198.653 ;
     RECT  2.34 198.391 3.33 198.661 ;
     RECT  105.015 2.413 105.297 198.751 ;
     RECT  121.215 196.637 121.497 198.751 ;
     RECT  0.108 198.619 0.126 198.763 ;
     RECT  13.215 196.637 13.497 198.763 ;
     RECT  24.015 196.637 24.297 198.763 ;
     RECT  34.815 196.637 35.097 198.763 ;
     RECT  45.615 196.637 45.897 198.763 ;
     RECT  56.415 196.637 56.697 198.763 ;
     RECT  67.215 196.637 67.497 198.763 ;
     RECT  78.015 196.637 78.297 198.763 ;
     RECT  88.815 196.637 89.097 198.763 ;
     RECT  99.615 196.637 99.897 198.763 ;
     RECT  205.668 198.625 205.686 198.779 ;
     RECT  121.104 198.751 121.497 198.797 ;
     RECT  140.652 198.661 140.67 198.797 ;
     RECT  205.56 198.787 205.578 198.845 ;
     RECT  108.792 198.661 108.81 198.859 ;
     RECT  110.415 196.637 110.697 198.859 ;
     RECT  0.108 198.763 0.342 198.895 ;
     RECT  88.704 198.763 89.097 198.895 ;
     RECT  89.892 198.517 97.506 198.895 ;
     RECT  108.288 198.859 109.458 198.895 ;
     RECT  110.415 198.859 110.97 198.895 ;
     RECT  106.596 198.763 106.614 198.907 ;
     RECT  88.704 198.895 97.506 198.923 ;
     RECT  101.448 198.085 101.466 198.931 ;
     RECT  104.904 198.751 105.297 198.931 ;
     RECT  106.596 198.907 107.082 198.931 ;
     RECT  324.288 198.653 325.242 198.931 ;
     RECT  2.34 198.661 3.618 198.955 ;
     RECT  108.288 198.895 111.654 199.021 ;
     RECT  115.815 2.413 116.097 199.021 ;
     RECT  307.656 198.653 323.514 199.048 ;
     RECT  124.74 198.661 124.758 199.049 ;
     RECT  307.512 199.048 323.514 199.049 ;
     RECT  108.288 199.021 111.69 199.051 ;
     RECT  99.504 198.763 99.897 199.057 ;
     RECT  108.072 199.051 111.69 199.057 ;
     RECT  0.108 198.895 0.558 199.085 ;
     RECT  307.512 199.049 314.55 199.085 ;
     RECT  307.62 199.085 314.55 199.091 ;
     RECT  104.904 198.931 107.082 199.093 ;
     RECT  107.892 199.057 111.69 199.093 ;
     RECT  115.704 199.021 116.097 199.093 ;
     RECT  202.215 172.205 202.497 199.093 ;
     RECT  99.252 199.057 99.897 199.129 ;
     RECT  100.908 198.931 101.466 199.129 ;
     RECT  2.304 198.955 3.618 199.165 ;
     RECT  104.904 199.093 111.69 199.165 ;
     RECT  115.632 199.093 116.097 199.165 ;
     RECT  86.724 199.147 86.742 199.195 ;
     RECT  104.904 199.165 111.87 199.201 ;
     RECT  126.615 196.655 126.897 199.201 ;
     RECT  131.508 198.269 132.297 199.201 ;
     RECT  324.288 198.931 325.638 199.201 ;
     RECT  13.104 198.763 13.497 199.229 ;
     RECT  23.904 198.763 24.297 199.229 ;
     RECT  34.704 198.763 35.097 199.229 ;
     RECT  45.504 198.763 45.897 199.229 ;
     RECT  56.304 198.763 56.697 199.229 ;
     RECT  67.104 198.763 67.497 199.229 ;
     RECT  77.904 198.763 78.297 199.229 ;
     RECT  104.904 199.201 111.906 199.291 ;
     RECT  121.215 198.797 121.497 199.291 ;
     RECT  2.304 199.165 3.69 199.319 ;
     RECT  202.215 199.093 203.202 199.319 ;
     RECT  103.968 199.201 103.986 199.327 ;
     RECT  86.724 199.195 86.814 199.339 ;
     RECT  131.184 199.201 132.297 199.387 ;
     RECT  86.652 199.339 86.814 199.399 ;
     RECT  114.588 199.093 114.606 199.399 ;
     RECT  115.56 199.165 116.097 199.399 ;
     RECT  202.215 199.319 203.094 199.399 ;
     RECT  125.208 199.363 125.226 199.429 ;
     RECT  126.036 199.201 126.897 199.429 ;
     RECT  88.704 198.923 97.29 199.435 ;
     RECT  114.588 199.399 116.097 199.435 ;
     RECT  0.108 199.085 0.342 199.463 ;
     RECT  131.04 199.387 132.297 199.463 ;
     RECT  0.144 199.463 0.342 199.469 ;
     RECT  86.652 199.399 87.354 199.469 ;
     RECT  131.4 199.463 132.297 199.471 ;
     RECT  133.02 199.201 133.038 199.471 ;
     RECT  315.396 199.049 323.514 199.471 ;
     RECT  324.288 199.201 325.89 199.471 ;
     RECT  131.4 199.471 133.038 199.483 ;
     RECT  104.904 199.291 111.942 199.499 ;
     RECT  201.78 199.399 203.094 199.499 ;
     RECT  86.652 199.469 87.282 199.517 ;
     RECT  98.028 199.471 98.046 199.561 ;
     RECT  118.044 199.201 118.062 199.561 ;
     RECT  167.76 189.965 167.778 199.561 ;
     RECT  83.415 2.413 83.697 199.579 ;
     RECT  114.3 199.435 116.097 199.579 ;
     RECT  128.844 199.561 129.33 199.579 ;
     RECT  167.76 199.561 167.886 199.579 ;
     RECT  131.4 199.483 133.398 199.589 ;
     RECT  315.396 199.471 325.89 199.589 ;
     RECT  99.252 199.129 101.466 199.597 ;
     RECT  114.12 199.579 116.097 199.597 ;
     RECT  123.228 199.579 123.246 199.597 ;
     RECT  124.128 199.579 124.146 199.597 ;
     RECT  167.76 199.579 167.922 199.625 ;
     RECT  210.564 199.435 210.582 199.625 ;
     RECT  315.396 199.589 321.297 199.625 ;
     RECT  103.86 199.327 103.986 199.633 ;
     RECT  104.904 199.499 111.87 199.633 ;
     RECT  128.844 199.579 129.618 199.633 ;
     RECT  133.38 199.589 133.398 199.633 ;
     RECT  169.815 175.559 170.097 199.633 ;
     RECT  209.664 199.597 209.682 199.633 ;
     RECT  99.18 199.597 101.466 199.669 ;
     RECT  102.348 199.597 102.366 199.669 ;
     RECT  120.06 199.597 120.078 199.669 ;
     RECT  121.215 199.291 121.986 199.669 ;
     RECT  122.868 199.597 124.146 199.669 ;
     RECT  167.868 199.625 167.922 199.669 ;
     RECT  167.868 199.669 168.462 199.697 ;
     RECT  99.18 199.669 102.366 199.705 ;
     RECT  103.86 199.633 111.87 199.705 ;
     RECT  238.176 198.895 238.194 199.705 ;
     RECT  2.304 199.319 3.654 199.723 ;
     RECT  98.028 199.561 98.406 199.741 ;
     RECT  99.18 199.705 111.87 199.741 ;
     RECT  114.12 199.597 116.154 199.741 ;
     RECT  118.044 199.561 118.602 199.741 ;
     RECT  0.18 199.469 0.342 199.831 ;
     RECT  83.232 199.579 83.697 199.831 ;
     RECT  206.388 199.705 206.406 199.831 ;
     RECT  242.28 198.661 242.298 199.831 ;
     RECT  117.036 199.633 117.054 199.858 ;
     RECT  86.724 199.517 87.282 199.859 ;
     RECT  133.38 199.633 133.758 199.859 ;
     RECT  160.74 199.741 160.758 199.859 ;
     RECT  168.444 199.697 168.462 199.859 ;
     RECT  198.432 199.669 198.45 199.859 ;
     RECT  201.78 199.499 202.914 199.859 ;
     RECT  205.056 199.669 205.074 199.859 ;
     RECT  238.176 199.705 238.482 199.859 ;
     RECT  242.28 199.831 242.586 199.859 ;
     RECT  210.924 199.705 211.014 199.867 ;
     RECT  209.664 199.633 210.114 199.901 ;
     RECT  201.78 199.859 202.59 199.903 ;
     RECT  210.924 199.867 211.23 199.904 ;
     RECT  113.796 199.741 116.154 199.915 ;
     RECT  206.352 199.831 206.406 199.931 ;
     RECT  210.924 199.904 211.014 199.931 ;
     RECT  117 199.858 117.054 199.939 ;
     RECT  118.044 199.741 118.674 199.939 ;
     RECT  121.215 199.669 124.146 199.939 ;
     RECT  87.048 199.859 87.282 199.949 ;
     RECT  201.6 199.903 202.59 199.949 ;
     RECT  209.664 199.901 209.826 199.949 ;
     RECT  117 199.939 118.674 199.963 ;
     RECT  131.4 199.589 132.354 199.967 ;
     RECT  202.215 199.949 202.59 199.967 ;
     RECT  206.388 199.931 206.406 199.967 ;
     RECT  210.996 199.931 211.014 199.967 ;
     RECT  120.06 199.669 120.366 199.975 ;
     RECT  121.14 199.939 124.146 199.975 ;
     RECT  125.208 199.429 126.897 199.975 ;
     RECT  133.74 199.859 133.758 199.975 ;
     RECT  307.62 199.091 314.154 199.975 ;
     RECT  88.344 199.435 97.29 200.039 ;
     RECT  98.028 199.741 111.87 200.039 ;
     RECT  204.984 199.963 205.002 200.039 ;
     RECT  209.808 199.949 209.826 200.039 ;
     RECT  0.18 199.831 0.558 200.045 ;
     RECT  82.764 199.831 83.697 200.045 ;
     RECT  307.62 199.975 314.658 200.045 ;
     RECT  87.048 199.949 87.174 200.129 ;
     RECT  113.76 199.915 116.154 200.129 ;
     RECT  133.74 199.975 134.37 200.129 ;
     RECT  88.344 200.039 97.146 200.141 ;
     RECT  87.048 200.129 87.066 200.201 ;
     RECT  88.488 200.141 97.146 200.201 ;
     RECT  135.396 199.831 135.414 200.201 ;
     RECT  307.62 200.045 313.974 200.201 ;
     RECT  134.352 200.129 134.37 200.209 ;
     RECT  137.415 196.925 137.697 200.209 ;
     RECT  242.568 199.859 242.586 200.237 ;
     RECT  113.868 200.129 116.154 200.245 ;
     RECT  116.892 199.963 118.674 200.245 ;
     RECT  88.704 200.201 97.146 200.273 ;
     RECT  113.868 200.245 118.674 200.273 ;
     RECT  132.015 199.967 132.354 200.273 ;
     RECT  134.352 200.209 134.55 200.273 ;
     RECT  307.62 200.201 312.606 200.273 ;
     RECT  120.06 199.975 126.897 200.281 ;
     RECT  136.404 197.609 136.422 200.281 ;
     RECT  137.376 200.209 137.697 200.281 ;
     RECT  2.268 199.723 3.654 200.333 ;
     RECT  314.712 200.209 314.874 200.347 ;
     RECT  315.612 199.625 321.297 200.347 ;
     RECT  128.844 199.633 129.69 200.371 ;
     RECT  85.464 199.963 85.482 200.399 ;
     RECT  88.704 200.273 97.038 200.399 ;
     RECT  113.94 200.273 118.674 200.399 ;
     RECT  308.196 200.273 312.606 200.399 ;
     RECT  314.712 200.347 321.297 200.399 ;
     RECT  136.152 200.281 137.697 200.435 ;
     RECT  314.856 200.399 321.297 200.479 ;
     RECT  322.02 199.589 325.89 200.479 ;
     RECT  134.532 200.273 134.55 200.507 ;
     RECT  137.376 200.435 137.697 200.507 ;
     RECT  2.304 200.333 3.654 200.543 ;
     RECT  114.192 200.399 118.674 200.551 ;
     RECT  136.152 200.435 136.17 200.579 ;
     RECT  120.06 200.281 127.386 200.635 ;
     RECT  120.024 200.635 127.386 200.641 ;
     RECT  128.844 200.371 130.05 200.641 ;
     RECT  169.776 199.633 170.097 200.641 ;
     RECT  245.415 171.311 245.697 200.641 ;
     RECT  250.815 194.189 251.097 200.641 ;
     RECT  88.704 200.399 96.966 200.669 ;
     RECT  138.492 200.101 138.51 200.669 ;
     RECT  169.308 200.641 170.097 200.677 ;
     RECT  182.304 200.641 182.322 200.677 ;
     RECT  120.024 200.641 127.494 200.683 ;
     RECT  128.844 200.641 130.194 200.683 ;
     RECT  182.304 200.677 182.862 200.683 ;
     RECT  180.615 176.237 180.897 200.713 ;
     RECT  181.98 200.683 182.862 200.713 ;
     RECT  169.308 200.677 170.73 200.717 ;
     RECT  156.24 200.731 156.258 200.749 ;
     RECT  128.304 200.683 130.194 200.776 ;
     RECT  250.308 200.641 251.097 200.785 ;
     RECT  0.468 200.045 0.558 200.813 ;
     RECT  3.636 200.543 3.654 200.813 ;
     RECT  119.952 200.683 127.494 200.821 ;
     RECT  178.416 200.677 178.434 200.821 ;
     RECT  300.6 200.713 300.618 200.821 ;
     RECT  313.416 200.201 313.974 200.821 ;
     RECT  180.615 200.713 182.862 200.849 ;
     RECT  245.415 200.641 246.33 200.849 ;
     RECT  13.215 199.229 13.497 200.911 ;
     RECT  24.015 199.229 24.297 200.911 ;
     RECT  34.815 199.229 35.097 200.911 ;
     RECT  45.615 199.229 45.897 200.911 ;
     RECT  56.415 199.229 56.697 200.911 ;
     RECT  67.215 199.229 67.497 200.911 ;
     RECT  78.015 199.229 78.297 200.911 ;
     RECT  114.192 200.551 118.854 200.911 ;
     RECT  156.132 200.749 156.258 200.939 ;
     RECT  300.492 200.821 300.618 200.939 ;
     RECT  119.952 200.821 127.53 200.947 ;
     RECT  128.304 200.776 130.23 200.947 ;
     RECT  153.615 197.165 153.897 200.947 ;
     RECT  308.448 200.399 312.606 200.947 ;
     RECT  313.416 200.821 314.082 200.947 ;
     RECT  34.632 200.911 35.097 200.957 ;
     RECT  178.416 200.821 178.506 200.975 ;
     RECT  180.615 200.849 182.79 200.975 ;
     RECT  300.492 200.939 300.51 200.975 ;
     RECT  114.192 200.911 119.106 200.983 ;
     RECT  119.952 200.947 127.566 200.983 ;
     RECT  153.615 200.947 154.494 201.047 ;
     RECT  156.312 200.947 156.33 201.047 ;
     RECT  180.615 200.975 182.61 201.047 ;
     RECT  180.615 201.047 181.422 201.056 ;
     RECT  98.064 200.039 111.726 201.067 ;
     RECT  139.896 200.713 139.914 201.067 ;
     RECT  182.304 201.047 182.61 201.083 ;
     RECT  308.448 200.947 314.082 201.083 ;
     RECT  98.064 201.067 111.762 201.091 ;
     RECT  304.815 191.129 305.097 201.091 ;
     RECT  314.856 200.479 325.89 201.091 ;
     RECT  114.192 200.983 127.566 201.119 ;
     RECT  97.92 201.091 111.762 201.181 ;
     RECT  112.716 200.245 112.734 201.181 ;
     RECT  139.896 201.067 140.202 201.181 ;
     RECT  218.415 175.469 218.697 201.181 ;
     RECT  0.144 200.875 0.342 201.197 ;
     RECT  125.568 201.119 127.566 201.209 ;
     RECT  139.896 201.181 140.67 201.209 ;
     RECT  178.416 200.975 178.434 201.209 ;
     RECT  182.592 201.083 182.61 201.209 ;
     RECT  309.204 201.083 314.082 201.209 ;
     RECT  309.24 201.209 314.082 201.217 ;
     RECT  314.856 201.091 325.998 201.217 ;
     RECT  304.488 201.091 305.097 201.245 ;
     RECT  97.92 201.181 112.842 201.253 ;
     RECT  327.744 199.669 327.762 201.253 ;
     RECT  218.415 201.181 218.862 201.281 ;
     RECT  97.92 201.253 113.022 201.289 ;
     RECT  140.184 201.209 140.67 201.317 ;
     RECT  132.015 200.273 132.297 201.352 ;
     RECT  142.815 196.655 143.097 201.352 ;
     RECT  153.615 201.047 153.897 201.352 ;
     RECT  164.415 182.579 164.697 201.352 ;
     RECT  175.215 179.357 175.497 201.352 ;
     RECT  186.015 175.469 186.297 201.352 ;
     RECT  196.815 175.469 197.097 201.352 ;
     RECT  2.304 200.543 2.898 201.353 ;
     RECT  140.256 201.317 140.67 201.353 ;
     RECT  131.904 201.352 132.297 201.389 ;
     RECT  142.704 201.352 143.097 201.389 ;
     RECT  153.504 201.352 153.897 201.389 ;
     RECT  164.304 201.352 164.697 201.389 ;
     RECT  175.104 201.352 175.497 201.389 ;
     RECT  185.904 201.352 186.297 201.389 ;
     RECT  196.704 201.352 197.097 201.389 ;
     RECT  140.256 201.353 140.598 201.479 ;
     RECT  204.624 201.355 204.642 201.479 ;
     RECT  34.704 200.957 35.097 201.485 ;
     RECT  2.304 201.353 2.697 201.488 ;
     RECT  13.104 200.911 13.497 201.488 ;
     RECT  23.904 200.911 24.297 201.488 ;
     RECT  45.504 200.911 45.897 201.488 ;
     RECT  56.304 200.911 56.697 201.488 ;
     RECT  67.104 200.911 67.497 201.488 ;
     RECT  77.904 200.911 78.297 201.488 ;
     RECT  88.704 200.669 96.894 201.488 ;
     RECT  86.796 201.355 86.814 201.499 ;
     RECT  223.815 2.413 224.097 201.523 ;
     RECT  86.688 201.499 86.814 201.533 ;
     RECT  97.92 201.289 113.31 201.533 ;
     RECT  86.688 201.533 86.706 201.559 ;
     RECT  88.815 201.488 96.894 201.595 ;
     RECT  128.304 200.947 130.302 201.595 ;
     RECT  216.972 201.091 216.99 201.595 ;
     RECT  229.215 183.725 229.497 201.595 ;
     RECT  309.24 201.217 325.998 201.595 ;
     RECT  86.652 201.559 86.706 201.629 ;
     RECT  88.815 201.595 97.11 201.631 ;
     RECT  204.372 201.487 204.39 201.659 ;
     RECT  309.24 201.595 326.034 201.659 ;
     RECT  0.144 201.197 0.234 201.677 ;
     RECT  311.76 201.659 326.034 201.721 ;
     RECT  327.24 201.253 327.762 201.721 ;
     RECT  128.304 201.595 130.878 201.739 ;
     RECT  141.66 201.361 141.678 201.749 ;
     RECT  216.828 201.595 216.99 201.749 ;
     RECT  0.18 201.677 0.234 201.773 ;
     RECT  0.216 201.773 0.234 201.785 ;
     RECT  86.652 201.629 86.67 201.785 ;
     RECT  88.815 201.631 97.506 201.785 ;
     RECT  125.568 201.209 127.422 201.785 ;
     RECT  216.828 201.749 216.846 201.785 ;
     RECT  89.928 201.785 97.506 201.821 ;
     RECT  311.76 201.721 326.07 201.821 ;
     RECT  211.5 201.361 211.518 201.829 ;
     RECT  306.18 201.793 306.198 201.829 ;
     RECT  98.244 201.533 113.31 201.865 ;
     RECT  114.192 201.119 124.758 201.865 ;
     RECT  327.204 201.721 327.762 201.865 ;
     RECT  125.604 201.785 127.098 201.893 ;
     RECT  225.864 201.865 225.882 201.901 ;
     RECT  128.268 201.739 130.878 201.929 ;
     RECT  308.448 201.083 308.466 201.991 ;
     RECT  309.24 201.659 310.986 201.991 ;
     RECT  211.5 201.829 211.806 202.019 ;
     RECT  225.864 201.901 226.062 202.019 ;
     RECT  213.015 2.413 213.297 202.027 ;
     RECT  306.144 201.829 306.198 202.027 ;
     RECT  327.204 201.865 327.834 202.027 ;
     RECT  311.76 201.821 326.034 202.055 ;
     RECT  223.815 201.523 224.154 202.063 ;
     RECT  98.244 201.865 124.758 202.127 ;
     RECT  210.348 202.027 210.366 202.127 ;
     RECT  212.688 202.027 213.297 202.127 ;
     RECT  222.3 202.027 222.318 202.127 ;
     RECT  113.112 202.127 124.758 202.171 ;
     RECT  130.428 201.929 130.878 202.171 ;
     RECT  226.836 202.099 226.854 202.171 ;
     RECT  327.168 202.027 327.834 202.171 ;
     RECT  306.144 202.027 306.234 202.199 ;
     RECT  308.448 201.991 310.986 202.199 ;
     RECT  311.832 202.055 326.034 202.199 ;
     RECT  140.58 201.479 140.598 202.253 ;
     RECT  142.815 201.389 143.097 202.261 ;
     RECT  113.112 202.171 124.83 202.289 ;
     RECT  130.428 202.171 131.238 202.289 ;
     RECT  141.552 201.757 141.606 202.289 ;
     RECT  223.272 202.063 224.154 202.289 ;
     RECT  226.656 202.171 226.854 202.289 ;
     RECT  249.408 201.901 249.426 202.289 ;
     RECT  250.236 200.785 251.097 202.289 ;
     RECT  128.268 201.929 129.618 202.297 ;
     RECT  89.928 201.821 97.182 202.325 ;
     RECT  98.244 202.127 112.266 202.325 ;
     RECT  131.22 202.289 131.238 202.325 ;
     RECT  111.78 202.325 112.266 202.349 ;
     RECT  97.164 202.325 97.182 202.361 ;
     RECT  98.244 202.325 110.826 202.361 ;
     RECT  2.415 201.488 2.697 202.369 ;
     RECT  98.244 202.361 110.697 202.441 ;
     RECT  98.208 202.441 110.697 202.469 ;
     RECT  141.552 202.289 141.57 202.559 ;
     RECT  212.76 202.127 213.297 202.559 ;
     RECT  230.256 202.441 230.274 202.559 ;
     RECT  113.4 202.289 124.83 202.589 ;
     RECT  98.208 202.469 109.062 202.631 ;
     RECT  327.168 202.171 328.158 202.631 ;
     RECT  109.98 202.469 110.697 202.667 ;
     RECT  214.344 202.369 214.362 202.667 ;
     RECT  125.604 201.893 127.026 202.675 ;
     RECT  127.908 202.297 129.618 202.675 ;
     RECT  88.815 201.785 89.097 202.699 ;
     RECT  89.928 202.325 96.318 202.699 ;
     RECT  111.816 202.349 112.266 202.703 ;
     RECT  142.524 202.261 143.097 202.703 ;
     RECT  0.54 202.441 0.558 202.711 ;
     RECT  113.58 202.589 124.83 202.711 ;
     RECT  125.604 202.675 130.158 202.711 ;
     RECT  88.815 202.699 96.318 202.829 ;
     RECT  98.208 202.631 108.918 202.829 ;
     RECT  90.18 202.829 96.318 202.835 ;
     RECT  113.58 202.711 130.158 202.835 ;
     RECT  304.815 201.245 305.097 202.837 ;
     RECT  98.208 202.829 107.55 202.865 ;
     RECT  108.396 202.829 108.918 202.865 ;
     RECT  111.888 202.703 112.266 202.865 ;
     RECT  110.196 202.667 110.697 202.901 ;
     RECT  90.648 202.835 96.318 202.925 ;
     RECT  98.208 202.865 107.478 202.925 ;
     RECT  234.615 191.939 234.897 202.945 ;
     RECT  309.024 202.199 310.986 202.945 ;
     RECT  311.976 202.199 326.034 202.945 ;
     RECT  125.604 202.835 130.158 202.973 ;
     RECT  97.452 202.909 97.47 202.981 ;
     RECT  98.208 202.925 106.902 202.981 ;
     RECT  230.292 202.909 230.598 202.981 ;
     RECT  232.884 202.603 232.902 202.981 ;
     RECT  308.952 202.945 326.034 203.021 ;
     RECT  2.415 202.369 2.754 203.071 ;
     RECT  13.215 201.488 13.497 203.071 ;
     RECT  24.015 201.488 24.297 203.071 ;
     RECT  34.815 201.485 35.097 203.071 ;
     RECT  45.615 201.488 45.897 203.071 ;
     RECT  56.415 201.488 56.697 203.071 ;
     RECT  67.215 201.488 67.497 203.071 ;
     RECT  78.015 201.488 78.297 203.071 ;
     RECT  88.815 202.829 89.097 203.071 ;
     RECT  327.204 202.631 328.158 203.083 ;
     RECT  228.708 201.595 229.497 203.099 ;
     RECT  230.292 202.981 230.634 203.099 ;
     RECT  232.704 202.981 232.902 203.099 ;
     RECT  304.632 202.837 305.097 203.099 ;
     RECT  277.815 2.413 278.097 203.107 ;
     RECT  2.304 203.071 2.754 203.117 ;
     RECT  13.104 203.071 13.497 203.117 ;
     RECT  23.904 203.071 24.297 203.117 ;
     RECT  34.704 203.071 35.097 203.117 ;
     RECT  45.504 203.071 45.897 203.117 ;
     RECT  56.304 203.071 56.697 203.117 ;
     RECT  67.104 203.071 67.497 203.117 ;
     RECT  77.904 203.071 78.297 203.117 ;
     RECT  88.704 203.071 89.097 203.117 ;
     RECT  303.084 202.801 303.102 203.117 ;
     RECT  93.456 202.925 96.318 203.143 ;
     RECT  97.452 202.981 106.902 203.143 ;
     RECT  128.376 202.973 130.158 203.143 ;
     RECT  93.456 203.143 106.902 203.171 ;
     RECT  234.18 202.945 234.897 203.171 ;
     RECT  270.18 203.071 270.198 203.171 ;
     RECT  277.815 203.107 278.154 203.207 ;
     RECT  302.112 203.107 302.13 203.207 ;
     RECT  304.704 203.099 305.097 203.207 ;
     RECT  108.396 202.865 108.846 203.243 ;
     RECT  113.58 202.835 124.686 203.243 ;
     RECT  234.252 203.171 234.897 203.243 ;
     RECT  93.492 203.171 106.902 203.369 ;
     RECT  108.396 203.243 108.414 203.369 ;
     RECT  113.58 203.243 114.57 203.369 ;
     RECT  115.668 203.243 124.686 203.369 ;
     RECT  128.376 203.143 130.302 203.369 ;
     RECT  230.292 203.099 230.598 203.369 ;
     RECT  90.648 202.925 92.538 203.405 ;
     RECT  93.492 203.369 94.878 203.405 ;
     RECT  95.616 203.369 106.902 203.405 ;
     RECT  112.248 202.865 112.266 203.405 ;
     RECT  115.74 203.369 124.686 203.405 ;
     RECT  128.376 203.369 130.194 203.405 ;
     RECT  93.996 203.405 94.497 203.441 ;
     RECT  95.616 203.405 95.634 203.441 ;
     RECT  114.552 203.369 114.57 203.441 ;
     RECT  115.74 203.405 116.802 203.441 ;
     RECT  117.972 203.405 124.686 203.441 ;
     RECT  96.372 203.405 106.902 203.501 ;
     RECT  113.58 203.369 113.598 203.501 ;
     RECT  306.108 202.441 306.126 203.521 ;
     RECT  0.468 202.711 0.558 203.611 ;
     RECT  90.648 203.405 92.466 203.639 ;
     RECT  228.78 203.099 229.497 203.639 ;
     RECT  230.256 203.521 230.274 203.647 ;
     RECT  222.12 202.891 222.138 203.683 ;
     RECT  97.092 203.501 106.902 203.693 ;
     RECT  97.308 203.693 106.902 203.711 ;
     RECT  226.296 203.107 226.314 203.719 ;
     RECT  90.648 203.639 92.034 203.747 ;
     RECT  230.22 203.647 230.274 203.747 ;
     RECT  306.108 203.521 306.198 203.747 ;
     RECT  90.648 203.747 91.206 203.783 ;
     RECT  92.016 203.747 92.034 203.783 ;
     RECT  2.415 203.117 2.754 203.791 ;
     RECT  98.208 203.711 106.902 203.791 ;
     RECT  118.872 203.441 124.686 203.791 ;
     RECT  125.604 202.973 127.566 203.791 ;
     RECT  128.376 203.405 130.086 203.791 ;
     RECT  226.296 203.719 226.962 203.791 ;
     RECT  309.204 203.021 326.034 203.791 ;
     RECT  94.068 203.441 94.497 203.819 ;
     RECT  306.18 203.747 306.198 203.819 ;
     RECT  118.872 203.791 124.758 203.851 ;
     RECT  125.532 203.791 130.086 203.851 ;
     RECT  327.204 203.083 328.23 203.851 ;
     RECT  2.415 203.791 2.862 203.909 ;
     RECT  86.652 203.791 86.67 203.909 ;
     RECT  98.208 203.791 107.334 203.909 ;
     RECT  222.12 203.683 222.318 203.909 ;
     RECT  226.296 203.791 227.142 203.909 ;
     RECT  228.888 203.639 229.497 203.909 ;
     RECT  104.544 203.909 106.506 203.945 ;
     RECT  308.916 203.791 326.034 203.947 ;
     RECT  97.308 203.711 97.398 203.981 ;
     RECT  98.208 203.909 103.77 203.981 ;
     RECT  107.316 203.909 107.334 203.981 ;
     RECT  226.296 203.909 226.314 203.981 ;
     RECT  230.256 203.747 230.274 203.981 ;
     RECT  98.496 203.981 103.77 204.029 ;
     RECT  2.415 203.909 2.754 204.043 ;
     RECT  13.215 203.117 13.497 204.043 ;
     RECT  24.015 203.117 24.297 204.043 ;
     RECT  34.815 203.117 35.097 204.043 ;
     RECT  45.615 203.117 45.897 204.043 ;
     RECT  56.415 203.117 56.697 204.043 ;
     RECT  67.215 203.117 67.497 204.043 ;
     RECT  78.015 203.117 78.297 204.043 ;
     RECT  88.815 203.117 89.097 204.043 ;
     RECT  104.544 203.945 105.822 204.053 ;
     RECT  308.88 203.947 326.034 204.053 ;
     RECT  13.104 204.043 13.497 204.089 ;
     RECT  23.904 204.043 24.297 204.089 ;
     RECT  34.704 204.043 35.097 204.089 ;
     RECT  45.504 204.043 45.897 204.089 ;
     RECT  56.304 204.043 56.697 204.089 ;
     RECT  67.104 204.043 67.497 204.089 ;
     RECT  77.904 204.043 78.297 204.089 ;
     RECT  88.704 204.043 89.097 204.089 ;
     RECT  100.62 204.029 103.77 204.089 ;
     RECT  308.952 204.053 325.962 204.089 ;
     RECT  0.108 203.611 0.558 204.173 ;
     RECT  100.62 204.089 103.734 204.179 ;
     RECT  118.872 203.851 130.086 204.179 ;
     RECT  2.304 204.043 2.754 204.215 ;
     RECT  98.604 204.029 99.897 204.215 ;
     RECT  308.952 204.089 325.818 204.215 ;
     RECT  98.604 204.215 98.622 204.221 ;
     RECT  100.62 204.179 101.538 204.251 ;
     RECT  123.444 204.179 130.086 204.259 ;
     RECT  102.276 204.179 103.59 204.269 ;
     RECT  100.8 204.251 101.538 204.323 ;
     RECT  123.444 204.259 130.194 204.359 ;
     RECT  311.796 204.215 325.818 204.359 ;
     RECT  102.312 204.269 103.59 204.449 ;
     RECT  123.444 204.359 129.942 204.449 ;
     RECT  2.304 204.215 2.697 204.461 ;
     RECT  102.312 204.449 103.05 204.485 ;
     RECT  102.672 204.485 102.726 204.521 ;
     RECT  102.672 204.521 102.69 204.557 ;
     RECT  118.872 204.179 122.67 204.557 ;
     RECT  123.66 204.449 129.942 204.593 ;
     RECT  118.872 204.557 119.934 204.619 ;
     RECT  308.952 204.215 310.806 204.629 ;
     RECT  311.796 204.359 321.678 204.629 ;
     RECT  0.108 204.173 0.486 204.653 ;
     RECT  118.584 204.619 119.934 204.719 ;
     RECT  120.744 204.557 122.67 204.719 ;
     RECT  123.66 204.593 128.862 204.719 ;
     RECT  309.888 204.629 310.806 204.719 ;
     RECT  119.268 204.719 119.826 204.755 ;
     RECT  120.852 204.719 122.67 204.755 ;
     RECT  311.796 204.629 312.354 204.755 ;
     RECT  309.888 204.719 310.497 204.791 ;
     RECT  120.852 204.755 121.986 204.827 ;
     RECT  129.924 204.593 129.942 204.863 ;
     RECT  322.524 204.359 325.818 204.871 ;
     RECT  124.02 204.719 127.17 204.899 ;
     RECT  327.168 203.851 328.23 204.907 ;
     RECT  267.015 2.413 267.297 204.961 ;
     RECT  119.268 204.755 119.394 204.989 ;
     RECT  120.852 204.827 121.698 204.989 ;
     RECT  124.02 204.899 126.897 204.989 ;
     RECT  128.268 204.719 128.826 204.989 ;
     RECT  119.268 204.989 119.286 205.025 ;
     RECT  124.02 204.989 124.038 205.025 ;
     RECT  124.776 204.989 125.262 205.025 ;
     RECT  313.092 204.629 321.678 205.025 ;
     RECT  266.328 204.961 267.297 205.037 ;
     RECT  313.344 205.025 321.678 205.037 ;
     RECT  322.524 204.871 325.962 205.099 ;
     RECT  126.144 204.989 126.897 205.133 ;
     RECT  313.416 205.037 321.678 205.141 ;
     RECT  322.524 205.099 326.07 205.141 ;
     RECT  0.108 204.653 0.126 205.147 ;
     RECT  0.036 205.147 0.126 205.181 ;
     RECT  264.78 205.105 264.798 205.195 ;
     RECT  264.78 205.195 265.122 205.259 ;
     RECT  124.776 205.025 124.902 205.295 ;
     RECT  128.484 204.989 128.538 205.295 ;
     RECT  312.336 204.755 312.354 205.295 ;
     RECT  264.78 205.259 265.086 205.331 ;
     RECT  151.92 205.231 151.938 205.375 ;
     RECT  124.776 205.295 124.794 205.439 ;
     RECT  128.52 205.295 128.538 205.439 ;
     RECT  327.132 204.907 328.23 205.483 ;
     RECT  313.416 205.141 326.07 205.573 ;
     RECT  326.988 205.483 328.23 205.573 ;
     RECT  151.596 205.375 151.938 205.808 ;
     RECT  151.596 205.808 151.614 205.949 ;
     RECT  313.416 205.573 328.23 205.951 ;
     RECT  312.984 205.951 328.23 205.979 ;
     RECT  310.215 204.791 310.497 206.149 ;
     RECT  314.064 205.979 328.23 206.189 ;
     RECT  310.104 206.149 310.497 206.249 ;
     RECT  312.984 205.979 313.146 206.339 ;
     RECT  314.064 206.189 314.118 206.339 ;
     RECT  314.964 206.189 328.23 206.339 ;
     RECT  257.544 206.221 257.562 206.375 ;
     RECT  315.036 206.339 328.23 206.411 ;
     RECT  315.036 206.411 327.15 206.753 ;
     RECT  315.036 206.753 326.07 206.789 ;
     RECT  328.212 206.411 328.23 206.789 ;
     RECT  315.036 206.789 322.326 206.879 ;
     RECT  323.172 206.789 326.07 206.879 ;
     RECT  314.064 206.339 314.082 206.887 ;
     RECT  323.748 206.879 326.07 206.909 ;
     RECT  313.956 206.887 314.082 206.915 ;
     RECT  324.036 206.909 326.07 206.951 ;
     RECT  315.036 206.879 322.29 207.059 ;
     RECT  315.036 207.059 321.462 207.121 ;
     RECT  313.956 206.915 313.974 207.149 ;
     RECT  314.964 207.121 321.462 207.149 ;
     RECT  322.272 207.059 322.29 207.149 ;
     RECT  314.964 207.149 321.354 207.185 ;
     RECT  324.036 206.951 325.926 207.185 ;
     RECT  327.096 206.753 327.15 207.221 ;
     RECT  314.964 207.185 321.297 207.265 ;
     RECT  314.892 207.265 321.297 207.293 ;
     RECT  324.576 207.185 325.926 207.329 ;
     RECT  314.892 207.293 315.918 207.419 ;
     RECT  316.836 207.293 321.297 207.419 ;
     RECT  325.152 207.329 325.926 207.419 ;
     RECT  314.892 207.419 315.897 207.455 ;
     RECT  316.836 207.419 319.554 207.455 ;
     RECT  318.384 207.455 319.554 207.491 ;
     RECT  327.132 207.221 327.15 207.491 ;
     RECT  315.216 207.455 315.897 207.689 ;
     RECT  318.384 207.491 319.338 207.689 ;
     RECT  325.836 207.419 325.926 207.689 ;
     RECT  325.836 207.689 325.854 207.725 ;
     RECT  316.836 207.455 316.854 207.761 ;
     RECT  318.6 207.689 319.194 207.959 ;
     RECT  308.268 209.179 308.286 209.461 ;
     RECT  310.215 206.249 310.497 209.515 ;
     RECT  308.268 209.461 308.322 209.549 ;
     RECT  308.268 209.549 308.286 209.579 ;
     RECT  309.816 209.515 310.497 209.579 ;
     RECT  207.615 175.469 207.897 217.195 ;
     RECT  207.36 217.195 207.897 217.409 ;
     RECT  235.62 217.195 235.638 217.409 ;
     RECT  207.468 217.409 207.897 217.481 ;
     RECT  233.712 217.435 233.73 217.481 ;
     RECT  124.416 218.299 124.434 218.488 ;
     RECT  124.056 218.488 124.434 218.489 ;
     RECT  124.056 218.489 124.074 218.525 ;
     RECT  144.108 225.163 144.126 225.509 ;
     RECT  142.815 202.703 143.097 226.291 ;
     RECT  142.815 226.291 143.154 226.349 ;
     RECT  144.396 225.661 144.414 226.349 ;
     RECT  169.308 200.717 170.097 229.639 ;
     RECT  153.615 201.389 153.897 229.723 ;
     RECT  159.015 193.991 159.297 229.723 ;
     RECT  164.415 201.389 164.697 229.723 ;
     RECT  169.308 229.639 170.19 229.723 ;
     RECT  153.615 229.723 153.99 229.901 ;
     RECT  158.472 229.723 159.39 229.901 ;
     RECT  162.468 229.723 162.486 229.901 ;
     RECT  164.415 229.723 164.79 229.901 ;
     RECT  169.308 229.723 170.766 230.099 ;
     RECT  169.308 230.099 170.514 230.189 ;
     RECT  169.308 230.189 170.442 230.243 ;
     RECT  222.12 238.843 222.138 239.009 ;
     RECT  220.032 239.035 220.05 239.081 ;
     RECT  67.215 204.089 67.497 242.401 ;
     RECT  0.036 205.181 0.054 242.429 ;
     RECT  67.215 242.401 68.13 242.519 ;
     RECT  67.215 242.519 67.806 242.717 ;
     RECT  148.215 197.699 148.497 250.051 ;
     RECT  146.52 249.643 146.538 250.079 ;
     RECT  148.068 250.051 148.497 250.109 ;
     RECT  175.215 201.389 175.497 251.371 ;
     RECT  180.615 201.056 180.897 251.371 ;
     RECT  174.42 251.371 174.438 251.501 ;
     RECT  175.215 251.371 175.59 251.501 ;
     RECT  178.416 251.371 178.434 251.501 ;
     RECT  180.615 251.371 180.99 251.501 ;
     RECT  183.96 251.401 183.978 251.501 ;
     RECT  182.412 251.371 182.43 251.597 ;
     RECT  184.248 251.563 184.266 251.609 ;
     RECT  208.764 261.643 208.782 261.959 ;
     RECT  207.615 217.481 207.897 261.967 ;
     RECT  207.615 261.967 208.422 262.013 ;
     RECT  169.308 230.243 170.097 276.961 ;
     RECT  166.716 206.311 166.734 287.419 ;
     RECT  166.716 287.419 167.13 287.455 ;
     RECT  166.572 287.455 167.382 287.491 ;
     RECT  166.572 287.491 167.85 287.789 ;
     RECT  166.572 287.789 167.13 287.837 ;
     RECT  166.68 287.837 167.13 305.401 ;
     RECT  166.68 305.401 167.67 305.699 ;
     RECT  166.68 305.699 167.13 319.477 ;
     RECT  133.38 319.441 133.398 319.517 ;
     RECT  132.015 201.389 132.297 319.531 ;
     RECT  159.015 229.901 159.297 319.531 ;
     RECT  162.432 319.477 162.45 319.577 ;
     RECT  132.015 319.531 132.786 319.649 ;
     RECT  159.015 319.531 159.39 319.649 ;
     RECT  166.68 319.477 167.526 322.603 ;
     RECT  166.248 322.603 167.526 322.979 ;
     RECT  166.248 322.979 167.022 323.123 ;
     RECT  166.392 323.123 167.022 359.275 ;
     RECT  166.392 359.275 167.238 359.311 ;
     RECT  166.392 359.311 167.814 359.807 ;
     RECT  169.092 276.961 170.097 359.851 ;
     RECT  166.5 359.807 167.814 360.239 ;
     RECT  168.696 359.851 170.097 360.239 ;
     RECT  166.788 360.239 167.814 360.355 ;
     RECT  166.788 360.355 168.246 360.509 ;
     RECT  166.788 360.509 168.066 361.133 ;
     RECT  167.364 361.133 168.066 361.741 ;
     RECT  169.092 360.239 170.097 361.741 ;
     RECT  167.364 361.741 170.097 361.859 ;
     RECT  167.364 361.859 168.174 361.949 ;
     RECT  167.796 361.949 168.174 361.967 ;
     RECT  167.832 361.967 168.174 362.399 ;
     RECT  167.004 362.371 167.022 362.525 ;
     RECT  167.832 362.399 168.138 364.261 ;
     RECT  167.832 364.261 168.354 364.441 ;
     RECT  169.092 361.859 170.097 364.441 ;
     RECT  166.5 364.531 166.518 364.555 ;
     RECT  166.176 364.555 166.518 364.675 ;
     RECT  167.256 364.441 170.097 364.675 ;
     RECT  166.176 364.675 170.097 364.829 ;
     RECT  166.176 364.829 168.354 365.171 ;
     RECT  166.176 365.171 168.246 365.215 ;
     RECT  166.14 365.215 168.246 365.755 ;
     RECT  165.924 365.755 168.246 365.989 ;
     RECT  165.924 365.989 168.354 366.179 ;
     RECT  166.248 366.179 168.354 366.259 ;
     RECT  169.092 364.829 170.097 366.259 ;
     RECT  166.248 366.259 170.097 366.719 ;
     RECT  166.248 366.719 166.266 366.791 ;
     RECT  167.04 366.719 170.097 367.295 ;
     RECT  167.616 367.295 170.097 368.483 ;
     RECT  167.796 368.483 170.097 368.681 ;
     RECT  168.156 368.681 170.097 368.879 ;
     RECT  168.264 368.879 170.097 368.915 ;
     RECT  2.415 204.461 2.697 369.107 ;
     RECT  7.815 2.413 8.097 369.107 ;
     RECT  13.215 204.089 13.497 369.107 ;
     RECT  18.615 2.413 18.897 369.107 ;
     RECT  24.015 204.089 24.297 369.107 ;
     RECT  29.415 2.413 29.697 369.107 ;
     RECT  34.815 204.089 35.097 369.107 ;
     RECT  40.215 2.413 40.497 369.107 ;
     RECT  45.615 204.089 45.897 369.107 ;
     RECT  51.015 2.413 51.297 369.107 ;
     RECT  56.415 204.089 56.697 369.107 ;
     RECT  61.815 196.619 62.097 369.107 ;
     RECT  67.215 242.717 67.497 369.107 ;
     RECT  72.615 2.413 72.897 369.107 ;
     RECT  78.015 204.089 78.297 369.107 ;
     RECT  83.415 200.045 83.697 369.107 ;
     RECT  88.815 204.089 89.097 369.107 ;
     RECT  94.215 203.819 94.497 369.107 ;
     RECT  99.615 204.215 99.897 369.107 ;
     RECT  105.015 204.053 105.297 369.107 ;
     RECT  110.415 202.901 110.697 369.107 ;
     RECT  115.815 203.441 116.097 369.107 ;
     RECT  121.215 204.989 121.497 369.107 ;
     RECT  126.615 205.133 126.897 369.107 ;
     RECT  132.015 319.649 132.297 369.107 ;
     RECT  137.415 200.507 137.697 369.107 ;
     RECT  142.815 226.349 143.097 369.107 ;
     RECT  148.215 250.109 148.497 369.107 ;
     RECT  153.615 229.901 153.897 369.107 ;
     RECT  159.015 319.649 159.297 369.107 ;
     RECT  164.415 229.901 164.697 369.107 ;
     RECT  168.624 368.915 170.097 369.107 ;
     RECT  175.215 251.501 175.497 369.107 ;
     RECT  180.615 251.501 180.897 369.107 ;
     RECT  186.015 201.389 186.297 369.107 ;
     RECT  191.415 175.865 191.697 369.107 ;
     RECT  196.815 201.389 197.097 369.107 ;
     RECT  202.215 199.967 202.497 369.107 ;
     RECT  207.615 262.013 207.897 369.107 ;
     RECT  213.015 202.559 213.297 369.107 ;
     RECT  218.415 201.281 218.697 369.107 ;
     RECT  223.815 202.289 224.097 369.107 ;
     RECT  229.215 203.909 229.497 369.107 ;
     RECT  234.615 203.243 234.897 369.107 ;
     RECT  240.015 191.129 240.297 369.107 ;
     RECT  245.415 200.849 245.697 369.107 ;
     RECT  250.815 202.289 251.097 369.107 ;
     RECT  256.215 2.413 256.497 369.107 ;
     RECT  261.615 191.129 261.897 369.107 ;
     RECT  267.015 205.037 267.297 369.107 ;
     RECT  272.415 191.129 272.697 369.107 ;
     RECT  277.815 203.207 278.097 369.107 ;
     RECT  283.215 191.129 283.497 369.107 ;
     RECT  288.615 187.757 288.897 369.107 ;
     RECT  294.015 191.129 294.297 369.107 ;
     RECT  299.415 2.413 299.697 369.107 ;
     RECT  304.815 203.207 305.097 369.107 ;
     RECT  310.215 209.579 310.497 369.107 ;
     RECT  315.615 207.689 315.897 369.107 ;
     RECT  321.015 207.419 321.297 369.107 ;
     RECT  168.624 369.107 169.905 369.149 ;
     RECT  168.696 369.149 169.905 369.185 ;
     RECT  168.696 369.185 169.002 369.221 ;
     RECT  168.696 369.221 168.966 369.341 ;
     RECT  2.415 369.107 2.505 369.377 ;
     RECT  7.815 369.107 7.905 369.377 ;
     RECT  13.215 369.107 13.305 369.377 ;
     RECT  18.615 369.107 18.705 369.377 ;
     RECT  24.015 369.107 24.105 369.377 ;
     RECT  29.415 369.107 29.505 369.377 ;
     RECT  34.815 369.107 34.905 369.377 ;
     RECT  40.215 369.107 40.305 369.377 ;
     RECT  45.615 369.107 45.705 369.377 ;
     RECT  51.015 369.107 51.105 369.377 ;
     RECT  56.415 369.107 56.505 369.377 ;
     RECT  61.815 369.107 61.905 369.377 ;
     RECT  67.215 369.107 67.305 369.377 ;
     RECT  72.615 369.107 72.705 369.377 ;
     RECT  78.015 369.107 78.105 369.377 ;
     RECT  83.415 369.107 83.505 369.377 ;
     RECT  88.815 369.107 88.905 369.377 ;
     RECT  94.215 369.107 94.305 369.377 ;
     RECT  99.615 369.107 99.705 369.377 ;
     RECT  105.015 369.107 105.105 369.377 ;
     RECT  110.415 369.107 110.505 369.377 ;
     RECT  115.815 369.107 115.905 369.377 ;
     RECT  121.215 369.107 121.305 369.377 ;
     RECT  126.615 369.107 126.705 369.377 ;
     RECT  132.015 369.107 132.105 369.377 ;
     RECT  137.415 369.107 137.505 369.377 ;
     RECT  142.815 369.107 142.905 369.377 ;
     RECT  148.215 369.107 148.305 369.377 ;
     RECT  153.615 369.107 153.705 369.377 ;
     RECT  159.015 369.107 159.105 369.377 ;
     RECT  164.415 369.107 164.505 369.377 ;
     RECT  169.815 369.185 169.905 369.377 ;
     RECT  175.215 369.107 175.305 369.377 ;
     RECT  180.615 369.107 180.705 369.377 ;
     RECT  186.015 369.107 186.105 369.377 ;
     RECT  191.415 369.107 191.505 369.377 ;
     RECT  196.815 369.107 196.905 369.377 ;
     RECT  202.215 369.107 202.305 369.377 ;
     RECT  207.615 369.107 207.705 369.377 ;
     RECT  213.015 369.107 213.105 369.377 ;
     RECT  218.415 369.107 218.505 369.377 ;
     RECT  223.815 369.107 223.905 369.377 ;
     RECT  229.215 369.107 229.305 369.377 ;
     RECT  234.615 369.107 234.705 369.377 ;
     RECT  240.015 369.107 240.105 369.377 ;
     RECT  245.415 369.107 245.505 369.377 ;
     RECT  250.815 369.107 250.905 369.377 ;
     RECT  256.215 369.107 256.305 369.377 ;
     RECT  261.615 369.107 261.705 369.377 ;
     RECT  267.015 369.107 267.105 369.377 ;
     RECT  272.415 369.107 272.505 369.377 ;
     RECT  277.815 369.107 277.905 369.377 ;
     RECT  283.215 369.107 283.305 369.377 ;
     RECT  288.615 369.107 288.705 369.377 ;
     RECT  294.015 369.107 294.105 369.377 ;
     RECT  299.415 369.107 299.505 369.377 ;
     RECT  304.815 369.107 304.905 369.377 ;
     RECT  310.215 369.107 310.305 369.377 ;
     RECT  315.615 369.107 315.705 369.377 ;
     RECT  321.015 369.107 321.105 369.377 ;
     RECT  168.696 369.341 168.858 370.541 ;
     RECT  168.84 370.541 168.858 371.405 ;
    LAYER M4 ;
     RECT  0.025 205.152 0.06 205.176 ;
     RECT  0.06 194.928 0.097 201.768 ;
     RECT  0.06 203.088 0.137 205.176 ;
     RECT  0.097 194.736 0.209 201.768 ;
     RECT  0.06 160.368 0.497 178.728 ;
     RECT  0.497 160.368 0.638 178.68 ;
     RECT  0.06 153.456 2.408 156.456 ;
     RECT  0.638 160.368 2.408 176.52 ;
     RECT  0.638 177.504 2.408 178.68 ;
     RECT  0.209 194.736 2.408 201.576 ;
     RECT  0.137 203.088 2.408 204.744 ;
     RECT  2.408 2.148 2.512 369.372 ;
     RECT  2.512 2.418 2.704 369.102 ;
     RECT  2.704 153.456 7.808 156.456 ;
     RECT  2.704 160.32 7.808 176.52 ;
     RECT  2.704 177.504 7.808 178.68 ;
     RECT  2.704 194.736 7.808 197.736 ;
     RECT  2.704 198.768 7.808 201.576 ;
     RECT  2.704 203.088 7.808 204.552 ;
     RECT  7.808 2.148 7.912 369.372 ;
     RECT  7.912 2.418 8.104 369.102 ;
     RECT  8.104 153.456 13.208 156.456 ;
     RECT  8.104 160.32 13.208 176.52 ;
     RECT  8.104 177.504 13.208 178.68 ;
     RECT  8.104 194.736 13.208 197.736 ;
     RECT  8.104 198.768 13.208 201.576 ;
     RECT  8.104 203.088 13.208 204.552 ;
     RECT  13.208 2.148 13.312 369.372 ;
     RECT  13.312 2.418 13.504 369.102 ;
     RECT  13.504 153.456 18.608 156.456 ;
     RECT  13.504 160.32 18.608 176.52 ;
     RECT  13.504 177.504 18.608 178.68 ;
     RECT  13.504 194.736 18.608 197.736 ;
     RECT  13.504 198.768 18.608 201.576 ;
     RECT  13.504 203.088 18.608 204.552 ;
     RECT  18.608 2.148 18.712 369.372 ;
     RECT  18.712 2.418 18.904 369.102 ;
     RECT  18.904 153.456 24.008 156.456 ;
     RECT  18.904 160.32 24.008 176.52 ;
     RECT  18.904 177.504 24.008 178.68 ;
     RECT  18.904 194.736 24.008 197.736 ;
     RECT  18.904 198.768 24.008 201.576 ;
     RECT  18.904 203.088 24.008 204.552 ;
     RECT  24.008 2.148 24.112 369.372 ;
     RECT  24.112 2.418 24.304 369.102 ;
     RECT  24.304 153.456 29.408 156.456 ;
     RECT  24.304 160.32 29.408 176.52 ;
     RECT  24.304 177.504 29.408 178.68 ;
     RECT  24.304 194.736 29.408 197.736 ;
     RECT  24.304 198.768 29.408 201.576 ;
     RECT  24.304 203.088 29.408 204.552 ;
     RECT  29.408 2.148 29.512 369.372 ;
     RECT  29.512 2.418 29.704 369.102 ;
     RECT  29.704 153.456 34.808 156.456 ;
     RECT  29.704 160.32 34.808 176.52 ;
     RECT  29.704 177.504 34.808 178.68 ;
     RECT  29.704 194.736 34.808 197.736 ;
     RECT  29.704 198.768 34.808 201.576 ;
     RECT  29.704 203.088 34.808 204.552 ;
     RECT  34.808 2.148 34.912 369.372 ;
     RECT  34.912 2.418 35.104 369.102 ;
     RECT  35.104 153.456 40.208 156.456 ;
     RECT  35.104 160.32 40.208 176.52 ;
     RECT  35.104 177.504 40.208 178.68 ;
     RECT  35.104 194.736 40.208 197.736 ;
     RECT  35.104 198.768 40.208 201.576 ;
     RECT  35.104 203.088 40.208 204.552 ;
     RECT  40.208 2.148 40.312 369.372 ;
     RECT  40.312 2.418 40.504 369.102 ;
     RECT  40.504 153.456 45.608 156.456 ;
     RECT  40.504 160.32 45.608 176.52 ;
     RECT  40.504 177.504 45.608 178.68 ;
     RECT  40.504 194.736 45.608 197.736 ;
     RECT  40.504 198.768 45.608 201.576 ;
     RECT  40.504 203.088 45.608 204.552 ;
     RECT  45.608 2.148 45.712 369.372 ;
     RECT  45.712 2.418 45.904 369.102 ;
     RECT  45.904 153.456 51.008 156.456 ;
     RECT  45.904 160.32 51.008 176.52 ;
     RECT  45.904 177.504 51.008 178.68 ;
     RECT  45.904 194.736 51.008 197.736 ;
     RECT  45.904 198.768 51.008 201.576 ;
     RECT  45.904 203.088 51.008 204.552 ;
     RECT  51.008 2.148 51.112 369.372 ;
     RECT  51.112 2.418 51.304 369.102 ;
     RECT  51.304 153.456 56.408 156.456 ;
     RECT  51.304 160.32 56.408 176.52 ;
     RECT  51.304 177.504 56.408 178.68 ;
     RECT  51.304 194.736 56.408 197.736 ;
     RECT  51.304 198.768 56.408 201.576 ;
     RECT  51.304 203.088 56.408 204.552 ;
     RECT  56.408 2.148 56.512 369.372 ;
     RECT  56.512 2.418 56.704 369.102 ;
     RECT  56.704 153.456 61.808 156.456 ;
     RECT  56.704 160.32 61.808 176.52 ;
     RECT  56.704 177.504 61.808 178.68 ;
     RECT  56.704 194.736 61.808 197.736 ;
     RECT  56.704 198.768 61.808 201.576 ;
     RECT  56.704 203.088 61.808 204.552 ;
     RECT  61.808 2.148 61.912 369.372 ;
     RECT  61.912 2.418 62.104 369.102 ;
     RECT  62.104 153.456 67.208 156.456 ;
     RECT  62.104 160.32 67.208 176.52 ;
     RECT  62.104 177.504 67.208 178.68 ;
     RECT  62.104 194.736 67.208 197.736 ;
     RECT  62.104 198.768 67.208 201.576 ;
     RECT  62.104 203.088 67.208 204.552 ;
     RECT  67.208 2.148 67.312 369.372 ;
     RECT  67.312 2.418 67.504 369.102 ;
     RECT  67.504 242.688 67.852 242.712 ;
     RECT  67.504 153.456 72.608 156.456 ;
     RECT  67.504 160.32 72.608 176.52 ;
     RECT  67.504 177.504 72.608 178.68 ;
     RECT  67.504 194.736 72.608 197.736 ;
     RECT  67.504 198.768 72.608 201.576 ;
     RECT  67.504 203.088 72.608 204.552 ;
     RECT  67.504 319.488 72.608 319.512 ;
     RECT  72.608 2.148 72.712 369.372 ;
     RECT  72.712 2.418 72.904 369.102 ;
     RECT  72.904 153.456 78.008 156.456 ;
     RECT  72.904 160.32 78.008 176.52 ;
     RECT  72.904 177.504 78.008 178.68 ;
     RECT  72.904 194.736 78.008 197.736 ;
     RECT  72.904 198.768 78.008 201.576 ;
     RECT  72.904 203.088 78.008 204.552 ;
     RECT  72.904 319.488 78.008 319.512 ;
     RECT  78.008 2.148 78.112 369.372 ;
     RECT  78.112 2.418 78.304 369.102 ;
     RECT  78.304 153.456 83.408 156.456 ;
     RECT  78.304 160.32 83.408 176.52 ;
     RECT  78.304 177.504 83.408 178.68 ;
     RECT  78.304 194.736 83.408 197.736 ;
     RECT  78.304 198.768 83.408 201.576 ;
     RECT  78.304 203.088 83.408 204.552 ;
     RECT  78.304 319.488 83.408 319.512 ;
     RECT  83.408 2.148 83.512 369.372 ;
     RECT  83.512 2.418 83.704 369.102 ;
     RECT  83.704 198.768 86.677 201.576 ;
     RECT  83.704 153.456 88.808 156.456 ;
     RECT  83.704 160.32 88.808 176.52 ;
     RECT  83.704 177.504 88.808 178.68 ;
     RECT  83.704 194.736 88.808 197.736 ;
     RECT  86.677 198.768 88.808 201.624 ;
     RECT  83.704 203.088 88.808 204.552 ;
     RECT  83.704 319.488 88.808 319.512 ;
     RECT  88.808 2.148 88.912 369.372 ;
     RECT  88.912 2.418 89.104 369.102 ;
     RECT  89.104 194.736 90.457 197.736 ;
     RECT  89.104 198.768 90.457 201.624 ;
     RECT  90.457 194.736 90.673 201.624 ;
     RECT  89.104 202.704 90.673 204.552 ;
     RECT  90.673 194.736 90.893 204.552 ;
     RECT  90.893 198.768 91.289 204.552 ;
     RECT  91.289 198.768 91.541 201.816 ;
     RECT  91.541 198.768 91.757 198.936 ;
     RECT  91.541 199.968 92.405 201.816 ;
     RECT  91.289 202.944 92.941 204.552 ;
     RECT  90.893 194.736 92.977 197.736 ;
     RECT  91.757 198.768 92.977 198.792 ;
     RECT  92.405 200.016 93.445 201.816 ;
     RECT  92.977 194.736 93.481 198.792 ;
     RECT  93.445 200.016 93.481 201.864 ;
     RECT  93.481 194.736 94.129 201.864 ;
     RECT  92.941 202.896 94.129 204.552 ;
     RECT  89.104 153.456 94.208 156.456 ;
     RECT  89.104 160.32 94.208 176.52 ;
     RECT  89.104 177.504 94.208 178.68 ;
     RECT  94.129 194.736 94.208 204.552 ;
     RECT  89.104 319.488 94.208 319.512 ;
     RECT  94.208 2.148 94.312 369.372 ;
     RECT  94.312 2.418 94.504 369.102 ;
     RECT  94.504 194.736 94.673 204.552 ;
     RECT  94.673 194.736 95.249 202.152 ;
     RECT  94.673 203.184 95.429 204.552 ;
     RECT  95.249 200.112 96.185 202.152 ;
     RECT  95.429 203.472 96.401 204.552 ;
     RECT  95.249 194.736 96.901 198.792 ;
     RECT  96.901 194.736 97.013 199.08 ;
     RECT  97.013 198.768 97.049 199.08 ;
     RECT  96.401 203.664 97.121 204.552 ;
     RECT  96.185 200.112 97.157 202.056 ;
     RECT  97.121 203.952 97.337 204.552 ;
     RECT  97.157 200.16 98.269 202.056 ;
     RECT  98.269 200.16 98.305 202.584 ;
     RECT  97.049 198.768 98.377 198.792 ;
     RECT  98.305 199.872 98.377 202.584 ;
     RECT  97.337 204.048 98.485 204.552 ;
     RECT  98.485 204 98.701 204.552 ;
     RECT  98.377 198.768 99.205 202.584 ;
     RECT  98.701 203.712 99.205 204.552 ;
     RECT  94.504 153.456 99.608 156.456 ;
     RECT  94.504 160.32 99.608 176.52 ;
     RECT  94.504 177.504 99.608 178.68 ;
     RECT  97.013 194.736 99.608 197.736 ;
     RECT  99.205 198.768 99.608 204.552 ;
     RECT  94.504 319.488 99.608 319.512 ;
     RECT  99.608 2.148 99.712 369.372 ;
     RECT  99.712 2.418 99.904 369.102 ;
     RECT  99.904 198.768 101.189 204.552 ;
     RECT  101.189 198.768 101.507 202.968 ;
     RECT  101.507 199.92 102.233 202.968 ;
     RECT  101.189 204.048 102.341 204.552 ;
     RECT  102.341 204.528 102.701 204.552 ;
     RECT  102.233 199.92 103.273 202.92 ;
     RECT  103.273 199.92 103.313 203.496 ;
     RECT  103.313 200.112 103.853 203.496 ;
     RECT  99.904 153.456 105.008 156.456 ;
     RECT  99.904 160.32 105.008 176.52 ;
     RECT  99.904 177.504 105.008 178.68 ;
     RECT  99.904 194.736 105.008 197.736 ;
     RECT  101.507 198.768 105.008 198.792 ;
     RECT  103.853 200.208 105.008 203.496 ;
     RECT  99.904 319.488 105.008 319.512 ;
     RECT  105.008 2.148 105.112 369.372 ;
     RECT  105.112 2.418 105.304 369.102 ;
     RECT  105.304 200.208 106.067 203.688 ;
     RECT  105.304 198.768 106.585 198.792 ;
     RECT  106.585 198.768 106.625 198.888 ;
     RECT  106.625 198.864 106.765 198.888 ;
     RECT  106.067 200.208 106.765 203.256 ;
     RECT  106.765 198.864 107.489 203.256 ;
     RECT  107.489 198.864 108.029 199.512 ;
     RECT  108.029 198.864 108.065 199.224 ;
     RECT  107.489 200.736 108.637 203.256 ;
     RECT  108.637 200.688 108.673 203.256 ;
     RECT  108.673 200.592 108.745 203.256 ;
     RECT  108.065 198.864 109.465 199.128 ;
     RECT  109.465 198.864 109.825 199.176 ;
     RECT  108.745 200.544 109.825 203.256 ;
     RECT  105.304 153.456 110.408 156.456 ;
     RECT  105.304 160.32 110.408 176.52 ;
     RECT  105.304 177.504 110.408 178.68 ;
     RECT  105.304 194.736 110.408 197.736 ;
     RECT  109.825 198.864 110.408 203.256 ;
     RECT  105.304 319.488 110.408 319.512 ;
     RECT  110.408 2.148 110.512 369.372 ;
     RECT  110.512 2.418 110.704 369.102 ;
     RECT  110.704 198.768 111.701 203.256 ;
     RECT  111.701 199.92 112.237 203.256 ;
     RECT  112.237 199.92 113.569 203.4 ;
     RECT  113.569 199.92 113.987 203.496 ;
     RECT  111.701 198.768 114.109 198.792 ;
     RECT  113.987 199.92 114.109 203.4 ;
     RECT  110.704 153.456 115.808 156.456 ;
     RECT  110.704 160.32 115.808 176.52 ;
     RECT  110.704 177.504 115.808 178.68 ;
     RECT  110.704 194.736 115.808 197.736 ;
     RECT  114.109 198.768 115.808 203.4 ;
     RECT  113.941 204.72 115.808 204.744 ;
     RECT  110.704 319.488 115.808 319.512 ;
     RECT  115.808 2.148 115.912 369.372 ;
     RECT  115.912 2.418 116.104 369.102 ;
     RECT  116.104 198.768 116.243 204.744 ;
     RECT  116.243 199.872 116.675 204.744 ;
     RECT  116.675 199.872 117.029 202.392 ;
     RECT  117.029 199.968 118.897 202.392 ;
     RECT  116.675 203.376 118.897 204.744 ;
     RECT  118.897 199.968 119.297 204.744 ;
     RECT  119.297 199.968 120.697 202.392 ;
     RECT  119.297 203.376 120.697 204.744 ;
     RECT  116.104 153.456 121.208 156.456 ;
     RECT  116.104 160.32 121.208 176.52 ;
     RECT  116.104 177.504 121.208 178.68 ;
     RECT  116.104 194.736 121.208 197.736 ;
     RECT  116.243 198.768 121.208 198.792 ;
     RECT  120.697 199.968 121.208 204.744 ;
     RECT  116.104 319.488 121.208 319.512 ;
     RECT  121.208 2.148 121.312 369.372 ;
     RECT  121.312 2.418 121.504 369.102 ;
     RECT  121.504 199.968 121.745 204.744 ;
     RECT  121.745 204.72 122.681 204.744 ;
     RECT  121.504 198.768 122.857 198.792 ;
     RECT  121.745 199.968 122.857 203.4 ;
     RECT  122.857 198.768 123.041 203.4 ;
     RECT  123.041 198.768 124.009 201.864 ;
     RECT  123.041 202.944 124.045 203.4 ;
     RECT  124.009 198.768 124.117 201.912 ;
     RECT  124.045 202.944 124.117 204.36 ;
     RECT  124.045 218.496 124.405 218.52 ;
     RECT  124.405 218.304 124.489 218.52 ;
     RECT  124.117 198.768 124.769 204.36 ;
     RECT  124.769 202.8 124.805 204.36 ;
     RECT  124.805 202.8 126.457 203.88 ;
     RECT  121.504 153.456 126.608 156.456 ;
     RECT  121.504 160.32 126.608 176.52 ;
     RECT  121.504 177.504 126.608 178.68 ;
     RECT  121.504 194.736 126.608 197.736 ;
     RECT  124.769 198.768 126.608 201.624 ;
     RECT  126.457 202.8 126.608 203.928 ;
     RECT  124.489 218.496 126.608 218.52 ;
     RECT  121.504 319.488 126.608 319.512 ;
     RECT  126.608 2.148 126.712 369.372 ;
     RECT  126.712 2.418 126.904 369.102 ;
     RECT  126.904 203.52 128.257 204.168 ;
     RECT  128.257 203.52 128.341 204.648 ;
     RECT  126.904 197.52 128.549 197.736 ;
     RECT  126.904 198.768 128.693 201.768 ;
     RECT  128.341 203.52 128.833 204.168 ;
     RECT  128.833 203.472 128.873 204.168 ;
     RECT  128.873 203.472 129.121 203.736 ;
     RECT  128.693 198.768 129.697 201.624 ;
     RECT  129.121 202.992 129.769 203.736 ;
     RECT  129.769 202.944 129.773 203.736 ;
     RECT  129.773 202.944 129.809 203.496 ;
     RECT  128.549 197.52 129.845 197.544 ;
     RECT  129.809 202.944 129.875 203.016 ;
     RECT  129.875 202.992 130.169 203.016 ;
     RECT  126.904 194.736 130.561 196.488 ;
     RECT  129.697 198.768 130.745 201.816 ;
     RECT  126.904 160.32 130.853 176.52 ;
     RECT  130.741 197.664 130.921 197.688 ;
     RECT  130.561 194.592 130.957 196.488 ;
     RECT  130.921 197.472 130.957 197.688 ;
     RECT  130.957 194.592 130.993 197.688 ;
     RECT  130.993 194.592 131.029 197.736 ;
     RECT  130.745 198.768 131.029 201.624 ;
     RECT  126.904 153.456 132.008 156.456 ;
     RECT  130.853 160.752 132.008 176.52 ;
     RECT  126.904 177.504 132.008 178.68 ;
     RECT  131.029 194.592 132.008 201.624 ;
     RECT  126.904 218.496 132.008 218.52 ;
     RECT  126.904 319.488 132.008 319.512 ;
     RECT  132.008 2.148 132.112 369.372 ;
     RECT  132.112 2.418 132.304 369.102 ;
     RECT  132.304 197.952 132.611 201.624 ;
     RECT  132.304 160.752 133.361 178.392 ;
     RECT  132.304 191.472 133.369 192.024 ;
     RECT  132.304 319.488 133.409 319.56 ;
     RECT  132.611 198.24 133.427 201.624 ;
     RECT  133.361 160.752 133.445 179.016 ;
     RECT  133.427 198.768 133.453 201.624 ;
     RECT  132.304 194.256 133.729 196.728 ;
     RECT  133.729 194.016 133.813 196.728 ;
     RECT  133.813 193.104 133.859 196.728 ;
     RECT  133.859 194.256 134.197 196.728 ;
     RECT  133.859 193.104 134.201 193.128 ;
     RECT  133.445 160.752 134.413 178.392 ;
     RECT  133.369 191.472 134.449 192.072 ;
     RECT  134.197 194.256 134.917 196.824 ;
     RECT  134.413 160.752 135.277 178.44 ;
     RECT  135.277 160.752 135.395 178.632 ;
     RECT  135.385 159.264 135.457 159.288 ;
     RECT  134.053 182.592 135.601 182.616 ;
     RECT  135.457 159.216 135.637 159.288 ;
     RECT  134.917 193.776 135.641 196.824 ;
     RECT  135.601 158.16 135.673 158.184 ;
     RECT  135.637 159.216 135.673 159.384 ;
     RECT  134.449 191.472 135.709 192.504 ;
     RECT  135.641 193.776 135.785 196.488 ;
     RECT  135.673 158.16 135.817 159.384 ;
     RECT  135.709 191.472 135.889 192.648 ;
     RECT  135.785 193.776 135.889 196.056 ;
     RECT  135.817 157.824 135.925 159.384 ;
     RECT  135.395 160.752 135.925 177.864 ;
     RECT  136.069 190.368 136.163 190.392 ;
     RECT  135.889 191.472 136.289 196.056 ;
     RECT  136.268 190.464 136.355 190.488 ;
     RECT  136.289 192.096 136.397 196.056 ;
     RECT  132.304 153.456 136.556 156.456 ;
     RECT  135.925 157.824 136.556 177.864 ;
     RECT  136.556 153.456 137.408 177.864 ;
     RECT  135.601 182.592 137.408 182.664 ;
     RECT  136.309 186.672 137.408 186.696 ;
     RECT  136.397 192.384 137.408 196.056 ;
     RECT  133.453 198.768 137.408 198.792 ;
     RECT  133.453 199.968 137.408 201.624 ;
     RECT  132.304 218.496 137.408 218.52 ;
     RECT  133.409 319.536 137.408 319.56 ;
     RECT  137.408 2.148 137.512 369.372 ;
     RECT  137.512 2.418 137.704 369.102 ;
     RECT  137.704 153.456 137.837 157.032 ;
     RECT  137.704 158.448 137.884 178.248 ;
     RECT  137.704 182.448 138.521 182.664 ;
     RECT  137.837 153.552 138.557 157.032 ;
     RECT  137.884 158.448 138.593 177.768 ;
     RECT  137.704 196.032 138.773 196.056 ;
     RECT  137.704 193.344 139.025 193.416 ;
     RECT  138.593 158.544 139.169 177.768 ;
     RECT  138.557 154.224 139.493 157.032 ;
     RECT  138.521 182.448 139.667 182.616 ;
     RECT  139.169 158.544 139.741 159.528 ;
     RECT  139.169 160.512 139.853 177.768 ;
     RECT  139.493 154.896 139.889 157.032 ;
     RECT  139.889 154.896 139.925 154.92 ;
     RECT  139.741 158.256 139.957 159.528 ;
     RECT  139.889 156.72 139.996 157.032 ;
     RECT  140.029 194.448 140.101 194.472 ;
     RECT  139.885 195.648 140.101 195.672 ;
     RECT  139.853 160.512 140.105 177.672 ;
     RECT  139.996 156.768 140.137 157.032 ;
     RECT  140.137 156.768 140.173 157.224 ;
     RECT  139.957 158.208 140.173 159.528 ;
     RECT  140.173 156.768 140.209 159.528 ;
     RECT  140.105 160.512 140.209 167.16 ;
     RECT  140.101 194.448 140.245 195.672 ;
     RECT  139.025 193.392 140.396 193.416 ;
     RECT  140.245 194.448 140.396 196.056 ;
     RECT  140.396 193.392 140.497 196.056 ;
     RECT  140.437 190.896 140.537 190.92 ;
     RECT  137.704 199.968 140.569 201.624 ;
     RECT  140.497 193.296 140.675 196.056 ;
     RECT  137.704 198.768 140.681 198.792 ;
     RECT  140.245 192.096 140.929 192.12 ;
     RECT  140.675 193.296 141.365 195.96 ;
     RECT  140.209 156.768 141.433 167.16 ;
     RECT  140.105 168.144 141.433 177.672 ;
     RECT  141.365 194.496 141.509 195.96 ;
     RECT  141.433 156.768 141.589 177.672 ;
     RECT  140.569 199.968 141.617 202.248 ;
     RECT  140.929 191.376 141.689 192.12 ;
     RECT  141.509 194.928 141.757 195.96 ;
     RECT  141.689 191.52 142.261 192.12 ;
     RECT  141.365 193.296 142.261 193.32 ;
     RECT  139.667 182.592 142.369 182.616 ;
     RECT  142.369 182.592 142.449 183.144 ;
     RECT  142.261 191.52 142.477 193.32 ;
     RECT  142.477 191.52 142.513 193.704 ;
     RECT  137.704 186.672 142.621 186.696 ;
     RECT  142.513 191.52 142.621 193.944 ;
     RECT  141.757 194.928 142.621 196.536 ;
     RECT  142.621 186.384 142.645 186.696 ;
     RECT  142.621 191.52 142.652 196.536 ;
     RECT  141.589 156.768 142.808 177.864 ;
     RECT  142.449 182.592 142.808 183.672 ;
     RECT  142.645 185.952 142.808 186.696 ;
     RECT  142.652 191.472 142.808 196.536 ;
     RECT  141.617 199.968 142.808 201.624 ;
     RECT  137.704 218.496 142.808 218.52 ;
     RECT  140.245 226.32 142.808 226.344 ;
     RECT  137.704 319.536 142.808 319.56 ;
     RECT  142.808 2.148 142.912 369.372 ;
     RECT  142.912 2.418 143.104 369.102 ;
     RECT  143.104 193.92 143.237 196.056 ;
     RECT  143.104 156.96 143.309 178.776 ;
     RECT  143.104 185.952 143.489 186.408 ;
     RECT  143.489 185.952 143.777 186.168 ;
     RECT  143.104 188.256 143.849 188.664 ;
     RECT  143.104 181.776 143.921 182.904 ;
     RECT  143.104 218.496 143.939 218.856 ;
     RECT  143.104 180.144 144.097 180.168 ;
     RECT  143.104 191.664 144.097 191.88 ;
     RECT  143.939 218.832 144.179 218.856 ;
     RECT  144.097 225.168 144.181 225.192 ;
     RECT  143.777 185.952 144.325 185.976 ;
     RECT  144.097 191.664 144.349 192.6 ;
     RECT  143.309 178.752 144.38 178.776 ;
     RECT  143.237 194.496 144.389 196.056 ;
     RECT  143.309 156.96 144.421 177.624 ;
     RECT  144.38 178.752 144.421 179.112 ;
     RECT  144.421 156.96 144.467 179.112 ;
     RECT  144.284 183.84 144.467 183.864 ;
     RECT  143.921 181.776 144.677 182.616 ;
     RECT  144.325 185.472 144.745 185.976 ;
     RECT  144.389 194.496 144.785 195.576 ;
     RECT  144.745 185.184 144.805 185.976 ;
     RECT  144.467 156.96 144.821 178.392 ;
     RECT  144.785 194.496 145.033 194.952 ;
     RECT  144.097 180.144 145.069 180.744 ;
     RECT  143.849 188.256 145.177 188.328 ;
     RECT  144.349 191.376 145.213 192.6 ;
     RECT  145.177 187.872 145.541 188.328 ;
     RECT  143.104 226.32 145.619 226.344 ;
     RECT  144.821 158.544 145.717 178.392 ;
     RECT  144.805 185.184 145.753 186.408 ;
     RECT  145.213 191.376 145.825 192.696 ;
     RECT  145.033 194.16 145.825 194.952 ;
     RECT  145.753 184.704 145.868 186.792 ;
     RECT  145.825 190.944 145.897 194.952 ;
     RECT  144.677 182.304 145.909 182.616 ;
     RECT  145.868 184.08 145.909 186.792 ;
     RECT  145.909 182.304 145.955 186.792 ;
     RECT  145.069 179.904 145.957 180.744 ;
     RECT  145.897 190.944 145.969 195.336 ;
     RECT  145.969 190.944 146.009 195.672 ;
     RECT  145.957 179.904 146.044 181.272 ;
     RECT  145.541 188.304 146.045 188.328 ;
     RECT  143.104 189.792 146.053 189.816 ;
     RECT  146.009 190.944 146.053 194.04 ;
     RECT  145.955 184.704 146.189 186.792 ;
     RECT  146.053 189.792 146.195 194.04 ;
     RECT  146.044 179.904 146.225 180.6 ;
     RECT  146.195 193.248 146.225 194.04 ;
     RECT  146.189 185.184 146.341 186.792 ;
     RECT  146.195 189.792 146.477 192.024 ;
     RECT  146.225 193.248 146.477 193.848 ;
     RECT  146.341 185.184 146.483 187.176 ;
     RECT  146.483 186.768 146.513 187.176 ;
     RECT  146.477 190.032 146.513 192.024 ;
     RECT  145.955 182.304 146.549 183.288 ;
     RECT  145.573 249.648 146.549 249.672 ;
     RECT  146.483 185.184 146.585 185.688 ;
     RECT  146.513 186.768 146.657 186.792 ;
     RECT  145.717 158.544 146.797 178.776 ;
     RECT  146.009 195.12 146.905 195.672 ;
     RECT  146.549 182.592 147.157 183.288 ;
     RECT  146.513 190.416 147.229 192.024 ;
     RECT  146.905 195.12 147.229 196.056 ;
     RECT  146.797 158.544 147.409 179.256 ;
     RECT  146.225 180.576 147.409 180.6 ;
     RECT  147.229 190.416 147.589 192.456 ;
     RECT  146.477 193.44 147.589 193.848 ;
     RECT  146.585 185.664 148.201 185.688 ;
     RECT  144.821 156.96 148.208 156.984 ;
     RECT  147.409 158.544 148.208 180.6 ;
     RECT  147.157 182.592 148.208 183.816 ;
     RECT  148.201 185.136 148.208 185.688 ;
     RECT  147.013 189.024 148.208 189.048 ;
     RECT  147.589 190.416 148.208 193.848 ;
     RECT  147.229 195.12 148.208 196.2 ;
     RECT  143.104 199.968 148.208 201.624 ;
     RECT  143.104 205.248 148.208 205.272 ;
     RECT  148.057 250.08 148.208 250.104 ;
     RECT  143.104 319.536 148.208 319.56 ;
     RECT  148.208 2.148 148.312 369.372 ;
     RECT  148.312 2.418 148.504 369.102 ;
     RECT  148.504 189.888 148.673 195.144 ;
     RECT  148.504 179.808 148.681 182.952 ;
     RECT  148.681 179.808 148.691 182.616 ;
     RECT  148.504 158.064 148.787 177.672 ;
     RECT  148.691 179.808 148.787 182.568 ;
     RECT  148.787 158.064 148.835 177.288 ;
     RECT  148.504 178.752 148.876 178.824 ;
     RECT  148.504 196.176 148.889 196.2 ;
     RECT  148.673 190.944 148.925 195.144 ;
     RECT  148.835 158.064 148.997 176.712 ;
     RECT  148.925 190.944 149.429 194.376 ;
     RECT  148.673 189.888 149.677 189.912 ;
     RECT  149.677 188.928 149.713 189.912 ;
     RECT  149.429 190.944 149.713 190.968 ;
     RECT  149.713 188.928 149.753 190.968 ;
     RECT  148.787 180.72 149.785 182.568 ;
     RECT  149.785 180.096 149.832 182.568 ;
     RECT  149.832 180.096 149.933 182.76 ;
     RECT  148.504 185.136 149.939 185.16 ;
     RECT  148.504 156.96 149.965 156.984 ;
     RECT  148.997 158.064 149.965 175.704 ;
     RECT  148.997 176.688 149.965 176.712 ;
     RECT  148.876 178.8 150.401 178.824 ;
     RECT  149.933 181.248 150.401 182.76 ;
     RECT  149.429 192.576 150.437 194.376 ;
     RECT  150.437 194.304 150.505 194.376 ;
     RECT  149.965 156.96 150.581 176.712 ;
     RECT  150.401 182.544 150.613 182.76 ;
     RECT  150.581 156.96 150.617 176.376 ;
     RECT  150.401 181.248 150.617 181.272 ;
     RECT  150.437 192.576 150.689 193.08 ;
     RECT  150.505 194.304 150.761 194.712 ;
     RECT  149.753 190.56 150.869 190.968 ;
     RECT  150.689 192.576 150.869 192.696 ;
     RECT  149.933 180.096 150.905 180.12 ;
     RECT  150.613 182.544 150.941 183 ;
     RECT  150.761 194.688 150.977 194.712 ;
     RECT  149.893 186.336 151.153 186.36 ;
     RECT  151.153 185.808 151.157 186.36 ;
     RECT  151.436 180.576 151.523 180.6 ;
     RECT  151.157 185.808 151.523 185.832 ;
     RECT  148.504 205.248 151.573 205.8 ;
     RECT  151.477 186.912 151.619 186.936 ;
     RECT  150.869 190.56 151.625 190.92 ;
     RECT  151.573 205.248 151.66 205.944 ;
     RECT  150.869 192.672 151.661 192.696 ;
     RECT  151.625 190.896 151.909 190.92 ;
     RECT  151.585 196.992 151.909 197.016 ;
     RECT  151.66 205.248 151.949 205.8 ;
     RECT  151.909 190.896 151.955 191.352 ;
     RECT  151.955 191.28 151.981 191.352 ;
     RECT  151.909 196.656 151.993 197.016 ;
     RECT  150.617 156.96 152.089 175.896 ;
     RECT  149.753 188.928 152.089 188.952 ;
     RECT  152.089 156.96 152.195 176.712 ;
     RECT  151.981 191.28 152.309 192.024 ;
     RECT  152.293 184.176 152.38 184.2 ;
     RECT  152.089 188.928 152.489 189.624 ;
     RECT  152.161 179.808 152.588 179.832 ;
     RECT  152.489 189.6 153.385 189.624 ;
     RECT  151.729 181.632 153.457 181.656 ;
     RECT  150.941 182.976 153.457 183 ;
     RECT  152.195 156.96 153.608 175.944 ;
     RECT  153.313 177.216 153.608 177.24 ;
     RECT  152.588 179.472 153.608 179.832 ;
     RECT  153.457 181.632 153.608 183 ;
     RECT  153.385 189.6 153.608 189.72 ;
     RECT  152.309 191.28 153.608 191.352 ;
     RECT  151.993 196.992 153.608 197.016 ;
     RECT  148.504 199.968 153.608 201.624 ;
     RECT  151.573 229.872 153.608 229.896 ;
     RECT  148.504 250.08 153.608 250.104 ;
     RECT  148.504 319.536 153.608 319.56 ;
     RECT  153.608 2.148 153.712 369.372 ;
     RECT  153.712 2.418 153.904 369.102 ;
     RECT  153.904 229.728 154.001 229.896 ;
     RECT  153.904 156.96 154.217 175.992 ;
     RECT  153.904 196.992 154.469 197.16 ;
     RECT  153.904 192.672 154.685 193.272 ;
     RECT  153.904 189.696 154.829 191.352 ;
     RECT  154.217 158.496 154.969 175.992 ;
     RECT  154.829 190.656 155.132 191.352 ;
     RECT  155.132 190.656 155.219 191.496 ;
     RECT  154.969 158.496 155.225 176.088 ;
     RECT  155.219 190.656 155.297 190.968 ;
     RECT  155.225 158.544 155.621 176.088 ;
     RECT  153.904 182.304 155.653 183.192 ;
     RECT  154.217 156.96 155.797 156.984 ;
     RECT  155.653 182.304 156.085 183.384 ;
     RECT  155.621 158.592 156.133 176.088 ;
     RECT  155.845 179.52 156.133 179.544 ;
     RECT  156.133 179.376 156.179 179.544 ;
     RECT  156.085 181.776 156.179 183.384 ;
     RECT  156.179 182.688 156.197 183.384 ;
     RECT  156.197 182.688 156.233 183.048 ;
     RECT  153.904 199.968 156.269 201.624 ;
     RECT  156.233 183.024 156.305 183.048 ;
     RECT  155.297 190.656 156.413 190.872 ;
     RECT  156.133 158.592 156.449 176.568 ;
     RECT  154.685 192.672 156.625 192.696 ;
     RECT  156.625 192.624 156.733 192.696 ;
     RECT  155.761 193.776 156.733 193.8 ;
     RECT  156.733 192.624 156.773 193.8 ;
     RECT  153.904 185.808 156.881 185.832 ;
     RECT  156.179 179.376 157.525 179.4 ;
     RECT  155.005 180.72 157.525 180.744 ;
     RECT  157.525 179.376 157.565 180.744 ;
     RECT  156.449 158.592 157.573 175.56 ;
     RECT  156.449 176.544 157.573 176.568 ;
     RECT  157.565 179.376 157.619 180.168 ;
     RECT  156.773 192.672 157.925 192.84 ;
     RECT  155.797 156.96 158.461 157.08 ;
     RECT  154.001 229.728 158.461 229.752 ;
     RECT  158.461 156.96 158.533 157.56 ;
     RECT  157.573 158.592 158.533 176.568 ;
     RECT  157.925 192.672 158.641 192.696 ;
     RECT  158.533 156.816 158.677 176.568 ;
     RECT  157.705 190.944 158.749 190.968 ;
     RECT  158.677 156.72 159.008 176.568 ;
     RECT  157.619 179.376 159.008 179.4 ;
     RECT  157.489 181.776 159.008 181.8 ;
     RECT  158.749 190.464 159.008 190.968 ;
     RECT  158.641 192.432 159.008 192.696 ;
     RECT  154.469 197.136 159.008 197.16 ;
     RECT  156.269 199.968 159.008 199.992 ;
     RECT  156.269 201.36 159.008 201.624 ;
     RECT  158.461 229.728 159.008 229.896 ;
     RECT  153.904 250.08 159.008 250.104 ;
     RECT  153.904 319.536 159.008 319.56 ;
     RECT  159.008 2.148 159.112 369.372 ;
     RECT  159.112 2.418 159.304 369.102 ;
     RECT  159.304 229.728 159.401 229.896 ;
     RECT  159.304 319.536 159.401 319.56 ;
     RECT  159.304 181.776 159.443 181.8 ;
     RECT  159.304 189.36 159.443 191.256 ;
     RECT  159.443 190.32 159.481 191.256 ;
     RECT  159.304 192.432 160.013 192.456 ;
     RECT  159.304 156.72 160.163 174.984 ;
     RECT  159.481 190.464 160.657 191.256 ;
     RECT  160.657 189.84 160.693 191.256 ;
     RECT  160.693 189.84 160.741 191.544 ;
     RECT  159.304 179.376 161.269 179.4 ;
     RECT  160.163 156.768 161.633 174.984 ;
     RECT  160.741 190.704 161.957 191.544 ;
     RECT  161.957 191.52 161.993 191.544 ;
     RECT  161.633 156.768 162.349 174.888 ;
     RECT  159.401 229.728 162.457 229.752 ;
     RECT  162.349 156 162.467 174.888 ;
     RECT  162.457 229.728 162.497 229.896 ;
     RECT  162.467 156.72 162.569 157.896 ;
     RECT  160.693 182.304 162.709 182.328 ;
     RECT  159.304 197.136 162.755 197.16 ;
     RECT  161.269 179.328 162.817 179.4 ;
     RECT  162.709 182.304 162.899 182.952 ;
     RECT  162.817 179.328 162.901 179.544 ;
     RECT  162.569 156.768 163.609 157.896 ;
     RECT  162.467 159.12 163.609 174.888 ;
     RECT  162.901 179.328 164.077 179.4 ;
     RECT  163.393 155.568 164.408 155.592 ;
     RECT  163.609 156.768 164.408 174.888 ;
     RECT  164.077 179.088 164.408 179.4 ;
     RECT  162.899 182.304 164.408 182.568 ;
     RECT  159.304 199.968 164.408 199.992 ;
     RECT  159.304 201.36 164.408 201.624 ;
     RECT  162.497 229.872 164.408 229.896 ;
     RECT  159.304 250.08 164.408 250.104 ;
     RECT  164.408 2.148 164.512 369.372 ;
     RECT  164.512 2.418 164.704 369.102 ;
     RECT  164.704 229.728 164.801 229.896 ;
     RECT  164.704 182.304 165.587 182.424 ;
     RECT  165.587 182.4 165.593 182.424 ;
     RECT  164.704 156.528 166.057 174.888 ;
     RECT  166.057 155.568 166.129 174.888 ;
     RECT  166.057 365.952 166.165 365.976 ;
     RECT  166.124 364.56 166.211 364.584 ;
     RECT  166.165 365.952 166.277 366.216 ;
     RECT  166.129 155.568 166.595 174.936 ;
     RECT  166.381 365.232 166.637 365.256 ;
     RECT  166.561 287.808 166.645 287.832 ;
     RECT  166.595 157.344 166.669 174.936 ;
     RECT  166.237 322.608 166.739 322.632 ;
     RECT  166.165 361.92 166.748 361.944 ;
     RECT  166.669 157.344 166.753 175.032 ;
     RECT  166.748 361.104 166.835 361.944 ;
     RECT  166.835 361.92 166.993 361.944 ;
     RECT  166.595 155.568 167.033 156.312 ;
     RECT  164.801 229.728 167.317 229.752 ;
     RECT  167.276 189.936 167.363 189.96 ;
     RECT  166.837 176.064 167.413 176.088 ;
     RECT  164.704 179.088 167.459 179.352 ;
     RECT  167.413 176.064 167.465 176.568 ;
     RECT  167.465 176.16 167.5 176.568 ;
     RECT  167.5 176.16 167.509 176.184 ;
     RECT  166.597 305.52 167.612 305.544 ;
     RECT  167.612 305.424 167.681 305.544 ;
     RECT  164.704 250.08 167.699 250.104 ;
     RECT  167.681 305.424 167.699 305.448 ;
     RECT  164.704 199.968 167.785 199.992 ;
     RECT  166.993 361.92 167.843 362.52 ;
     RECT  167.785 199.584 167.933 199.992 ;
     RECT  167.033 156.288 168.109 156.312 ;
     RECT  167.569 365.808 168.181 365.832 ;
     RECT  167.797 367.104 168.181 367.128 ;
     RECT  167.843 361.92 168.185 361.944 ;
     RECT  168.181 365.808 168.221 367.128 ;
     RECT  167.605 364.752 168.227 364.776 ;
     RECT  168.221 366.288 168.293 367.128 ;
     RECT  168.293 367.104 168.473 367.128 ;
     RECT  166.753 157.344 168.761 174.888 ;
     RECT  168.685 370.512 168.785 370.536 ;
     RECT  168.109 156.192 168.865 156.312 ;
     RECT  168.785 370.512 168.869 371.4 ;
     RECT  168.869 370.512 168.947 370.536 ;
     RECT  167.461 154.896 169.045 154.92 ;
     RECT  168.865 156.192 169.045 156.504 ;
     RECT  168.937 369.312 169.093 369.336 ;
     RECT  169.045 154.896 169.808 156.504 ;
     RECT  168.761 157.92 169.808 174.84 ;
     RECT  167.459 179.328 169.808 179.352 ;
     RECT  168.865 189.264 169.808 189.864 ;
     RECT  167.933 199.968 169.808 199.992 ;
     RECT  164.704 201.36 169.808 201.624 ;
     RECT  167.317 229.728 169.808 229.944 ;
     RECT  168.709 261.984 169.808 262.008 ;
     RECT  169.093 368.784 169.808 369.336 ;
     RECT  169.808 2.148 169.912 369.372 ;
     RECT  169.912 2.418 170.104 369.102 ;
     RECT  170.104 229.728 170.531 230.184 ;
     RECT  170.531 229.728 170.777 229.944 ;
     RECT  170.104 154.896 170.921 174.84 ;
     RECT  170.921 154.896 171.529 156.936 ;
     RECT  170.921 158.64 171.961 172.2 ;
     RECT  170.921 173.232 171.961 174.84 ;
     RECT  171.961 158.64 172.069 174.84 ;
     RECT  171.529 154.752 172.285 156.936 ;
     RECT  172.069 158.016 172.285 174.84 ;
     RECT  172.285 154.752 172.649 174.84 ;
     RECT  172.649 174.576 172.681 174.84 ;
     RECT  172.649 154.752 172.685 173.592 ;
     RECT  172.681 174.576 173.513 174.888 ;
     RECT  172.685 154.752 174.013 173.496 ;
     RECT  173.513 174.576 174.013 174.84 ;
     RECT  170.104 251.376 174.409 251.4 ;
     RECT  174.013 154.752 175.208 174.84 ;
     RECT  170.104 179.328 175.208 179.352 ;
     RECT  170.104 199.968 175.208 201.624 ;
     RECT  174.409 251.376 175.208 251.496 ;
     RECT  170.104 261.984 175.208 262.008 ;
     RECT  175.208 2.148 175.312 369.372 ;
     RECT  175.312 2.418 175.504 369.102 ;
     RECT  175.504 251.376 175.601 251.496 ;
     RECT  175.504 154.752 176.893 174.792 ;
     RECT  176.893 154.752 177.011 175.032 ;
     RECT  175.504 179.328 178.405 179.352 ;
     RECT  175.601 251.376 178.405 251.4 ;
     RECT  178.405 179.328 178.445 179.448 ;
     RECT  178.405 251.376 178.445 251.496 ;
     RECT  177.011 154.752 179.917 174.648 ;
     RECT  177.397 176.112 179.917 176.136 ;
     RECT  179.917 154.752 180.608 176.136 ;
     RECT  178.445 179.424 180.608 179.448 ;
     RECT  175.504 199.968 180.608 201.624 ;
     RECT  178.445 251.472 180.608 251.496 ;
     RECT  175.504 261.984 180.608 262.008 ;
     RECT  180.608 2.148 180.712 369.372 ;
     RECT  180.712 2.418 180.904 369.102 ;
     RECT  180.904 251.376 181.001 251.496 ;
     RECT  180.904 154.752 181.361 176.232 ;
     RECT  180.904 199.968 182.341 201.624 ;
     RECT  182.341 199.872 182.387 201.624 ;
     RECT  181.001 251.376 182.401 251.4 ;
     RECT  182.401 251.376 182.441 251.592 ;
     RECT  181.361 154.752 182.657 175.032 ;
     RECT  181.361 176.112 183.301 176.232 ;
     RECT  180.904 179.424 183.347 179.448 ;
     RECT  182.657 154.752 183.377 174.984 ;
     RECT  183.377 154.752 183.557 174.648 ;
     RECT  182.441 251.568 183.949 251.592 ;
     RECT  183.301 176.112 184.273 176.424 ;
     RECT  183.949 251.472 184.277 251.592 ;
     RECT  184.273 176.112 184.597 176.52 ;
     RECT  183.557 154.752 184.661 174.312 ;
     RECT  184.597 175.344 184.661 176.52 ;
     RECT  184.661 154.752 186.008 176.52 ;
     RECT  183.205 187.824 186.008 187.848 ;
     RECT  182.387 199.872 186.008 199.992 ;
     RECT  182.387 201.024 186.008 201.624 ;
     RECT  184.277 251.472 186.008 251.496 ;
     RECT  180.904 261.984 186.008 262.008 ;
     RECT  186.008 2.148 186.112 369.372 ;
     RECT  186.112 2.418 186.304 369.102 ;
     RECT  186.304 154.752 188.665 172.344 ;
     RECT  186.304 173.376 188.665 176.52 ;
     RECT  186.304 187.968 190.393 187.992 ;
     RECT  190.393 187.824 190.433 187.992 ;
     RECT  188.665 154.752 191.408 176.52 ;
     RECT  190.433 187.824 191.408 187.848 ;
     RECT  186.304 199.872 191.408 199.992 ;
     RECT  186.304 201.024 191.408 201.624 ;
     RECT  186.304 251.472 191.408 251.496 ;
     RECT  186.304 261.984 191.408 262.008 ;
     RECT  191.408 2.148 191.512 369.372 ;
     RECT  191.512 2.418 191.704 369.102 ;
     RECT  191.704 154.752 192.125 176.52 ;
     RECT  191.704 201.024 192.707 201.624 ;
     RECT  191.704 182.592 192.725 182.616 ;
     RECT  192.125 173.376 192.803 176.52 ;
     RECT  192.725 182.4 192.809 182.616 ;
     RECT  191.704 187.824 193.436 187.848 ;
     RECT  193.436 187.824 193.523 188.088 ;
     RECT  193.523 187.824 193.781 187.848 ;
     RECT  192.125 154.752 194.209 172.344 ;
     RECT  192.803 173.376 194.209 174.312 ;
     RECT  195.001 187.536 195.085 187.56 ;
     RECT  194.209 154.752 196.621 174.312 ;
     RECT  196.621 154.752 196.808 174.36 ;
     RECT  192.803 175.44 196.808 176.52 ;
     RECT  192.809 182.592 196.808 182.616 ;
     RECT  191.704 199.872 196.808 199.992 ;
     RECT  192.707 201.36 196.808 201.624 ;
     RECT  193.477 217.2 196.808 217.224 ;
     RECT  191.704 251.472 196.808 251.496 ;
     RECT  191.704 261.984 196.808 262.008 ;
     RECT  196.808 2.148 196.912 369.372 ;
     RECT  196.912 2.418 197.104 369.102 ;
     RECT  197.104 154.752 197.813 174.36 ;
     RECT  197.813 154.752 198.961 174.312 ;
     RECT  197.104 175.44 198.961 176.52 ;
     RECT  198.961 154.752 200.339 176.52 ;
     RECT  200.339 154.752 200.621 172.344 ;
     RECT  200.621 154.752 201.233 170.76 ;
     RECT  201.233 154.752 202.208 170.376 ;
     RECT  200.621 171.888 202.208 172.344 ;
     RECT  200.339 173.376 202.208 176.52 ;
     RECT  200.293 180.96 202.208 180.984 ;
     RECT  197.104 182.592 202.208 182.616 ;
     RECT  197.104 199.872 202.208 199.992 ;
     RECT  197.104 201.36 202.208 201.624 ;
     RECT  197.104 217.2 202.208 217.224 ;
     RECT  197.104 251.472 202.208 251.496 ;
     RECT  197.104 261.984 202.208 262.008 ;
     RECT  202.208 2.148 202.312 369.372 ;
     RECT  202.312 2.418 202.504 369.102 ;
     RECT  202.504 154.752 202.601 169.992 ;
     RECT  202.504 201.36 204.653 201.624 ;
     RECT  202.504 199.872 205.013 199.992 ;
     RECT  202.504 217.2 207.457 217.224 ;
     RECT  202.601 154.752 207.608 168.168 ;
     RECT  202.601 169.152 207.608 169.992 ;
     RECT  202.504 171.888 207.608 172.344 ;
     RECT  202.504 173.376 207.608 176.52 ;
     RECT  202.504 180.96 207.608 180.984 ;
     RECT  202.504 182.592 207.608 182.616 ;
     RECT  205.549 198.816 207.608 198.84 ;
     RECT  205.013 199.872 207.608 199.944 ;
     RECT  204.653 201.6 207.608 201.624 ;
     RECT  207.457 217.2 207.608 217.464 ;
     RECT  202.504 251.472 207.608 251.496 ;
     RECT  202.504 261.984 207.608 262.008 ;
     RECT  207.608 2.148 207.712 369.372 ;
     RECT  207.712 2.418 207.904 369.102 ;
     RECT  207.904 261.648 208.433 262.008 ;
     RECT  207.904 251.376 208.787 251.496 ;
     RECT  208.433 261.648 208.793 261.672 ;
     RECT  208.787 251.376 208.883 251.4 ;
     RECT  207.904 199.872 209.693 199.944 ;
     RECT  209.693 199.872 210.125 199.896 ;
     RECT  207.904 154.752 213.008 168.168 ;
     RECT  207.904 169.152 213.008 169.992 ;
     RECT  207.904 171.888 213.008 172.344 ;
     RECT  207.904 173.376 213.008 176.52 ;
     RECT  207.904 180.96 213.008 180.984 ;
     RECT  207.904 182.592 213.008 182.616 ;
     RECT  207.904 198.816 213.008 198.84 ;
     RECT  211.201 199.872 213.008 199.896 ;
     RECT  207.904 201.6 213.008 201.624 ;
     RECT  207.904 217.44 213.008 217.464 ;
     RECT  207.904 239.04 213.008 239.064 ;
     RECT  213.008 2.148 213.112 369.372 ;
     RECT  213.112 2.418 213.304 369.102 ;
     RECT  213.304 154.752 218.408 168.168 ;
     RECT  213.304 169.152 218.408 169.992 ;
     RECT  213.304 171.888 218.408 172.344 ;
     RECT  213.304 173.376 218.408 176.52 ;
     RECT  213.304 180.96 218.408 180.984 ;
     RECT  213.304 182.592 218.408 182.616 ;
     RECT  213.304 198.816 218.408 198.84 ;
     RECT  213.304 199.872 218.408 199.896 ;
     RECT  213.304 201.6 218.408 201.624 ;
     RECT  213.304 217.44 218.408 217.464 ;
     RECT  213.304 239.04 218.408 239.064 ;
     RECT  218.408 2.148 218.512 369.372 ;
     RECT  218.512 2.418 218.704 369.102 ;
     RECT  218.704 239.04 220.061 239.064 ;
     RECT  222.109 238.848 222.193 238.872 ;
     RECT  218.704 154.752 223.808 168.168 ;
     RECT  218.704 169.152 223.808 169.992 ;
     RECT  218.704 171.888 223.808 172.344 ;
     RECT  218.704 173.376 223.808 176.52 ;
     RECT  218.704 180.96 223.808 180.984 ;
     RECT  218.704 182.592 223.808 182.616 ;
     RECT  218.704 198.816 223.808 198.84 ;
     RECT  218.704 199.872 223.808 199.896 ;
     RECT  218.704 201.6 223.808 201.624 ;
     RECT  222.109 202.896 223.808 202.92 ;
     RECT  218.704 217.44 223.808 217.464 ;
     RECT  223.808 2.148 223.912 369.372 ;
     RECT  223.912 2.418 224.104 369.102 ;
     RECT  224.104 202.896 228.985 202.92 ;
     RECT  224.104 154.752 229.208 168.168 ;
     RECT  224.104 169.152 229.208 169.992 ;
     RECT  224.104 171.888 229.208 172.344 ;
     RECT  224.104 173.376 229.208 176.52 ;
     RECT  224.104 180.96 229.208 180.984 ;
     RECT  224.104 182.592 229.208 182.616 ;
     RECT  228.985 183.696 229.208 183.72 ;
     RECT  224.104 198.816 229.208 198.84 ;
     RECT  224.104 199.872 229.208 199.896 ;
     RECT  224.104 201.6 229.208 201.624 ;
     RECT  228.985 202.896 229.208 203.688 ;
     RECT  224.104 217.44 229.208 217.464 ;
     RECT  229.208 2.148 229.312 369.372 ;
     RECT  229.312 2.418 229.504 369.102 ;
     RECT  229.504 182.592 233.449 182.616 ;
     RECT  229.504 183.696 233.449 183.72 ;
     RECT  229.504 154.752 234.608 168.168 ;
     RECT  229.504 169.152 234.608 169.992 ;
     RECT  229.504 171.888 234.608 172.344 ;
     RECT  229.504 173.376 234.608 176.52 ;
     RECT  229.504 180.96 234.608 180.984 ;
     RECT  233.449 182.592 234.608 183.816 ;
     RECT  233.881 191.808 234.608 191.832 ;
     RECT  229.504 198.816 234.608 198.84 ;
     RECT  229.504 199.872 234.608 199.896 ;
     RECT  229.504 202.896 234.608 203.688 ;
     RECT  229.504 217.44 234.608 217.464 ;
     RECT  234.608 2.148 234.712 369.372 ;
     RECT  234.712 2.418 234.904 369.102 ;
     RECT  234.904 154.752 240.008 168.168 ;
     RECT  234.904 169.152 240.008 169.992 ;
     RECT  234.904 171.888 240.008 172.344 ;
     RECT  234.904 173.376 240.008 176.52 ;
     RECT  234.904 180.96 240.008 180.984 ;
     RECT  234.904 182.592 240.008 183.816 ;
     RECT  234.904 190.704 240.008 191.928 ;
     RECT  234.904 198.816 240.008 198.84 ;
     RECT  234.904 199.872 240.008 199.896 ;
     RECT  234.904 202.896 240.008 203.688 ;
     RECT  234.904 217.2 240.008 217.224 ;
     RECT  240.008 2.148 240.112 369.372 ;
     RECT  240.112 2.418 240.304 369.102 ;
     RECT  240.304 180.96 241.157 181.032 ;
     RECT  240.304 154.752 242.485 168.168 ;
     RECT  242.485 154.32 243.493 168.168 ;
     RECT  243.493 154.272 245.408 168.168 ;
     RECT  240.304 169.152 245.408 169.992 ;
     RECT  240.304 171.888 245.408 172.344 ;
     RECT  240.304 173.376 245.408 176.52 ;
     RECT  241.157 181.008 245.408 181.032 ;
     RECT  240.304 182.592 245.408 183.816 ;
     RECT  240.304 190.704 245.408 191.928 ;
     RECT  240.304 198.816 245.408 198.84 ;
     RECT  240.304 199.872 245.408 199.896 ;
     RECT  240.304 202.896 245.408 203.688 ;
     RECT  240.304 217.2 245.408 217.224 ;
     RECT  245.408 2.148 245.512 369.372 ;
     RECT  245.512 2.418 245.704 369.102 ;
     RECT  245.704 154.272 246.269 168.168 ;
     RECT  245.704 181.008 248.819 181.032 ;
     RECT  248.965 193.824 249.049 193.848 ;
     RECT  245.704 190.704 250.453 191.928 ;
     RECT  246.269 154.32 250.808 168.168 ;
     RECT  245.704 169.152 250.808 169.992 ;
     RECT  245.704 171.888 250.808 172.344 ;
     RECT  245.704 173.376 250.808 176.52 ;
     RECT  245.704 182.592 250.808 183.816 ;
     RECT  248.773 187.728 250.808 187.752 ;
     RECT  250.453 190.416 250.808 191.928 ;
     RECT  250.441 193.824 250.808 193.848 ;
     RECT  245.704 198.816 250.808 198.84 ;
     RECT  245.704 199.872 250.808 199.896 ;
     RECT  245.704 202.896 250.808 203.688 ;
     RECT  245.704 217.2 250.808 217.224 ;
     RECT  250.808 2.148 250.912 369.372 ;
     RECT  250.912 2.418 251.104 369.102 ;
     RECT  251.104 169.152 251.201 169.992 ;
     RECT  251.104 154.32 256.208 168.168 ;
     RECT  251.201 169.152 256.208 169.896 ;
     RECT  251.104 171.888 256.208 172.344 ;
     RECT  251.104 173.376 256.208 176.52 ;
     RECT  251.104 182.832 256.208 183.816 ;
     RECT  251.104 187.728 256.208 187.752 ;
     RECT  251.104 190.416 256.208 191.928 ;
     RECT  251.104 198.816 256.208 198.84 ;
     RECT  251.104 199.872 256.208 199.896 ;
     RECT  251.104 202.896 256.208 203.688 ;
     RECT  251.104 217.2 256.208 217.224 ;
     RECT  256.208 2.148 256.312 369.372 ;
     RECT  256.312 2.418 256.504 369.102 ;
     RECT  256.504 154.32 261.608 168.168 ;
     RECT  256.504 169.152 261.608 169.896 ;
     RECT  256.504 171.888 261.608 172.344 ;
     RECT  256.504 173.376 261.608 176.52 ;
     RECT  256.504 182.832 261.608 183.816 ;
     RECT  256.504 187.728 261.608 187.752 ;
     RECT  256.504 190.416 261.608 191.928 ;
     RECT  256.504 198.816 261.608 198.84 ;
     RECT  256.504 199.872 261.608 199.896 ;
     RECT  256.504 202.896 261.608 203.688 ;
     RECT  256.504 217.2 261.608 217.224 ;
     RECT  261.608 2.148 261.712 369.372 ;
     RECT  261.712 2.418 261.904 369.102 ;
     RECT  261.904 217.2 264.851 217.224 ;
     RECT  264.805 205.296 265.093 205.32 ;
     RECT  265.093 205.2 265.097 205.32 ;
     RECT  265.097 205.2 265.177 205.224 ;
     RECT  261.904 154.32 267.008 168.168 ;
     RECT  261.904 169.152 267.008 169.896 ;
     RECT  261.904 171.888 267.008 172.344 ;
     RECT  261.904 173.376 267.008 176.52 ;
     RECT  261.904 182.832 267.008 183.816 ;
     RECT  261.904 187.728 267.008 187.752 ;
     RECT  261.904 190.416 267.008 191.928 ;
     RECT  261.904 198.816 267.008 198.84 ;
     RECT  261.904 199.872 267.008 199.896 ;
     RECT  261.904 202.896 267.008 203.688 ;
     RECT  266.317 205.008 267.008 205.032 ;
     RECT  267.008 2.148 267.112 369.372 ;
     RECT  267.112 2.418 267.304 369.102 ;
     RECT  267.304 154.32 272.408 168.168 ;
     RECT  267.304 169.152 272.408 169.896 ;
     RECT  267.304 171.888 272.408 172.344 ;
     RECT  267.304 173.376 272.408 176.52 ;
     RECT  267.304 182.832 272.408 183.816 ;
     RECT  267.304 187.728 272.408 187.752 ;
     RECT  267.304 190.416 272.408 191.928 ;
     RECT  267.304 198.816 272.408 198.84 ;
     RECT  267.304 199.872 272.408 199.896 ;
     RECT  267.304 202.896 272.408 203.688 ;
     RECT  267.304 205.008 272.408 205.032 ;
     RECT  272.408 2.148 272.512 369.372 ;
     RECT  272.512 2.418 272.704 369.102 ;
     RECT  272.704 154.32 277.808 168.168 ;
     RECT  272.704 169.152 277.808 169.896 ;
     RECT  272.704 171.888 277.808 172.344 ;
     RECT  272.704 173.376 277.808 176.52 ;
     RECT  272.704 182.832 277.808 183.816 ;
     RECT  272.704 187.728 277.808 187.752 ;
     RECT  272.704 190.416 277.808 191.928 ;
     RECT  272.704 198.816 277.808 198.84 ;
     RECT  272.704 199.872 277.808 199.896 ;
     RECT  272.704 202.896 277.808 203.688 ;
     RECT  272.704 205.008 277.808 205.032 ;
     RECT  277.808 2.148 277.912 369.372 ;
     RECT  277.912 2.418 278.104 369.102 ;
     RECT  278.104 154.32 283.208 168.168 ;
     RECT  278.104 169.152 283.208 169.896 ;
     RECT  278.104 171.888 283.208 172.344 ;
     RECT  278.104 173.376 283.208 176.52 ;
     RECT  278.104 182.832 283.208 183.816 ;
     RECT  278.104 187.728 283.208 187.752 ;
     RECT  278.104 190.416 283.208 191.928 ;
     RECT  278.104 198.816 283.208 198.84 ;
     RECT  278.104 199.872 283.208 199.896 ;
     RECT  278.104 202.896 283.208 203.688 ;
     RECT  278.104 205.008 283.208 205.032 ;
     RECT  283.208 2.148 283.312 369.372 ;
     RECT  283.312 2.418 283.504 369.102 ;
     RECT  283.504 154.32 288.608 168.168 ;
     RECT  283.504 169.152 288.608 169.896 ;
     RECT  283.504 171.888 288.608 172.344 ;
     RECT  283.504 173.376 288.608 176.52 ;
     RECT  283.504 182.832 288.608 183.816 ;
     RECT  283.504 187.728 288.608 187.752 ;
     RECT  283.504 190.416 288.608 191.928 ;
     RECT  283.504 198.816 288.608 198.84 ;
     RECT  283.504 199.872 288.608 199.896 ;
     RECT  283.504 202.896 288.608 203.688 ;
     RECT  283.504 205.008 288.608 205.032 ;
     RECT  288.608 2.148 288.712 369.372 ;
     RECT  288.712 2.418 288.904 369.102 ;
     RECT  288.904 154.32 294.008 168.168 ;
     RECT  288.904 169.152 294.008 169.896 ;
     RECT  288.904 171.888 294.008 172.344 ;
     RECT  288.904 173.376 294.008 176.52 ;
     RECT  288.904 182.832 294.008 183.816 ;
     RECT  288.904 187.728 294.008 187.752 ;
     RECT  288.904 190.416 294.008 191.928 ;
     RECT  288.904 198.816 294.008 198.84 ;
     RECT  288.904 199.872 294.008 199.896 ;
     RECT  288.904 202.896 294.008 203.688 ;
     RECT  288.904 205.008 294.008 205.032 ;
     RECT  294.008 2.148 294.112 369.372 ;
     RECT  294.112 2.418 294.304 369.102 ;
     RECT  294.304 154.32 299.408 168.168 ;
     RECT  294.304 169.152 299.408 169.896 ;
     RECT  294.304 171.888 299.408 172.344 ;
     RECT  294.304 173.376 299.408 176.52 ;
     RECT  294.304 182.832 299.408 183.816 ;
     RECT  294.304 187.728 299.408 187.752 ;
     RECT  294.304 190.416 299.408 191.928 ;
     RECT  294.304 198.816 299.408 198.84 ;
     RECT  294.304 199.872 299.408 199.896 ;
     RECT  294.304 202.896 299.408 203.688 ;
     RECT  294.304 205.008 299.408 205.032 ;
     RECT  299.408 2.148 299.512 369.372 ;
     RECT  299.512 2.418 299.704 369.102 ;
     RECT  299.704 205.008 303.107 205.032 ;
     RECT  299.704 202.896 304.621 203.688 ;
     RECT  299.704 154.32 304.808 168.168 ;
     RECT  299.704 169.152 304.808 169.896 ;
     RECT  299.704 171.888 304.808 172.344 ;
     RECT  299.704 173.376 304.808 176.52 ;
     RECT  299.704 182.832 304.808 183.816 ;
     RECT  299.704 187.728 304.808 187.752 ;
     RECT  299.704 190.416 304.808 191.928 ;
     RECT  299.704 198.816 304.808 198.84 ;
     RECT  299.704 199.872 304.808 199.896 ;
     RECT  304.621 202.848 304.808 203.688 ;
     RECT  304.808 2.148 304.912 369.372 ;
     RECT  304.912 2.418 305.104 369.102 ;
     RECT  305.104 190.416 306.097 191.928 ;
     RECT  305.104 198.816 307.501 198.84 ;
     RECT  305.104 199.872 307.501 199.896 ;
     RECT  307.501 198.816 307.897 199.896 ;
     RECT  307.861 193.872 307.933 193.896 ;
     RECT  307.933 193.872 307.957 194.088 ;
     RECT  307.753 195.648 307.969 195.672 ;
     RECT  307.933 196.656 307.969 196.68 ;
     RECT  307.897 198.576 308.005 199.896 ;
     RECT  306.097 190.416 308.041 192.024 ;
     RECT  307.957 193.68 308.041 194.088 ;
     RECT  308.005 198.192 308.149 199.896 ;
     RECT  308.041 190.416 308.153 194.088 ;
     RECT  305.104 202.848 308.195 203.688 ;
     RECT  307.969 195.6 308.257 196.68 ;
     RECT  308.149 198 308.257 199.992 ;
     RECT  308.257 209.184 308.293 209.208 ;
     RECT  308.293 209.184 308.341 209.544 ;
     RECT  308.257 195.6 308.401 199.992 ;
     RECT  308.401 195.216 308.509 199.992 ;
     RECT  308.509 195.216 308.689 200.184 ;
     RECT  308.689 194.496 308.869 200.184 ;
     RECT  308.195 202.896 308.869 203.688 ;
     RECT  308.869 194.496 309.085 200.328 ;
     RECT  309.085 194.496 309.164 200.616 ;
     RECT  308.473 189.216 309.233 189.24 ;
     RECT  308.869 202.896 309.301 203.976 ;
     RECT  308.153 190.416 309.553 193.512 ;
     RECT  309.164 194.496 309.553 201.192 ;
     RECT  309.553 190.416 309.625 201.192 ;
     RECT  309.301 202.896 309.829 204.312 ;
     RECT  309.625 190.416 309.985 201.816 ;
     RECT  305.104 154.32 310.208 168.168 ;
     RECT  305.104 169.152 310.208 169.896 ;
     RECT  305.104 171.888 310.208 172.344 ;
     RECT  305.104 173.376 310.208 176.52 ;
     RECT  305.104 182.832 310.208 183.816 ;
     RECT  305.104 187.728 310.208 187.752 ;
     RECT  309.985 190.272 310.208 201.816 ;
     RECT  309.829 202.896 310.208 205.032 ;
     RECT  308.341 209.52 310.208 209.544 ;
     RECT  310.208 2.148 310.312 369.372 ;
     RECT  310.312 2.418 310.504 369.102 ;
     RECT  310.504 190.272 310.565 203.736 ;
     RECT  310.565 201.792 310.781 203.736 ;
     RECT  310.781 201.84 311.105 203.736 ;
     RECT  310.504 187.728 311.285 189.096 ;
     RECT  310.565 190.272 311.609 200.712 ;
     RECT  311.609 197.76 311.753 200.712 ;
     RECT  311.285 187.728 311.825 188.808 ;
     RECT  311.753 197.904 312.001 200.712 ;
     RECT  311.105 201.84 312.001 203.688 ;
     RECT  311.609 190.272 312.005 196.728 ;
     RECT  312.001 197.904 312.005 203.688 ;
     RECT  311.825 187.728 312.221 188.616 ;
     RECT  312.005 190.272 312.365 193.224 ;
     RECT  312.005 197.904 312.865 201.336 ;
     RECT  312.865 197.76 313.189 201.336 ;
     RECT  312.005 202.56 313.189 203.688 ;
     RECT  313.189 197.76 313.333 203.688 ;
     RECT  310.504 205.008 313.333 205.032 ;
     RECT  312.365 190.368 313.369 193.224 ;
     RECT  312.005 194.304 313.369 196.728 ;
     RECT  313.369 190.368 313.549 196.728 ;
     RECT  313.333 197.76 313.549 205.032 ;
     RECT  312.221 187.728 313.621 187.752 ;
     RECT  313.621 187.344 313.657 188.712 ;
     RECT  313.657 186.912 313.667 188.712 ;
     RECT  313.667 186.912 313.708 187.368 ;
     RECT  313.667 188.688 313.733 188.712 ;
     RECT  313.549 190.368 313.859 205.032 ;
     RECT  313.873 189.216 313.909 189.24 ;
     RECT  313.859 190.368 313.909 197.256 ;
     RECT  313.909 189.216 313.985 197.256 ;
     RECT  313.985 189.216 314.057 197.208 ;
     RECT  314.057 189.216 314.093 195.144 ;
     RECT  314.057 196.128 314.165 197.208 ;
     RECT  313.859 198.24 314.165 205.032 ;
     RECT  314.093 193.152 314.237 194.52 ;
     RECT  314.165 196.128 314.273 196.68 ;
     RECT  314.165 198.816 314.305 205.032 ;
     RECT  314.237 193.2 314.483 194.52 ;
     RECT  314.483 193.2 314.524 193.704 ;
     RECT  314.305 198.816 315.205 205.176 ;
     RECT  314.093 189.696 315.313 192.072 ;
     RECT  315.313 189.072 315.493 192.072 ;
     RECT  310.504 154.32 315.608 168.168 ;
     RECT  310.504 169.152 315.608 169.896 ;
     RECT  310.504 171.888 315.608 172.344 ;
     RECT  310.504 173.376 315.608 176.52 ;
     RECT  310.504 182.832 315.608 183.816 ;
     RECT  313.708 186.912 315.608 186.936 ;
     RECT  315.493 189.072 315.608 192.168 ;
     RECT  314.524 193.2 315.608 193.224 ;
     RECT  314.273 196.128 315.608 196.152 ;
     RECT  315.205 198.288 315.608 205.176 ;
     RECT  314.053 206.16 315.608 206.184 ;
     RECT  315.608 2.148 315.712 369.372 ;
     RECT  315.712 2.418 315.904 369.102 ;
     RECT  315.904 189.072 316.073 193.128 ;
     RECT  316.073 189.072 316.361 192.12 ;
     RECT  315.904 196.608 316.892 196.632 ;
     RECT  316.892 196.512 316.979 196.632 ;
     RECT  315.904 198.384 317.149 204.6 ;
     RECT  315.904 186.912 317.153 187.32 ;
     RECT  315.904 206.928 317.185 206.952 ;
     RECT  316.979 196.608 317.189 196.632 ;
     RECT  315.904 195.456 317.225 195.48 ;
     RECT  317.185 206.112 317.293 206.952 ;
     RECT  317.149 197.76 317.549 204.6 ;
     RECT  317.549 197.76 317.555 204.072 ;
     RECT  317.293 206.064 317.657 206.952 ;
     RECT  317.555 198.768 317.693 204.072 ;
     RECT  316.361 189.072 317.761 191.928 ;
     RECT  317.761 189.072 317.833 192.12 ;
     RECT  316.073 193.104 317.833 193.128 ;
     RECT  317.437 187.92 318.125 187.944 ;
     RECT  317.555 197.76 318.125 197.784 ;
     RECT  317.657 206.88 318.373 206.952 ;
     RECT  315.904 182.832 318.428 183.816 ;
     RECT  316.933 185.28 318.428 185.304 ;
     RECT  318.428 182.832 318.445 185.304 ;
     RECT  317.153 186.912 318.445 186.936 ;
     RECT  318.445 182.832 318.515 186.936 ;
     RECT  317.693 198.816 318.557 204.072 ;
     RECT  317.833 189.072 318.565 193.128 ;
     RECT  318.373 206.88 318.611 207.528 ;
     RECT  318.565 188.784 318.625 193.128 ;
     RECT  317.905 205.68 318.661 205.704 ;
     RECT  318.625 188.784 318.805 193.8 ;
     RECT  318.481 195.6 318.805 195.624 ;
     RECT  318.515 185.28 318.809 186.936 ;
     RECT  318.661 205.68 318.841 205.8 ;
     RECT  318.611 206.88 318.841 207.48 ;
     RECT  318.557 200.352 318.881 204.072 ;
     RECT  318.841 205.152 318.925 207.48 ;
     RECT  318.809 186.144 319.093 186.936 ;
     RECT  318.557 198.816 319.097 199.32 ;
     RECT  319.093 186.144 319.133 187.512 ;
     RECT  319.097 198.816 319.165 198.936 ;
     RECT  318.805 188.784 319.187 195.624 ;
     RECT  319.165 198.384 319.205 198.936 ;
     RECT  318.925 206.88 319.313 207.48 ;
     RECT  319.313 207.456 319.565 207.48 ;
     RECT  319.187 192.912 319.573 195.624 ;
     RECT  318.841 196.944 319.573 196.968 ;
     RECT  318.881 200.352 319.669 203.928 ;
     RECT  318.515 182.832 319.777 183.816 ;
     RECT  318.925 205.152 319.777 205.8 ;
     RECT  319.133 186.912 319.817 187.512 ;
     RECT  319.187 188.784 319.817 191.928 ;
     RECT  319.573 192.912 319.961 196.968 ;
     RECT  319.205 198.384 320.033 198.84 ;
     RECT  319.817 189.888 320.281 191.928 ;
     RECT  319.961 192.912 320.281 194.52 ;
     RECT  319.669 200.208 320.281 203.928 ;
     RECT  319.777 205.008 320.281 205.8 ;
     RECT  320.281 200.208 320.425 205.8 ;
     RECT  319.817 186.912 320.605 187.464 ;
     RECT  319.961 195.552 320.605 196.968 ;
     RECT  320.033 198.816 320.605 198.84 ;
     RECT  320.605 186.384 320.857 187.464 ;
     RECT  319.817 188.784 320.857 188.904 ;
     RECT  315.904 154.32 321.008 168.168 ;
     RECT  315.904 169.152 321.008 169.896 ;
     RECT  315.904 171.888 321.008 172.344 ;
     RECT  315.904 173.376 321.008 176.52 ;
     RECT  319.777 182.832 321.008 184.68 ;
     RECT  320.857 186.384 321.008 188.904 ;
     RECT  320.281 189.888 321.008 194.52 ;
     RECT  320.605 195.552 321.008 197.208 ;
     RECT  320.605 198.816 321.008 198.936 ;
     RECT  320.425 200.112 321.008 205.896 ;
     RECT  320.461 206.88 321.008 206.904 ;
     RECT  321.008 2.148 321.112 369.372 ;
     RECT  321.112 2.418 321.304 369.102 ;
     RECT  321.304 194.928 321.365 198.936 ;
     RECT  321.304 200.496 321.401 206.904 ;
     RECT  321.401 200.496 321.437 203.736 ;
     RECT  321.365 196.464 321.443 198.936 ;
     RECT  321.443 196.464 321.445 196.632 ;
     RECT  321.401 205.008 321.581 206.904 ;
     RECT  321.445 196.464 321.653 196.488 ;
     RECT  321.581 205.008 321.689 205.944 ;
     RECT  321.443 198.096 321.869 198.936 ;
     RECT  321.304 182.736 322.193 193.8 ;
     RECT  321.689 205.152 322.657 205.944 ;
     RECT  321.869 198.096 323.053 198.408 ;
     RECT  322.657 204.816 323.117 205.944 ;
     RECT  323.117 204.816 323.125 206.376 ;
     RECT  321.437 200.496 323.161 203.688 ;
     RECT  322.193 182.736 323.201 192.6 ;
     RECT  321.365 194.928 323.237 194.952 ;
     RECT  323.053 198.096 323.267 198.936 ;
     RECT  323.201 182.736 323.273 186.984 ;
     RECT  323.161 200.496 323.341 203.832 ;
     RECT  323.125 204.816 323.341 206.664 ;
     RECT  323.267 198.096 323.381 198.12 ;
     RECT  323.341 200.496 323.489 206.664 ;
     RECT  322.193 193.776 323.525 193.8 ;
     RECT  323.201 188.256 323.561 192.6 ;
     RECT  323.489 200.496 323.561 201.48 ;
     RECT  323.489 202.464 323.597 206.664 ;
     RECT  323.597 206.64 323.737 206.664 ;
     RECT  323.561 188.256 323.849 192.456 ;
     RECT  323.273 185.76 323.885 186.984 ;
     RECT  323.273 182.736 324.317 184.68 ;
     RECT  323.561 201.456 324.497 201.48 ;
     RECT  323.737 206.64 324.601 206.904 ;
     RECT  321.304 171.888 324.889 172.344 ;
     RECT  321.304 173.376 324.889 176.52 ;
     RECT  324.317 182.736 324.893 184.2 ;
     RECT  324.601 206.592 324.893 206.904 ;
     RECT  323.849 188.256 324.929 191.928 ;
     RECT  323.885 186.144 325.001 186.984 ;
     RECT  325.001 186.96 325.073 186.984 ;
     RECT  324.929 188.64 325.073 191.928 ;
     RECT  324.493 199.488 325.073 199.512 ;
     RECT  324.893 206.592 325.217 206.616 ;
     RECT  323.597 202.464 325.429 205.416 ;
     RECT  325.429 202.128 325.501 205.416 ;
     RECT  325.073 189.312 325.613 191.928 ;
     RECT  325.501 201.888 325.649 205.416 ;
     RECT  325.613 189.312 326.545 189.72 ;
     RECT  326.545 189.264 326.581 189.72 ;
     RECT  325.613 190.704 326.581 191.928 ;
     RECT  325.649 202.128 326.617 205.416 ;
     RECT  324.893 182.736 326.941 183.816 ;
     RECT  326.941 182.736 327.085 184.392 ;
     RECT  326.617 185.712 327.085 185.736 ;
     RECT  326.581 189.264 327.085 191.928 ;
     RECT  326.617 202.128 327.085 205.8 ;
     RECT  327.085 189.168 327.121 191.928 ;
     RECT  327.121 188.976 327.157 191.928 ;
     RECT  327.085 202.128 327.157 205.992 ;
     RECT  327.157 202.032 327.193 205.992 ;
     RECT  324.889 171.888 327.697 176.52 ;
     RECT  327.193 201.936 327.697 205.992 ;
     RECT  321.304 154.32 327.733 168.168 ;
     RECT  321.304 169.152 327.733 169.896 ;
     RECT  327.697 170.928 327.733 176.52 ;
     RECT  327.697 201.936 327.733 206.088 ;
     RECT  327.157 188.88 327.88 191.928 ;
     RECT  327.88 188.88 328.241 191.976 ;
     RECT  327.733 154.32 328.284 176.52 ;
     RECT  327.085 182.736 328.284 185.736 ;
     RECT  328.241 188.88 328.284 191.88 ;
     RECT  327.733 201.936 328.284 206.28 ;
    LAYER M5 ;
     RECT  2.4 2.137 2.52 2.151 ;
     RECT  7.8 2.137 7.92 2.151 ;
     RECT  13.2 2.137 13.32 2.151 ;
     RECT  18.6 2.137 18.72 2.151 ;
     RECT  24 2.137 24.12 2.151 ;
     RECT  29.4 2.137 29.52 2.151 ;
     RECT  34.8 2.137 34.92 2.151 ;
     RECT  40.2 2.137 40.32 2.151 ;
     RECT  45.6 2.137 45.72 2.151 ;
     RECT  51 2.137 51.12 2.151 ;
     RECT  56.4 2.137 56.52 2.151 ;
     RECT  61.8 2.137 61.92 2.151 ;
     RECT  67.2 2.137 67.32 2.151 ;
     RECT  72.6 2.137 72.72 2.151 ;
     RECT  78 2.137 78.12 2.151 ;
     RECT  83.4 2.137 83.52 2.151 ;
     RECT  88.8 2.137 88.92 2.151 ;
     RECT  94.2 2.137 94.32 2.151 ;
     RECT  99.6 2.137 99.72 2.151 ;
     RECT  105 2.137 105.12 2.151 ;
     RECT  110.4 2.137 110.52 2.151 ;
     RECT  115.8 2.137 115.92 2.151 ;
     RECT  121.2 2.137 121.32 2.151 ;
     RECT  126.6 2.137 126.72 2.151 ;
     RECT  132 2.137 132.12 2.151 ;
     RECT  137.4 2.137 137.52 2.151 ;
     RECT  142.8 2.137 142.92 2.151 ;
     RECT  148.2 2.137 148.32 2.151 ;
     RECT  153.6 2.137 153.72 2.151 ;
     RECT  159 2.137 159.12 2.151 ;
     RECT  164.4 2.137 164.52 2.151 ;
     RECT  169.8 2.137 169.92 2.151 ;
     RECT  175.2 2.137 175.32 2.151 ;
     RECT  180.6 2.137 180.72 2.151 ;
     RECT  186 2.137 186.12 2.151 ;
     RECT  191.4 2.137 191.52 2.151 ;
     RECT  196.8 2.137 196.92 2.151 ;
     RECT  202.2 2.137 202.32 2.151 ;
     RECT  207.6 2.137 207.72 2.151 ;
     RECT  213 2.137 213.12 2.151 ;
     RECT  218.4 2.137 218.52 2.151 ;
     RECT  223.8 2.137 223.92 2.151 ;
     RECT  229.2 2.137 229.32 2.151 ;
     RECT  234.6 2.137 234.72 2.151 ;
     RECT  240 2.137 240.12 2.151 ;
     RECT  245.4 2.137 245.52 2.151 ;
     RECT  250.8 2.137 250.92 2.151 ;
     RECT  256.2 2.137 256.32 2.151 ;
     RECT  261.6 2.137 261.72 2.151 ;
     RECT  267 2.137 267.12 2.151 ;
     RECT  272.4 2.137 272.52 2.151 ;
     RECT  277.8 2.137 277.92 2.151 ;
     RECT  283.2 2.137 283.32 2.151 ;
     RECT  288.6 2.137 288.72 2.151 ;
     RECT  294 2.137 294.12 2.151 ;
     RECT  299.4 2.137 299.52 2.151 ;
     RECT  304.8 2.137 304.92 2.151 ;
     RECT  310.2 2.137 310.32 2.151 ;
     RECT  315.6 2.137 315.72 2.151 ;
     RECT  321 2.137 321.12 2.151 ;
     RECT  137.4 2.151 137.712 154.405 ;
     RECT  136.656 154.405 137.712 155.075 ;
     RECT  0.192 155.413 0.216 155.651 ;
     RECT  175.2 2.151 175.512 155.845 ;
     RECT  137.4 155.075 137.712 155.893 ;
     RECT  174.864 155.845 175.512 156.419 ;
     RECT  159 2.151 159.312 156.709 ;
     RECT  186 2.151 186.312 156.709 ;
     RECT  139.92 156.709 139.944 156.757 ;
     RECT  159 156.709 160.152 156.805 ;
     RECT  137.4 155.893 138.312 156.995 ;
     RECT  139.92 156.757 140.808 156.995 ;
     RECT  140.784 156.995 140.808 156.997 ;
     RECT  180.6 2.151 180.912 157.237 ;
     RECT  177.216 156.133 177.24 157.283 ;
     RECT  137.4 156.995 137.712 157.285 ;
     RECT  175.056 156.419 175.512 157.475 ;
     RECT  185.712 156.709 186.312 157.523 ;
     RECT  180.6 157.237 181.272 157.907 ;
     RECT  328.128 157.333 328.152 157.907 ;
     RECT  180.6 157.907 180.912 158.005 ;
     RECT  140.784 156.997 141.48 158.099 ;
     RECT  136.608 157.285 137.712 158.435 ;
     RECT  137.4 158.435 137.712 158.533 ;
     RECT  137.4 158.533 138.504 158.867 ;
     RECT  184.704 158.773 184.728 158.963 ;
     RECT  158.544 156.805 160.152 159.059 ;
     RECT  194.4 158.437 194.424 159.059 ;
     RECT  196.8 2.151 197.112 159.061 ;
     RECT  166.56 156.085 166.584 159.109 ;
     RECT  166.464 159.109 166.584 159.155 ;
     RECT  164.4 2.151 164.712 159.157 ;
     RECT  166.464 159.155 166.488 159.157 ;
     RECT  144.768 159.205 144.792 159.347 ;
     RECT  196.272 159.061 197.112 159.349 ;
     RECT  167.76 159.013 167.784 159.445 ;
     RECT  167.76 159.445 168.312 159.587 ;
     RECT  159 159.059 160.152 159.635 ;
     RECT  164.304 159.157 164.712 159.635 ;
     RECT  165.936 159.157 166.488 159.635 ;
     RECT  183.36 159.013 183.384 159.635 ;
     RECT  189.84 158.821 189.864 159.635 ;
     RECT  153.6 2.151 153.912 159.829 ;
     RECT  167.76 159.587 167.784 159.875 ;
     RECT  165.936 159.635 165.96 159.923 ;
     RECT  153.312 159.829 153.912 159.971 ;
     RECT  162.432 155.989 162.456 159.971 ;
     RECT  141.456 158.099 141.48 160.117 ;
     RECT  141.456 160.117 141.672 160.693 ;
     RECT  164.4 159.635 164.712 160.741 ;
     RECT  163.968 160.741 164.712 160.883 ;
     RECT  155.808 157.045 155.832 160.933 ;
     RECT  140.736 160.693 141.672 160.979 ;
     RECT  169.8 2.151 170.112 160.981 ;
     RECT  171.36 160.693 171.384 160.981 ;
     RECT  178.416 160.741 178.44 161.075 ;
     RECT  169.8 160.981 171.384 161.171 ;
     RECT  172.416 161.077 172.44 161.267 ;
     RECT  157.344 160.981 157.368 161.269 ;
     RECT  139.056 160.117 139.08 161.363 ;
     RECT  140.736 160.979 140.76 161.363 ;
     RECT  171.36 161.171 171.384 161.461 ;
     RECT  137.4 158.867 137.712 161.557 ;
     RECT  136.032 161.365 136.056 161.603 ;
     RECT  155.52 160.933 155.832 161.603 ;
     RECT  171.36 161.461 171.48 161.651 ;
     RECT  148.2 2.151 148.512 161.701 ;
     RECT  199.776 161.221 199.8 161.749 ;
     RECT  180.096 158.005 180.912 161.797 ;
     RECT  157.344 161.269 157.608 161.843 ;
     RECT  175.2 157.475 175.512 161.845 ;
     RECT  172.944 161.701 172.968 161.891 ;
     RECT  186 157.523 186.312 161.893 ;
     RECT  157.584 161.843 157.608 162.131 ;
     RECT  153.6 159.971 153.912 162.181 ;
     RECT  145.632 160.693 145.656 162.323 ;
     RECT  153.6 162.181 154.488 162.323 ;
     RECT  180.096 161.797 181.08 162.371 ;
     RECT  171.216 162.133 171.24 162.419 ;
     RECT  175.2 161.845 175.608 162.467 ;
     RECT  137.4 161.557 138.504 162.515 ;
     RECT  183.504 161.749 183.528 162.515 ;
     RECT  153.6 162.323 154.008 162.565 ;
     RECT  128.928 161.797 128.952 162.659 ;
     RECT  199.536 161.749 199.8 162.707 ;
     RECT  152.736 162.565 154.008 162.851 ;
     RECT  145.68 162.373 145.704 162.853 ;
     RECT  150.192 161.509 150.216 162.853 ;
     RECT  151.488 159.541 151.512 162.853 ;
     RECT  160.512 162.709 160.536 162.901 ;
     RECT  137.4 162.515 138.36 162.995 ;
     RECT  145.68 162.853 146.52 162.995 ;
     RECT  191.4 2.151 191.712 162.997 ;
     RECT  150.096 162.853 150.216 163.043 ;
     RECT  151.488 162.853 151.56 163.043 ;
     RECT  160.512 162.901 160.776 163.043 ;
     RECT  167.568 162.997 167.592 163.093 ;
     RECT  145.68 162.995 146.472 163.187 ;
     RECT  196.272 159.349 198.024 163.285 ;
     RECT  141.024 163.189 141.048 163.379 ;
     RECT  167.136 163.093 167.592 163.427 ;
     RECT  180.6 162.371 181.08 163.427 ;
     RECT  169.8 161.171 170.112 163.429 ;
     RECT  153.6 162.851 154.008 163.475 ;
     RECT  130.464 163.285 130.488 163.525 ;
     RECT  142.8 2.151 143.112 163.525 ;
     RECT  147.552 161.701 148.512 163.525 ;
     RECT  175.2 162.467 175.512 163.525 ;
     RECT  179.376 163.285 179.4 163.573 ;
     RECT  147.552 163.525 148.872 163.619 ;
     RECT  185.28 161.893 186.312 163.667 ;
     RECT  142.608 163.525 143.112 163.717 ;
     RECT  160.512 163.043 160.536 163.811 ;
     RECT  169.248 163.429 170.112 163.861 ;
     RECT  142.032 163.717 143.112 163.955 ;
     RECT  155.808 161.603 155.832 163.955 ;
     RECT  169.2 163.861 170.112 163.957 ;
     RECT  190.8 162.997 191.712 164.147 ;
     RECT  192.96 160.693 192.984 164.195 ;
     RECT  199.68 162.707 199.8 164.195 ;
     RECT  148.2 163.619 148.872 164.483 ;
     RECT  167.568 163.427 167.592 164.483 ;
     RECT  175.2 163.525 176.232 164.581 ;
     RECT  145.68 163.187 145.704 164.725 ;
     RECT  196.032 163.285 198.024 164.771 ;
     RECT  144.48 164.725 145.704 164.867 ;
     RECT  153.6 163.475 153.912 164.869 ;
     RECT  168.912 163.957 170.112 164.869 ;
     RECT  175.2 164.581 176.712 164.869 ;
     RECT  153.6 164.869 154.008 164.917 ;
     RECT  129.984 163.525 130.488 165.013 ;
     RECT  129.984 165.013 130.536 165.059 ;
     RECT  179.04 163.573 179.4 165.061 ;
     RECT  0.192 164.917 0.216 165.107 ;
     RECT  183.744 163.141 183.768 165.109 ;
     RECT  168.288 164.869 170.112 165.203 ;
     RECT  196.272 164.771 198.024 165.203 ;
     RECT  137.4 162.995 137.712 165.253 ;
     RECT  142.512 163.955 143.112 165.253 ;
     RECT  148.2 164.483 148.824 165.347 ;
     RECT  163.392 161.509 163.416 165.395 ;
     RECT  130.464 165.059 130.536 165.491 ;
     RECT  191.4 164.147 191.712 165.829 ;
     RECT  195.024 165.013 195.048 165.829 ;
     RECT  238.272 165.637 238.296 165.875 ;
     RECT  153.024 164.917 154.008 166.067 ;
     RECT  174.096 159.253 174.12 166.165 ;
     RECT  173.616 166.165 174.12 166.307 ;
     RECT  159 159.635 159.312 166.357 ;
     RECT  144.48 164.867 144.504 166.405 ;
     RECT  145.68 164.867 145.704 166.405 ;
     RECT  168.912 165.203 170.112 166.405 ;
     RECT  191.4 165.829 192.504 166.405 ;
     RECT  190.608 166.405 192.504 166.499 ;
     RECT  199.68 164.195 199.704 166.643 ;
     RECT  183.312 165.109 183.768 166.645 ;
     RECT  183.216 166.645 183.768 166.691 ;
     RECT  190.608 166.499 191.712 166.883 ;
     RECT  160.752 166.549 160.776 167.027 ;
     RECT  144.48 166.405 145.704 167.075 ;
     RECT  175.2 164.869 176.808 167.123 ;
     RECT  194.448 165.829 195.048 167.219 ;
     RECT  168.912 166.405 170.328 167.221 ;
     RECT  196.272 165.203 197.112 167.317 ;
     RECT  168.72 167.221 170.76 167.413 ;
     RECT  168.432 167.413 170.76 167.555 ;
     RECT  168.72 167.555 170.76 167.603 ;
     RECT  175.2 167.123 176.712 167.603 ;
     RECT  180.6 163.427 180.912 167.605 ;
     RECT  189.024 167.557 189.048 167.699 ;
     RECT  174.096 166.307 174.12 167.747 ;
     RECT  180.384 167.605 180.912 167.843 ;
     RECT  159 166.357 159.432 167.845 ;
     RECT  178.992 165.061 179.4 167.893 ;
     RECT  153.024 166.067 153.912 167.989 ;
     RECT  152.832 167.989 153.912 168.131 ;
     RECT  150.192 163.043 150.216 168.229 ;
     RECT  151.488 163.043 151.512 168.229 ;
     RECT  150.192 168.229 151.512 168.275 ;
     RECT  178.032 167.893 179.4 168.515 ;
     RECT  158.064 167.845 159.432 168.611 ;
     RECT  178.032 168.515 178.056 168.611 ;
     RECT  196.272 167.317 197.592 168.755 ;
     RECT  176.976 168.085 177 168.805 ;
     RECT  159 168.611 159.432 168.851 ;
     RECT  137.4 165.253 138.12 168.997 ;
     RECT  137.4 168.997 138.552 169.139 ;
     RECT  148.2 165.347 148.512 169.189 ;
     RECT  130.512 165.491 130.536 169.331 ;
     RECT  150.192 168.275 151.368 169.379 ;
     RECT  196.8 168.755 197.592 169.381 ;
     RECT  137.4 169.139 138.504 169.475 ;
     RECT  183.216 166.691 183.336 169.477 ;
     RECT  191.4 166.883 191.712 169.477 ;
     RECT  0.144 169.381 0.168 169.571 ;
     RECT  137.4 169.475 138.12 169.619 ;
     RECT  196.8 169.381 198.024 169.715 ;
     RECT  179.04 168.515 179.4 169.717 ;
     RECT  180.6 167.843 180.912 169.717 ;
     RECT  144.48 167.075 144.936 169.813 ;
     RECT  130.416 169.477 130.44 169.859 ;
     RECT  179.04 169.717 180.912 169.859 ;
     RECT  142.08 165.253 143.112 169.861 ;
     RECT  153.024 168.131 153.912 169.907 ;
     RECT  179.04 169.859 179.4 169.907 ;
     RECT  144.48 169.813 145.704 169.909 ;
     RECT  195.024 167.219 195.048 169.909 ;
     RECT  137.4 169.619 137.832 169.955 ;
     RECT  144.48 169.909 146.328 169.955 ;
     RECT  142.08 169.861 143.208 170.003 ;
     RECT  144.48 169.955 144.936 170.005 ;
     RECT  146.208 169.955 146.328 170.005 ;
     RECT  176.736 168.805 177 170.051 ;
     RECT  132 2.151 132.312 170.053 ;
     RECT  140.784 169.861 140.808 170.099 ;
     RECT  168.72 167.603 170.232 170.099 ;
     RECT  135.744 169.957 135.768 170.147 ;
     RECT  175.2 167.603 175.608 170.149 ;
     RECT  144.24 170.005 144.936 170.195 ;
     RECT  162.384 170.197 162.408 170.339 ;
     RECT  131.856 170.053 132.312 170.389 ;
     RECT  164.4 160.883 164.712 170.389 ;
     RECT  146.208 170.005 146.52 170.435 ;
     RECT  183.12 169.477 183.336 170.435 ;
     RECT  153.6 169.907 153.912 170.437 ;
     RECT  177.984 169.909 178.008 170.483 ;
     RECT  190.224 170.245 190.248 170.483 ;
     RECT  131.472 170.389 132.312 170.531 ;
     RECT  153.6 170.437 154.44 170.579 ;
     RECT  132 170.531 132.312 170.677 ;
     RECT  132 170.677 132.84 170.819 ;
     RECT  183.216 170.435 183.336 170.965 ;
     RECT  146.976 170.437 147 171.011 ;
     RECT  150.192 169.379 150.744 171.059 ;
     RECT  195.024 169.909 195.288 171.059 ;
     RECT  144.48 170.195 144.936 171.301 ;
     RECT  148.2 169.189 148.632 171.445 ;
     RECT  139.632 165.013 139.656 171.541 ;
     RECT  191.4 169.477 191.832 171.541 ;
     RECT  144.336 171.301 144.936 171.587 ;
     RECT  179.04 169.907 179.064 171.635 ;
     RECT  167.28 170.917 167.304 172.115 ;
     RECT  139.056 171.541 139.656 172.117 ;
     RECT  130.56 171.829 130.584 172.163 ;
     RECT  139.056 172.117 139.704 172.163 ;
     RECT  191.4 171.541 192.072 172.163 ;
     RECT  132 170.819 132.312 172.357 ;
     RECT  183.216 170.965 183.624 172.595 ;
     RECT  142.08 170.003 143.112 172.597 ;
     RECT  141.36 172.597 143.112 172.643 ;
     RECT  137.4 169.955 137.712 172.645 ;
     RECT  144.48 171.587 144.936 172.645 ;
     RECT  195.024 171.059 195.048 172.645 ;
     RECT  168.72 170.099 170.112 172.739 ;
     RECT  139.632 172.163 139.704 172.883 ;
     RECT  200.064 171.541 200.088 172.933 ;
     RECT  200.064 172.933 200.328 172.979 ;
     RECT  173.808 171.925 173.832 172.981 ;
     RECT  175.2 170.149 175.896 172.981 ;
     RECT  144.432 172.645 144.936 173.171 ;
     RECT  163.296 170.437 163.32 173.171 ;
     RECT  180.6 169.859 180.912 173.173 ;
     RECT  191.4 172.163 191.712 173.221 ;
     RECT  196.8 169.715 197.112 173.221 ;
     RECT  144.48 173.171 144.936 173.267 ;
     RECT  184.704 173.173 184.728 173.269 ;
     RECT  186 163.667 186.312 173.269 ;
     RECT  141.36 172.643 141.384 173.315 ;
     RECT  173.808 172.981 175.896 173.315 ;
     RECT  146.88 172.117 146.904 173.651 ;
     RECT  152.304 172.645 152.328 173.651 ;
     RECT  194.736 172.645 195.048 173.651 ;
     RECT  132 172.357 132.552 173.699 ;
     RECT  137.4 172.645 137.832 173.749 ;
     RECT  144.912 173.267 144.936 173.891 ;
     RECT  190.944 173.221 191.712 173.891 ;
     RECT  184.704 173.269 186.312 173.939 ;
     RECT  166.848 172.597 166.872 174.037 ;
     RECT  180.6 173.173 181.8 174.179 ;
     RECT  174.432 173.315 175.896 174.227 ;
     RECT  153.6 170.579 153.912 174.229 ;
     RECT  196.704 173.221 197.112 174.371 ;
     RECT  166.848 174.037 167.496 174.373 ;
     RECT  188.496 168.805 188.52 174.373 ;
     RECT  175.2 174.227 175.896 174.467 ;
     RECT  188.496 174.373 189.288 174.467 ;
     RECT  141.552 174.085 141.576 174.611 ;
     RECT  183.216 172.595 183.24 174.659 ;
     RECT  136.368 171.541 136.392 174.757 ;
     RECT  137.4 173.749 138.552 174.757 ;
     RECT  150.72 171.059 150.744 174.757 ;
     RECT  166.704 174.373 167.496 175.043 ;
     RECT  176.976 170.051 177 175.043 ;
     RECT  184.704 173.939 184.728 175.043 ;
     RECT  148.2 171.445 148.68 175.045 ;
     RECT  136.368 174.757 138.552 175.283 ;
     RECT  142.8 172.643 143.112 175.525 ;
     RECT  150.48 174.757 150.744 175.525 ;
     RECT  136.8 175.283 138.552 175.571 ;
     RECT  150.48 175.525 151.512 175.571 ;
     RECT  153.36 174.229 153.912 175.571 ;
     RECT  147.984 175.045 148.68 175.667 ;
     RECT  157.824 174.517 157.848 175.813 ;
     RECT  136.8 175.571 137.832 175.859 ;
     RECT  157.584 175.813 157.848 175.859 ;
     RECT  189.264 174.467 189.288 175.859 ;
     RECT  151.488 175.571 151.512 175.909 ;
     RECT  166.848 175.043 167.496 176.099 ;
     RECT  167.424 176.099 167.496 176.195 ;
     RECT  142.8 175.525 143.688 176.243 ;
     RECT  141.504 174.949 141.528 176.293 ;
     RECT  142.8 176.243 143.112 176.293 ;
     RECT  141.504 176.293 143.112 176.339 ;
     RECT  148.2 175.667 148.68 176.677 ;
     RECT  150.48 175.571 150.504 176.723 ;
     RECT  151.488 175.909 152.184 176.723 ;
     RECT  141.6 176.339 143.112 177.011 ;
     RECT  135.312 175.813 135.336 177.251 ;
     RECT  141.6 177.011 141.624 177.875 ;
     RECT  137.4 175.859 137.832 178.259 ;
     RECT  135.36 177.829 135.384 178.643 ;
     RECT  148.2 176.677 148.824 178.787 ;
     RECT  133.392 178.357 133.416 179.027 ;
     RECT  167.424 176.195 167.448 179.123 ;
     RECT  183.312 174.949 183.336 179.413 ;
     RECT  183.216 179.413 183.336 179.459 ;
     RECT  153.6 175.571 153.912 179.461 ;
     RECT  156.144 173.029 156.168 179.509 ;
     RECT  155.856 179.509 156.168 179.555 ;
     RECT  148.2 178.787 148.776 179.843 ;
     RECT  152.64 179.461 153.912 179.843 ;
     RECT  157.584 175.859 157.608 180.179 ;
     RECT  200.304 172.979 200.328 180.995 ;
     RECT  155.856 179.555 155.88 181.765 ;
     RECT  159 168.851 159.312 181.765 ;
     RECT  145.968 181.237 145.992 182.339 ;
     RECT  155.856 181.765 156.168 182.435 ;
     RECT  164.4 170.389 165.576 182.435 ;
     RECT  139.632 172.883 139.656 182.483 ;
     RECT  250.8 2.151 251.112 182.581 ;
     RECT  148.2 179.843 148.68 182.627 ;
     RECT  156.144 182.435 156.168 182.723 ;
     RECT  142.8 177.011 143.112 182.869 ;
     RECT  162.864 179.509 162.888 182.917 ;
     RECT  162.72 182.917 162.888 182.963 ;
     RECT  151.488 176.723 151.512 182.965 ;
     RECT  142.464 182.869 143.112 183.683 ;
     RECT  144.432 176.917 144.456 183.829 ;
     RECT  144.336 183.829 144.456 183.875 ;
     RECT  151.488 182.965 152.328 184.211 ;
     RECT  144.336 183.875 144.36 185.221 ;
     RECT  145.92 183.253 145.944 185.267 ;
     RECT  144.336 185.221 144.84 185.507 ;
     RECT  321 2.151 321.312 185.749 ;
     RECT  151.488 184.211 151.512 185.843 ;
     RECT  142.8 183.683 143.112 185.941 ;
     RECT  321 185.749 322.056 186.131 ;
     RECT  146.064 185.461 146.088 186.325 ;
     RECT  149.904 182.725 149.928 186.371 ;
     RECT  142.656 185.941 143.112 186.419 ;
     RECT  144.816 185.507 144.84 186.419 ;
     RECT  323.184 185.749 323.208 186.659 ;
     RECT  318.48 184.357 318.504 186.947 ;
     RECT  146.064 186.325 146.472 186.995 ;
     RECT  146.064 186.995 146.376 187.187 ;
     RECT  195.024 173.651 195.048 187.571 ;
     RECT  248.784 180.997 248.808 187.717 ;
     RECT  248.784 187.717 249 187.763 ;
     RECT  183.216 179.459 183.24 187.859 ;
     RECT  192.768 174.901 192.792 188.053 ;
     RECT  313.632 187.333 313.656 188.723 ;
     RECT  151.584 186.901 151.608 188.963 ;
     RECT  168.912 172.739 170.112 189.299 ;
     RECT  323.424 188.629 323.448 189.589 ;
     RECT  323.424 189.589 323.736 189.635 ;
     RECT  168.96 189.299 170.112 189.875 ;
     RECT  146.064 187.187 146.088 190.021 ;
     RECT  146.064 190.021 146.184 190.067 ;
     RECT  318.576 188.773 318.6 190.309 ;
     RECT  136.32 186.661 136.344 190.357 ;
     RECT  317.808 190.309 318.6 190.451 ;
     RECT  136.128 190.357 136.344 190.499 ;
     RECT  323.712 189.635 323.736 190.931 ;
     RECT  159 181.765 159.432 191.267 ;
     RECT  321 186.131 321.312 191.269 ;
     RECT  308.4 191.173 308.424 191.315 ;
     RECT  315.6 2.151 315.912 191.365 ;
     RECT  317.808 190.451 317.832 191.411 ;
     RECT  321 191.269 321.432 191.411 ;
     RECT  312.624 191.317 312.648 191.413 ;
     RECT  132 173.699 132.312 191.461 ;
     RECT  142.8 186.419 143.112 191.461 ;
     RECT  311.616 191.413 312.648 191.507 ;
     RECT  324.24 191.365 324.264 191.507 ;
     RECT  310.2 2.151 310.512 191.509 ;
     RECT  311.616 191.507 312.552 191.509 ;
     RECT  160.704 182.293 160.728 191.555 ;
     RECT  310.2 191.509 312.552 191.555 ;
     RECT  142.704 191.461 143.112 191.891 ;
     RECT  136.128 190.499 136.152 192.035 ;
     RECT  315.504 191.365 315.912 192.179 ;
     RECT  312.528 191.555 312.552 192.323 ;
     RECT  321 191.411 321.312 192.565 ;
     RECT  310.2 191.555 311.208 192.613 ;
     RECT  146.16 190.067 146.184 192.707 ;
     RECT  155.184 191.461 155.208 192.707 ;
     RECT  309.984 192.613 311.208 192.901 ;
     RECT  319.152 192.037 319.176 192.947 ;
     RECT  320.64 192.565 321.312 193.093 ;
     RECT  308.352 192.853 308.376 193.379 ;
     RECT  140.448 190.885 140.472 193.381 ;
     RECT  140.448 193.381 140.664 193.523 ;
     RECT  312.912 192.613 312.936 193.669 ;
     RECT  314.448 193.189 314.472 193.669 ;
     RECT  309.792 192.901 311.208 193.763 ;
     RECT  248.976 187.763 249 193.859 ;
     RECT  250.464 182.581 251.112 193.859 ;
     RECT  133.824 192.037 133.848 194.051 ;
     RECT  307.968 193.669 307.992 194.099 ;
     RECT  312.912 193.669 314.472 194.341 ;
     RECT  149.904 192.949 149.928 194.387 ;
     RECT  312.384 194.341 314.472 194.387 ;
     RECT  313.488 194.387 314.472 194.531 ;
     RECT  318.912 193.525 318.936 194.629 ;
     RECT  320.544 193.093 321.312 194.629 ;
     RECT  132 191.461 132.6 194.773 ;
     RECT  136.272 194.341 136.296 194.963 ;
     RECT  312.384 194.387 312.408 194.963 ;
     RECT  126.6 2.151 126.912 195.253 ;
     RECT  134.928 193.765 134.952 195.349 ;
     RECT  134.544 195.349 134.952 195.539 ;
     RECT  140.64 193.523 140.664 196.021 ;
     RECT  140.256 196.021 140.664 196.067 ;
     RECT  134.544 195.539 134.568 196.115 ;
     RECT  318.912 194.629 321.312 196.115 ;
     RECT  309.792 193.763 310.92 196.261 ;
     RECT  132 194.773 132.648 196.357 ;
     RECT  313.488 194.531 313.992 196.453 ;
     RECT  132 196.357 132.744 196.499 ;
     RECT  309.696 196.261 310.92 196.549 ;
     RECT  321 196.115 321.312 196.597 ;
     RECT  151.92 190.885 151.944 196.691 ;
     RECT  313.488 196.453 314.04 196.739 ;
     RECT  318.912 196.115 319.608 196.979 ;
     RECT  162.72 182.963 162.744 197.171 ;
     RECT  309.216 196.549 310.92 197.173 ;
     RECT  321 196.597 321.432 197.219 ;
     RECT  94.2 2.151 94.512 197.461 ;
     RECT  132 196.499 132.6 197.461 ;
     RECT  313.968 196.739 314.04 197.749 ;
     RECT  309.216 197.173 311.208 197.941 ;
     RECT  309.216 197.941 311.736 198.085 ;
     RECT  316.944 196.501 316.968 198.085 ;
     RECT  131.04 197.461 132.6 198.229 ;
     RECT  315.6 192.179 315.912 198.277 ;
     RECT  309.12 198.085 311.736 198.373 ;
     RECT  318.912 196.979 319.224 198.419 ;
     RECT  323.088 198.085 323.112 198.419 ;
     RECT  93.504 197.461 94.512 198.515 ;
     RECT  94.2 198.515 94.512 198.517 ;
     RECT  308.16 198.373 311.736 198.517 ;
     RECT  316.944 198.085 317.544 198.517 ;
     RECT  308.16 198.517 312.36 198.803 ;
     RECT  316.896 198.517 317.544 198.901 ;
     RECT  318.912 198.419 318.936 198.901 ;
     RECT  313.824 197.749 314.04 199.045 ;
     RECT  315.504 198.277 315.912 199.045 ;
     RECT  308.16 198.803 310.512 199.091 ;
     RECT  316.896 198.901 318.936 199.187 ;
     RECT  311.712 198.803 312.36 199.189 ;
     RECT  311.712 199.189 312.552 199.283 ;
     RECT  313.824 199.045 315.912 199.477 ;
     RECT  316.896 199.187 316.968 199.477 ;
     RECT  131.04 198.229 133.416 199.523 ;
     RECT  126.24 195.253 126.912 199.571 ;
     RECT  115.8 2.151 116.112 199.573 ;
     RECT  131.04 199.523 132.6 199.619 ;
     RECT  313.824 199.477 316.968 199.861 ;
     RECT  191.4 173.891 191.712 199.909 ;
     RECT  192.768 188.053 193.512 199.909 ;
     RECT  83.4 2.151 83.712 200.005 ;
     RECT  94.2 198.517 94.68 200.005 ;
     RECT  115.8 199.573 116.232 200.005 ;
     RECT  308.832 199.091 310.512 200.195 ;
     RECT  312.528 199.283 312.552 200.195 ;
     RECT  105 2.151 105.312 200.197 ;
     RECT  93.456 200.005 94.68 200.243 ;
     RECT  137.4 178.259 137.712 200.293 ;
     RECT  131.04 199.619 132.312 200.387 ;
     RECT  96.864 200.245 96.888 200.435 ;
     RECT  313.776 199.861 316.968 200.675 ;
     RECT  318.48 199.187 318.936 200.675 ;
     RECT  182.352 199.861 182.376 200.723 ;
     RECT  83.184 200.005 83.712 200.819 ;
     RECT  101.472 199.573 101.496 201.059 ;
     RECT  115.104 200.005 116.232 201.059 ;
     RECT  191.4 199.909 193.512 201.059 ;
     RECT  136.416 200.293 137.712 201.107 ;
     RECT  309.216 200.195 310.512 201.203 ;
     RECT  321 197.219 321.312 201.205 ;
     RECT  323.232 198.901 323.256 201.205 ;
     RECT  119.04 201.253 119.064 201.443 ;
     RECT  313.776 200.675 315.912 201.827 ;
     RECT  321 201.205 323.256 201.827 ;
     RECT  93.456 200.243 94.512 201.875 ;
     RECT  115.104 201.059 116.112 201.875 ;
     RECT  105 200.197 106.008 202.019 ;
     RECT  321 201.827 322.296 202.019 ;
     RECT  99.6 2.151 99.912 202.021 ;
     RECT  318.912 200.675 318.936 202.117 ;
     RECT  313.776 201.827 313.8 202.355 ;
     RECT  101.808 201.781 101.832 202.451 ;
     RECT  316.896 200.675 316.968 202.451 ;
     RECT  316.944 202.451 316.968 202.595 ;
     RECT  91.152 202.309 91.176 202.789 ;
     RECT  324.864 202.693 324.888 202.789 ;
     RECT  91.008 202.789 91.176 202.835 ;
     RECT  323.28 202.165 323.304 202.885 ;
     RECT  324.336 202.789 324.888 202.885 ;
     RECT  91.008 202.835 91.032 202.933 ;
     RECT  113.568 200.005 113.592 202.979 ;
     RECT  129.84 201.733 129.864 202.979 ;
     RECT  318.912 202.117 319.224 202.979 ;
     RECT  323.28 202.885 324.888 203.029 ;
     RECT  323.136 203.029 324.888 203.075 ;
     RECT  308.16 202.837 308.184 203.173 ;
     RECT  90.624 202.933 91.032 203.219 ;
     RECT  308.16 203.173 308.328 203.219 ;
     RECT  105 202.019 105.48 203.221 ;
     RECT  319.2 202.979 319.224 203.267 ;
     RECT  99.6 202.021 100.392 203.269 ;
     RECT  115.8 201.875 116.112 203.269 ;
     RECT  324.24 203.075 324.888 203.365 ;
     RECT  324.24 203.365 325.176 203.507 ;
     RECT  91.008 203.219 91.032 203.555 ;
     RECT  105 203.221 106.056 203.699 ;
     RECT  324.24 203.507 324.888 203.939 ;
     RECT  321 202.019 321.312 204.037 ;
     RECT  99.6 203.269 100.488 204.083 ;
     RECT  115.8 203.269 116.664 204.083 ;
     RECT  324.864 203.939 324.888 204.083 ;
     RECT  320.688 204.037 321.312 204.563 ;
     RECT  119.376 203.749 119.4 204.659 ;
     RECT  128.304 199.621 128.328 204.659 ;
     RECT  113.952 203.461 113.976 204.755 ;
     RECT  310.2 201.203 310.512 204.997 ;
     RECT  303.072 203.077 303.096 205.043 ;
     RECT  314.832 201.827 315.912 205.043 ;
     RECT  265.104 187.717 265.128 205.235 ;
     RECT  142.8 191.891 143.112 205.237 ;
     RECT  148.2 182.627 148.632 205.811 ;
     RECT  323.136 203.075 323.16 206.387 ;
     RECT  318.864 206.293 318.888 206.869 ;
     RECT  318.576 206.869 318.888 207.491 ;
     RECT  318.576 207.491 318.6 207.539 ;
     RECT  308.304 203.219 308.328 209.219 ;
     RECT  309.84 204.997 310.512 209.555 ;
     RECT  193.488 201.059 193.512 217.235 ;
     RECT  264.816 205.285 264.84 217.235 ;
     RECT  124.416 199.573 124.44 218.339 ;
     RECT  142.8 205.237 143.928 218.821 ;
     RECT  142.8 218.821 144.168 218.867 ;
     RECT  144.144 218.867 144.168 225.203 ;
     RECT  140.256 196.067 140.28 226.355 ;
     RECT  151.584 205.909 151.608 229.907 ;
     RECT  167.328 189.925 167.352 229.955 ;
     RECT  169.8 189.875 170.112 230.149 ;
     RECT  222.144 217.429 222.168 238.883 ;
     RECT  207.6 2.151 207.912 239.029 ;
     RECT  67.2 2.151 67.512 242.677 ;
     RECT  145.584 226.309 145.608 249.683 ;
     RECT  169.8 230.149 170.52 251.411 ;
     RECT  207.6 239.029 208.872 251.411 ;
     RECT  207.6 251.411 208.776 261.683 ;
     RECT  166.608 287.797 166.632 305.509 ;
     RECT  167.664 250.069 167.688 305.509 ;
     RECT  166.608 305.509 167.688 305.555 ;
     RECT  67.2 242.677 67.8 319.523 ;
     RECT  166.704 305.555 167.688 322.643 ;
     RECT  167.664 322.643 167.688 361.093 ;
     RECT  166.8 361.093 167.688 361.909 ;
     RECT  166.176 361.909 167.688 361.955 ;
     RECT  167.664 361.955 167.688 362.485 ;
     RECT  168.72 261.973 168.744 362.485 ;
     RECT  167.664 362.485 168.744 362.531 ;
     RECT  166.176 361.955 166.2 366.227 ;
     RECT  167.808 362.531 168.744 367.139 ;
     RECT  168.72 367.139 168.744 368.773 ;
     RECT  169.8 251.411 170.112 368.773 ;
     RECT  2.4 2.151 2.712 369.369 ;
     RECT  7.8 2.151 8.112 369.369 ;
     RECT  13.2 2.151 13.512 369.369 ;
     RECT  18.6 2.151 18.912 369.369 ;
     RECT  24 2.151 24.312 369.369 ;
     RECT  29.4 2.151 29.712 369.369 ;
     RECT  34.8 2.151 35.112 369.369 ;
     RECT  40.2 2.151 40.512 369.369 ;
     RECT  45.6 2.151 45.912 369.369 ;
     RECT  51 2.151 51.312 369.369 ;
     RECT  56.4 2.151 56.712 369.369 ;
     RECT  61.8 2.151 62.112 369.369 ;
     RECT  67.2 319.523 67.512 369.369 ;
     RECT  72.6 2.151 72.912 369.369 ;
     RECT  78 2.151 78.312 369.369 ;
     RECT  83.4 200.819 83.712 369.369 ;
     RECT  88.8 2.151 89.112 369.369 ;
     RECT  94.2 201.875 94.512 369.369 ;
     RECT  99.6 204.083 99.912 369.369 ;
     RECT  105 203.699 105.312 369.369 ;
     RECT  110.4 2.151 110.712 369.369 ;
     RECT  115.8 204.083 116.112 369.369 ;
     RECT  121.2 2.151 121.512 369.369 ;
     RECT  126.6 199.571 126.912 369.369 ;
     RECT  132 200.387 132.312 369.369 ;
     RECT  137.4 201.107 137.712 369.369 ;
     RECT  142.8 218.867 143.112 369.369 ;
     RECT  148.2 205.811 148.512 369.369 ;
     RECT  153.6 179.843 153.912 369.369 ;
     RECT  159 191.267 159.312 369.369 ;
     RECT  164.4 182.435 164.712 369.369 ;
     RECT  168.72 368.773 170.112 369.369 ;
     RECT  175.2 174.467 175.512 369.369 ;
     RECT  180.6 174.179 180.912 369.369 ;
     RECT  186 173.939 186.312 369.369 ;
     RECT  191.4 201.059 191.712 369.369 ;
     RECT  196.8 174.371 197.112 369.369 ;
     RECT  202.2 2.151 202.512 369.369 ;
     RECT  207.6 261.683 207.912 369.369 ;
     RECT  213 2.151 213.312 369.369 ;
     RECT  218.4 2.151 218.712 369.369 ;
     RECT  223.8 2.151 224.112 369.369 ;
     RECT  229.2 2.151 229.512 369.369 ;
     RECT  234.6 2.151 234.912 369.369 ;
     RECT  240 2.151 240.312 369.369 ;
     RECT  245.4 2.151 245.712 369.369 ;
     RECT  250.8 193.859 251.112 369.369 ;
     RECT  256.2 2.151 256.512 369.369 ;
     RECT  261.6 2.151 261.912 369.369 ;
     RECT  267 2.151 267.312 369.369 ;
     RECT  272.4 2.151 272.712 369.369 ;
     RECT  277.8 2.151 278.112 369.369 ;
     RECT  283.2 2.151 283.512 369.369 ;
     RECT  288.6 2.151 288.912 369.369 ;
     RECT  294 2.151 294.312 369.369 ;
     RECT  299.4 2.151 299.712 369.369 ;
     RECT  304.8 2.151 305.112 369.369 ;
     RECT  310.2 209.555 310.512 369.369 ;
     RECT  315.6 205.043 315.912 369.369 ;
     RECT  321 204.563 321.312 369.369 ;
     RECT  2.4 369.369 2.52 369.383 ;
     RECT  7.8 369.369 7.92 369.383 ;
     RECT  13.2 369.369 13.32 369.383 ;
     RECT  18.6 369.369 18.72 369.383 ;
     RECT  24 369.369 24.12 369.383 ;
     RECT  29.4 369.369 29.52 369.383 ;
     RECT  34.8 369.369 34.92 369.383 ;
     RECT  40.2 369.369 40.32 369.383 ;
     RECT  45.6 369.369 45.72 369.383 ;
     RECT  51 369.369 51.12 369.383 ;
     RECT  56.4 369.369 56.52 369.383 ;
     RECT  61.8 369.369 61.92 369.383 ;
     RECT  67.2 369.369 67.32 369.383 ;
     RECT  72.6 369.369 72.72 369.383 ;
     RECT  78 369.369 78.12 369.383 ;
     RECT  83.4 369.369 83.52 369.383 ;
     RECT  88.8 369.369 88.92 369.383 ;
     RECT  94.2 369.369 94.32 369.383 ;
     RECT  99.6 369.369 99.72 369.383 ;
     RECT  105 369.369 105.12 369.383 ;
     RECT  110.4 369.369 110.52 369.383 ;
     RECT  115.8 369.369 115.92 369.383 ;
     RECT  121.2 369.369 121.32 369.383 ;
     RECT  126.6 369.369 126.72 369.383 ;
     RECT  132 369.369 132.12 369.383 ;
     RECT  137.4 369.369 137.52 369.383 ;
     RECT  142.8 369.369 142.92 369.383 ;
     RECT  148.2 369.369 148.32 369.383 ;
     RECT  153.6 369.369 153.72 369.383 ;
     RECT  159 369.369 159.12 369.383 ;
     RECT  164.4 369.369 164.52 369.383 ;
     RECT  168.72 369.369 169.92 369.383 ;
     RECT  175.2 369.369 175.32 369.383 ;
     RECT  180.6 369.369 180.72 369.383 ;
     RECT  186 369.369 186.12 369.383 ;
     RECT  191.4 369.369 191.52 369.383 ;
     RECT  196.8 369.369 196.92 369.383 ;
     RECT  202.2 369.369 202.32 369.383 ;
     RECT  207.6 369.369 207.72 369.383 ;
     RECT  213 369.369 213.12 369.383 ;
     RECT  218.4 369.369 218.52 369.383 ;
     RECT  223.8 369.369 223.92 369.383 ;
     RECT  229.2 369.369 229.32 369.383 ;
     RECT  234.6 369.369 234.72 369.383 ;
     RECT  240 369.369 240.12 369.383 ;
     RECT  245.4 369.369 245.52 369.383 ;
     RECT  250.8 369.369 250.92 369.383 ;
     RECT  256.2 369.369 256.32 369.383 ;
     RECT  261.6 369.369 261.72 369.383 ;
     RECT  267 369.369 267.12 369.383 ;
     RECT  272.4 369.369 272.52 369.383 ;
     RECT  277.8 369.369 277.92 369.383 ;
     RECT  283.2 369.369 283.32 369.383 ;
     RECT  288.6 369.369 288.72 369.383 ;
     RECT  294 369.369 294.12 369.383 ;
     RECT  299.4 369.369 299.52 369.383 ;
     RECT  304.8 369.369 304.92 369.383 ;
     RECT  310.2 369.369 310.32 369.383 ;
     RECT  315.6 369.369 315.72 369.383 ;
     RECT  321 369.369 321.12 369.383 ;
     RECT  168.72 369.383 169.128 371.472 ;
  END
END ot_qwen_kvc_decode_map_pc
END LIBRARY
